VERSION 5.8 ;
BUSBITCHARS "[]" ;
DIVIDERCHAR "/" ;
UNITS
    DATABASE MICRONS 1000 ;
END UNITS

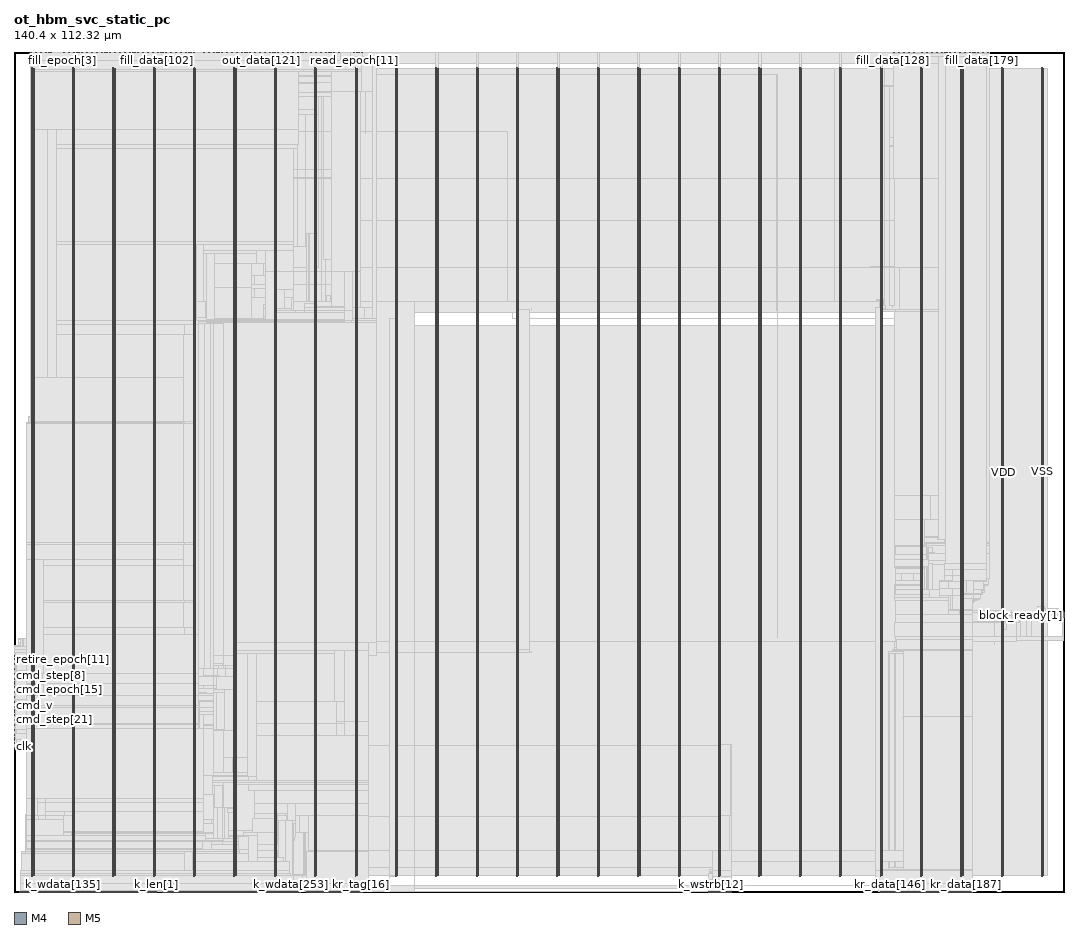
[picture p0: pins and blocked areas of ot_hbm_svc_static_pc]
MACRO ot_hbm_svc_static_pc
  FOREIGN ot_hbm_svc_static_pc 0 0 ;
  CLASS BLOCK ;
  SIZE 140.4 BY 112.32 ;
  PIN bank_owned[0]
    DIRECTION OUTPUT ;
    USE SIGNAL ;
    PORT
      LAYER M4 ;
        RECT  140.316 36.72 140.4 36.744 ;
    END
  END bank_owned[0]
  PIN bank_owned[1]
    DIRECTION OUTPUT ;
    USE SIGNAL ;
    PORT
      LAYER M4 ;
        RECT  140.316 36.816 140.4 36.84 ;
    END
  END bank_owned[1]
  PIN block_ready[0]
    DIRECTION OUTPUT ;
    USE SIGNAL ;
    PORT
      LAYER M4 ;
        RECT  140.316 36.912 140.4 36.936 ;
    END
  END block_ready[0]
  PIN block_ready[1]
    DIRECTION OUTPUT ;
    USE SIGNAL ;
    PORT
      LAYER M4 ;
        RECT  140.316 37.008 140.4 37.032 ;
    END
  END block_ready[1]
  PIN busy
    DIRECTION OUTPUT ;
    USE SIGNAL ;
    PORT
      LAYER M4 ;
        RECT  140.316 37.104 140.4 37.128 ;
    END
  END busy
  PIN clk
    DIRECTION INPUT ;
    USE SIGNAL ;
    PORT
      LAYER M4 ;
        RECT  0 19.44 0.084 19.464 ;
    END
  END clk
  PIN cmd_addr[0]
    DIRECTION INPUT ;
    USE SIGNAL ;
    PORT
      LAYER M4 ;
        RECT  0 19.536 0.084 19.56 ;
    END
  END cmd_addr[0]
  PIN cmd_addr[10]
    DIRECTION INPUT ;
    USE SIGNAL ;
    PORT
      LAYER M4 ;
        RECT  0 20.496 0.084 20.52 ;
    END
  END cmd_addr[10]
  PIN cmd_addr[11]
    DIRECTION INPUT ;
    USE SIGNAL ;
    PORT
      LAYER M4 ;
        RECT  0 20.592 0.084 20.616 ;
    END
  END cmd_addr[11]
  PIN cmd_addr[12]
    DIRECTION INPUT ;
    USE SIGNAL ;
    PORT
      LAYER M4 ;
        RECT  0 20.688 0.084 20.712 ;
    END
  END cmd_addr[12]
  PIN cmd_addr[13]
    DIRECTION INPUT ;
    USE SIGNAL ;
    PORT
      LAYER M4 ;
        RECT  0 20.784 0.084 20.808 ;
    END
  END cmd_addr[13]
  PIN cmd_addr[14]
    DIRECTION INPUT ;
    USE SIGNAL ;
    PORT
      LAYER M4 ;
        RECT  0 20.88 0.084 20.904 ;
    END
  END cmd_addr[14]
  PIN cmd_addr[15]
    DIRECTION INPUT ;
    USE SIGNAL ;
    PORT
      LAYER M4 ;
        RECT  0 20.976 0.084 21 ;
    END
  END cmd_addr[15]
  PIN cmd_addr[16]
    DIRECTION INPUT ;
    USE SIGNAL ;
    PORT
      LAYER M4 ;
        RECT  0 21.072 0.084 21.096 ;
    END
  END cmd_addr[16]
  PIN cmd_addr[17]
    DIRECTION INPUT ;
    USE SIGNAL ;
    PORT
      LAYER M4 ;
        RECT  0 21.168 0.084 21.192 ;
    END
  END cmd_addr[17]
  PIN cmd_addr[18]
    DIRECTION INPUT ;
    USE SIGNAL ;
    PORT
      LAYER M4 ;
        RECT  0 21.264 0.084 21.288 ;
    END
  END cmd_addr[18]
  PIN cmd_addr[19]
    DIRECTION INPUT ;
    USE SIGNAL ;
    PORT
      LAYER M4 ;
        RECT  0 21.36 0.084 21.384 ;
    END
  END cmd_addr[19]
  PIN cmd_addr[1]
    DIRECTION INPUT ;
    USE SIGNAL ;
    PORT
      LAYER M4 ;
        RECT  0 19.632 0.084 19.656 ;
    END
  END cmd_addr[1]
  PIN cmd_addr[20]
    DIRECTION INPUT ;
    USE SIGNAL ;
    PORT
      LAYER M4 ;
        RECT  0 21.456 0.084 21.48 ;
    END
  END cmd_addr[20]
  PIN cmd_addr[21]
    DIRECTION INPUT ;
    USE SIGNAL ;
    PORT
      LAYER M4 ;
        RECT  0 21.552 0.084 21.576 ;
    END
  END cmd_addr[21]
  PIN cmd_addr[22]
    DIRECTION INPUT ;
    USE SIGNAL ;
    PORT
      LAYER M4 ;
        RECT  0 21.648 0.084 21.672 ;
    END
  END cmd_addr[22]
  PIN cmd_addr[23]
    DIRECTION INPUT ;
    USE SIGNAL ;
    PORT
      LAYER M4 ;
        RECT  0 21.744 0.084 21.768 ;
    END
  END cmd_addr[23]
  PIN cmd_addr[24]
    DIRECTION INPUT ;
    USE SIGNAL ;
    PORT
      LAYER M4 ;
        RECT  0 21.84 0.084 21.864 ;
    END
  END cmd_addr[24]
  PIN cmd_addr[25]
    DIRECTION INPUT ;
    USE SIGNAL ;
    PORT
      LAYER M4 ;
        RECT  0 21.936 0.084 21.96 ;
    END
  END cmd_addr[25]
  PIN cmd_addr[26]
    DIRECTION INPUT ;
    USE SIGNAL ;
    PORT
      LAYER M4 ;
        RECT  0 22.032 0.084 22.056 ;
    END
  END cmd_addr[26]
  PIN cmd_addr[27]
    DIRECTION INPUT ;
    USE SIGNAL ;
    PORT
      LAYER M4 ;
        RECT  0 22.128 0.084 22.152 ;
    END
  END cmd_addr[27]
  PIN cmd_addr[28]
    DIRECTION INPUT ;
    USE SIGNAL ;
    PORT
      LAYER M4 ;
        RECT  0 22.224 0.084 22.248 ;
    END
  END cmd_addr[28]
  PIN cmd_addr[29]
    DIRECTION INPUT ;
    USE SIGNAL ;
    PORT
      LAYER M4 ;
        RECT  0 22.32 0.084 22.344 ;
    END
  END cmd_addr[29]
  PIN cmd_addr[2]
    DIRECTION INPUT ;
    USE SIGNAL ;
    PORT
      LAYER M4 ;
        RECT  0 19.728 0.084 19.752 ;
    END
  END cmd_addr[2]
  PIN cmd_addr[3]
    DIRECTION INPUT ;
    USE SIGNAL ;
    PORT
      LAYER M4 ;
        RECT  0 19.824 0.084 19.848 ;
    END
  END cmd_addr[3]
  PIN cmd_addr[4]
    DIRECTION INPUT ;
    USE SIGNAL ;
    PORT
      LAYER M4 ;
        RECT  0 19.92 0.084 19.944 ;
    END
  END cmd_addr[4]
  PIN cmd_addr[5]
    DIRECTION INPUT ;
    USE SIGNAL ;
    PORT
      LAYER M4 ;
        RECT  0 20.016 0.084 20.04 ;
    END
  END cmd_addr[5]
  PIN cmd_addr[6]
    DIRECTION INPUT ;
    USE SIGNAL ;
    PORT
      LAYER M4 ;
        RECT  0 20.112 0.084 20.136 ;
    END
  END cmd_addr[6]
  PIN cmd_addr[7]
    DIRECTION INPUT ;
    USE SIGNAL ;
    PORT
      LAYER M4 ;
        RECT  0 20.208 0.084 20.232 ;
    END
  END cmd_addr[7]
  PIN cmd_addr[8]
    DIRECTION INPUT ;
    USE SIGNAL ;
    PORT
      LAYER M4 ;
        RECT  0 20.304 0.084 20.328 ;
    END
  END cmd_addr[8]
  PIN cmd_addr[9]
    DIRECTION INPUT ;
    USE SIGNAL ;
    PORT
      LAYER M4 ;
        RECT  0 20.4 0.084 20.424 ;
    END
  END cmd_addr[9]
  PIN cmd_bank
    DIRECTION INPUT ;
    USE SIGNAL ;
    PORT
      LAYER M4 ;
        RECT  0 22.416 0.084 22.44 ;
    END
  END cmd_bank
  PIN cmd_epoch[0]
    DIRECTION INPUT ;
    USE SIGNAL ;
    PORT
      LAYER M4 ;
        RECT  0 25.584 0.084 25.608 ;
    END
  END cmd_epoch[0]
  PIN cmd_epoch[10]
    DIRECTION INPUT ;
    USE SIGNAL ;
    PORT
      LAYER M4 ;
        RECT  0 26.544 0.084 26.568 ;
    END
  END cmd_epoch[10]
  PIN cmd_epoch[11]
    DIRECTION INPUT ;
    USE SIGNAL ;
    PORT
      LAYER M4 ;
        RECT  0 26.64 0.084 26.664 ;
    END
  END cmd_epoch[11]
  PIN cmd_epoch[12]
    DIRECTION INPUT ;
    USE SIGNAL ;
    PORT
      LAYER M4 ;
        RECT  0 26.736 0.084 26.76 ;
    END
  END cmd_epoch[12]
  PIN cmd_epoch[13]
    DIRECTION INPUT ;
    USE SIGNAL ;
    PORT
      LAYER M4 ;
        RECT  0 26.832 0.084 26.856 ;
    END
  END cmd_epoch[13]
  PIN cmd_epoch[14]
    DIRECTION INPUT ;
    USE SIGNAL ;
    PORT
      LAYER M4 ;
        RECT  0 26.928 0.084 26.952 ;
    END
  END cmd_epoch[14]
  PIN cmd_epoch[15]
    DIRECTION INPUT ;
    USE SIGNAL ;
    PORT
      LAYER M4 ;
        RECT  0 27.024 0.084 27.048 ;
    END
  END cmd_epoch[15]
  PIN cmd_epoch[1]
    DIRECTION INPUT ;
    USE SIGNAL ;
    PORT
      LAYER M4 ;
        RECT  0 25.68 0.084 25.704 ;
    END
  END cmd_epoch[1]
  PIN cmd_epoch[2]
    DIRECTION INPUT ;
    USE SIGNAL ;
    PORT
      LAYER M4 ;
        RECT  0 25.776 0.084 25.8 ;
    END
  END cmd_epoch[2]
  PIN cmd_epoch[3]
    DIRECTION INPUT ;
    USE SIGNAL ;
    PORT
      LAYER M4 ;
        RECT  0 25.872 0.084 25.896 ;
    END
  END cmd_epoch[3]
  PIN cmd_epoch[4]
    DIRECTION INPUT ;
    USE SIGNAL ;
    PORT
      LAYER M4 ;
        RECT  0 25.968 0.084 25.992 ;
    END
  END cmd_epoch[4]
  PIN cmd_epoch[5]
    DIRECTION INPUT ;
    USE SIGNAL ;
    PORT
      LAYER M4 ;
        RECT  0 26.064 0.084 26.088 ;
    END
  END cmd_epoch[5]
  PIN cmd_epoch[6]
    DIRECTION INPUT ;
    USE SIGNAL ;
    PORT
      LAYER M4 ;
        RECT  0 26.16 0.084 26.184 ;
    END
  END cmd_epoch[6]
  PIN cmd_epoch[7]
    DIRECTION INPUT ;
    USE SIGNAL ;
    PORT
      LAYER M4 ;
        RECT  0 26.256 0.084 26.28 ;
    END
  END cmd_epoch[7]
  PIN cmd_epoch[8]
    DIRECTION INPUT ;
    USE SIGNAL ;
    PORT
      LAYER M4 ;
        RECT  0 26.352 0.084 26.376 ;
    END
  END cmd_epoch[8]
  PIN cmd_epoch[9]
    DIRECTION INPUT ;
    USE SIGNAL ;
    PORT
      LAYER M4 ;
        RECT  0 26.448 0.084 26.472 ;
    END
  END cmd_epoch[9]
  PIN cmd_step[0]
    DIRECTION INPUT ;
    USE SIGNAL ;
    PORT
      LAYER M4 ;
        RECT  0 27.12 0.084 27.144 ;
    END
  END cmd_step[0]
  PIN cmd_step[10]
    DIRECTION INPUT ;
    USE SIGNAL ;
    PORT
      LAYER M4 ;
        RECT  0 28.08 0.084 28.104 ;
    END
  END cmd_step[10]
  PIN cmd_step[11]
    DIRECTION INPUT ;
    USE SIGNAL ;
    PORT
      LAYER M4 ;
        RECT  0 28.176 0.084 28.2 ;
    END
  END cmd_step[11]
  PIN cmd_step[12]
    DIRECTION INPUT ;
    USE SIGNAL ;
    PORT
      LAYER M4 ;
        RECT  0 28.272 0.084 28.296 ;
    END
  END cmd_step[12]
  PIN cmd_step[13]
    DIRECTION INPUT ;
    USE SIGNAL ;
    PORT
      LAYER M4 ;
        RECT  0 28.368 0.084 28.392 ;
    END
  END cmd_step[13]
  PIN cmd_step[14]
    DIRECTION INPUT ;
    USE SIGNAL ;
    PORT
      LAYER M4 ;
        RECT  0 28.464 0.084 28.488 ;
    END
  END cmd_step[14]
  PIN cmd_step[15]
    DIRECTION INPUT ;
    USE SIGNAL ;
    PORT
      LAYER M4 ;
        RECT  0 28.56 0.084 28.584 ;
    END
  END cmd_step[15]
  PIN cmd_step[16]
    DIRECTION INPUT ;
    USE SIGNAL ;
    PORT
      LAYER M4 ;
        RECT  0 22.512 0.084 22.536 ;
    END
  END cmd_step[16]
  PIN cmd_step[17]
    DIRECTION INPUT ;
    USE SIGNAL ;
    PORT
      LAYER M4 ;
        RECT  0 22.608 0.084 22.632 ;
    END
  END cmd_step[17]
  PIN cmd_step[18]
    DIRECTION INPUT ;
    USE SIGNAL ;
    PORT
      LAYER M4 ;
        RECT  0 22.704 0.084 22.728 ;
    END
  END cmd_step[18]
  PIN cmd_step[19]
    DIRECTION INPUT ;
    USE SIGNAL ;
    PORT
      LAYER M4 ;
        RECT  0 22.8 0.084 22.824 ;
    END
  END cmd_step[19]
  PIN cmd_step[1]
    DIRECTION INPUT ;
    USE SIGNAL ;
    PORT
      LAYER M4 ;
        RECT  0 27.216 0.084 27.24 ;
    END
  END cmd_step[1]
  PIN cmd_step[20]
    DIRECTION INPUT ;
    USE SIGNAL ;
    PORT
      LAYER M4 ;
        RECT  0 22.896 0.084 22.92 ;
    END
  END cmd_step[20]
  PIN cmd_step[21]
    DIRECTION INPUT ;
    USE SIGNAL ;
    PORT
      LAYER M4 ;
        RECT  0 22.992 0.084 23.016 ;
    END
  END cmd_step[21]
  PIN cmd_step[22]
    DIRECTION INPUT ;
    USE SIGNAL ;
    PORT
      LAYER M4 ;
        RECT  0 23.088 0.084 23.112 ;
    END
  END cmd_step[22]
  PIN cmd_step[23]
    DIRECTION INPUT ;
    USE SIGNAL ;
    PORT
      LAYER M4 ;
        RECT  0 23.184 0.084 23.208 ;
    END
  END cmd_step[23]
  PIN cmd_step[24]
    DIRECTION INPUT ;
    USE SIGNAL ;
    PORT
      LAYER M4 ;
        RECT  0 23.28 0.084 23.304 ;
    END
  END cmd_step[24]
  PIN cmd_step[25]
    DIRECTION INPUT ;
    USE SIGNAL ;
    PORT
      LAYER M4 ;
        RECT  0 23.376 0.084 23.4 ;
    END
  END cmd_step[25]
  PIN cmd_step[26]
    DIRECTION INPUT ;
    USE SIGNAL ;
    PORT
      LAYER M4 ;
        RECT  0 23.472 0.084 23.496 ;
    END
  END cmd_step[26]
  PIN cmd_step[27]
    DIRECTION INPUT ;
    USE SIGNAL ;
    PORT
      LAYER M4 ;
        RECT  0 23.568 0.084 23.592 ;
    END
  END cmd_step[27]
  PIN cmd_step[28]
    DIRECTION INPUT ;
    USE SIGNAL ;
    PORT
      LAYER M4 ;
        RECT  0 23.664 0.084 23.688 ;
    END
  END cmd_step[28]
  PIN cmd_step[29]
    DIRECTION INPUT ;
    USE SIGNAL ;
    PORT
      LAYER M4 ;
        RECT  0 23.76 0.084 23.784 ;
    END
  END cmd_step[29]
  PIN cmd_step[2]
    DIRECTION INPUT ;
    USE SIGNAL ;
    PORT
      LAYER M4 ;
        RECT  0 27.312 0.084 27.336 ;
    END
  END cmd_step[2]
  PIN cmd_step[3]
    DIRECTION INPUT ;
    USE SIGNAL ;
    PORT
      LAYER M4 ;
        RECT  0 27.408 0.084 27.432 ;
    END
  END cmd_step[3]
  PIN cmd_step[4]
    DIRECTION INPUT ;
    USE SIGNAL ;
    PORT
      LAYER M4 ;
        RECT  0 27.504 0.084 27.528 ;
    END
  END cmd_step[4]
  PIN cmd_step[5]
    DIRECTION INPUT ;
    USE SIGNAL ;
    PORT
      LAYER M4 ;
        RECT  0 27.6 0.084 27.624 ;
    END
  END cmd_step[5]
  PIN cmd_step[6]
    DIRECTION INPUT ;
    USE SIGNAL ;
    PORT
      LAYER M4 ;
        RECT  0 27.696 0.084 27.72 ;
    END
  END cmd_step[6]
  PIN cmd_step[7]
    DIRECTION INPUT ;
    USE SIGNAL ;
    PORT
      LAYER M4 ;
        RECT  0 27.792 0.084 27.816 ;
    END
  END cmd_step[7]
  PIN cmd_step[8]
    DIRECTION INPUT ;
    USE SIGNAL ;
    PORT
      LAYER M4 ;
        RECT  0 27.888 0.084 27.912 ;
    END
  END cmd_step[8]
  PIN cmd_step[9]
    DIRECTION INPUT ;
    USE SIGNAL ;
    PORT
      LAYER M4 ;
        RECT  0 27.984 0.084 28.008 ;
    END
  END cmd_step[9]
  PIN cmd_v
    DIRECTION INPUT ;
    USE SIGNAL ;
    PORT
      LAYER M4 ;
        RECT  0 23.856 0.084 23.88 ;
    END
  END cmd_v
  PIN cmd_write
    DIRECTION INPUT ;
    USE SIGNAL ;
    PORT
      LAYER M4 ;
        RECT  0 23.952 0.084 23.976 ;
    END
  END cmd_write
  PIN done
    DIRECTION OUTPUT ;
    USE SIGNAL ;
    PORT
      LAYER M4 ;
        RECT  140.316 37.2 140.4 37.224 ;
    END
  END done
  PIN fault
    DIRECTION OUTPUT ;
    USE SIGNAL ;
    PORT
      LAYER M4 ;
        RECT  140.316 37.296 140.4 37.32 ;
    END
  END fault
  PIN fill_bank
    DIRECTION INPUT ;
    USE SIGNAL ;
    PORT
      LAYER M5 ;
        RECT  15.312 112.236 15.336 112.32 ;
    END
  END fill_bank
  PIN fill_data[0]
    DIRECTION INPUT ;
    USE SIGNAL ;
    PORT
      LAYER M5 ;
        RECT  15.408 112.236 15.432 112.32 ;
    END
  END fill_data[0]
  PIN fill_data[100]
    DIRECTION INPUT ;
    USE SIGNAL ;
    PORT
      LAYER M5 ;
        RECT  18.864 112.236 18.888 112.32 ;
    END
  END fill_data[100]
  PIN fill_data[101]
    DIRECTION INPUT ;
    USE SIGNAL ;
    PORT
      LAYER M5 ;
        RECT  18.96 112.236 18.984 112.32 ;
    END
  END fill_data[101]
  PIN fill_data[102]
    DIRECTION INPUT ;
    USE SIGNAL ;
    PORT
      LAYER M5 ;
        RECT  19.056 112.236 19.08 112.32 ;
    END
  END fill_data[102]
  PIN fill_data[103]
    DIRECTION INPUT ;
    USE SIGNAL ;
    PORT
      LAYER M5 ;
        RECT  19.152 112.236 19.176 112.32 ;
    END
  END fill_data[103]
  PIN fill_data[104]
    DIRECTION INPUT ;
    USE SIGNAL ;
    PORT
      LAYER M5 ;
        RECT  19.248 112.236 19.272 112.32 ;
    END
  END fill_data[104]
  PIN fill_data[105]
    DIRECTION INPUT ;
    USE SIGNAL ;
    PORT
      LAYER M5 ;
        RECT  19.344 112.236 19.368 112.32 ;
    END
  END fill_data[105]
  PIN fill_data[106]
    DIRECTION INPUT ;
    USE SIGNAL ;
    PORT
      LAYER M5 ;
        RECT  19.44 112.236 19.464 112.32 ;
    END
  END fill_data[106]
  PIN fill_data[107]
    DIRECTION INPUT ;
    USE SIGNAL ;
    PORT
      LAYER M5 ;
        RECT  19.536 112.236 19.56 112.32 ;
    END
  END fill_data[107]
  PIN fill_data[108]
    DIRECTION INPUT ;
    USE SIGNAL ;
    PORT
      LAYER M5 ;
        RECT  19.632 112.236 19.656 112.32 ;
    END
  END fill_data[108]
  PIN fill_data[109]
    DIRECTION INPUT ;
    USE SIGNAL ;
    PORT
      LAYER M5 ;
        RECT  19.728 112.236 19.752 112.32 ;
    END
  END fill_data[109]
  PIN fill_data[10]
    DIRECTION INPUT ;
    USE SIGNAL ;
    PORT
      LAYER M5 ;
        RECT  16.368 112.236 16.392 112.32 ;
    END
  END fill_data[10]
  PIN fill_data[110]
    DIRECTION INPUT ;
    USE SIGNAL ;
    PORT
      LAYER M5 ;
        RECT  19.824 112.236 19.848 112.32 ;
    END
  END fill_data[110]
  PIN fill_data[111]
    DIRECTION INPUT ;
    USE SIGNAL ;
    PORT
      LAYER M5 ;
        RECT  19.92 112.236 19.944 112.32 ;
    END
  END fill_data[111]
  PIN fill_data[112]
    DIRECTION INPUT ;
    USE SIGNAL ;
    PORT
      LAYER M5 ;
        RECT  20.016 112.236 20.04 112.32 ;
    END
  END fill_data[112]
  PIN fill_data[113]
    DIRECTION INPUT ;
    USE SIGNAL ;
    PORT
      LAYER M5 ;
        RECT  20.112 112.236 20.136 112.32 ;
    END
  END fill_data[113]
  PIN fill_data[114]
    DIRECTION INPUT ;
    USE SIGNAL ;
    PORT
      LAYER M5 ;
        RECT  20.208 112.236 20.232 112.32 ;
    END
  END fill_data[114]
  PIN fill_data[115]
    DIRECTION INPUT ;
    USE SIGNAL ;
    PORT
      LAYER M5 ;
        RECT  20.304 112.236 20.328 112.32 ;
    END
  END fill_data[115]
  PIN fill_data[116]
    DIRECTION INPUT ;
    USE SIGNAL ;
    PORT
      LAYER M5 ;
        RECT  20.4 112.236 20.424 112.32 ;
    END
  END fill_data[116]
  PIN fill_data[117]
    DIRECTION INPUT ;
    USE SIGNAL ;
    PORT
      LAYER M5 ;
        RECT  20.496 112.236 20.52 112.32 ;
    END
  END fill_data[117]
  PIN fill_data[118]
    DIRECTION INPUT ;
    USE SIGNAL ;
    PORT
      LAYER M5 ;
        RECT  20.592 112.236 20.616 112.32 ;
    END
  END fill_data[118]
  PIN fill_data[119]
    DIRECTION INPUT ;
    USE SIGNAL ;
    PORT
      LAYER M5 ;
        RECT  20.688 112.236 20.712 112.32 ;
    END
  END fill_data[119]
  PIN fill_data[11]
    DIRECTION INPUT ;
    USE SIGNAL ;
    PORT
      LAYER M5 ;
        RECT  16.464 112.236 16.488 112.32 ;
    END
  END fill_data[11]
  PIN fill_data[120]
    DIRECTION INPUT ;
    USE SIGNAL ;
    PORT
      LAYER M5 ;
        RECT  20.784 112.236 20.808 112.32 ;
    END
  END fill_data[120]
  PIN fill_data[121]
    DIRECTION INPUT ;
    USE SIGNAL ;
    PORT
      LAYER M5 ;
        RECT  20.88 112.236 20.904 112.32 ;
    END
  END fill_data[121]
  PIN fill_data[122]
    DIRECTION INPUT ;
    USE SIGNAL ;
    PORT
      LAYER M5 ;
        RECT  20.976 112.236 21 112.32 ;
    END
  END fill_data[122]
  PIN fill_data[123]
    DIRECTION INPUT ;
    USE SIGNAL ;
    PORT
      LAYER M5 ;
        RECT  21.072 112.236 21.096 112.32 ;
    END
  END fill_data[123]
  PIN fill_data[124]
    DIRECTION INPUT ;
    USE SIGNAL ;
    PORT
      LAYER M5 ;
        RECT  21.168 112.236 21.192 112.32 ;
    END
  END fill_data[124]
  PIN fill_data[125]
    DIRECTION INPUT ;
    USE SIGNAL ;
    PORT
      LAYER M5 ;
        RECT  21.264 112.236 21.288 112.32 ;
    END
  END fill_data[125]
  PIN fill_data[126]
    DIRECTION INPUT ;
    USE SIGNAL ;
    PORT
      LAYER M5 ;
        RECT  21.36 112.236 21.384 112.32 ;
    END
  END fill_data[126]
  PIN fill_data[127]
    DIRECTION INPUT ;
    USE SIGNAL ;
    PORT
      LAYER M5 ;
        RECT  117.456 112.236 117.48 112.32 ;
    END
  END fill_data[127]
  PIN fill_data[128]
    DIRECTION INPUT ;
    USE SIGNAL ;
    PORT
      LAYER M5 ;
        RECT  117.552 112.236 117.576 112.32 ;
    END
  END fill_data[128]
  PIN fill_data[129]
    DIRECTION INPUT ;
    USE SIGNAL ;
    PORT
      LAYER M5 ;
        RECT  117.648 112.236 117.672 112.32 ;
    END
  END fill_data[129]
  PIN fill_data[12]
    DIRECTION INPUT ;
    USE SIGNAL ;
    PORT
      LAYER M5 ;
        RECT  16.56 112.236 16.584 112.32 ;
    END
  END fill_data[12]
  PIN fill_data[130]
    DIRECTION INPUT ;
    USE SIGNAL ;
    PORT
      LAYER M5 ;
        RECT  117.744 112.236 117.768 112.32 ;
    END
  END fill_data[130]
  PIN fill_data[131]
    DIRECTION INPUT ;
    USE SIGNAL ;
    PORT
      LAYER M5 ;
        RECT  117.84 112.236 117.864 112.32 ;
    END
  END fill_data[131]
  PIN fill_data[132]
    DIRECTION INPUT ;
    USE SIGNAL ;
    PORT
      LAYER M5 ;
        RECT  117.936 112.236 117.96 112.32 ;
    END
  END fill_data[132]
  PIN fill_data[133]
    DIRECTION INPUT ;
    USE SIGNAL ;
    PORT
      LAYER M5 ;
        RECT  118.032 112.236 118.056 112.32 ;
    END
  END fill_data[133]
  PIN fill_data[134]
    DIRECTION INPUT ;
    USE SIGNAL ;
    PORT
      LAYER M5 ;
        RECT  118.128 112.236 118.152 112.32 ;
    END
  END fill_data[134]
  PIN fill_data[135]
    DIRECTION INPUT ;
    USE SIGNAL ;
    PORT
      LAYER M5 ;
        RECT  118.224 112.236 118.248 112.32 ;
    END
  END fill_data[135]
  PIN fill_data[136]
    DIRECTION INPUT ;
    USE SIGNAL ;
    PORT
      LAYER M5 ;
        RECT  118.32 112.236 118.344 112.32 ;
    END
  END fill_data[136]
  PIN fill_data[137]
    DIRECTION INPUT ;
    USE SIGNAL ;
    PORT
      LAYER M5 ;
        RECT  118.416 112.236 118.44 112.32 ;
    END
  END fill_data[137]
  PIN fill_data[138]
    DIRECTION INPUT ;
    USE SIGNAL ;
    PORT
      LAYER M5 ;
        RECT  118.512 112.236 118.536 112.32 ;
    END
  END fill_data[138]
  PIN fill_data[139]
    DIRECTION INPUT ;
    USE SIGNAL ;
    PORT
      LAYER M5 ;
        RECT  118.608 112.236 118.632 112.32 ;
    END
  END fill_data[139]
  PIN fill_data[13]
    DIRECTION INPUT ;
    USE SIGNAL ;
    PORT
      LAYER M5 ;
        RECT  16.656 112.236 16.68 112.32 ;
    END
  END fill_data[13]
  PIN fill_data[140]
    DIRECTION INPUT ;
    USE SIGNAL ;
    PORT
      LAYER M5 ;
        RECT  118.704 112.236 118.728 112.32 ;
    END
  END fill_data[140]
  PIN fill_data[141]
    DIRECTION INPUT ;
    USE SIGNAL ;
    PORT
      LAYER M5 ;
        RECT  118.8 112.236 118.824 112.32 ;
    END
  END fill_data[141]
  PIN fill_data[142]
    DIRECTION INPUT ;
    USE SIGNAL ;
    PORT
      LAYER M5 ;
        RECT  118.896 112.236 118.92 112.32 ;
    END
  END fill_data[142]
  PIN fill_data[143]
    DIRECTION INPUT ;
    USE SIGNAL ;
    PORT
      LAYER M5 ;
        RECT  118.992 112.236 119.016 112.32 ;
    END
  END fill_data[143]
  PIN fill_data[144]
    DIRECTION INPUT ;
    USE SIGNAL ;
    PORT
      LAYER M5 ;
        RECT  119.088 112.236 119.112 112.32 ;
    END
  END fill_data[144]
  PIN fill_data[145]
    DIRECTION INPUT ;
    USE SIGNAL ;
    PORT
      LAYER M5 ;
        RECT  119.184 112.236 119.208 112.32 ;
    END
  END fill_data[145]
  PIN fill_data[146]
    DIRECTION INPUT ;
    USE SIGNAL ;
    PORT
      LAYER M5 ;
        RECT  119.28 112.236 119.304 112.32 ;
    END
  END fill_data[146]
  PIN fill_data[147]
    DIRECTION INPUT ;
    USE SIGNAL ;
    PORT
      LAYER M5 ;
        RECT  119.376 112.236 119.4 112.32 ;
    END
  END fill_data[147]
  PIN fill_data[148]
    DIRECTION INPUT ;
    USE SIGNAL ;
    PORT
      LAYER M5 ;
        RECT  119.472 112.236 119.496 112.32 ;
    END
  END fill_data[148]
  PIN fill_data[149]
    DIRECTION INPUT ;
    USE SIGNAL ;
    PORT
      LAYER M5 ;
        RECT  119.568 112.236 119.592 112.32 ;
    END
  END fill_data[149]
  PIN fill_data[14]
    DIRECTION INPUT ;
    USE SIGNAL ;
    PORT
      LAYER M5 ;
        RECT  16.752 112.236 16.776 112.32 ;
    END
  END fill_data[14]
  PIN fill_data[150]
    DIRECTION INPUT ;
    USE SIGNAL ;
    PORT
      LAYER M5 ;
        RECT  119.664 112.236 119.688 112.32 ;
    END
  END fill_data[150]
  PIN fill_data[151]
    DIRECTION INPUT ;
    USE SIGNAL ;
    PORT
      LAYER M5 ;
        RECT  119.76 112.236 119.784 112.32 ;
    END
  END fill_data[151]
  PIN fill_data[152]
    DIRECTION INPUT ;
    USE SIGNAL ;
    PORT
      LAYER M5 ;
        RECT  119.856 112.236 119.88 112.32 ;
    END
  END fill_data[152]
  PIN fill_data[153]
    DIRECTION INPUT ;
    USE SIGNAL ;
    PORT
      LAYER M5 ;
        RECT  119.952 112.236 119.976 112.32 ;
    END
  END fill_data[153]
  PIN fill_data[154]
    DIRECTION INPUT ;
    USE SIGNAL ;
    PORT
      LAYER M5 ;
        RECT  120.048 112.236 120.072 112.32 ;
    END
  END fill_data[154]
  PIN fill_data[155]
    DIRECTION INPUT ;
    USE SIGNAL ;
    PORT
      LAYER M5 ;
        RECT  120.144 112.236 120.168 112.32 ;
    END
  END fill_data[155]
  PIN fill_data[156]
    DIRECTION INPUT ;
    USE SIGNAL ;
    PORT
      LAYER M5 ;
        RECT  120.24 112.236 120.264 112.32 ;
    END
  END fill_data[156]
  PIN fill_data[157]
    DIRECTION INPUT ;
    USE SIGNAL ;
    PORT
      LAYER M5 ;
        RECT  120.336 112.236 120.36 112.32 ;
    END
  END fill_data[157]
  PIN fill_data[158]
    DIRECTION INPUT ;
    USE SIGNAL ;
    PORT
      LAYER M5 ;
        RECT  120.432 112.236 120.456 112.32 ;
    END
  END fill_data[158]
  PIN fill_data[159]
    DIRECTION INPUT ;
    USE SIGNAL ;
    PORT
      LAYER M5 ;
        RECT  127.44 112.236 127.464 112.32 ;
    END
  END fill_data[159]
  PIN fill_data[15]
    DIRECTION INPUT ;
    USE SIGNAL ;
    PORT
      LAYER M5 ;
        RECT  16.848 112.236 16.872 112.32 ;
    END
  END fill_data[15]
  PIN fill_data[160]
    DIRECTION INPUT ;
    USE SIGNAL ;
    PORT
      LAYER M5 ;
        RECT  127.536 112.236 127.56 112.32 ;
    END
  END fill_data[160]
  PIN fill_data[161]
    DIRECTION INPUT ;
    USE SIGNAL ;
    PORT
      LAYER M5 ;
        RECT  127.632 112.236 127.656 112.32 ;
    END
  END fill_data[161]
  PIN fill_data[162]
    DIRECTION INPUT ;
    USE SIGNAL ;
    PORT
      LAYER M5 ;
        RECT  127.728 112.236 127.752 112.32 ;
    END
  END fill_data[162]
  PIN fill_data[163]
    DIRECTION INPUT ;
    USE SIGNAL ;
    PORT
      LAYER M5 ;
        RECT  127.824 112.236 127.848 112.32 ;
    END
  END fill_data[163]
  PIN fill_data[164]
    DIRECTION INPUT ;
    USE SIGNAL ;
    PORT
      LAYER M5 ;
        RECT  127.92 112.236 127.944 112.32 ;
    END
  END fill_data[164]
  PIN fill_data[165]
    DIRECTION INPUT ;
    USE SIGNAL ;
    PORT
      LAYER M5 ;
        RECT  128.016 112.236 128.04 112.32 ;
    END
  END fill_data[165]
  PIN fill_data[166]
    DIRECTION INPUT ;
    USE SIGNAL ;
    PORT
      LAYER M5 ;
        RECT  128.112 112.236 128.136 112.32 ;
    END
  END fill_data[166]
  PIN fill_data[167]
    DIRECTION INPUT ;
    USE SIGNAL ;
    PORT
      LAYER M5 ;
        RECT  128.208 112.236 128.232 112.32 ;
    END
  END fill_data[167]
  PIN fill_data[168]
    DIRECTION INPUT ;
    USE SIGNAL ;
    PORT
      LAYER M5 ;
        RECT  128.304 112.236 128.328 112.32 ;
    END
  END fill_data[168]
  PIN fill_data[169]
    DIRECTION INPUT ;
    USE SIGNAL ;
    PORT
      LAYER M5 ;
        RECT  128.4 112.236 128.424 112.32 ;
    END
  END fill_data[169]
  PIN fill_data[16]
    DIRECTION INPUT ;
    USE SIGNAL ;
    PORT
      LAYER M5 ;
        RECT  16.944 112.236 16.968 112.32 ;
    END
  END fill_data[16]
  PIN fill_data[170]
    DIRECTION INPUT ;
    USE SIGNAL ;
    PORT
      LAYER M5 ;
        RECT  128.496 112.236 128.52 112.32 ;
    END
  END fill_data[170]
  PIN fill_data[171]
    DIRECTION INPUT ;
    USE SIGNAL ;
    PORT
      LAYER M5 ;
        RECT  128.592 112.236 128.616 112.32 ;
    END
  END fill_data[171]
  PIN fill_data[172]
    DIRECTION INPUT ;
    USE SIGNAL ;
    PORT
      LAYER M5 ;
        RECT  128.688 112.236 128.712 112.32 ;
    END
  END fill_data[172]
  PIN fill_data[173]
    DIRECTION INPUT ;
    USE SIGNAL ;
    PORT
      LAYER M5 ;
        RECT  128.784 112.236 128.808 112.32 ;
    END
  END fill_data[173]
  PIN fill_data[174]
    DIRECTION INPUT ;
    USE SIGNAL ;
    PORT
      LAYER M5 ;
        RECT  128.88 112.236 128.904 112.32 ;
    END
  END fill_data[174]
  PIN fill_data[175]
    DIRECTION INPUT ;
    USE SIGNAL ;
    PORT
      LAYER M5 ;
        RECT  128.976 112.236 129 112.32 ;
    END
  END fill_data[175]
  PIN fill_data[176]
    DIRECTION INPUT ;
    USE SIGNAL ;
    PORT
      LAYER M5 ;
        RECT  129.072 112.236 129.096 112.32 ;
    END
  END fill_data[176]
  PIN fill_data[177]
    DIRECTION INPUT ;
    USE SIGNAL ;
    PORT
      LAYER M5 ;
        RECT  129.168 112.236 129.192 112.32 ;
    END
  END fill_data[177]
  PIN fill_data[178]
    DIRECTION INPUT ;
    USE SIGNAL ;
    PORT
      LAYER M5 ;
        RECT  129.264 112.236 129.288 112.32 ;
    END
  END fill_data[178]
  PIN fill_data[179]
    DIRECTION INPUT ;
    USE SIGNAL ;
    PORT
      LAYER M5 ;
        RECT  129.36 112.236 129.384 112.32 ;
    END
  END fill_data[179]
  PIN fill_data[17]
    DIRECTION INPUT ;
    USE SIGNAL ;
    PORT
      LAYER M5 ;
        RECT  17.04 112.236 17.064 112.32 ;
    END
  END fill_data[17]
  PIN fill_data[180]
    DIRECTION INPUT ;
    USE SIGNAL ;
    PORT
      LAYER M5 ;
        RECT  129.456 112.236 129.48 112.32 ;
    END
  END fill_data[180]
  PIN fill_data[181]
    DIRECTION INPUT ;
    USE SIGNAL ;
    PORT
      LAYER M5 ;
        RECT  129.552 112.236 129.576 112.32 ;
    END
  END fill_data[181]
  PIN fill_data[182]
    DIRECTION INPUT ;
    USE SIGNAL ;
    PORT
      LAYER M5 ;
        RECT  129.648 112.236 129.672 112.32 ;
    END
  END fill_data[182]
  PIN fill_data[183]
    DIRECTION INPUT ;
    USE SIGNAL ;
    PORT
      LAYER M5 ;
        RECT  129.744 112.236 129.768 112.32 ;
    END
  END fill_data[183]
  PIN fill_data[184]
    DIRECTION INPUT ;
    USE SIGNAL ;
    PORT
      LAYER M5 ;
        RECT  129.84 112.236 129.864 112.32 ;
    END
  END fill_data[184]
  PIN fill_data[185]
    DIRECTION INPUT ;
    USE SIGNAL ;
    PORT
      LAYER M5 ;
        RECT  129.936 112.236 129.96 112.32 ;
    END
  END fill_data[185]
  PIN fill_data[186]
    DIRECTION INPUT ;
    USE SIGNAL ;
    PORT
      LAYER M5 ;
        RECT  130.032 112.236 130.056 112.32 ;
    END
  END fill_data[186]
  PIN fill_data[187]
    DIRECTION INPUT ;
    USE SIGNAL ;
    PORT
      LAYER M5 ;
        RECT  130.128 112.236 130.152 112.32 ;
    END
  END fill_data[187]
  PIN fill_data[188]
    DIRECTION INPUT ;
    USE SIGNAL ;
    PORT
      LAYER M5 ;
        RECT  130.224 112.236 130.248 112.32 ;
    END
  END fill_data[188]
  PIN fill_data[189]
    DIRECTION INPUT ;
    USE SIGNAL ;
    PORT
      LAYER M5 ;
        RECT  130.32 112.236 130.344 112.32 ;
    END
  END fill_data[189]
  PIN fill_data[18]
    DIRECTION INPUT ;
    USE SIGNAL ;
    PORT
      LAYER M5 ;
        RECT  17.136 112.236 17.16 112.32 ;
    END
  END fill_data[18]
  PIN fill_data[190]
    DIRECTION INPUT ;
    USE SIGNAL ;
    PORT
      LAYER M5 ;
        RECT  130.416 112.236 130.44 112.32 ;
    END
  END fill_data[190]
  PIN fill_data[191]
    DIRECTION INPUT ;
    USE SIGNAL ;
    PORT
      LAYER M5 ;
        RECT  124.368 112.236 124.392 112.32 ;
    END
  END fill_data[191]
  PIN fill_data[192]
    DIRECTION INPUT ;
    USE SIGNAL ;
    PORT
      LAYER M5 ;
        RECT  124.464 112.236 124.488 112.32 ;
    END
  END fill_data[192]
  PIN fill_data[193]
    DIRECTION INPUT ;
    USE SIGNAL ;
    PORT
      LAYER M5 ;
        RECT  124.56 112.236 124.584 112.32 ;
    END
  END fill_data[193]
  PIN fill_data[194]
    DIRECTION INPUT ;
    USE SIGNAL ;
    PORT
      LAYER M5 ;
        RECT  124.656 112.236 124.68 112.32 ;
    END
  END fill_data[194]
  PIN fill_data[195]
    DIRECTION INPUT ;
    USE SIGNAL ;
    PORT
      LAYER M5 ;
        RECT  124.752 112.236 124.776 112.32 ;
    END
  END fill_data[195]
  PIN fill_data[196]
    DIRECTION INPUT ;
    USE SIGNAL ;
    PORT
      LAYER M5 ;
        RECT  124.848 112.236 124.872 112.32 ;
    END
  END fill_data[196]
  PIN fill_data[197]
    DIRECTION INPUT ;
    USE SIGNAL ;
    PORT
      LAYER M5 ;
        RECT  124.944 112.236 124.968 112.32 ;
    END
  END fill_data[197]
  PIN fill_data[198]
    DIRECTION INPUT ;
    USE SIGNAL ;
    PORT
      LAYER M5 ;
        RECT  125.04 112.236 125.064 112.32 ;
    END
  END fill_data[198]
  PIN fill_data[199]
    DIRECTION INPUT ;
    USE SIGNAL ;
    PORT
      LAYER M5 ;
        RECT  125.136 112.236 125.16 112.32 ;
    END
  END fill_data[199]
  PIN fill_data[19]
    DIRECTION INPUT ;
    USE SIGNAL ;
    PORT
      LAYER M5 ;
        RECT  17.232 112.236 17.256 112.32 ;
    END
  END fill_data[19]
  PIN fill_data[1]
    DIRECTION INPUT ;
    USE SIGNAL ;
    PORT
      LAYER M5 ;
        RECT  15.504 112.236 15.528 112.32 ;
    END
  END fill_data[1]
  PIN fill_data[200]
    DIRECTION INPUT ;
    USE SIGNAL ;
    PORT
      LAYER M5 ;
        RECT  125.232 112.236 125.256 112.32 ;
    END
  END fill_data[200]
  PIN fill_data[201]
    DIRECTION INPUT ;
    USE SIGNAL ;
    PORT
      LAYER M5 ;
        RECT  125.328 112.236 125.352 112.32 ;
    END
  END fill_data[201]
  PIN fill_data[202]
    DIRECTION INPUT ;
    USE SIGNAL ;
    PORT
      LAYER M5 ;
        RECT  125.424 112.236 125.448 112.32 ;
    END
  END fill_data[202]
  PIN fill_data[203]
    DIRECTION INPUT ;
    USE SIGNAL ;
    PORT
      LAYER M5 ;
        RECT  125.52 112.236 125.544 112.32 ;
    END
  END fill_data[203]
  PIN fill_data[204]
    DIRECTION INPUT ;
    USE SIGNAL ;
    PORT
      LAYER M5 ;
        RECT  125.616 112.236 125.64 112.32 ;
    END
  END fill_data[204]
  PIN fill_data[205]
    DIRECTION INPUT ;
    USE SIGNAL ;
    PORT
      LAYER M5 ;
        RECT  125.712 112.236 125.736 112.32 ;
    END
  END fill_data[205]
  PIN fill_data[206]
    DIRECTION INPUT ;
    USE SIGNAL ;
    PORT
      LAYER M5 ;
        RECT  125.808 112.236 125.832 112.32 ;
    END
  END fill_data[206]
  PIN fill_data[207]
    DIRECTION INPUT ;
    USE SIGNAL ;
    PORT
      LAYER M5 ;
        RECT  125.904 112.236 125.928 112.32 ;
    END
  END fill_data[207]
  PIN fill_data[208]
    DIRECTION INPUT ;
    USE SIGNAL ;
    PORT
      LAYER M5 ;
        RECT  126 112.236 126.024 112.32 ;
    END
  END fill_data[208]
  PIN fill_data[209]
    DIRECTION INPUT ;
    USE SIGNAL ;
    PORT
      LAYER M5 ;
        RECT  126.096 112.236 126.12 112.32 ;
    END
  END fill_data[209]
  PIN fill_data[20]
    DIRECTION INPUT ;
    USE SIGNAL ;
    PORT
      LAYER M5 ;
        RECT  17.328 112.236 17.352 112.32 ;
    END
  END fill_data[20]
  PIN fill_data[210]
    DIRECTION INPUT ;
    USE SIGNAL ;
    PORT
      LAYER M5 ;
        RECT  126.192 112.236 126.216 112.32 ;
    END
  END fill_data[210]
  PIN fill_data[211]
    DIRECTION INPUT ;
    USE SIGNAL ;
    PORT
      LAYER M5 ;
        RECT  126.288 112.236 126.312 112.32 ;
    END
  END fill_data[211]
  PIN fill_data[212]
    DIRECTION INPUT ;
    USE SIGNAL ;
    PORT
      LAYER M5 ;
        RECT  126.384 112.236 126.408 112.32 ;
    END
  END fill_data[212]
  PIN fill_data[213]
    DIRECTION INPUT ;
    USE SIGNAL ;
    PORT
      LAYER M5 ;
        RECT  126.48 112.236 126.504 112.32 ;
    END
  END fill_data[213]
  PIN fill_data[214]
    DIRECTION INPUT ;
    USE SIGNAL ;
    PORT
      LAYER M5 ;
        RECT  126.576 112.236 126.6 112.32 ;
    END
  END fill_data[214]
  PIN fill_data[215]
    DIRECTION INPUT ;
    USE SIGNAL ;
    PORT
      LAYER M5 ;
        RECT  126.672 112.236 126.696 112.32 ;
    END
  END fill_data[215]
  PIN fill_data[216]
    DIRECTION INPUT ;
    USE SIGNAL ;
    PORT
      LAYER M5 ;
        RECT  126.768 112.236 126.792 112.32 ;
    END
  END fill_data[216]
  PIN fill_data[217]
    DIRECTION INPUT ;
    USE SIGNAL ;
    PORT
      LAYER M5 ;
        RECT  126.864 112.236 126.888 112.32 ;
    END
  END fill_data[217]
  PIN fill_data[218]
    DIRECTION INPUT ;
    USE SIGNAL ;
    PORT
      LAYER M5 ;
        RECT  126.96 112.236 126.984 112.32 ;
    END
  END fill_data[218]
  PIN fill_data[219]
    DIRECTION INPUT ;
    USE SIGNAL ;
    PORT
      LAYER M5 ;
        RECT  127.056 112.236 127.08 112.32 ;
    END
  END fill_data[219]
  PIN fill_data[21]
    DIRECTION INPUT ;
    USE SIGNAL ;
    PORT
      LAYER M5 ;
        RECT  17.424 112.236 17.448 112.32 ;
    END
  END fill_data[21]
  PIN fill_data[220]
    DIRECTION INPUT ;
    USE SIGNAL ;
    PORT
      LAYER M5 ;
        RECT  127.152 112.236 127.176 112.32 ;
    END
  END fill_data[220]
  PIN fill_data[221]
    DIRECTION INPUT ;
    USE SIGNAL ;
    PORT
      LAYER M5 ;
        RECT  127.248 112.236 127.272 112.32 ;
    END
  END fill_data[221]
  PIN fill_data[222]
    DIRECTION INPUT ;
    USE SIGNAL ;
    PORT
      LAYER M5 ;
        RECT  127.344 112.236 127.368 112.32 ;
    END
  END fill_data[222]
  PIN fill_data[223]
    DIRECTION INPUT ;
    USE SIGNAL ;
    PORT
      LAYER M5 ;
        RECT  121.296 112.236 121.32 112.32 ;
    END
  END fill_data[223]
  PIN fill_data[224]
    DIRECTION INPUT ;
    USE SIGNAL ;
    PORT
      LAYER M5 ;
        RECT  121.392 112.236 121.416 112.32 ;
    END
  END fill_data[224]
  PIN fill_data[225]
    DIRECTION INPUT ;
    USE SIGNAL ;
    PORT
      LAYER M5 ;
        RECT  121.488 112.236 121.512 112.32 ;
    END
  END fill_data[225]
  PIN fill_data[226]
    DIRECTION INPUT ;
    USE SIGNAL ;
    PORT
      LAYER M5 ;
        RECT  121.584 112.236 121.608 112.32 ;
    END
  END fill_data[226]
  PIN fill_data[227]
    DIRECTION INPUT ;
    USE SIGNAL ;
    PORT
      LAYER M5 ;
        RECT  121.68 112.236 121.704 112.32 ;
    END
  END fill_data[227]
  PIN fill_data[228]
    DIRECTION INPUT ;
    USE SIGNAL ;
    PORT
      LAYER M5 ;
        RECT  121.776 112.236 121.8 112.32 ;
    END
  END fill_data[228]
  PIN fill_data[229]
    DIRECTION INPUT ;
    USE SIGNAL ;
    PORT
      LAYER M5 ;
        RECT  121.872 112.236 121.896 112.32 ;
    END
  END fill_data[229]
  PIN fill_data[22]
    DIRECTION INPUT ;
    USE SIGNAL ;
    PORT
      LAYER M5 ;
        RECT  17.52 112.236 17.544 112.32 ;
    END
  END fill_data[22]
  PIN fill_data[230]
    DIRECTION INPUT ;
    USE SIGNAL ;
    PORT
      LAYER M5 ;
        RECT  121.968 112.236 121.992 112.32 ;
    END
  END fill_data[230]
  PIN fill_data[231]
    DIRECTION INPUT ;
    USE SIGNAL ;
    PORT
      LAYER M5 ;
        RECT  122.064 112.236 122.088 112.32 ;
    END
  END fill_data[231]
  PIN fill_data[232]
    DIRECTION INPUT ;
    USE SIGNAL ;
    PORT
      LAYER M5 ;
        RECT  122.16 112.236 122.184 112.32 ;
    END
  END fill_data[232]
  PIN fill_data[233]
    DIRECTION INPUT ;
    USE SIGNAL ;
    PORT
      LAYER M5 ;
        RECT  122.256 112.236 122.28 112.32 ;
    END
  END fill_data[233]
  PIN fill_data[234]
    DIRECTION INPUT ;
    USE SIGNAL ;
    PORT
      LAYER M5 ;
        RECT  122.352 112.236 122.376 112.32 ;
    END
  END fill_data[234]
  PIN fill_data[235]
    DIRECTION INPUT ;
    USE SIGNAL ;
    PORT
      LAYER M5 ;
        RECT  122.448 112.236 122.472 112.32 ;
    END
  END fill_data[235]
  PIN fill_data[236]
    DIRECTION INPUT ;
    USE SIGNAL ;
    PORT
      LAYER M5 ;
        RECT  122.544 112.236 122.568 112.32 ;
    END
  END fill_data[236]
  PIN fill_data[237]
    DIRECTION INPUT ;
    USE SIGNAL ;
    PORT
      LAYER M5 ;
        RECT  122.64 112.236 122.664 112.32 ;
    END
  END fill_data[237]
  PIN fill_data[238]
    DIRECTION INPUT ;
    USE SIGNAL ;
    PORT
      LAYER M5 ;
        RECT  122.736 112.236 122.76 112.32 ;
    END
  END fill_data[238]
  PIN fill_data[239]
    DIRECTION INPUT ;
    USE SIGNAL ;
    PORT
      LAYER M5 ;
        RECT  122.832 112.236 122.856 112.32 ;
    END
  END fill_data[239]
  PIN fill_data[23]
    DIRECTION INPUT ;
    USE SIGNAL ;
    PORT
      LAYER M5 ;
        RECT  17.616 112.236 17.64 112.32 ;
    END
  END fill_data[23]
  PIN fill_data[240]
    DIRECTION INPUT ;
    USE SIGNAL ;
    PORT
      LAYER M5 ;
        RECT  122.928 112.236 122.952 112.32 ;
    END
  END fill_data[240]
  PIN fill_data[241]
    DIRECTION INPUT ;
    USE SIGNAL ;
    PORT
      LAYER M5 ;
        RECT  123.024 112.236 123.048 112.32 ;
    END
  END fill_data[241]
  PIN fill_data[242]
    DIRECTION INPUT ;
    USE SIGNAL ;
    PORT
      LAYER M5 ;
        RECT  123.12 112.236 123.144 112.32 ;
    END
  END fill_data[242]
  PIN fill_data[243]
    DIRECTION INPUT ;
    USE SIGNAL ;
    PORT
      LAYER M5 ;
        RECT  123.216 112.236 123.24 112.32 ;
    END
  END fill_data[243]
  PIN fill_data[244]
    DIRECTION INPUT ;
    USE SIGNAL ;
    PORT
      LAYER M5 ;
        RECT  123.312 112.236 123.336 112.32 ;
    END
  END fill_data[244]
  PIN fill_data[245]
    DIRECTION INPUT ;
    USE SIGNAL ;
    PORT
      LAYER M5 ;
        RECT  123.408 112.236 123.432 112.32 ;
    END
  END fill_data[245]
  PIN fill_data[246]
    DIRECTION INPUT ;
    USE SIGNAL ;
    PORT
      LAYER M5 ;
        RECT  123.504 112.236 123.528 112.32 ;
    END
  END fill_data[246]
  PIN fill_data[247]
    DIRECTION INPUT ;
    USE SIGNAL ;
    PORT
      LAYER M5 ;
        RECT  123.6 112.236 123.624 112.32 ;
    END
  END fill_data[247]
  PIN fill_data[248]
    DIRECTION INPUT ;
    USE SIGNAL ;
    PORT
      LAYER M5 ;
        RECT  123.696 112.236 123.72 112.32 ;
    END
  END fill_data[248]
  PIN fill_data[249]
    DIRECTION INPUT ;
    USE SIGNAL ;
    PORT
      LAYER M5 ;
        RECT  123.792 112.236 123.816 112.32 ;
    END
  END fill_data[249]
  PIN fill_data[24]
    DIRECTION INPUT ;
    USE SIGNAL ;
    PORT
      LAYER M5 ;
        RECT  17.712 112.236 17.736 112.32 ;
    END
  END fill_data[24]
  PIN fill_data[250]
    DIRECTION INPUT ;
    USE SIGNAL ;
    PORT
      LAYER M5 ;
        RECT  123.888 112.236 123.912 112.32 ;
    END
  END fill_data[250]
  PIN fill_data[251]
    DIRECTION INPUT ;
    USE SIGNAL ;
    PORT
      LAYER M5 ;
        RECT  123.984 112.236 124.008 112.32 ;
    END
  END fill_data[251]
  PIN fill_data[252]
    DIRECTION INPUT ;
    USE SIGNAL ;
    PORT
      LAYER M5 ;
        RECT  124.08 112.236 124.104 112.32 ;
    END
  END fill_data[252]
  PIN fill_data[253]
    DIRECTION INPUT ;
    USE SIGNAL ;
    PORT
      LAYER M5 ;
        RECT  124.176 112.236 124.2 112.32 ;
    END
  END fill_data[253]
  PIN fill_data[254]
    DIRECTION INPUT ;
    USE SIGNAL ;
    PORT
      LAYER M5 ;
        RECT  124.272 112.236 124.296 112.32 ;
    END
  END fill_data[254]
  PIN fill_data[255]
    DIRECTION INPUT ;
    USE SIGNAL ;
    PORT
      LAYER M5 ;
        RECT  6.096 112.236 6.12 112.32 ;
    END
  END fill_data[255]
  PIN fill_data[25]
    DIRECTION INPUT ;
    USE SIGNAL ;
    PORT
      LAYER M5 ;
        RECT  17.808 112.236 17.832 112.32 ;
    END
  END fill_data[25]
  PIN fill_data[26]
    DIRECTION INPUT ;
    USE SIGNAL ;
    PORT
      LAYER M5 ;
        RECT  17.904 112.236 17.928 112.32 ;
    END
  END fill_data[26]
  PIN fill_data[27]
    DIRECTION INPUT ;
    USE SIGNAL ;
    PORT
      LAYER M5 ;
        RECT  18 112.236 18.024 112.32 ;
    END
  END fill_data[27]
  PIN fill_data[28]
    DIRECTION INPUT ;
    USE SIGNAL ;
    PORT
      LAYER M5 ;
        RECT  18.096 112.236 18.12 112.32 ;
    END
  END fill_data[28]
  PIN fill_data[29]
    DIRECTION INPUT ;
    USE SIGNAL ;
    PORT
      LAYER M5 ;
        RECT  18.192 112.236 18.216 112.32 ;
    END
  END fill_data[29]
  PIN fill_data[2]
    DIRECTION INPUT ;
    USE SIGNAL ;
    PORT
      LAYER M5 ;
        RECT  15.6 112.236 15.624 112.32 ;
    END
  END fill_data[2]
  PIN fill_data[30]
    DIRECTION INPUT ;
    USE SIGNAL ;
    PORT
      LAYER M5 ;
        RECT  18.288 112.236 18.312 112.32 ;
    END
  END fill_data[30]
  PIN fill_data[31]
    DIRECTION INPUT ;
    USE SIGNAL ;
    PORT
      LAYER M5 ;
        RECT  12.24 112.236 12.264 112.32 ;
    END
  END fill_data[31]
  PIN fill_data[32]
    DIRECTION INPUT ;
    USE SIGNAL ;
    PORT
      LAYER M5 ;
        RECT  12.336 112.236 12.36 112.32 ;
    END
  END fill_data[32]
  PIN fill_data[33]
    DIRECTION INPUT ;
    USE SIGNAL ;
    PORT
      LAYER M5 ;
        RECT  12.432 112.236 12.456 112.32 ;
    END
  END fill_data[33]
  PIN fill_data[34]
    DIRECTION INPUT ;
    USE SIGNAL ;
    PORT
      LAYER M5 ;
        RECT  12.528 112.236 12.552 112.32 ;
    END
  END fill_data[34]
  PIN fill_data[35]
    DIRECTION INPUT ;
    USE SIGNAL ;
    PORT
      LAYER M5 ;
        RECT  12.624 112.236 12.648 112.32 ;
    END
  END fill_data[35]
  PIN fill_data[36]
    DIRECTION INPUT ;
    USE SIGNAL ;
    PORT
      LAYER M5 ;
        RECT  12.72 112.236 12.744 112.32 ;
    END
  END fill_data[36]
  PIN fill_data[37]
    DIRECTION INPUT ;
    USE SIGNAL ;
    PORT
      LAYER M5 ;
        RECT  12.816 112.236 12.84 112.32 ;
    END
  END fill_data[37]
  PIN fill_data[38]
    DIRECTION INPUT ;
    USE SIGNAL ;
    PORT
      LAYER M5 ;
        RECT  12.912 112.236 12.936 112.32 ;
    END
  END fill_data[38]
  PIN fill_data[39]
    DIRECTION INPUT ;
    USE SIGNAL ;
    PORT
      LAYER M5 ;
        RECT  13.008 112.236 13.032 112.32 ;
    END
  END fill_data[39]
  PIN fill_data[3]
    DIRECTION INPUT ;
    USE SIGNAL ;
    PORT
      LAYER M5 ;
        RECT  15.696 112.236 15.72 112.32 ;
    END
  END fill_data[3]
  PIN fill_data[40]
    DIRECTION INPUT ;
    USE SIGNAL ;
    PORT
      LAYER M5 ;
        RECT  13.104 112.236 13.128 112.32 ;
    END
  END fill_data[40]
  PIN fill_data[41]
    DIRECTION INPUT ;
    USE SIGNAL ;
    PORT
      LAYER M5 ;
        RECT  13.2 112.236 13.224 112.32 ;
    END
  END fill_data[41]
  PIN fill_data[42]
    DIRECTION INPUT ;
    USE SIGNAL ;
    PORT
      LAYER M5 ;
        RECT  13.296 112.236 13.32 112.32 ;
    END
  END fill_data[42]
  PIN fill_data[43]
    DIRECTION INPUT ;
    USE SIGNAL ;
    PORT
      LAYER M5 ;
        RECT  13.392 112.236 13.416 112.32 ;
    END
  END fill_data[43]
  PIN fill_data[44]
    DIRECTION INPUT ;
    USE SIGNAL ;
    PORT
      LAYER M5 ;
        RECT  13.488 112.236 13.512 112.32 ;
    END
  END fill_data[44]
  PIN fill_data[45]
    DIRECTION INPUT ;
    USE SIGNAL ;
    PORT
      LAYER M5 ;
        RECT  13.584 112.236 13.608 112.32 ;
    END
  END fill_data[45]
  PIN fill_data[46]
    DIRECTION INPUT ;
    USE SIGNAL ;
    PORT
      LAYER M5 ;
        RECT  13.68 112.236 13.704 112.32 ;
    END
  END fill_data[46]
  PIN fill_data[47]
    DIRECTION INPUT ;
    USE SIGNAL ;
    PORT
      LAYER M5 ;
        RECT  13.776 112.236 13.8 112.32 ;
    END
  END fill_data[47]
  PIN fill_data[48]
    DIRECTION INPUT ;
    USE SIGNAL ;
    PORT
      LAYER M5 ;
        RECT  13.872 112.236 13.896 112.32 ;
    END
  END fill_data[48]
  PIN fill_data[49]
    DIRECTION INPUT ;
    USE SIGNAL ;
    PORT
      LAYER M5 ;
        RECT  13.968 112.236 13.992 112.32 ;
    END
  END fill_data[49]
  PIN fill_data[4]
    DIRECTION INPUT ;
    USE SIGNAL ;
    PORT
      LAYER M5 ;
        RECT  15.792 112.236 15.816 112.32 ;
    END
  END fill_data[4]
  PIN fill_data[50]
    DIRECTION INPUT ;
    USE SIGNAL ;
    PORT
      LAYER M5 ;
        RECT  14.064 112.236 14.088 112.32 ;
    END
  END fill_data[50]
  PIN fill_data[51]
    DIRECTION INPUT ;
    USE SIGNAL ;
    PORT
      LAYER M5 ;
        RECT  14.16 112.236 14.184 112.32 ;
    END
  END fill_data[51]
  PIN fill_data[52]
    DIRECTION INPUT ;
    USE SIGNAL ;
    PORT
      LAYER M5 ;
        RECT  14.256 112.236 14.28 112.32 ;
    END
  END fill_data[52]
  PIN fill_data[53]
    DIRECTION INPUT ;
    USE SIGNAL ;
    PORT
      LAYER M5 ;
        RECT  14.352 112.236 14.376 112.32 ;
    END
  END fill_data[53]
  PIN fill_data[54]
    DIRECTION INPUT ;
    USE SIGNAL ;
    PORT
      LAYER M5 ;
        RECT  14.448 112.236 14.472 112.32 ;
    END
  END fill_data[54]
  PIN fill_data[55]
    DIRECTION INPUT ;
    USE SIGNAL ;
    PORT
      LAYER M5 ;
        RECT  14.544 112.236 14.568 112.32 ;
    END
  END fill_data[55]
  PIN fill_data[56]
    DIRECTION INPUT ;
    USE SIGNAL ;
    PORT
      LAYER M5 ;
        RECT  14.64 112.236 14.664 112.32 ;
    END
  END fill_data[56]
  PIN fill_data[57]
    DIRECTION INPUT ;
    USE SIGNAL ;
    PORT
      LAYER M5 ;
        RECT  14.736 112.236 14.76 112.32 ;
    END
  END fill_data[57]
  PIN fill_data[58]
    DIRECTION INPUT ;
    USE SIGNAL ;
    PORT
      LAYER M5 ;
        RECT  14.832 112.236 14.856 112.32 ;
    END
  END fill_data[58]
  PIN fill_data[59]
    DIRECTION INPUT ;
    USE SIGNAL ;
    PORT
      LAYER M5 ;
        RECT  14.928 112.236 14.952 112.32 ;
    END
  END fill_data[59]
  PIN fill_data[5]
    DIRECTION INPUT ;
    USE SIGNAL ;
    PORT
      LAYER M5 ;
        RECT  15.888 112.236 15.912 112.32 ;
    END
  END fill_data[5]
  PIN fill_data[60]
    DIRECTION INPUT ;
    USE SIGNAL ;
    PORT
      LAYER M5 ;
        RECT  15.024 112.236 15.048 112.32 ;
    END
  END fill_data[60]
  PIN fill_data[61]
    DIRECTION INPUT ;
    USE SIGNAL ;
    PORT
      LAYER M5 ;
        RECT  15.12 112.236 15.144 112.32 ;
    END
  END fill_data[61]
  PIN fill_data[62]
    DIRECTION INPUT ;
    USE SIGNAL ;
    PORT
      LAYER M5 ;
        RECT  15.216 112.236 15.24 112.32 ;
    END
  END fill_data[62]
  PIN fill_data[63]
    DIRECTION INPUT ;
    USE SIGNAL ;
    PORT
      LAYER M5 ;
        RECT  9.168 112.236 9.192 112.32 ;
    END
  END fill_data[63]
  PIN fill_data[64]
    DIRECTION INPUT ;
    USE SIGNAL ;
    PORT
      LAYER M5 ;
        RECT  9.264 112.236 9.288 112.32 ;
    END
  END fill_data[64]
  PIN fill_data[65]
    DIRECTION INPUT ;
    USE SIGNAL ;
    PORT
      LAYER M5 ;
        RECT  9.36 112.236 9.384 112.32 ;
    END
  END fill_data[65]
  PIN fill_data[66]
    DIRECTION INPUT ;
    USE SIGNAL ;
    PORT
      LAYER M5 ;
        RECT  9.456 112.236 9.48 112.32 ;
    END
  END fill_data[66]
  PIN fill_data[67]
    DIRECTION INPUT ;
    USE SIGNAL ;
    PORT
      LAYER M5 ;
        RECT  9.552 112.236 9.576 112.32 ;
    END
  END fill_data[67]
  PIN fill_data[68]
    DIRECTION INPUT ;
    USE SIGNAL ;
    PORT
      LAYER M5 ;
        RECT  9.648 112.236 9.672 112.32 ;
    END
  END fill_data[68]
  PIN fill_data[69]
    DIRECTION INPUT ;
    USE SIGNAL ;
    PORT
      LAYER M5 ;
        RECT  9.744 112.236 9.768 112.32 ;
    END
  END fill_data[69]
  PIN fill_data[6]
    DIRECTION INPUT ;
    USE SIGNAL ;
    PORT
      LAYER M5 ;
        RECT  15.984 112.236 16.008 112.32 ;
    END
  END fill_data[6]
  PIN fill_data[70]
    DIRECTION INPUT ;
    USE SIGNAL ;
    PORT
      LAYER M5 ;
        RECT  9.84 112.236 9.864 112.32 ;
    END
  END fill_data[70]
  PIN fill_data[71]
    DIRECTION INPUT ;
    USE SIGNAL ;
    PORT
      LAYER M5 ;
        RECT  9.936 112.236 9.96 112.32 ;
    END
  END fill_data[71]
  PIN fill_data[72]
    DIRECTION INPUT ;
    USE SIGNAL ;
    PORT
      LAYER M5 ;
        RECT  10.032 112.236 10.056 112.32 ;
    END
  END fill_data[72]
  PIN fill_data[73]
    DIRECTION INPUT ;
    USE SIGNAL ;
    PORT
      LAYER M5 ;
        RECT  10.128 112.236 10.152 112.32 ;
    END
  END fill_data[73]
  PIN fill_data[74]
    DIRECTION INPUT ;
    USE SIGNAL ;
    PORT
      LAYER M5 ;
        RECT  10.224 112.236 10.248 112.32 ;
    END
  END fill_data[74]
  PIN fill_data[75]
    DIRECTION INPUT ;
    USE SIGNAL ;
    PORT
      LAYER M5 ;
        RECT  10.32 112.236 10.344 112.32 ;
    END
  END fill_data[75]
  PIN fill_data[76]
    DIRECTION INPUT ;
    USE SIGNAL ;
    PORT
      LAYER M5 ;
        RECT  10.416 112.236 10.44 112.32 ;
    END
  END fill_data[76]
  PIN fill_data[77]
    DIRECTION INPUT ;
    USE SIGNAL ;
    PORT
      LAYER M5 ;
        RECT  10.512 112.236 10.536 112.32 ;
    END
  END fill_data[77]
  PIN fill_data[78]
    DIRECTION INPUT ;
    USE SIGNAL ;
    PORT
      LAYER M5 ;
        RECT  10.608 112.236 10.632 112.32 ;
    END
  END fill_data[78]
  PIN fill_data[79]
    DIRECTION INPUT ;
    USE SIGNAL ;
    PORT
      LAYER M5 ;
        RECT  10.704 112.236 10.728 112.32 ;
    END
  END fill_data[79]
  PIN fill_data[7]
    DIRECTION INPUT ;
    USE SIGNAL ;
    PORT
      LAYER M5 ;
        RECT  16.08 112.236 16.104 112.32 ;
    END
  END fill_data[7]
  PIN fill_data[80]
    DIRECTION INPUT ;
    USE SIGNAL ;
    PORT
      LAYER M5 ;
        RECT  10.8 112.236 10.824 112.32 ;
    END
  END fill_data[80]
  PIN fill_data[81]
    DIRECTION INPUT ;
    USE SIGNAL ;
    PORT
      LAYER M5 ;
        RECT  10.896 112.236 10.92 112.32 ;
    END
  END fill_data[81]
  PIN fill_data[82]
    DIRECTION INPUT ;
    USE SIGNAL ;
    PORT
      LAYER M5 ;
        RECT  10.992 112.236 11.016 112.32 ;
    END
  END fill_data[82]
  PIN fill_data[83]
    DIRECTION INPUT ;
    USE SIGNAL ;
    PORT
      LAYER M5 ;
        RECT  11.088 112.236 11.112 112.32 ;
    END
  END fill_data[83]
  PIN fill_data[84]
    DIRECTION INPUT ;
    USE SIGNAL ;
    PORT
      LAYER M5 ;
        RECT  11.184 112.236 11.208 112.32 ;
    END
  END fill_data[84]
  PIN fill_data[85]
    DIRECTION INPUT ;
    USE SIGNAL ;
    PORT
      LAYER M5 ;
        RECT  11.28 112.236 11.304 112.32 ;
    END
  END fill_data[85]
  PIN fill_data[86]
    DIRECTION INPUT ;
    USE SIGNAL ;
    PORT
      LAYER M5 ;
        RECT  11.376 112.236 11.4 112.32 ;
    END
  END fill_data[86]
  PIN fill_data[87]
    DIRECTION INPUT ;
    USE SIGNAL ;
    PORT
      LAYER M5 ;
        RECT  11.472 112.236 11.496 112.32 ;
    END
  END fill_data[87]
  PIN fill_data[88]
    DIRECTION INPUT ;
    USE SIGNAL ;
    PORT
      LAYER M5 ;
        RECT  11.568 112.236 11.592 112.32 ;
    END
  END fill_data[88]
  PIN fill_data[89]
    DIRECTION INPUT ;
    USE SIGNAL ;
    PORT
      LAYER M5 ;
        RECT  11.664 112.236 11.688 112.32 ;
    END
  END fill_data[89]
  PIN fill_data[8]
    DIRECTION INPUT ;
    USE SIGNAL ;
    PORT
      LAYER M5 ;
        RECT  16.176 112.236 16.2 112.32 ;
    END
  END fill_data[8]
  PIN fill_data[90]
    DIRECTION INPUT ;
    USE SIGNAL ;
    PORT
      LAYER M5 ;
        RECT  11.76 112.236 11.784 112.32 ;
    END
  END fill_data[90]
  PIN fill_data[91]
    DIRECTION INPUT ;
    USE SIGNAL ;
    PORT
      LAYER M5 ;
        RECT  11.856 112.236 11.88 112.32 ;
    END
  END fill_data[91]
  PIN fill_data[92]
    DIRECTION INPUT ;
    USE SIGNAL ;
    PORT
      LAYER M5 ;
        RECT  11.952 112.236 11.976 112.32 ;
    END
  END fill_data[92]
  PIN fill_data[93]
    DIRECTION INPUT ;
    USE SIGNAL ;
    PORT
      LAYER M5 ;
        RECT  12.048 112.236 12.072 112.32 ;
    END
  END fill_data[93]
  PIN fill_data[94]
    DIRECTION INPUT ;
    USE SIGNAL ;
    PORT
      LAYER M5 ;
        RECT  12.144 112.236 12.168 112.32 ;
    END
  END fill_data[94]
  PIN fill_data[95]
    DIRECTION INPUT ;
    USE SIGNAL ;
    PORT
      LAYER M5 ;
        RECT  18.384 112.236 18.408 112.32 ;
    END
  END fill_data[95]
  PIN fill_data[96]
    DIRECTION INPUT ;
    USE SIGNAL ;
    PORT
      LAYER M5 ;
        RECT  18.48 112.236 18.504 112.32 ;
    END
  END fill_data[96]
  PIN fill_data[97]
    DIRECTION INPUT ;
    USE SIGNAL ;
    PORT
      LAYER M5 ;
        RECT  18.576 112.236 18.6 112.32 ;
    END
  END fill_data[97]
  PIN fill_data[98]
    DIRECTION INPUT ;
    USE SIGNAL ;
    PORT
      LAYER M5 ;
        RECT  18.672 112.236 18.696 112.32 ;
    END
  END fill_data[98]
  PIN fill_data[99]
    DIRECTION INPUT ;
    USE SIGNAL ;
    PORT
      LAYER M5 ;
        RECT  18.768 112.236 18.792 112.32 ;
    END
  END fill_data[99]
  PIN fill_data[9]
    DIRECTION INPUT ;
    USE SIGNAL ;
    PORT
      LAYER M5 ;
        RECT  16.272 112.236 16.296 112.32 ;
    END
  END fill_data[9]
  PIN fill_epoch[0]
    DIRECTION INPUT ;
    USE SIGNAL ;
    PORT
      LAYER M5 ;
        RECT  6.192 112.236 6.216 112.32 ;
    END
  END fill_epoch[0]
  PIN fill_epoch[10]
    DIRECTION INPUT ;
    USE SIGNAL ;
    PORT
      LAYER M5 ;
        RECT  7.152 112.236 7.176 112.32 ;
    END
  END fill_epoch[10]
  PIN fill_epoch[11]
    DIRECTION INPUT ;
    USE SIGNAL ;
    PORT
      LAYER M5 ;
        RECT  7.248 112.236 7.272 112.32 ;
    END
  END fill_epoch[11]
  PIN fill_epoch[12]
    DIRECTION INPUT ;
    USE SIGNAL ;
    PORT
      LAYER M5 ;
        RECT  7.344 112.236 7.368 112.32 ;
    END
  END fill_epoch[12]
  PIN fill_epoch[13]
    DIRECTION INPUT ;
    USE SIGNAL ;
    PORT
      LAYER M5 ;
        RECT  7.44 112.236 7.464 112.32 ;
    END
  END fill_epoch[13]
  PIN fill_epoch[14]
    DIRECTION INPUT ;
    USE SIGNAL ;
    PORT
      LAYER M5 ;
        RECT  7.536 112.236 7.56 112.32 ;
    END
  END fill_epoch[14]
  PIN fill_epoch[15]
    DIRECTION INPUT ;
    USE SIGNAL ;
    PORT
      LAYER M5 ;
        RECT  7.632 112.236 7.656 112.32 ;
    END
  END fill_epoch[15]
  PIN fill_epoch[1]
    DIRECTION INPUT ;
    USE SIGNAL ;
    PORT
      LAYER M5 ;
        RECT  6.288 112.236 6.312 112.32 ;
    END
  END fill_epoch[1]
  PIN fill_epoch[2]
    DIRECTION INPUT ;
    USE SIGNAL ;
    PORT
      LAYER M5 ;
        RECT  6.384 112.236 6.408 112.32 ;
    END
  END fill_epoch[2]
  PIN fill_epoch[3]
    DIRECTION INPUT ;
    USE SIGNAL ;
    PORT
      LAYER M5 ;
        RECT  6.48 112.236 6.504 112.32 ;
    END
  END fill_epoch[3]
  PIN fill_epoch[4]
    DIRECTION INPUT ;
    USE SIGNAL ;
    PORT
      LAYER M5 ;
        RECT  6.576 112.236 6.6 112.32 ;
    END
  END fill_epoch[4]
  PIN fill_epoch[5]
    DIRECTION INPUT ;
    USE SIGNAL ;
    PORT
      LAYER M5 ;
        RECT  6.672 112.236 6.696 112.32 ;
    END
  END fill_epoch[5]
  PIN fill_epoch[6]
    DIRECTION INPUT ;
    USE SIGNAL ;
    PORT
      LAYER M5 ;
        RECT  6.768 112.236 6.792 112.32 ;
    END
  END fill_epoch[6]
  PIN fill_epoch[7]
    DIRECTION INPUT ;
    USE SIGNAL ;
    PORT
      LAYER M5 ;
        RECT  6.864 112.236 6.888 112.32 ;
    END
  END fill_epoch[7]
  PIN fill_epoch[8]
    DIRECTION INPUT ;
    USE SIGNAL ;
    PORT
      LAYER M5 ;
        RECT  6.96 112.236 6.984 112.32 ;
    END
  END fill_epoch[8]
  PIN fill_epoch[9]
    DIRECTION INPUT ;
    USE SIGNAL ;
    PORT
      LAYER M5 ;
        RECT  7.056 112.236 7.08 112.32 ;
    END
  END fill_epoch[9]
  PIN fill_slot[0]
    DIRECTION INPUT ;
    USE SIGNAL ;
    PORT
      LAYER M5 ;
        RECT  7.728 112.236 7.752 112.32 ;
    END
  END fill_slot[0]
  PIN fill_slot[1]
    DIRECTION INPUT ;
    USE SIGNAL ;
    PORT
      LAYER M5 ;
        RECT  7.824 112.236 7.848 112.32 ;
    END
  END fill_slot[1]
  PIN fill_slot[2]
    DIRECTION INPUT ;
    USE SIGNAL ;
    PORT
      LAYER M5 ;
        RECT  7.92 112.236 7.944 112.32 ;
    END
  END fill_slot[2]
  PIN fill_slot[3]
    DIRECTION INPUT ;
    USE SIGNAL ;
    PORT
      LAYER M5 ;
        RECT  8.016 112.236 8.04 112.32 ;
    END
  END fill_slot[3]
  PIN fill_slot[4]
    DIRECTION INPUT ;
    USE SIGNAL ;
    PORT
      LAYER M5 ;
        RECT  8.112 112.236 8.136 112.32 ;
    END
  END fill_slot[4]
  PIN fill_slot[5]
    DIRECTION INPUT ;
    USE SIGNAL ;
    PORT
      LAYER M5 ;
        RECT  8.208 112.236 8.232 112.32 ;
    END
  END fill_slot[5]
  PIN fill_v
    DIRECTION INPUT ;
    USE SIGNAL ;
    PORT
      LAYER M5 ;
        RECT  8.304 112.236 8.328 112.32 ;
    END
  END fill_v
  PIN k_addr[0]
    DIRECTION OUTPUT ;
    USE SIGNAL ;
    PORT
      LAYER M5 ;
        RECT  16.08 0 16.104 0.084 ;
    END
  END k_addr[0]
  PIN k_addr[10]
    DIRECTION OUTPUT ;
    USE SIGNAL ;
    PORT
      LAYER M5 ;
        RECT  17.04 0 17.064 0.084 ;
    END
  END k_addr[10]
  PIN k_addr[11]
    DIRECTION OUTPUT ;
    USE SIGNAL ;
    PORT
      LAYER M5 ;
        RECT  17.136 0 17.16 0.084 ;
    END
  END k_addr[11]
  PIN k_addr[12]
    DIRECTION OUTPUT ;
    USE SIGNAL ;
    PORT
      LAYER M5 ;
        RECT  17.232 0 17.256 0.084 ;
    END
  END k_addr[12]
  PIN k_addr[13]
    DIRECTION OUTPUT ;
    USE SIGNAL ;
    PORT
      LAYER M5 ;
        RECT  17.328 0 17.352 0.084 ;
    END
  END k_addr[13]
  PIN k_addr[14]
    DIRECTION OUTPUT ;
    USE SIGNAL ;
    PORT
      LAYER M5 ;
        RECT  17.424 0 17.448 0.084 ;
    END
  END k_addr[14]
  PIN k_addr[15]
    DIRECTION OUTPUT ;
    USE SIGNAL ;
    PORT
      LAYER M5 ;
        RECT  17.52 0 17.544 0.084 ;
    END
  END k_addr[15]
  PIN k_addr[16]
    DIRECTION OUTPUT ;
    USE SIGNAL ;
    PORT
      LAYER M5 ;
        RECT  17.616 0 17.64 0.084 ;
    END
  END k_addr[16]
  PIN k_addr[17]
    DIRECTION OUTPUT ;
    USE SIGNAL ;
    PORT
      LAYER M5 ;
        RECT  17.712 0 17.736 0.084 ;
    END
  END k_addr[17]
  PIN k_addr[18]
    DIRECTION OUTPUT ;
    USE SIGNAL ;
    PORT
      LAYER M5 ;
        RECT  17.808 0 17.832 0.084 ;
    END
  END k_addr[18]
  PIN k_addr[19]
    DIRECTION OUTPUT ;
    USE SIGNAL ;
    PORT
      LAYER M5 ;
        RECT  17.904 0 17.928 0.084 ;
    END
  END k_addr[19]
  PIN k_addr[1]
    DIRECTION OUTPUT ;
    USE SIGNAL ;
    PORT
      LAYER M5 ;
        RECT  16.176 0 16.2 0.084 ;
    END
  END k_addr[1]
  PIN k_addr[20]
    DIRECTION OUTPUT ;
    USE SIGNAL ;
    PORT
      LAYER M5 ;
        RECT  18 0 18.024 0.084 ;
    END
  END k_addr[20]
  PIN k_addr[21]
    DIRECTION OUTPUT ;
    USE SIGNAL ;
    PORT
      LAYER M5 ;
        RECT  18.096 0 18.12 0.084 ;
    END
  END k_addr[21]
  PIN k_addr[22]
    DIRECTION OUTPUT ;
    USE SIGNAL ;
    PORT
      LAYER M5 ;
        RECT  18.192 0 18.216 0.084 ;
    END
  END k_addr[22]
  PIN k_addr[23]
    DIRECTION OUTPUT ;
    USE SIGNAL ;
    PORT
      LAYER M5 ;
        RECT  18.288 0 18.312 0.084 ;
    END
  END k_addr[23]
  PIN k_addr[24]
    DIRECTION OUTPUT ;
    USE SIGNAL ;
    PORT
      LAYER M5 ;
        RECT  18.384 0 18.408 0.084 ;
    END
  END k_addr[24]
  PIN k_addr[25]
    DIRECTION OUTPUT ;
    USE SIGNAL ;
    PORT
      LAYER M5 ;
        RECT  18.48 0 18.504 0.084 ;
    END
  END k_addr[25]
  PIN k_addr[26]
    DIRECTION OUTPUT ;
    USE SIGNAL ;
    PORT
      LAYER M5 ;
        RECT  18.576 0 18.6 0.084 ;
    END
  END k_addr[26]
  PIN k_addr[27]
    DIRECTION OUTPUT ;
    USE SIGNAL ;
    PORT
      LAYER M5 ;
        RECT  18.672 0 18.696 0.084 ;
    END
  END k_addr[27]
  PIN k_addr[28]
    DIRECTION OUTPUT ;
    USE SIGNAL ;
    PORT
      LAYER M5 ;
        RECT  18.768 0 18.792 0.084 ;
    END
  END k_addr[28]
  PIN k_addr[29]
    DIRECTION OUTPUT ;
    USE SIGNAL ;
    PORT
      LAYER M5 ;
        RECT  18.864 0 18.888 0.084 ;
    END
  END k_addr[29]
  PIN k_addr[2]
    DIRECTION OUTPUT ;
    USE SIGNAL ;
    PORT
      LAYER M5 ;
        RECT  16.272 0 16.296 0.084 ;
    END
  END k_addr[2]
  PIN k_addr[3]
    DIRECTION OUTPUT ;
    USE SIGNAL ;
    PORT
      LAYER M5 ;
        RECT  16.368 0 16.392 0.084 ;
    END
  END k_addr[3]
  PIN k_addr[4]
    DIRECTION OUTPUT ;
    USE SIGNAL ;
    PORT
      LAYER M5 ;
        RECT  16.464 0 16.488 0.084 ;
    END
  END k_addr[4]
  PIN k_addr[5]
    DIRECTION OUTPUT ;
    USE SIGNAL ;
    PORT
      LAYER M5 ;
        RECT  16.56 0 16.584 0.084 ;
    END
  END k_addr[5]
  PIN k_addr[6]
    DIRECTION OUTPUT ;
    USE SIGNAL ;
    PORT
      LAYER M5 ;
        RECT  16.656 0 16.68 0.084 ;
    END
  END k_addr[6]
  PIN k_addr[7]
    DIRECTION OUTPUT ;
    USE SIGNAL ;
    PORT
      LAYER M5 ;
        RECT  16.752 0 16.776 0.084 ;
    END
  END k_addr[7]
  PIN k_addr[8]
    DIRECTION OUTPUT ;
    USE SIGNAL ;
    PORT
      LAYER M5 ;
        RECT  16.848 0 16.872 0.084 ;
    END
  END k_addr[8]
  PIN k_addr[9]
    DIRECTION OUTPUT ;
    USE SIGNAL ;
    PORT
      LAYER M5 ;
        RECT  16.944 0 16.968 0.084 ;
    END
  END k_addr[9]
  PIN k_len[0]
    DIRECTION OUTPUT ;
    USE SIGNAL ;
    PORT
      LAYER M5 ;
        RECT  18.96 0 18.984 0.084 ;
    END
  END k_len[0]
  PIN k_len[1]
    DIRECTION OUTPUT ;
    USE SIGNAL ;
    PORT
      LAYER M5 ;
        RECT  19.056 0 19.08 0.084 ;
    END
  END k_len[1]
  PIN k_len[2]
    DIRECTION OUTPUT ;
    USE SIGNAL ;
    PORT
      LAYER M5 ;
        RECT  13.008 0 13.032 0.084 ;
    END
  END k_len[2]
  PIN k_len[3]
    DIRECTION OUTPUT ;
    USE SIGNAL ;
    PORT
      LAYER M5 ;
        RECT  13.104 0 13.128 0.084 ;
    END
  END k_len[3]
  PIN k_rdy
    DIRECTION INPUT ;
    USE SIGNAL ;
    PORT
      LAYER M5 ;
        RECT  13.2 0 13.224 0.084 ;
    END
  END k_rdy
  PIN k_tag[0]
    DIRECTION OUTPUT ;
    USE SIGNAL ;
    PORT
      LAYER M5 ;
        RECT  13.296 0 13.32 0.084 ;
    END
  END k_tag[0]
  PIN k_tag[10]
    DIRECTION OUTPUT ;
    USE SIGNAL ;
    PORT
      LAYER M5 ;
        RECT  14.256 0 14.28 0.084 ;
    END
  END k_tag[10]
  PIN k_tag[11]
    DIRECTION OUTPUT ;
    USE SIGNAL ;
    PORT
      LAYER M5 ;
        RECT  14.352 0 14.376 0.084 ;
    END
  END k_tag[11]
  PIN k_tag[12]
    DIRECTION OUTPUT ;
    USE SIGNAL ;
    PORT
      LAYER M5 ;
        RECT  14.448 0 14.472 0.084 ;
    END
  END k_tag[12]
  PIN k_tag[13]
    DIRECTION OUTPUT ;
    USE SIGNAL ;
    PORT
      LAYER M5 ;
        RECT  14.544 0 14.568 0.084 ;
    END
  END k_tag[13]
  PIN k_tag[14]
    DIRECTION OUTPUT ;
    USE SIGNAL ;
    PORT
      LAYER M5 ;
        RECT  14.64 0 14.664 0.084 ;
    END
  END k_tag[14]
  PIN k_tag[15]
    DIRECTION OUTPUT ;
    USE SIGNAL ;
    PORT
      LAYER M5 ;
        RECT  14.736 0 14.76 0.084 ;
    END
  END k_tag[15]
  PIN k_tag[16]
    DIRECTION OUTPUT ;
    USE SIGNAL ;
    PORT
      LAYER M5 ;
        RECT  14.832 0 14.856 0.084 ;
    END
  END k_tag[16]
  PIN k_tag[1]
    DIRECTION OUTPUT ;
    USE SIGNAL ;
    PORT
      LAYER M5 ;
        RECT  13.392 0 13.416 0.084 ;
    END
  END k_tag[1]
  PIN k_tag[2]
    DIRECTION OUTPUT ;
    USE SIGNAL ;
    PORT
      LAYER M5 ;
        RECT  13.488 0 13.512 0.084 ;
    END
  END k_tag[2]
  PIN k_tag[3]
    DIRECTION OUTPUT ;
    USE SIGNAL ;
    PORT
      LAYER M5 ;
        RECT  13.584 0 13.608 0.084 ;
    END
  END k_tag[3]
  PIN k_tag[4]
    DIRECTION OUTPUT ;
    USE SIGNAL ;
    PORT
      LAYER M5 ;
        RECT  13.68 0 13.704 0.084 ;
    END
  END k_tag[4]
  PIN k_tag[5]
    DIRECTION OUTPUT ;
    USE SIGNAL ;
    PORT
      LAYER M5 ;
        RECT  13.776 0 13.8 0.084 ;
    END
  END k_tag[5]
  PIN k_tag[6]
    DIRECTION OUTPUT ;
    USE SIGNAL ;
    PORT
      LAYER M5 ;
        RECT  13.872 0 13.896 0.084 ;
    END
  END k_tag[6]
  PIN k_tag[7]
    DIRECTION OUTPUT ;
    USE SIGNAL ;
    PORT
      LAYER M5 ;
        RECT  13.968 0 13.992 0.084 ;
    END
  END k_tag[7]
  PIN k_tag[8]
    DIRECTION OUTPUT ;
    USE SIGNAL ;
    PORT
      LAYER M5 ;
        RECT  14.064 0 14.088 0.084 ;
    END
  END k_tag[8]
  PIN k_tag[9]
    DIRECTION OUTPUT ;
    USE SIGNAL ;
    PORT
      LAYER M5 ;
        RECT  14.16 0 14.184 0.084 ;
    END
  END k_tag[9]
  PIN k_v
    DIRECTION OUTPUT ;
    USE SIGNAL ;
    PORT
      LAYER M5 ;
        RECT  14.928 0 14.952 0.084 ;
    END
  END k_v
  PIN k_wdata[0]
    DIRECTION OUTPUT ;
    USE SIGNAL ;
    PORT
      LAYER M5 ;
        RECT  15.024 0 15.048 0.084 ;
    END
  END k_wdata[0]
  PIN k_wdata[100]
    DIRECTION OUTPUT ;
    USE SIGNAL ;
    PORT
      LAYER M5 ;
        RECT  9.264 0 9.288 0.084 ;
    END
  END k_wdata[100]
  PIN k_wdata[101]
    DIRECTION OUTPUT ;
    USE SIGNAL ;
    PORT
      LAYER M5 ;
        RECT  9.36 0 9.384 0.084 ;
    END
  END k_wdata[101]
  PIN k_wdata[102]
    DIRECTION OUTPUT ;
    USE SIGNAL ;
    PORT
      LAYER M5 ;
        RECT  9.456 0 9.48 0.084 ;
    END
  END k_wdata[102]
  PIN k_wdata[103]
    DIRECTION OUTPUT ;
    USE SIGNAL ;
    PORT
      LAYER M5 ;
        RECT  9.552 0 9.576 0.084 ;
    END
  END k_wdata[103]
  PIN k_wdata[104]
    DIRECTION OUTPUT ;
    USE SIGNAL ;
    PORT
      LAYER M5 ;
        RECT  9.648 0 9.672 0.084 ;
    END
  END k_wdata[104]
  PIN k_wdata[105]
    DIRECTION OUTPUT ;
    USE SIGNAL ;
    PORT
      LAYER M5 ;
        RECT  9.744 0 9.768 0.084 ;
    END
  END k_wdata[105]
  PIN k_wdata[106]
    DIRECTION OUTPUT ;
    USE SIGNAL ;
    PORT
      LAYER M5 ;
        RECT  9.84 0 9.864 0.084 ;
    END
  END k_wdata[106]
  PIN k_wdata[107]
    DIRECTION OUTPUT ;
    USE SIGNAL ;
    PORT
      LAYER M5 ;
        RECT  3.792 0 3.816 0.084 ;
    END
  END k_wdata[107]
  PIN k_wdata[108]
    DIRECTION OUTPUT ;
    USE SIGNAL ;
    PORT
      LAYER M5 ;
        RECT  3.888 0 3.912 0.084 ;
    END
  END k_wdata[108]
  PIN k_wdata[109]
    DIRECTION OUTPUT ;
    USE SIGNAL ;
    PORT
      LAYER M5 ;
        RECT  3.984 0 4.008 0.084 ;
    END
  END k_wdata[109]
  PIN k_wdata[10]
    DIRECTION OUTPUT ;
    USE SIGNAL ;
    PORT
      LAYER M5 ;
        RECT  15.984 0 16.008 0.084 ;
    END
  END k_wdata[10]
  PIN k_wdata[110]
    DIRECTION OUTPUT ;
    USE SIGNAL ;
    PORT
      LAYER M5 ;
        RECT  4.08 0 4.104 0.084 ;
    END
  END k_wdata[110]
  PIN k_wdata[111]
    DIRECTION OUTPUT ;
    USE SIGNAL ;
    PORT
      LAYER M5 ;
        RECT  4.176 0 4.2 0.084 ;
    END
  END k_wdata[111]
  PIN k_wdata[112]
    DIRECTION OUTPUT ;
    USE SIGNAL ;
    PORT
      LAYER M5 ;
        RECT  4.272 0 4.296 0.084 ;
    END
  END k_wdata[112]
  PIN k_wdata[113]
    DIRECTION OUTPUT ;
    USE SIGNAL ;
    PORT
      LAYER M5 ;
        RECT  4.368 0 4.392 0.084 ;
    END
  END k_wdata[113]
  PIN k_wdata[114]
    DIRECTION OUTPUT ;
    USE SIGNAL ;
    PORT
      LAYER M5 ;
        RECT  4.464 0 4.488 0.084 ;
    END
  END k_wdata[114]
  PIN k_wdata[115]
    DIRECTION OUTPUT ;
    USE SIGNAL ;
    PORT
      LAYER M5 ;
        RECT  4.56 0 4.584 0.084 ;
    END
  END k_wdata[115]
  PIN k_wdata[116]
    DIRECTION OUTPUT ;
    USE SIGNAL ;
    PORT
      LAYER M5 ;
        RECT  4.656 0 4.68 0.084 ;
    END
  END k_wdata[116]
  PIN k_wdata[117]
    DIRECTION OUTPUT ;
    USE SIGNAL ;
    PORT
      LAYER M5 ;
        RECT  4.752 0 4.776 0.084 ;
    END
  END k_wdata[117]
  PIN k_wdata[118]
    DIRECTION OUTPUT ;
    USE SIGNAL ;
    PORT
      LAYER M5 ;
        RECT  4.848 0 4.872 0.084 ;
    END
  END k_wdata[118]
  PIN k_wdata[119]
    DIRECTION OUTPUT ;
    USE SIGNAL ;
    PORT
      LAYER M5 ;
        RECT  4.944 0 4.968 0.084 ;
    END
  END k_wdata[119]
  PIN k_wdata[11]
    DIRECTION OUTPUT ;
    USE SIGNAL ;
    PORT
      LAYER M5 ;
        RECT  26.064 0 26.088 0.084 ;
    END
  END k_wdata[11]
  PIN k_wdata[120]
    DIRECTION OUTPUT ;
    USE SIGNAL ;
    PORT
      LAYER M5 ;
        RECT  5.04 0 5.064 0.084 ;
    END
  END k_wdata[120]
  PIN k_wdata[121]
    DIRECTION OUTPUT ;
    USE SIGNAL ;
    PORT
      LAYER M5 ;
        RECT  5.136 0 5.16 0.084 ;
    END
  END k_wdata[121]
  PIN k_wdata[122]
    DIRECTION OUTPUT ;
    USE SIGNAL ;
    PORT
      LAYER M5 ;
        RECT  5.232 0 5.256 0.084 ;
    END
  END k_wdata[122]
  PIN k_wdata[123]
    DIRECTION OUTPUT ;
    USE SIGNAL ;
    PORT
      LAYER M5 ;
        RECT  5.328 0 5.352 0.084 ;
    END
  END k_wdata[123]
  PIN k_wdata[124]
    DIRECTION OUTPUT ;
    USE SIGNAL ;
    PORT
      LAYER M5 ;
        RECT  5.424 0 5.448 0.084 ;
    END
  END k_wdata[124]
  PIN k_wdata[125]
    DIRECTION OUTPUT ;
    USE SIGNAL ;
    PORT
      LAYER M5 ;
        RECT  5.52 0 5.544 0.084 ;
    END
  END k_wdata[125]
  PIN k_wdata[126]
    DIRECTION OUTPUT ;
    USE SIGNAL ;
    PORT
      LAYER M5 ;
        RECT  5.616 0 5.64 0.084 ;
    END
  END k_wdata[126]
  PIN k_wdata[127]
    DIRECTION OUTPUT ;
    USE SIGNAL ;
    PORT
      LAYER M5 ;
        RECT  5.712 0 5.736 0.084 ;
    END
  END k_wdata[127]
  PIN k_wdata[128]
    DIRECTION OUTPUT ;
    USE SIGNAL ;
    PORT
      LAYER M5 ;
        RECT  5.808 0 5.832 0.084 ;
    END
  END k_wdata[128]
  PIN k_wdata[129]
    DIRECTION OUTPUT ;
    USE SIGNAL ;
    PORT
      LAYER M5 ;
        RECT  5.904 0 5.928 0.084 ;
    END
  END k_wdata[129]
  PIN k_wdata[12]
    DIRECTION OUTPUT ;
    USE SIGNAL ;
    PORT
      LAYER M5 ;
        RECT  26.16 0 26.184 0.084 ;
    END
  END k_wdata[12]
  PIN k_wdata[130]
    DIRECTION OUTPUT ;
    USE SIGNAL ;
    PORT
      LAYER M5 ;
        RECT  6 0 6.024 0.084 ;
    END
  END k_wdata[130]
  PIN k_wdata[131]
    DIRECTION OUTPUT ;
    USE SIGNAL ;
    PORT
      LAYER M5 ;
        RECT  6.096 0 6.12 0.084 ;
    END
  END k_wdata[131]
  PIN k_wdata[132]
    DIRECTION OUTPUT ;
    USE SIGNAL ;
    PORT
      LAYER M5 ;
        RECT  6.192 0 6.216 0.084 ;
    END
  END k_wdata[132]
  PIN k_wdata[133]
    DIRECTION OUTPUT ;
    USE SIGNAL ;
    PORT
      LAYER M5 ;
        RECT  6.288 0 6.312 0.084 ;
    END
  END k_wdata[133]
  PIN k_wdata[134]
    DIRECTION OUTPUT ;
    USE SIGNAL ;
    PORT
      LAYER M5 ;
        RECT  6.384 0 6.408 0.084 ;
    END
  END k_wdata[134]
  PIN k_wdata[135]
    DIRECTION OUTPUT ;
    USE SIGNAL ;
    PORT
      LAYER M5 ;
        RECT  6.48 0 6.504 0.084 ;
    END
  END k_wdata[135]
  PIN k_wdata[136]
    DIRECTION OUTPUT ;
    USE SIGNAL ;
    PORT
      LAYER M5 ;
        RECT  6.576 0 6.6 0.084 ;
    END
  END k_wdata[136]
  PIN k_wdata[137]
    DIRECTION OUTPUT ;
    USE SIGNAL ;
    PORT
      LAYER M5 ;
        RECT  6.672 0 6.696 0.084 ;
    END
  END k_wdata[137]
  PIN k_wdata[138]
    DIRECTION OUTPUT ;
    USE SIGNAL ;
    PORT
      LAYER M5 ;
        RECT  6.768 0 6.792 0.084 ;
    END
  END k_wdata[138]
  PIN k_wdata[139]
    DIRECTION OUTPUT ;
    USE SIGNAL ;
    PORT
      LAYER M5 ;
        RECT  0.72 0 0.744 0.084 ;
    END
  END k_wdata[139]
  PIN k_wdata[13]
    DIRECTION OUTPUT ;
    USE SIGNAL ;
    PORT
      LAYER M5 ;
        RECT  26.256 0 26.28 0.084 ;
    END
  END k_wdata[13]
  PIN k_wdata[140]
    DIRECTION OUTPUT ;
    USE SIGNAL ;
    PORT
      LAYER M5 ;
        RECT  0.816 0 0.84 0.084 ;
    END
  END k_wdata[140]
  PIN k_wdata[141]
    DIRECTION OUTPUT ;
    USE SIGNAL ;
    PORT
      LAYER M5 ;
        RECT  0.912 0 0.936 0.084 ;
    END
  END k_wdata[141]
  PIN k_wdata[142]
    DIRECTION OUTPUT ;
    USE SIGNAL ;
    PORT
      LAYER M5 ;
        RECT  1.008 0 1.032 0.084 ;
    END
  END k_wdata[142]
  PIN k_wdata[143]
    DIRECTION OUTPUT ;
    USE SIGNAL ;
    PORT
      LAYER M5 ;
        RECT  1.104 0 1.128 0.084 ;
    END
  END k_wdata[143]
  PIN k_wdata[144]
    DIRECTION OUTPUT ;
    USE SIGNAL ;
    PORT
      LAYER M5 ;
        RECT  1.2 0 1.224 0.084 ;
    END
  END k_wdata[144]
  PIN k_wdata[145]
    DIRECTION OUTPUT ;
    USE SIGNAL ;
    PORT
      LAYER M5 ;
        RECT  1.296 0 1.32 0.084 ;
    END
  END k_wdata[145]
  PIN k_wdata[146]
    DIRECTION OUTPUT ;
    USE SIGNAL ;
    PORT
      LAYER M5 ;
        RECT  1.392 0 1.416 0.084 ;
    END
  END k_wdata[146]
  PIN k_wdata[147]
    DIRECTION OUTPUT ;
    USE SIGNAL ;
    PORT
      LAYER M5 ;
        RECT  1.488 0 1.512 0.084 ;
    END
  END k_wdata[147]
  PIN k_wdata[148]
    DIRECTION OUTPUT ;
    USE SIGNAL ;
    PORT
      LAYER M5 ;
        RECT  1.584 0 1.608 0.084 ;
    END
  END k_wdata[148]
  PIN k_wdata[149]
    DIRECTION OUTPUT ;
    USE SIGNAL ;
    PORT
      LAYER M5 ;
        RECT  1.68 0 1.704 0.084 ;
    END
  END k_wdata[149]
  PIN k_wdata[14]
    DIRECTION OUTPUT ;
    USE SIGNAL ;
    PORT
      LAYER M5 ;
        RECT  26.352 0 26.376 0.084 ;
    END
  END k_wdata[14]
  PIN k_wdata[150]
    DIRECTION OUTPUT ;
    USE SIGNAL ;
    PORT
      LAYER M5 ;
        RECT  1.776 0 1.8 0.084 ;
    END
  END k_wdata[150]
  PIN k_wdata[151]
    DIRECTION OUTPUT ;
    USE SIGNAL ;
    PORT
      LAYER M5 ;
        RECT  1.872 0 1.896 0.084 ;
    END
  END k_wdata[151]
  PIN k_wdata[152]
    DIRECTION OUTPUT ;
    USE SIGNAL ;
    PORT
      LAYER M5 ;
        RECT  1.968 0 1.992 0.084 ;
    END
  END k_wdata[152]
  PIN k_wdata[153]
    DIRECTION OUTPUT ;
    USE SIGNAL ;
    PORT
      LAYER M5 ;
        RECT  2.064 0 2.088 0.084 ;
    END
  END k_wdata[153]
  PIN k_wdata[154]
    DIRECTION OUTPUT ;
    USE SIGNAL ;
    PORT
      LAYER M5 ;
        RECT  2.16 0 2.184 0.084 ;
    END
  END k_wdata[154]
  PIN k_wdata[155]
    DIRECTION OUTPUT ;
    USE SIGNAL ;
    PORT
      LAYER M5 ;
        RECT  2.256 0 2.28 0.084 ;
    END
  END k_wdata[155]
  PIN k_wdata[156]
    DIRECTION OUTPUT ;
    USE SIGNAL ;
    PORT
      LAYER M5 ;
        RECT  2.352 0 2.376 0.084 ;
    END
  END k_wdata[156]
  PIN k_wdata[157]
    DIRECTION OUTPUT ;
    USE SIGNAL ;
    PORT
      LAYER M5 ;
        RECT  2.448 0 2.472 0.084 ;
    END
  END k_wdata[157]
  PIN k_wdata[158]
    DIRECTION OUTPUT ;
    USE SIGNAL ;
    PORT
      LAYER M5 ;
        RECT  2.544 0 2.568 0.084 ;
    END
  END k_wdata[158]
  PIN k_wdata[159]
    DIRECTION OUTPUT ;
    USE SIGNAL ;
    PORT
      LAYER M5 ;
        RECT  2.64 0 2.664 0.084 ;
    END
  END k_wdata[159]
  PIN k_wdata[15]
    DIRECTION OUTPUT ;
    USE SIGNAL ;
    PORT
      LAYER M5 ;
        RECT  26.448 0 26.472 0.084 ;
    END
  END k_wdata[15]
  PIN k_wdata[160]
    DIRECTION OUTPUT ;
    USE SIGNAL ;
    PORT
      LAYER M5 ;
        RECT  2.736 0 2.76 0.084 ;
    END
  END k_wdata[160]
  PIN k_wdata[161]
    DIRECTION OUTPUT ;
    USE SIGNAL ;
    PORT
      LAYER M5 ;
        RECT  2.832 0 2.856 0.084 ;
    END
  END k_wdata[161]
  PIN k_wdata[162]
    DIRECTION OUTPUT ;
    USE SIGNAL ;
    PORT
      LAYER M5 ;
        RECT  2.928 0 2.952 0.084 ;
    END
  END k_wdata[162]
  PIN k_wdata[163]
    DIRECTION OUTPUT ;
    USE SIGNAL ;
    PORT
      LAYER M5 ;
        RECT  3.024 0 3.048 0.084 ;
    END
  END k_wdata[163]
  PIN k_wdata[164]
    DIRECTION OUTPUT ;
    USE SIGNAL ;
    PORT
      LAYER M5 ;
        RECT  3.12 0 3.144 0.084 ;
    END
  END k_wdata[164]
  PIN k_wdata[165]
    DIRECTION OUTPUT ;
    USE SIGNAL ;
    PORT
      LAYER M5 ;
        RECT  3.216 0 3.24 0.084 ;
    END
  END k_wdata[165]
  PIN k_wdata[166]
    DIRECTION OUTPUT ;
    USE SIGNAL ;
    PORT
      LAYER M5 ;
        RECT  3.312 0 3.336 0.084 ;
    END
  END k_wdata[166]
  PIN k_wdata[167]
    DIRECTION OUTPUT ;
    USE SIGNAL ;
    PORT
      LAYER M5 ;
        RECT  3.408 0 3.432 0.084 ;
    END
  END k_wdata[167]
  PIN k_wdata[168]
    DIRECTION OUTPUT ;
    USE SIGNAL ;
    PORT
      LAYER M5 ;
        RECT  3.504 0 3.528 0.084 ;
    END
  END k_wdata[168]
  PIN k_wdata[169]
    DIRECTION OUTPUT ;
    USE SIGNAL ;
    PORT
      LAYER M5 ;
        RECT  3.6 0 3.624 0.084 ;
    END
  END k_wdata[169]
  PIN k_wdata[16]
    DIRECTION OUTPUT ;
    USE SIGNAL ;
    PORT
      LAYER M5 ;
        RECT  26.544 0 26.568 0.084 ;
    END
  END k_wdata[16]
  PIN k_wdata[170]
    DIRECTION OUTPUT ;
    USE SIGNAL ;
    PORT
      LAYER M5 ;
        RECT  3.696 0 3.72 0.084 ;
    END
  END k_wdata[170]
  PIN k_wdata[171]
    DIRECTION OUTPUT ;
    USE SIGNAL ;
    PORT
      LAYER M5 ;
        RECT  22.992 0 23.016 0.084 ;
    END
  END k_wdata[171]
  PIN k_wdata[172]
    DIRECTION OUTPUT ;
    USE SIGNAL ;
    PORT
      LAYER M5 ;
        RECT  23.088 0 23.112 0.084 ;
    END
  END k_wdata[172]
  PIN k_wdata[173]
    DIRECTION OUTPUT ;
    USE SIGNAL ;
    PORT
      LAYER M5 ;
        RECT  23.184 0 23.208 0.084 ;
    END
  END k_wdata[173]
  PIN k_wdata[174]
    DIRECTION OUTPUT ;
    USE SIGNAL ;
    PORT
      LAYER M5 ;
        RECT  23.28 0 23.304 0.084 ;
    END
  END k_wdata[174]
  PIN k_wdata[175]
    DIRECTION OUTPUT ;
    USE SIGNAL ;
    PORT
      LAYER M5 ;
        RECT  23.376 0 23.4 0.084 ;
    END
  END k_wdata[175]
  PIN k_wdata[176]
    DIRECTION OUTPUT ;
    USE SIGNAL ;
    PORT
      LAYER M5 ;
        RECT  23.472 0 23.496 0.084 ;
    END
  END k_wdata[176]
  PIN k_wdata[177]
    DIRECTION OUTPUT ;
    USE SIGNAL ;
    PORT
      LAYER M5 ;
        RECT  23.568 0 23.592 0.084 ;
    END
  END k_wdata[177]
  PIN k_wdata[178]
    DIRECTION OUTPUT ;
    USE SIGNAL ;
    PORT
      LAYER M5 ;
        RECT  23.664 0 23.688 0.084 ;
    END
  END k_wdata[178]
  PIN k_wdata[179]
    DIRECTION OUTPUT ;
    USE SIGNAL ;
    PORT
      LAYER M5 ;
        RECT  23.76 0 23.784 0.084 ;
    END
  END k_wdata[179]
  PIN k_wdata[17]
    DIRECTION OUTPUT ;
    USE SIGNAL ;
    PORT
      LAYER M5 ;
        RECT  26.64 0 26.664 0.084 ;
    END
  END k_wdata[17]
  PIN k_wdata[180]
    DIRECTION OUTPUT ;
    USE SIGNAL ;
    PORT
      LAYER M5 ;
        RECT  23.856 0 23.88 0.084 ;
    END
  END k_wdata[180]
  PIN k_wdata[181]
    DIRECTION OUTPUT ;
    USE SIGNAL ;
    PORT
      LAYER M5 ;
        RECT  23.952 0 23.976 0.084 ;
    END
  END k_wdata[181]
  PIN k_wdata[182]
    DIRECTION OUTPUT ;
    USE SIGNAL ;
    PORT
      LAYER M5 ;
        RECT  24.048 0 24.072 0.084 ;
    END
  END k_wdata[182]
  PIN k_wdata[183]
    DIRECTION OUTPUT ;
    USE SIGNAL ;
    PORT
      LAYER M5 ;
        RECT  24.144 0 24.168 0.084 ;
    END
  END k_wdata[183]
  PIN k_wdata[184]
    DIRECTION OUTPUT ;
    USE SIGNAL ;
    PORT
      LAYER M5 ;
        RECT  24.24 0 24.264 0.084 ;
    END
  END k_wdata[184]
  PIN k_wdata[185]
    DIRECTION OUTPUT ;
    USE SIGNAL ;
    PORT
      LAYER M5 ;
        RECT  24.336 0 24.36 0.084 ;
    END
  END k_wdata[185]
  PIN k_wdata[186]
    DIRECTION OUTPUT ;
    USE SIGNAL ;
    PORT
      LAYER M5 ;
        RECT  24.432 0 24.456 0.084 ;
    END
  END k_wdata[186]
  PIN k_wdata[187]
    DIRECTION OUTPUT ;
    USE SIGNAL ;
    PORT
      LAYER M5 ;
        RECT  24.528 0 24.552 0.084 ;
    END
  END k_wdata[187]
  PIN k_wdata[188]
    DIRECTION OUTPUT ;
    USE SIGNAL ;
    PORT
      LAYER M5 ;
        RECT  24.624 0 24.648 0.084 ;
    END
  END k_wdata[188]
  PIN k_wdata[189]
    DIRECTION OUTPUT ;
    USE SIGNAL ;
    PORT
      LAYER M5 ;
        RECT  24.72 0 24.744 0.084 ;
    END
  END k_wdata[189]
  PIN k_wdata[18]
    DIRECTION OUTPUT ;
    USE SIGNAL ;
    PORT
      LAYER M5 ;
        RECT  26.736 0 26.76 0.084 ;
    END
  END k_wdata[18]
  PIN k_wdata[190]
    DIRECTION OUTPUT ;
    USE SIGNAL ;
    PORT
      LAYER M5 ;
        RECT  24.816 0 24.84 0.084 ;
    END
  END k_wdata[190]
  PIN k_wdata[191]
    DIRECTION OUTPUT ;
    USE SIGNAL ;
    PORT
      LAYER M5 ;
        RECT  24.912 0 24.936 0.084 ;
    END
  END k_wdata[191]
  PIN k_wdata[192]
    DIRECTION OUTPUT ;
    USE SIGNAL ;
    PORT
      LAYER M5 ;
        RECT  25.008 0 25.032 0.084 ;
    END
  END k_wdata[192]
  PIN k_wdata[193]
    DIRECTION OUTPUT ;
    USE SIGNAL ;
    PORT
      LAYER M5 ;
        RECT  25.104 0 25.128 0.084 ;
    END
  END k_wdata[193]
  PIN k_wdata[194]
    DIRECTION OUTPUT ;
    USE SIGNAL ;
    PORT
      LAYER M5 ;
        RECT  25.2 0 25.224 0.084 ;
    END
  END k_wdata[194]
  PIN k_wdata[195]
    DIRECTION OUTPUT ;
    USE SIGNAL ;
    PORT
      LAYER M5 ;
        RECT  25.296 0 25.32 0.084 ;
    END
  END k_wdata[195]
  PIN k_wdata[196]
    DIRECTION OUTPUT ;
    USE SIGNAL ;
    PORT
      LAYER M5 ;
        RECT  25.392 0 25.416 0.084 ;
    END
  END k_wdata[196]
  PIN k_wdata[197]
    DIRECTION OUTPUT ;
    USE SIGNAL ;
    PORT
      LAYER M5 ;
        RECT  25.488 0 25.512 0.084 ;
    END
  END k_wdata[197]
  PIN k_wdata[198]
    DIRECTION OUTPUT ;
    USE SIGNAL ;
    PORT
      LAYER M5 ;
        RECT  25.584 0 25.608 0.084 ;
    END
  END k_wdata[198]
  PIN k_wdata[199]
    DIRECTION OUTPUT ;
    USE SIGNAL ;
    PORT
      LAYER M5 ;
        RECT  25.68 0 25.704 0.084 ;
    END
  END k_wdata[199]
  PIN k_wdata[19]
    DIRECTION OUTPUT ;
    USE SIGNAL ;
    PORT
      LAYER M5 ;
        RECT  26.832 0 26.856 0.084 ;
    END
  END k_wdata[19]
  PIN k_wdata[1]
    DIRECTION OUTPUT ;
    USE SIGNAL ;
    PORT
      LAYER M5 ;
        RECT  15.12 0 15.144 0.084 ;
    END
  END k_wdata[1]
  PIN k_wdata[200]
    DIRECTION OUTPUT ;
    USE SIGNAL ;
    PORT
      LAYER M5 ;
        RECT  25.776 0 25.8 0.084 ;
    END
  END k_wdata[200]
  PIN k_wdata[201]
    DIRECTION OUTPUT ;
    USE SIGNAL ;
    PORT
      LAYER M5 ;
        RECT  25.872 0 25.896 0.084 ;
    END
  END k_wdata[201]
  PIN k_wdata[202]
    DIRECTION OUTPUT ;
    USE SIGNAL ;
    PORT
      LAYER M5 ;
        RECT  25.968 0 25.992 0.084 ;
    END
  END k_wdata[202]
  PIN k_wdata[203]
    DIRECTION OUTPUT ;
    USE SIGNAL ;
    PORT
      LAYER M5 ;
        RECT  29.136 0 29.16 0.084 ;
    END
  END k_wdata[203]
  PIN k_wdata[204]
    DIRECTION OUTPUT ;
    USE SIGNAL ;
    PORT
      LAYER M5 ;
        RECT  29.232 0 29.256 0.084 ;
    END
  END k_wdata[204]
  PIN k_wdata[205]
    DIRECTION OUTPUT ;
    USE SIGNAL ;
    PORT
      LAYER M5 ;
        RECT  29.328 0 29.352 0.084 ;
    END
  END k_wdata[205]
  PIN k_wdata[206]
    DIRECTION OUTPUT ;
    USE SIGNAL ;
    PORT
      LAYER M5 ;
        RECT  29.424 0 29.448 0.084 ;
    END
  END k_wdata[206]
  PIN k_wdata[207]
    DIRECTION OUTPUT ;
    USE SIGNAL ;
    PORT
      LAYER M5 ;
        RECT  29.52 0 29.544 0.084 ;
    END
  END k_wdata[207]
  PIN k_wdata[208]
    DIRECTION OUTPUT ;
    USE SIGNAL ;
    PORT
      LAYER M5 ;
        RECT  29.616 0 29.64 0.084 ;
    END
  END k_wdata[208]
  PIN k_wdata[209]
    DIRECTION OUTPUT ;
    USE SIGNAL ;
    PORT
      LAYER M5 ;
        RECT  29.712 0 29.736 0.084 ;
    END
  END k_wdata[209]
  PIN k_wdata[20]
    DIRECTION OUTPUT ;
    USE SIGNAL ;
    PORT
      LAYER M5 ;
        RECT  26.928 0 26.952 0.084 ;
    END
  END k_wdata[20]
  PIN k_wdata[210]
    DIRECTION OUTPUT ;
    USE SIGNAL ;
    PORT
      LAYER M5 ;
        RECT  29.808 0 29.832 0.084 ;
    END
  END k_wdata[210]
  PIN k_wdata[211]
    DIRECTION OUTPUT ;
    USE SIGNAL ;
    PORT
      LAYER M5 ;
        RECT  29.904 0 29.928 0.084 ;
    END
  END k_wdata[211]
  PIN k_wdata[212]
    DIRECTION OUTPUT ;
    USE SIGNAL ;
    PORT
      LAYER M5 ;
        RECT  30 0 30.024 0.084 ;
    END
  END k_wdata[212]
  PIN k_wdata[213]
    DIRECTION OUTPUT ;
    USE SIGNAL ;
    PORT
      LAYER M5 ;
        RECT  30.096 0 30.12 0.084 ;
    END
  END k_wdata[213]
  PIN k_wdata[214]
    DIRECTION OUTPUT ;
    USE SIGNAL ;
    PORT
      LAYER M5 ;
        RECT  30.192 0 30.216 0.084 ;
    END
  END k_wdata[214]
  PIN k_wdata[215]
    DIRECTION OUTPUT ;
    USE SIGNAL ;
    PORT
      LAYER M5 ;
        RECT  30.288 0 30.312 0.084 ;
    END
  END k_wdata[215]
  PIN k_wdata[216]
    DIRECTION OUTPUT ;
    USE SIGNAL ;
    PORT
      LAYER M5 ;
        RECT  30.384 0 30.408 0.084 ;
    END
  END k_wdata[216]
  PIN k_wdata[217]
    DIRECTION OUTPUT ;
    USE SIGNAL ;
    PORT
      LAYER M5 ;
        RECT  30.48 0 30.504 0.084 ;
    END
  END k_wdata[217]
  PIN k_wdata[218]
    DIRECTION OUTPUT ;
    USE SIGNAL ;
    PORT
      LAYER M5 ;
        RECT  30.576 0 30.6 0.084 ;
    END
  END k_wdata[218]
  PIN k_wdata[219]
    DIRECTION OUTPUT ;
    USE SIGNAL ;
    PORT
      LAYER M5 ;
        RECT  30.672 0 30.696 0.084 ;
    END
  END k_wdata[219]
  PIN k_wdata[21]
    DIRECTION OUTPUT ;
    USE SIGNAL ;
    PORT
      LAYER M5 ;
        RECT  27.024 0 27.048 0.084 ;
    END
  END k_wdata[21]
  PIN k_wdata[220]
    DIRECTION OUTPUT ;
    USE SIGNAL ;
    PORT
      LAYER M5 ;
        RECT  30.768 0 30.792 0.084 ;
    END
  END k_wdata[220]
  PIN k_wdata[221]
    DIRECTION OUTPUT ;
    USE SIGNAL ;
    PORT
      LAYER M5 ;
        RECT  30.864 0 30.888 0.084 ;
    END
  END k_wdata[221]
  PIN k_wdata[222]
    DIRECTION OUTPUT ;
    USE SIGNAL ;
    PORT
      LAYER M5 ;
        RECT  30.96 0 30.984 0.084 ;
    END
  END k_wdata[222]
  PIN k_wdata[223]
    DIRECTION OUTPUT ;
    USE SIGNAL ;
    PORT
      LAYER M5 ;
        RECT  31.056 0 31.08 0.084 ;
    END
  END k_wdata[223]
  PIN k_wdata[224]
    DIRECTION OUTPUT ;
    USE SIGNAL ;
    PORT
      LAYER M5 ;
        RECT  31.152 0 31.176 0.084 ;
    END
  END k_wdata[224]
  PIN k_wdata[225]
    DIRECTION OUTPUT ;
    USE SIGNAL ;
    PORT
      LAYER M5 ;
        RECT  31.248 0 31.272 0.084 ;
    END
  END k_wdata[225]
  PIN k_wdata[226]
    DIRECTION OUTPUT ;
    USE SIGNAL ;
    PORT
      LAYER M5 ;
        RECT  31.344 0 31.368 0.084 ;
    END
  END k_wdata[226]
  PIN k_wdata[227]
    DIRECTION OUTPUT ;
    USE SIGNAL ;
    PORT
      LAYER M5 ;
        RECT  31.44 0 31.464 0.084 ;
    END
  END k_wdata[227]
  PIN k_wdata[228]
    DIRECTION OUTPUT ;
    USE SIGNAL ;
    PORT
      LAYER M5 ;
        RECT  31.536 0 31.56 0.084 ;
    END
  END k_wdata[228]
  PIN k_wdata[229]
    DIRECTION OUTPUT ;
    USE SIGNAL ;
    PORT
      LAYER M5 ;
        RECT  31.632 0 31.656 0.084 ;
    END
  END k_wdata[229]
  PIN k_wdata[22]
    DIRECTION OUTPUT ;
    USE SIGNAL ;
    PORT
      LAYER M5 ;
        RECT  27.12 0 27.144 0.084 ;
    END
  END k_wdata[22]
  PIN k_wdata[230]
    DIRECTION OUTPUT ;
    USE SIGNAL ;
    PORT
      LAYER M5 ;
        RECT  31.728 0 31.752 0.084 ;
    END
  END k_wdata[230]
  PIN k_wdata[231]
    DIRECTION OUTPUT ;
    USE SIGNAL ;
    PORT
      LAYER M5 ;
        RECT  31.824 0 31.848 0.084 ;
    END
  END k_wdata[231]
  PIN k_wdata[232]
    DIRECTION OUTPUT ;
    USE SIGNAL ;
    PORT
      LAYER M5 ;
        RECT  31.92 0 31.944 0.084 ;
    END
  END k_wdata[232]
  PIN k_wdata[233]
    DIRECTION OUTPUT ;
    USE SIGNAL ;
    PORT
      LAYER M5 ;
        RECT  32.016 0 32.04 0.084 ;
    END
  END k_wdata[233]
  PIN k_wdata[234]
    DIRECTION OUTPUT ;
    USE SIGNAL ;
    PORT
      LAYER M5 ;
        RECT  32.112 0 32.136 0.084 ;
    END
  END k_wdata[234]
  PIN k_wdata[235]
    DIRECTION OUTPUT ;
    USE SIGNAL ;
    PORT
      LAYER M5 ;
        RECT  35.28 0 35.304 0.084 ;
    END
  END k_wdata[235]
  PIN k_wdata[236]
    DIRECTION OUTPUT ;
    USE SIGNAL ;
    PORT
      LAYER M5 ;
        RECT  35.376 0 35.4 0.084 ;
    END
  END k_wdata[236]
  PIN k_wdata[237]
    DIRECTION OUTPUT ;
    USE SIGNAL ;
    PORT
      LAYER M5 ;
        RECT  35.472 0 35.496 0.084 ;
    END
  END k_wdata[237]
  PIN k_wdata[238]
    DIRECTION OUTPUT ;
    USE SIGNAL ;
    PORT
      LAYER M5 ;
        RECT  35.568 0 35.592 0.084 ;
    END
  END k_wdata[238]
  PIN k_wdata[239]
    DIRECTION OUTPUT ;
    USE SIGNAL ;
    PORT
      LAYER M5 ;
        RECT  35.664 0 35.688 0.084 ;
    END
  END k_wdata[239]
  PIN k_wdata[23]
    DIRECTION OUTPUT ;
    USE SIGNAL ;
    PORT
      LAYER M5 ;
        RECT  27.216 0 27.24 0.084 ;
    END
  END k_wdata[23]
  PIN k_wdata[240]
    DIRECTION OUTPUT ;
    USE SIGNAL ;
    PORT
      LAYER M5 ;
        RECT  35.76 0 35.784 0.084 ;
    END
  END k_wdata[240]
  PIN k_wdata[241]
    DIRECTION OUTPUT ;
    USE SIGNAL ;
    PORT
      LAYER M5 ;
        RECT  35.856 0 35.88 0.084 ;
    END
  END k_wdata[241]
  PIN k_wdata[242]
    DIRECTION OUTPUT ;
    USE SIGNAL ;
    PORT
      LAYER M5 ;
        RECT  35.952 0 35.976 0.084 ;
    END
  END k_wdata[242]
  PIN k_wdata[243]
    DIRECTION OUTPUT ;
    USE SIGNAL ;
    PORT
      LAYER M5 ;
        RECT  36.048 0 36.072 0.084 ;
    END
  END k_wdata[243]
  PIN k_wdata[244]
    DIRECTION OUTPUT ;
    USE SIGNAL ;
    PORT
      LAYER M5 ;
        RECT  36.144 0 36.168 0.084 ;
    END
  END k_wdata[244]
  PIN k_wdata[245]
    DIRECTION OUTPUT ;
    USE SIGNAL ;
    PORT
      LAYER M5 ;
        RECT  36.24 0 36.264 0.084 ;
    END
  END k_wdata[245]
  PIN k_wdata[246]
    DIRECTION OUTPUT ;
    USE SIGNAL ;
    PORT
      LAYER M5 ;
        RECT  36.336 0 36.36 0.084 ;
    END
  END k_wdata[246]
  PIN k_wdata[247]
    DIRECTION OUTPUT ;
    USE SIGNAL ;
    PORT
      LAYER M5 ;
        RECT  36.432 0 36.456 0.084 ;
    END
  END k_wdata[247]
  PIN k_wdata[248]
    DIRECTION OUTPUT ;
    USE SIGNAL ;
    PORT
      LAYER M5 ;
        RECT  36.528 0 36.552 0.084 ;
    END
  END k_wdata[248]
  PIN k_wdata[249]
    DIRECTION OUTPUT ;
    USE SIGNAL ;
    PORT
      LAYER M5 ;
        RECT  36.624 0 36.648 0.084 ;
    END
  END k_wdata[249]
  PIN k_wdata[24]
    DIRECTION OUTPUT ;
    USE SIGNAL ;
    PORT
      LAYER M5 ;
        RECT  27.312 0 27.336 0.084 ;
    END
  END k_wdata[24]
  PIN k_wdata[250]
    DIRECTION OUTPUT ;
    USE SIGNAL ;
    PORT
      LAYER M5 ;
        RECT  36.72 0 36.744 0.084 ;
    END
  END k_wdata[250]
  PIN k_wdata[251]
    DIRECTION OUTPUT ;
    USE SIGNAL ;
    PORT
      LAYER M5 ;
        RECT  36.816 0 36.84 0.084 ;
    END
  END k_wdata[251]
  PIN k_wdata[252]
    DIRECTION OUTPUT ;
    USE SIGNAL ;
    PORT
      LAYER M5 ;
        RECT  36.912 0 36.936 0.084 ;
    END
  END k_wdata[252]
  PIN k_wdata[253]
    DIRECTION OUTPUT ;
    USE SIGNAL ;
    PORT
      LAYER M5 ;
        RECT  37.008 0 37.032 0.084 ;
    END
  END k_wdata[253]
  PIN k_wdata[254]
    DIRECTION OUTPUT ;
    USE SIGNAL ;
    PORT
      LAYER M5 ;
        RECT  37.104 0 37.128 0.084 ;
    END
  END k_wdata[254]
  PIN k_wdata[255]
    DIRECTION OUTPUT ;
    USE SIGNAL ;
    PORT
      LAYER M5 ;
        RECT  37.2 0 37.224 0.084 ;
    END
  END k_wdata[255]
  PIN k_wdata[25]
    DIRECTION OUTPUT ;
    USE SIGNAL ;
    PORT
      LAYER M5 ;
        RECT  27.408 0 27.432 0.084 ;
    END
  END k_wdata[25]
  PIN k_wdata[26]
    DIRECTION OUTPUT ;
    USE SIGNAL ;
    PORT
      LAYER M5 ;
        RECT  27.504 0 27.528 0.084 ;
    END
  END k_wdata[26]
  PIN k_wdata[27]
    DIRECTION OUTPUT ;
    USE SIGNAL ;
    PORT
      LAYER M5 ;
        RECT  27.6 0 27.624 0.084 ;
    END
  END k_wdata[27]
  PIN k_wdata[28]
    DIRECTION OUTPUT ;
    USE SIGNAL ;
    PORT
      LAYER M5 ;
        RECT  27.696 0 27.72 0.084 ;
    END
  END k_wdata[28]
  PIN k_wdata[29]
    DIRECTION OUTPUT ;
    USE SIGNAL ;
    PORT
      LAYER M5 ;
        RECT  27.792 0 27.816 0.084 ;
    END
  END k_wdata[29]
  PIN k_wdata[2]
    DIRECTION OUTPUT ;
    USE SIGNAL ;
    PORT
      LAYER M5 ;
        RECT  15.216 0 15.24 0.084 ;
    END
  END k_wdata[2]
  PIN k_wdata[30]
    DIRECTION OUTPUT ;
    USE SIGNAL ;
    PORT
      LAYER M5 ;
        RECT  27.888 0 27.912 0.084 ;
    END
  END k_wdata[30]
  PIN k_wdata[31]
    DIRECTION OUTPUT ;
    USE SIGNAL ;
    PORT
      LAYER M5 ;
        RECT  27.984 0 28.008 0.084 ;
    END
  END k_wdata[31]
  PIN k_wdata[32]
    DIRECTION OUTPUT ;
    USE SIGNAL ;
    PORT
      LAYER M5 ;
        RECT  28.08 0 28.104 0.084 ;
    END
  END k_wdata[32]
  PIN k_wdata[33]
    DIRECTION OUTPUT ;
    USE SIGNAL ;
    PORT
      LAYER M5 ;
        RECT  28.176 0 28.2 0.084 ;
    END
  END k_wdata[33]
  PIN k_wdata[34]
    DIRECTION OUTPUT ;
    USE SIGNAL ;
    PORT
      LAYER M5 ;
        RECT  28.272 0 28.296 0.084 ;
    END
  END k_wdata[34]
  PIN k_wdata[35]
    DIRECTION OUTPUT ;
    USE SIGNAL ;
    PORT
      LAYER M5 ;
        RECT  28.368 0 28.392 0.084 ;
    END
  END k_wdata[35]
  PIN k_wdata[36]
    DIRECTION OUTPUT ;
    USE SIGNAL ;
    PORT
      LAYER M5 ;
        RECT  28.464 0 28.488 0.084 ;
    END
  END k_wdata[36]
  PIN k_wdata[37]
    DIRECTION OUTPUT ;
    USE SIGNAL ;
    PORT
      LAYER M5 ;
        RECT  28.56 0 28.584 0.084 ;
    END
  END k_wdata[37]
  PIN k_wdata[38]
    DIRECTION OUTPUT ;
    USE SIGNAL ;
    PORT
      LAYER M5 ;
        RECT  28.656 0 28.68 0.084 ;
    END
  END k_wdata[38]
  PIN k_wdata[39]
    DIRECTION OUTPUT ;
    USE SIGNAL ;
    PORT
      LAYER M5 ;
        RECT  28.752 0 28.776 0.084 ;
    END
  END k_wdata[39]
  PIN k_wdata[3]
    DIRECTION OUTPUT ;
    USE SIGNAL ;
    PORT
      LAYER M5 ;
        RECT  15.312 0 15.336 0.084 ;
    END
  END k_wdata[3]
  PIN k_wdata[40]
    DIRECTION OUTPUT ;
    USE SIGNAL ;
    PORT
      LAYER M5 ;
        RECT  28.848 0 28.872 0.084 ;
    END
  END k_wdata[40]
  PIN k_wdata[41]
    DIRECTION OUTPUT ;
    USE SIGNAL ;
    PORT
      LAYER M5 ;
        RECT  28.944 0 28.968 0.084 ;
    END
  END k_wdata[41]
  PIN k_wdata[42]
    DIRECTION OUTPUT ;
    USE SIGNAL ;
    PORT
      LAYER M5 ;
        RECT  29.04 0 29.064 0.084 ;
    END
  END k_wdata[42]
  PIN k_wdata[43]
    DIRECTION OUTPUT ;
    USE SIGNAL ;
    PORT
      LAYER M5 ;
        RECT  9.936 0 9.96 0.084 ;
    END
  END k_wdata[43]
  PIN k_wdata[44]
    DIRECTION OUTPUT ;
    USE SIGNAL ;
    PORT
      LAYER M5 ;
        RECT  10.032 0 10.056 0.084 ;
    END
  END k_wdata[44]
  PIN k_wdata[45]
    DIRECTION OUTPUT ;
    USE SIGNAL ;
    PORT
      LAYER M5 ;
        RECT  10.128 0 10.152 0.084 ;
    END
  END k_wdata[45]
  PIN k_wdata[46]
    DIRECTION OUTPUT ;
    USE SIGNAL ;
    PORT
      LAYER M5 ;
        RECT  10.224 0 10.248 0.084 ;
    END
  END k_wdata[46]
  PIN k_wdata[47]
    DIRECTION OUTPUT ;
    USE SIGNAL ;
    PORT
      LAYER M5 ;
        RECT  10.32 0 10.344 0.084 ;
    END
  END k_wdata[47]
  PIN k_wdata[48]
    DIRECTION OUTPUT ;
    USE SIGNAL ;
    PORT
      LAYER M5 ;
        RECT  10.416 0 10.44 0.084 ;
    END
  END k_wdata[48]
  PIN k_wdata[49]
    DIRECTION OUTPUT ;
    USE SIGNAL ;
    PORT
      LAYER M5 ;
        RECT  10.512 0 10.536 0.084 ;
    END
  END k_wdata[49]
  PIN k_wdata[4]
    DIRECTION OUTPUT ;
    USE SIGNAL ;
    PORT
      LAYER M5 ;
        RECT  15.408 0 15.432 0.084 ;
    END
  END k_wdata[4]
  PIN k_wdata[50]
    DIRECTION OUTPUT ;
    USE SIGNAL ;
    PORT
      LAYER M5 ;
        RECT  10.608 0 10.632 0.084 ;
    END
  END k_wdata[50]
  PIN k_wdata[51]
    DIRECTION OUTPUT ;
    USE SIGNAL ;
    PORT
      LAYER M5 ;
        RECT  10.704 0 10.728 0.084 ;
    END
  END k_wdata[51]
  PIN k_wdata[52]
    DIRECTION OUTPUT ;
    USE SIGNAL ;
    PORT
      LAYER M5 ;
        RECT  10.8 0 10.824 0.084 ;
    END
  END k_wdata[52]
  PIN k_wdata[53]
    DIRECTION OUTPUT ;
    USE SIGNAL ;
    PORT
      LAYER M5 ;
        RECT  10.896 0 10.92 0.084 ;
    END
  END k_wdata[53]
  PIN k_wdata[54]
    DIRECTION OUTPUT ;
    USE SIGNAL ;
    PORT
      LAYER M5 ;
        RECT  10.992 0 11.016 0.084 ;
    END
  END k_wdata[54]
  PIN k_wdata[55]
    DIRECTION OUTPUT ;
    USE SIGNAL ;
    PORT
      LAYER M5 ;
        RECT  11.088 0 11.112 0.084 ;
    END
  END k_wdata[55]
  PIN k_wdata[56]
    DIRECTION OUTPUT ;
    USE SIGNAL ;
    PORT
      LAYER M5 ;
        RECT  11.184 0 11.208 0.084 ;
    END
  END k_wdata[56]
  PIN k_wdata[57]
    DIRECTION OUTPUT ;
    USE SIGNAL ;
    PORT
      LAYER M5 ;
        RECT  11.28 0 11.304 0.084 ;
    END
  END k_wdata[57]
  PIN k_wdata[58]
    DIRECTION OUTPUT ;
    USE SIGNAL ;
    PORT
      LAYER M5 ;
        RECT  11.376 0 11.4 0.084 ;
    END
  END k_wdata[58]
  PIN k_wdata[59]
    DIRECTION OUTPUT ;
    USE SIGNAL ;
    PORT
      LAYER M5 ;
        RECT  11.472 0 11.496 0.084 ;
    END
  END k_wdata[59]
  PIN k_wdata[5]
    DIRECTION OUTPUT ;
    USE SIGNAL ;
    PORT
      LAYER M5 ;
        RECT  15.504 0 15.528 0.084 ;
    END
  END k_wdata[5]
  PIN k_wdata[60]
    DIRECTION OUTPUT ;
    USE SIGNAL ;
    PORT
      LAYER M5 ;
        RECT  11.568 0 11.592 0.084 ;
    END
  END k_wdata[60]
  PIN k_wdata[61]
    DIRECTION OUTPUT ;
    USE SIGNAL ;
    PORT
      LAYER M5 ;
        RECT  11.664 0 11.688 0.084 ;
    END
  END k_wdata[61]
  PIN k_wdata[62]
    DIRECTION OUTPUT ;
    USE SIGNAL ;
    PORT
      LAYER M5 ;
        RECT  11.76 0 11.784 0.084 ;
    END
  END k_wdata[62]
  PIN k_wdata[63]
    DIRECTION OUTPUT ;
    USE SIGNAL ;
    PORT
      LAYER M5 ;
        RECT  11.856 0 11.88 0.084 ;
    END
  END k_wdata[63]
  PIN k_wdata[64]
    DIRECTION OUTPUT ;
    USE SIGNAL ;
    PORT
      LAYER M5 ;
        RECT  11.952 0 11.976 0.084 ;
    END
  END k_wdata[64]
  PIN k_wdata[65]
    DIRECTION OUTPUT ;
    USE SIGNAL ;
    PORT
      LAYER M5 ;
        RECT  12.048 0 12.072 0.084 ;
    END
  END k_wdata[65]
  PIN k_wdata[66]
    DIRECTION OUTPUT ;
    USE SIGNAL ;
    PORT
      LAYER M5 ;
        RECT  12.144 0 12.168 0.084 ;
    END
  END k_wdata[66]
  PIN k_wdata[67]
    DIRECTION OUTPUT ;
    USE SIGNAL ;
    PORT
      LAYER M5 ;
        RECT  12.24 0 12.264 0.084 ;
    END
  END k_wdata[67]
  PIN k_wdata[68]
    DIRECTION OUTPUT ;
    USE SIGNAL ;
    PORT
      LAYER M5 ;
        RECT  12.336 0 12.36 0.084 ;
    END
  END k_wdata[68]
  PIN k_wdata[69]
    DIRECTION OUTPUT ;
    USE SIGNAL ;
    PORT
      LAYER M5 ;
        RECT  12.432 0 12.456 0.084 ;
    END
  END k_wdata[69]
  PIN k_wdata[6]
    DIRECTION OUTPUT ;
    USE SIGNAL ;
    PORT
      LAYER M5 ;
        RECT  15.6 0 15.624 0.084 ;
    END
  END k_wdata[6]
  PIN k_wdata[70]
    DIRECTION OUTPUT ;
    USE SIGNAL ;
    PORT
      LAYER M5 ;
        RECT  12.528 0 12.552 0.084 ;
    END
  END k_wdata[70]
  PIN k_wdata[71]
    DIRECTION OUTPUT ;
    USE SIGNAL ;
    PORT
      LAYER M5 ;
        RECT  12.624 0 12.648 0.084 ;
    END
  END k_wdata[71]
  PIN k_wdata[72]
    DIRECTION OUTPUT ;
    USE SIGNAL ;
    PORT
      LAYER M5 ;
        RECT  12.72 0 12.744 0.084 ;
    END
  END k_wdata[72]
  PIN k_wdata[73]
    DIRECTION OUTPUT ;
    USE SIGNAL ;
    PORT
      LAYER M5 ;
        RECT  12.816 0 12.84 0.084 ;
    END
  END k_wdata[73]
  PIN k_wdata[74]
    DIRECTION OUTPUT ;
    USE SIGNAL ;
    PORT
      LAYER M5 ;
        RECT  12.912 0 12.936 0.084 ;
    END
  END k_wdata[74]
  PIN k_wdata[75]
    DIRECTION OUTPUT ;
    USE SIGNAL ;
    PORT
      LAYER M5 ;
        RECT  6.864 0 6.888 0.084 ;
    END
  END k_wdata[75]
  PIN k_wdata[76]
    DIRECTION OUTPUT ;
    USE SIGNAL ;
    PORT
      LAYER M5 ;
        RECT  6.96 0 6.984 0.084 ;
    END
  END k_wdata[76]
  PIN k_wdata[77]
    DIRECTION OUTPUT ;
    USE SIGNAL ;
    PORT
      LAYER M5 ;
        RECT  7.056 0 7.08 0.084 ;
    END
  END k_wdata[77]
  PIN k_wdata[78]
    DIRECTION OUTPUT ;
    USE SIGNAL ;
    PORT
      LAYER M5 ;
        RECT  7.152 0 7.176 0.084 ;
    END
  END k_wdata[78]
  PIN k_wdata[79]
    DIRECTION OUTPUT ;
    USE SIGNAL ;
    PORT
      LAYER M5 ;
        RECT  7.248 0 7.272 0.084 ;
    END
  END k_wdata[79]
  PIN k_wdata[7]
    DIRECTION OUTPUT ;
    USE SIGNAL ;
    PORT
      LAYER M5 ;
        RECT  15.696 0 15.72 0.084 ;
    END
  END k_wdata[7]
  PIN k_wdata[80]
    DIRECTION OUTPUT ;
    USE SIGNAL ;
    PORT
      LAYER M5 ;
        RECT  7.344 0 7.368 0.084 ;
    END
  END k_wdata[80]
  PIN k_wdata[81]
    DIRECTION OUTPUT ;
    USE SIGNAL ;
    PORT
      LAYER M5 ;
        RECT  7.44 0 7.464 0.084 ;
    END
  END k_wdata[81]
  PIN k_wdata[82]
    DIRECTION OUTPUT ;
    USE SIGNAL ;
    PORT
      LAYER M5 ;
        RECT  7.536 0 7.56 0.084 ;
    END
  END k_wdata[82]
  PIN k_wdata[83]
    DIRECTION OUTPUT ;
    USE SIGNAL ;
    PORT
      LAYER M5 ;
        RECT  7.632 0 7.656 0.084 ;
    END
  END k_wdata[83]
  PIN k_wdata[84]
    DIRECTION OUTPUT ;
    USE SIGNAL ;
    PORT
      LAYER M5 ;
        RECT  7.728 0 7.752 0.084 ;
    END
  END k_wdata[84]
  PIN k_wdata[85]
    DIRECTION OUTPUT ;
    USE SIGNAL ;
    PORT
      LAYER M5 ;
        RECT  7.824 0 7.848 0.084 ;
    END
  END k_wdata[85]
  PIN k_wdata[86]
    DIRECTION OUTPUT ;
    USE SIGNAL ;
    PORT
      LAYER M5 ;
        RECT  7.92 0 7.944 0.084 ;
    END
  END k_wdata[86]
  PIN k_wdata[87]
    DIRECTION OUTPUT ;
    USE SIGNAL ;
    PORT
      LAYER M5 ;
        RECT  8.016 0 8.04 0.084 ;
    END
  END k_wdata[87]
  PIN k_wdata[88]
    DIRECTION OUTPUT ;
    USE SIGNAL ;
    PORT
      LAYER M5 ;
        RECT  8.112 0 8.136 0.084 ;
    END
  END k_wdata[88]
  PIN k_wdata[89]
    DIRECTION OUTPUT ;
    USE SIGNAL ;
    PORT
      LAYER M5 ;
        RECT  8.208 0 8.232 0.084 ;
    END
  END k_wdata[89]
  PIN k_wdata[8]
    DIRECTION OUTPUT ;
    USE SIGNAL ;
    PORT
      LAYER M5 ;
        RECT  15.792 0 15.816 0.084 ;
    END
  END k_wdata[8]
  PIN k_wdata[90]
    DIRECTION OUTPUT ;
    USE SIGNAL ;
    PORT
      LAYER M5 ;
        RECT  8.304 0 8.328 0.084 ;
    END
  END k_wdata[90]
  PIN k_wdata[91]
    DIRECTION OUTPUT ;
    USE SIGNAL ;
    PORT
      LAYER M5 ;
        RECT  8.4 0 8.424 0.084 ;
    END
  END k_wdata[91]
  PIN k_wdata[92]
    DIRECTION OUTPUT ;
    USE SIGNAL ;
    PORT
      LAYER M5 ;
        RECT  8.496 0 8.52 0.084 ;
    END
  END k_wdata[92]
  PIN k_wdata[93]
    DIRECTION OUTPUT ;
    USE SIGNAL ;
    PORT
      LAYER M5 ;
        RECT  8.592 0 8.616 0.084 ;
    END
  END k_wdata[93]
  PIN k_wdata[94]
    DIRECTION OUTPUT ;
    USE SIGNAL ;
    PORT
      LAYER M5 ;
        RECT  8.688 0 8.712 0.084 ;
    END
  END k_wdata[94]
  PIN k_wdata[95]
    DIRECTION OUTPUT ;
    USE SIGNAL ;
    PORT
      LAYER M5 ;
        RECT  8.784 0 8.808 0.084 ;
    END
  END k_wdata[95]
  PIN k_wdata[96]
    DIRECTION OUTPUT ;
    USE SIGNAL ;
    PORT
      LAYER M5 ;
        RECT  8.88 0 8.904 0.084 ;
    END
  END k_wdata[96]
  PIN k_wdata[97]
    DIRECTION OUTPUT ;
    USE SIGNAL ;
    PORT
      LAYER M5 ;
        RECT  8.976 0 9 0.084 ;
    END
  END k_wdata[97]
  PIN k_wdata[98]
    DIRECTION OUTPUT ;
    USE SIGNAL ;
    PORT
      LAYER M5 ;
        RECT  9.072 0 9.096 0.084 ;
    END
  END k_wdata[98]
  PIN k_wdata[99]
    DIRECTION OUTPUT ;
    USE SIGNAL ;
    PORT
      LAYER M5 ;
        RECT  9.168 0 9.192 0.084 ;
    END
  END k_wdata[99]
  PIN k_wdata[9]
    DIRECTION OUTPUT ;
    USE SIGNAL ;
    PORT
      LAYER M5 ;
        RECT  15.888 0 15.912 0.084 ;
    END
  END k_wdata[9]
  PIN k_we
    DIRECTION OUTPUT ;
    USE SIGNAL ;
    PORT
      LAYER M5 ;
        RECT  37.296 0 37.32 0.084 ;
    END
  END k_we
  PIN k_wr_done
    DIRECTION INPUT ;
    USE SIGNAL ;
    PORT
      LAYER M5 ;
        RECT  37.392 0 37.416 0.084 ;
    END
  END k_wr_done
  PIN k_wstrb[0]
    DIRECTION OUTPUT ;
    USE SIGNAL ;
    PORT
      LAYER M5 ;
        RECT  37.488 0 37.512 0.084 ;
    END
  END k_wstrb[0]
  PIN k_wstrb[10]
    DIRECTION OUTPUT ;
    USE SIGNAL ;
    PORT
      LAYER M5 ;
        RECT  92.976 0 93 0.084 ;
    END
  END k_wstrb[10]
  PIN k_wstrb[11]
    DIRECTION OUTPUT ;
    USE SIGNAL ;
    PORT
      LAYER M5 ;
        RECT  93.072 0 93.096 0.084 ;
    END
  END k_wstrb[11]
  PIN k_wstrb[12]
    DIRECTION OUTPUT ;
    USE SIGNAL ;
    PORT
      LAYER M5 ;
        RECT  93.168 0 93.192 0.084 ;
    END
  END k_wstrb[12]
  PIN k_wstrb[13]
    DIRECTION OUTPUT ;
    USE SIGNAL ;
    PORT
      LAYER M5 ;
        RECT  93.264 0 93.288 0.084 ;
    END
  END k_wstrb[13]
  PIN k_wstrb[14]
    DIRECTION OUTPUT ;
    USE SIGNAL ;
    PORT
      LAYER M5 ;
        RECT  93.36 0 93.384 0.084 ;
    END
  END k_wstrb[14]
  PIN k_wstrb[15]
    DIRECTION OUTPUT ;
    USE SIGNAL ;
    PORT
      LAYER M5 ;
        RECT  93.456 0 93.48 0.084 ;
    END
  END k_wstrb[15]
  PIN k_wstrb[16]
    DIRECTION OUTPUT ;
    USE SIGNAL ;
    PORT
      LAYER M5 ;
        RECT  93.552 0 93.576 0.084 ;
    END
  END k_wstrb[16]
  PIN k_wstrb[17]
    DIRECTION OUTPUT ;
    USE SIGNAL ;
    PORT
      LAYER M5 ;
        RECT  93.648 0 93.672 0.084 ;
    END
  END k_wstrb[17]
  PIN k_wstrb[18]
    DIRECTION OUTPUT ;
    USE SIGNAL ;
    PORT
      LAYER M5 ;
        RECT  93.744 0 93.768 0.084 ;
    END
  END k_wstrb[18]
  PIN k_wstrb[19]
    DIRECTION OUTPUT ;
    USE SIGNAL ;
    PORT
      LAYER M5 ;
        RECT  93.84 0 93.864 0.084 ;
    END
  END k_wstrb[19]
  PIN k_wstrb[1]
    DIRECTION OUTPUT ;
    USE SIGNAL ;
    PORT
      LAYER M5 ;
        RECT  37.584 0 37.608 0.084 ;
    END
  END k_wstrb[1]
  PIN k_wstrb[20]
    DIRECTION OUTPUT ;
    USE SIGNAL ;
    PORT
      LAYER M5 ;
        RECT  93.936 0 93.96 0.084 ;
    END
  END k_wstrb[20]
  PIN k_wstrb[21]
    DIRECTION OUTPUT ;
    USE SIGNAL ;
    PORT
      LAYER M5 ;
        RECT  94.032 0 94.056 0.084 ;
    END
  END k_wstrb[21]
  PIN k_wstrb[22]
    DIRECTION OUTPUT ;
    USE SIGNAL ;
    PORT
      LAYER M5 ;
        RECT  94.128 0 94.152 0.084 ;
    END
  END k_wstrb[22]
  PIN k_wstrb[23]
    DIRECTION OUTPUT ;
    USE SIGNAL ;
    PORT
      LAYER M5 ;
        RECT  94.224 0 94.248 0.084 ;
    END
  END k_wstrb[23]
  PIN k_wstrb[24]
    DIRECTION OUTPUT ;
    USE SIGNAL ;
    PORT
      LAYER M5 ;
        RECT  94.32 0 94.344 0.084 ;
    END
  END k_wstrb[24]
  PIN k_wstrb[25]
    DIRECTION OUTPUT ;
    USE SIGNAL ;
    PORT
      LAYER M5 ;
        RECT  94.416 0 94.44 0.084 ;
    END
  END k_wstrb[25]
  PIN k_wstrb[26]
    DIRECTION OUTPUT ;
    USE SIGNAL ;
    PORT
      LAYER M5 ;
        RECT  94.512 0 94.536 0.084 ;
    END
  END k_wstrb[26]
  PIN k_wstrb[27]
    DIRECTION OUTPUT ;
    USE SIGNAL ;
    PORT
      LAYER M5 ;
        RECT  94.608 0 94.632 0.084 ;
    END
  END k_wstrb[27]
  PIN k_wstrb[28]
    DIRECTION OUTPUT ;
    USE SIGNAL ;
    PORT
      LAYER M5 ;
        RECT  94.704 0 94.728 0.084 ;
    END
  END k_wstrb[28]
  PIN k_wstrb[29]
    DIRECTION OUTPUT ;
    USE SIGNAL ;
    PORT
      LAYER M5 ;
        RECT  94.8 0 94.824 0.084 ;
    END
  END k_wstrb[29]
  PIN k_wstrb[2]
    DIRECTION OUTPUT ;
    USE SIGNAL ;
    PORT
      LAYER M5 ;
        RECT  37.68 0 37.704 0.084 ;
    END
  END k_wstrb[2]
  PIN k_wstrb[30]
    DIRECTION OUTPUT ;
    USE SIGNAL ;
    PORT
      LAYER M5 ;
        RECT  94.896 0 94.92 0.084 ;
    END
  END k_wstrb[30]
  PIN k_wstrb[31]
    DIRECTION OUTPUT ;
    USE SIGNAL ;
    PORT
      LAYER M5 ;
        RECT  94.992 0 95.016 0.084 ;
    END
  END k_wstrb[31]
  PIN k_wstrb[3]
    DIRECTION OUTPUT ;
    USE SIGNAL ;
    PORT
      LAYER M5 ;
        RECT  37.776 0 37.8 0.084 ;
    END
  END k_wstrb[3]
  PIN k_wstrb[4]
    DIRECTION OUTPUT ;
    USE SIGNAL ;
    PORT
      LAYER M5 ;
        RECT  37.872 0 37.896 0.084 ;
    END
  END k_wstrb[4]
  PIN k_wstrb[5]
    DIRECTION OUTPUT ;
    USE SIGNAL ;
    PORT
      LAYER M5 ;
        RECT  37.968 0 37.992 0.084 ;
    END
  END k_wstrb[5]
  PIN k_wstrb[6]
    DIRECTION OUTPUT ;
    USE SIGNAL ;
    PORT
      LAYER M5 ;
        RECT  38.064 0 38.088 0.084 ;
    END
  END k_wstrb[6]
  PIN k_wstrb[7]
    DIRECTION OUTPUT ;
    USE SIGNAL ;
    PORT
      LAYER M5 ;
        RECT  38.16 0 38.184 0.084 ;
    END
  END k_wstrb[7]
  PIN k_wstrb[8]
    DIRECTION OUTPUT ;
    USE SIGNAL ;
    PORT
      LAYER M5 ;
        RECT  38.256 0 38.28 0.084 ;
    END
  END k_wstrb[8]
  PIN k_wstrb[9]
    DIRECTION OUTPUT ;
    USE SIGNAL ;
    PORT
      LAYER M5 ;
        RECT  92.88 0 92.904 0.084 ;
    END
  END k_wstrb[9]
  PIN kr_beat[0]
    DIRECTION INPUT ;
    USE SIGNAL ;
    PORT
      LAYER M5 ;
        RECT  95.088 0 95.112 0.084 ;
    END
  END kr_beat[0]
  PIN kr_beat[1]
    DIRECTION INPUT ;
    USE SIGNAL ;
    PORT
      LAYER M5 ;
        RECT  95.184 0 95.208 0.084 ;
    END
  END kr_beat[1]
  PIN kr_beat[2]
    DIRECTION INPUT ;
    USE SIGNAL ;
    PORT
      LAYER M5 ;
        RECT  95.28 0 95.304 0.084 ;
    END
  END kr_beat[2]
  PIN kr_beat[3]
    DIRECTION INPUT ;
    USE SIGNAL ;
    PORT
      LAYER M5 ;
        RECT  95.376 0 95.4 0.084 ;
    END
  END kr_beat[3]
  PIN kr_data[0]
    DIRECTION INPUT ;
    USE SIGNAL ;
    PORT
      LAYER M5 ;
        RECT  95.472 0 95.496 0.084 ;
    END
  END kr_data[0]
  PIN kr_data[100]
    DIRECTION INPUT ;
    USE SIGNAL ;
    PORT
      LAYER M5 ;
        RECT  45.168 0 45.192 0.084 ;
    END
  END kr_data[100]
  PIN kr_data[101]
    DIRECTION INPUT ;
    USE SIGNAL ;
    PORT
      LAYER M5 ;
        RECT  39.12 0 39.144 0.084 ;
    END
  END kr_data[101]
  PIN kr_data[102]
    DIRECTION INPUT ;
    USE SIGNAL ;
    PORT
      LAYER M5 ;
        RECT  39.216 0 39.24 0.084 ;
    END
  END kr_data[102]
  PIN kr_data[103]
    DIRECTION INPUT ;
    USE SIGNAL ;
    PORT
      LAYER M5 ;
        RECT  39.312 0 39.336 0.084 ;
    END
  END kr_data[103]
  PIN kr_data[104]
    DIRECTION INPUT ;
    USE SIGNAL ;
    PORT
      LAYER M5 ;
        RECT  39.408 0 39.432 0.084 ;
    END
  END kr_data[104]
  PIN kr_data[105]
    DIRECTION INPUT ;
    USE SIGNAL ;
    PORT
      LAYER M5 ;
        RECT  39.504 0 39.528 0.084 ;
    END
  END kr_data[105]
  PIN kr_data[106]
    DIRECTION INPUT ;
    USE SIGNAL ;
    PORT
      LAYER M5 ;
        RECT  39.6 0 39.624 0.084 ;
    END
  END kr_data[106]
  PIN kr_data[107]
    DIRECTION INPUT ;
    USE SIGNAL ;
    PORT
      LAYER M5 ;
        RECT  39.696 0 39.72 0.084 ;
    END
  END kr_data[107]
  PIN kr_data[108]
    DIRECTION INPUT ;
    USE SIGNAL ;
    PORT
      LAYER M5 ;
        RECT  39.792 0 39.816 0.084 ;
    END
  END kr_data[108]
  PIN kr_data[109]
    DIRECTION INPUT ;
    USE SIGNAL ;
    PORT
      LAYER M5 ;
        RECT  39.888 0 39.912 0.084 ;
    END
  END kr_data[109]
  PIN kr_data[10]
    DIRECTION INPUT ;
    USE SIGNAL ;
    PORT
      LAYER M5 ;
        RECT  20.4 0 20.424 0.084 ;
    END
  END kr_data[10]
  PIN kr_data[110]
    DIRECTION INPUT ;
    USE SIGNAL ;
    PORT
      LAYER M5 ;
        RECT  39.984 0 40.008 0.084 ;
    END
  END kr_data[110]
  PIN kr_data[111]
    DIRECTION INPUT ;
    USE SIGNAL ;
    PORT
      LAYER M5 ;
        RECT  40.08 0 40.104 0.084 ;
    END
  END kr_data[111]
  PIN kr_data[112]
    DIRECTION INPUT ;
    USE SIGNAL ;
    PORT
      LAYER M5 ;
        RECT  40.176 0 40.2 0.084 ;
    END
  END kr_data[112]
  PIN kr_data[113]
    DIRECTION INPUT ;
    USE SIGNAL ;
    PORT
      LAYER M5 ;
        RECT  40.272 0 40.296 0.084 ;
    END
  END kr_data[113]
  PIN kr_data[114]
    DIRECTION INPUT ;
    USE SIGNAL ;
    PORT
      LAYER M5 ;
        RECT  40.368 0 40.392 0.084 ;
    END
  END kr_data[114]
  PIN kr_data[115]
    DIRECTION INPUT ;
    USE SIGNAL ;
    PORT
      LAYER M5 ;
        RECT  40.464 0 40.488 0.084 ;
    END
  END kr_data[115]
  PIN kr_data[116]
    DIRECTION INPUT ;
    USE SIGNAL ;
    PORT
      LAYER M5 ;
        RECT  40.56 0 40.584 0.084 ;
    END
  END kr_data[116]
  PIN kr_data[117]
    DIRECTION INPUT ;
    USE SIGNAL ;
    PORT
      LAYER M5 ;
        RECT  40.656 0 40.68 0.084 ;
    END
  END kr_data[117]
  PIN kr_data[118]
    DIRECTION INPUT ;
    USE SIGNAL ;
    PORT
      LAYER M5 ;
        RECT  40.752 0 40.776 0.084 ;
    END
  END kr_data[118]
  PIN kr_data[119]
    DIRECTION INPUT ;
    USE SIGNAL ;
    PORT
      LAYER M5 ;
        RECT  40.848 0 40.872 0.084 ;
    END
  END kr_data[119]
  PIN kr_data[11]
    DIRECTION INPUT ;
    USE SIGNAL ;
    PORT
      LAYER M5 ;
        RECT  20.496 0 20.52 0.084 ;
    END
  END kr_data[11]
  PIN kr_data[120]
    DIRECTION INPUT ;
    USE SIGNAL ;
    PORT
      LAYER M5 ;
        RECT  40.944 0 40.968 0.084 ;
    END
  END kr_data[120]
  PIN kr_data[121]
    DIRECTION INPUT ;
    USE SIGNAL ;
    PORT
      LAYER M5 ;
        RECT  41.04 0 41.064 0.084 ;
    END
  END kr_data[121]
  PIN kr_data[122]
    DIRECTION INPUT ;
    USE SIGNAL ;
    PORT
      LAYER M5 ;
        RECT  41.136 0 41.16 0.084 ;
    END
  END kr_data[122]
  PIN kr_data[123]
    DIRECTION INPUT ;
    USE SIGNAL ;
    PORT
      LAYER M5 ;
        RECT  41.232 0 41.256 0.084 ;
    END
  END kr_data[123]
  PIN kr_data[124]
    DIRECTION INPUT ;
    USE SIGNAL ;
    PORT
      LAYER M5 ;
        RECT  41.328 0 41.352 0.084 ;
    END
  END kr_data[124]
  PIN kr_data[125]
    DIRECTION INPUT ;
    USE SIGNAL ;
    PORT
      LAYER M5 ;
        RECT  41.424 0 41.448 0.084 ;
    END
  END kr_data[125]
  PIN kr_data[126]
    DIRECTION INPUT ;
    USE SIGNAL ;
    PORT
      LAYER M5 ;
        RECT  41.52 0 41.544 0.084 ;
    END
  END kr_data[126]
  PIN kr_data[127]
    DIRECTION INPUT ;
    USE SIGNAL ;
    PORT
      LAYER M5 ;
        RECT  41.616 0 41.64 0.084 ;
    END
  END kr_data[127]
  PIN kr_data[128]
    DIRECTION INPUT ;
    USE SIGNAL ;
    PORT
      LAYER M5 ;
        RECT  41.712 0 41.736 0.084 ;
    END
  END kr_data[128]
  PIN kr_data[129]
    DIRECTION INPUT ;
    USE SIGNAL ;
    PORT
      LAYER M5 ;
        RECT  41.808 0 41.832 0.084 ;
    END
  END kr_data[129]
  PIN kr_data[12]
    DIRECTION INPUT ;
    USE SIGNAL ;
    PORT
      LAYER M5 ;
        RECT  20.592 0 20.616 0.084 ;
    END
  END kr_data[12]
  PIN kr_data[130]
    DIRECTION INPUT ;
    USE SIGNAL ;
    PORT
      LAYER M5 ;
        RECT  41.904 0 41.928 0.084 ;
    END
  END kr_data[130]
  PIN kr_data[131]
    DIRECTION INPUT ;
    USE SIGNAL ;
    PORT
      LAYER M5 ;
        RECT  42 0 42.024 0.084 ;
    END
  END kr_data[131]
  PIN kr_data[132]
    DIRECTION INPUT ;
    USE SIGNAL ;
    PORT
      LAYER M5 ;
        RECT  42.096 0 42.12 0.084 ;
    END
  END kr_data[132]
  PIN kr_data[133]
    DIRECTION INPUT ;
    USE SIGNAL ;
    PORT
      LAYER M5 ;
        RECT  115.92 0 115.944 0.084 ;
    END
  END kr_data[133]
  PIN kr_data[134]
    DIRECTION INPUT ;
    USE SIGNAL ;
    PORT
      LAYER M5 ;
        RECT  116.016 0 116.04 0.084 ;
    END
  END kr_data[134]
  PIN kr_data[135]
    DIRECTION INPUT ;
    USE SIGNAL ;
    PORT
      LAYER M5 ;
        RECT  116.112 0 116.136 0.084 ;
    END
  END kr_data[135]
  PIN kr_data[136]
    DIRECTION INPUT ;
    USE SIGNAL ;
    PORT
      LAYER M5 ;
        RECT  116.208 0 116.232 0.084 ;
    END
  END kr_data[136]
  PIN kr_data[137]
    DIRECTION INPUT ;
    USE SIGNAL ;
    PORT
      LAYER M5 ;
        RECT  116.304 0 116.328 0.084 ;
    END
  END kr_data[137]
  PIN kr_data[138]
    DIRECTION INPUT ;
    USE SIGNAL ;
    PORT
      LAYER M5 ;
        RECT  116.4 0 116.424 0.084 ;
    END
  END kr_data[138]
  PIN kr_data[139]
    DIRECTION INPUT ;
    USE SIGNAL ;
    PORT
      LAYER M5 ;
        RECT  116.496 0 116.52 0.084 ;
    END
  END kr_data[139]
  PIN kr_data[13]
    DIRECTION INPUT ;
    USE SIGNAL ;
    PORT
      LAYER M5 ;
        RECT  20.688 0 20.712 0.084 ;
    END
  END kr_data[13]
  PIN kr_data[140]
    DIRECTION INPUT ;
    USE SIGNAL ;
    PORT
      LAYER M5 ;
        RECT  116.592 0 116.616 0.084 ;
    END
  END kr_data[140]
  PIN kr_data[141]
    DIRECTION INPUT ;
    USE SIGNAL ;
    PORT
      LAYER M5 ;
        RECT  116.688 0 116.712 0.084 ;
    END
  END kr_data[141]
  PIN kr_data[142]
    DIRECTION INPUT ;
    USE SIGNAL ;
    PORT
      LAYER M5 ;
        RECT  116.784 0 116.808 0.084 ;
    END
  END kr_data[142]
  PIN kr_data[143]
    DIRECTION INPUT ;
    USE SIGNAL ;
    PORT
      LAYER M5 ;
        RECT  116.88 0 116.904 0.084 ;
    END
  END kr_data[143]
  PIN kr_data[144]
    DIRECTION INPUT ;
    USE SIGNAL ;
    PORT
      LAYER M5 ;
        RECT  116.976 0 117 0.084 ;
    END
  END kr_data[144]
  PIN kr_data[145]
    DIRECTION INPUT ;
    USE SIGNAL ;
    PORT
      LAYER M5 ;
        RECT  117.072 0 117.096 0.084 ;
    END
  END kr_data[145]
  PIN kr_data[146]
    DIRECTION INPUT ;
    USE SIGNAL ;
    PORT
      LAYER M5 ;
        RECT  117.168 0 117.192 0.084 ;
    END
  END kr_data[146]
  PIN kr_data[147]
    DIRECTION INPUT ;
    USE SIGNAL ;
    PORT
      LAYER M5 ;
        RECT  117.264 0 117.288 0.084 ;
    END
  END kr_data[147]
  PIN kr_data[148]
    DIRECTION INPUT ;
    USE SIGNAL ;
    PORT
      LAYER M5 ;
        RECT  117.36 0 117.384 0.084 ;
    END
  END kr_data[148]
  PIN kr_data[149]
    DIRECTION INPUT ;
    USE SIGNAL ;
    PORT
      LAYER M5 ;
        RECT  117.456 0 117.48 0.084 ;
    END
  END kr_data[149]
  PIN kr_data[14]
    DIRECTION INPUT ;
    USE SIGNAL ;
    PORT
      LAYER M5 ;
        RECT  20.784 0 20.808 0.084 ;
    END
  END kr_data[14]
  PIN kr_data[150]
    DIRECTION INPUT ;
    USE SIGNAL ;
    PORT
      LAYER M5 ;
        RECT  117.552 0 117.576 0.084 ;
    END
  END kr_data[150]
  PIN kr_data[151]
    DIRECTION INPUT ;
    USE SIGNAL ;
    PORT
      LAYER M5 ;
        RECT  117.648 0 117.672 0.084 ;
    END
  END kr_data[151]
  PIN kr_data[152]
    DIRECTION INPUT ;
    USE SIGNAL ;
    PORT
      LAYER M5 ;
        RECT  117.744 0 117.768 0.084 ;
    END
  END kr_data[152]
  PIN kr_data[153]
    DIRECTION INPUT ;
    USE SIGNAL ;
    PORT
      LAYER M5 ;
        RECT  117.84 0 117.864 0.084 ;
    END
  END kr_data[153]
  PIN kr_data[154]
    DIRECTION INPUT ;
    USE SIGNAL ;
    PORT
      LAYER M5 ;
        RECT  117.936 0 117.96 0.084 ;
    END
  END kr_data[154]
  PIN kr_data[155]
    DIRECTION INPUT ;
    USE SIGNAL ;
    PORT
      LAYER M5 ;
        RECT  118.032 0 118.056 0.084 ;
    END
  END kr_data[155]
  PIN kr_data[156]
    DIRECTION INPUT ;
    USE SIGNAL ;
    PORT
      LAYER M5 ;
        RECT  118.128 0 118.152 0.084 ;
    END
  END kr_data[156]
  PIN kr_data[157]
    DIRECTION INPUT ;
    USE SIGNAL ;
    PORT
      LAYER M5 ;
        RECT  118.224 0 118.248 0.084 ;
    END
  END kr_data[157]
  PIN kr_data[158]
    DIRECTION INPUT ;
    USE SIGNAL ;
    PORT
      LAYER M5 ;
        RECT  118.32 0 118.344 0.084 ;
    END
  END kr_data[158]
  PIN kr_data[159]
    DIRECTION INPUT ;
    USE SIGNAL ;
    PORT
      LAYER M5 ;
        RECT  118.416 0 118.44 0.084 ;
    END
  END kr_data[159]
  PIN kr_data[15]
    DIRECTION INPUT ;
    USE SIGNAL ;
    PORT
      LAYER M5 ;
        RECT  20.88 0 20.904 0.084 ;
    END
  END kr_data[15]
  PIN kr_data[160]
    DIRECTION INPUT ;
    USE SIGNAL ;
    PORT
      LAYER M5 ;
        RECT  118.512 0 118.536 0.084 ;
    END
  END kr_data[160]
  PIN kr_data[161]
    DIRECTION INPUT ;
    USE SIGNAL ;
    PORT
      LAYER M5 ;
        RECT  118.608 0 118.632 0.084 ;
    END
  END kr_data[161]
  PIN kr_data[162]
    DIRECTION INPUT ;
    USE SIGNAL ;
    PORT
      LAYER M5 ;
        RECT  118.704 0 118.728 0.084 ;
    END
  END kr_data[162]
  PIN kr_data[163]
    DIRECTION INPUT ;
    USE SIGNAL ;
    PORT
      LAYER M5 ;
        RECT  118.8 0 118.824 0.084 ;
    END
  END kr_data[163]
  PIN kr_data[164]
    DIRECTION INPUT ;
    USE SIGNAL ;
    PORT
      LAYER M5 ;
        RECT  118.896 0 118.92 0.084 ;
    END
  END kr_data[164]
  PIN kr_data[165]
    DIRECTION INPUT ;
    USE SIGNAL ;
    PORT
      LAYER M5 ;
        RECT  125.136 0 125.16 0.084 ;
    END
  END kr_data[165]
  PIN kr_data[166]
    DIRECTION INPUT ;
    USE SIGNAL ;
    PORT
      LAYER M5 ;
        RECT  125.232 0 125.256 0.084 ;
    END
  END kr_data[166]
  PIN kr_data[167]
    DIRECTION INPUT ;
    USE SIGNAL ;
    PORT
      LAYER M5 ;
        RECT  125.328 0 125.352 0.084 ;
    END
  END kr_data[167]
  PIN kr_data[168]
    DIRECTION INPUT ;
    USE SIGNAL ;
    PORT
      LAYER M5 ;
        RECT  125.424 0 125.448 0.084 ;
    END
  END kr_data[168]
  PIN kr_data[169]
    DIRECTION INPUT ;
    USE SIGNAL ;
    PORT
      LAYER M5 ;
        RECT  125.52 0 125.544 0.084 ;
    END
  END kr_data[169]
  PIN kr_data[16]
    DIRECTION INPUT ;
    USE SIGNAL ;
    PORT
      LAYER M5 ;
        RECT  20.976 0 21 0.084 ;
    END
  END kr_data[16]
  PIN kr_data[170]
    DIRECTION INPUT ;
    USE SIGNAL ;
    PORT
      LAYER M5 ;
        RECT  125.616 0 125.64 0.084 ;
    END
  END kr_data[170]
  PIN kr_data[171]
    DIRECTION INPUT ;
    USE SIGNAL ;
    PORT
      LAYER M5 ;
        RECT  125.712 0 125.736 0.084 ;
    END
  END kr_data[171]
  PIN kr_data[172]
    DIRECTION INPUT ;
    USE SIGNAL ;
    PORT
      LAYER M5 ;
        RECT  125.808 0 125.832 0.084 ;
    END
  END kr_data[172]
  PIN kr_data[173]
    DIRECTION INPUT ;
    USE SIGNAL ;
    PORT
      LAYER M5 ;
        RECT  125.904 0 125.928 0.084 ;
    END
  END kr_data[173]
  PIN kr_data[174]
    DIRECTION INPUT ;
    USE SIGNAL ;
    PORT
      LAYER M5 ;
        RECT  126 0 126.024 0.084 ;
    END
  END kr_data[174]
  PIN kr_data[175]
    DIRECTION INPUT ;
    USE SIGNAL ;
    PORT
      LAYER M5 ;
        RECT  126.096 0 126.12 0.084 ;
    END
  END kr_data[175]
  PIN kr_data[176]
    DIRECTION INPUT ;
    USE SIGNAL ;
    PORT
      LAYER M5 ;
        RECT  126.192 0 126.216 0.084 ;
    END
  END kr_data[176]
  PIN kr_data[177]
    DIRECTION INPUT ;
    USE SIGNAL ;
    PORT
      LAYER M5 ;
        RECT  126.288 0 126.312 0.084 ;
    END
  END kr_data[177]
  PIN kr_data[178]
    DIRECTION INPUT ;
    USE SIGNAL ;
    PORT
      LAYER M5 ;
        RECT  126.384 0 126.408 0.084 ;
    END
  END kr_data[178]
  PIN kr_data[179]
    DIRECTION INPUT ;
    USE SIGNAL ;
    PORT
      LAYER M5 ;
        RECT  126.48 0 126.504 0.084 ;
    END
  END kr_data[179]
  PIN kr_data[17]
    DIRECTION INPUT ;
    USE SIGNAL ;
    PORT
      LAYER M5 ;
        RECT  21.072 0 21.096 0.084 ;
    END
  END kr_data[17]
  PIN kr_data[180]
    DIRECTION INPUT ;
    USE SIGNAL ;
    PORT
      LAYER M5 ;
        RECT  126.576 0 126.6 0.084 ;
    END
  END kr_data[180]
  PIN kr_data[181]
    DIRECTION INPUT ;
    USE SIGNAL ;
    PORT
      LAYER M5 ;
        RECT  126.672 0 126.696 0.084 ;
    END
  END kr_data[181]
  PIN kr_data[182]
    DIRECTION INPUT ;
    USE SIGNAL ;
    PORT
      LAYER M5 ;
        RECT  126.768 0 126.792 0.084 ;
    END
  END kr_data[182]
  PIN kr_data[183]
    DIRECTION INPUT ;
    USE SIGNAL ;
    PORT
      LAYER M5 ;
        RECT  126.864 0 126.888 0.084 ;
    END
  END kr_data[183]
  PIN kr_data[184]
    DIRECTION INPUT ;
    USE SIGNAL ;
    PORT
      LAYER M5 ;
        RECT  126.96 0 126.984 0.084 ;
    END
  END kr_data[184]
  PIN kr_data[185]
    DIRECTION INPUT ;
    USE SIGNAL ;
    PORT
      LAYER M5 ;
        RECT  127.056 0 127.08 0.084 ;
    END
  END kr_data[185]
  PIN kr_data[186]
    DIRECTION INPUT ;
    USE SIGNAL ;
    PORT
      LAYER M5 ;
        RECT  127.152 0 127.176 0.084 ;
    END
  END kr_data[186]
  PIN kr_data[187]
    DIRECTION INPUT ;
    USE SIGNAL ;
    PORT
      LAYER M5 ;
        RECT  127.248 0 127.272 0.084 ;
    END
  END kr_data[187]
  PIN kr_data[188]
    DIRECTION INPUT ;
    USE SIGNAL ;
    PORT
      LAYER M5 ;
        RECT  127.344 0 127.368 0.084 ;
    END
  END kr_data[188]
  PIN kr_data[189]
    DIRECTION INPUT ;
    USE SIGNAL ;
    PORT
      LAYER M5 ;
        RECT  127.44 0 127.464 0.084 ;
    END
  END kr_data[189]
  PIN kr_data[18]
    DIRECTION INPUT ;
    USE SIGNAL ;
    PORT
      LAYER M5 ;
        RECT  21.168 0 21.192 0.084 ;
    END
  END kr_data[18]
  PIN kr_data[190]
    DIRECTION INPUT ;
    USE SIGNAL ;
    PORT
      LAYER M5 ;
        RECT  127.536 0 127.56 0.084 ;
    END
  END kr_data[190]
  PIN kr_data[191]
    DIRECTION INPUT ;
    USE SIGNAL ;
    PORT
      LAYER M5 ;
        RECT  127.632 0 127.656 0.084 ;
    END
  END kr_data[191]
  PIN kr_data[192]
    DIRECTION INPUT ;
    USE SIGNAL ;
    PORT
      LAYER M5 ;
        RECT  127.728 0 127.752 0.084 ;
    END
  END kr_data[192]
  PIN kr_data[193]
    DIRECTION INPUT ;
    USE SIGNAL ;
    PORT
      LAYER M5 ;
        RECT  127.824 0 127.848 0.084 ;
    END
  END kr_data[193]
  PIN kr_data[194]
    DIRECTION INPUT ;
    USE SIGNAL ;
    PORT
      LAYER M5 ;
        RECT  127.92 0 127.944 0.084 ;
    END
  END kr_data[194]
  PIN kr_data[195]
    DIRECTION INPUT ;
    USE SIGNAL ;
    PORT
      LAYER M5 ;
        RECT  128.016 0 128.04 0.084 ;
    END
  END kr_data[195]
  PIN kr_data[196]
    DIRECTION INPUT ;
    USE SIGNAL ;
    PORT
      LAYER M5 ;
        RECT  128.112 0 128.136 0.084 ;
    END
  END kr_data[196]
  PIN kr_data[197]
    DIRECTION INPUT ;
    USE SIGNAL ;
    PORT
      LAYER M5 ;
        RECT  122.064 0 122.088 0.084 ;
    END
  END kr_data[197]
  PIN kr_data[198]
    DIRECTION INPUT ;
    USE SIGNAL ;
    PORT
      LAYER M5 ;
        RECT  122.16 0 122.184 0.084 ;
    END
  END kr_data[198]
  PIN kr_data[199]
    DIRECTION INPUT ;
    USE SIGNAL ;
    PORT
      LAYER M5 ;
        RECT  122.256 0 122.28 0.084 ;
    END
  END kr_data[199]
  PIN kr_data[19]
    DIRECTION INPUT ;
    USE SIGNAL ;
    PORT
      LAYER M5 ;
        RECT  21.264 0 21.288 0.084 ;
    END
  END kr_data[19]
  PIN kr_data[1]
    DIRECTION INPUT ;
    USE SIGNAL ;
    PORT
      LAYER M5 ;
        RECT  95.568 0 95.592 0.084 ;
    END
  END kr_data[1]
  PIN kr_data[200]
    DIRECTION INPUT ;
    USE SIGNAL ;
    PORT
      LAYER M5 ;
        RECT  122.352 0 122.376 0.084 ;
    END
  END kr_data[200]
  PIN kr_data[201]
    DIRECTION INPUT ;
    USE SIGNAL ;
    PORT
      LAYER M5 ;
        RECT  122.448 0 122.472 0.084 ;
    END
  END kr_data[201]
  PIN kr_data[202]
    DIRECTION INPUT ;
    USE SIGNAL ;
    PORT
      LAYER M5 ;
        RECT  122.544 0 122.568 0.084 ;
    END
  END kr_data[202]
  PIN kr_data[203]
    DIRECTION INPUT ;
    USE SIGNAL ;
    PORT
      LAYER M5 ;
        RECT  122.64 0 122.664 0.084 ;
    END
  END kr_data[203]
  PIN kr_data[204]
    DIRECTION INPUT ;
    USE SIGNAL ;
    PORT
      LAYER M5 ;
        RECT  122.736 0 122.76 0.084 ;
    END
  END kr_data[204]
  PIN kr_data[205]
    DIRECTION INPUT ;
    USE SIGNAL ;
    PORT
      LAYER M5 ;
        RECT  122.832 0 122.856 0.084 ;
    END
  END kr_data[205]
  PIN kr_data[206]
    DIRECTION INPUT ;
    USE SIGNAL ;
    PORT
      LAYER M5 ;
        RECT  122.928 0 122.952 0.084 ;
    END
  END kr_data[206]
  PIN kr_data[207]
    DIRECTION INPUT ;
    USE SIGNAL ;
    PORT
      LAYER M5 ;
        RECT  123.024 0 123.048 0.084 ;
    END
  END kr_data[207]
  PIN kr_data[208]
    DIRECTION INPUT ;
    USE SIGNAL ;
    PORT
      LAYER M5 ;
        RECT  123.12 0 123.144 0.084 ;
    END
  END kr_data[208]
  PIN kr_data[209]
    DIRECTION INPUT ;
    USE SIGNAL ;
    PORT
      LAYER M5 ;
        RECT  123.216 0 123.24 0.084 ;
    END
  END kr_data[209]
  PIN kr_data[20]
    DIRECTION INPUT ;
    USE SIGNAL ;
    PORT
      LAYER M5 ;
        RECT  21.36 0 21.384 0.084 ;
    END
  END kr_data[20]
  PIN kr_data[210]
    DIRECTION INPUT ;
    USE SIGNAL ;
    PORT
      LAYER M5 ;
        RECT  123.312 0 123.336 0.084 ;
    END
  END kr_data[210]
  PIN kr_data[211]
    DIRECTION INPUT ;
    USE SIGNAL ;
    PORT
      LAYER M5 ;
        RECT  123.408 0 123.432 0.084 ;
    END
  END kr_data[211]
  PIN kr_data[212]
    DIRECTION INPUT ;
    USE SIGNAL ;
    PORT
      LAYER M5 ;
        RECT  123.504 0 123.528 0.084 ;
    END
  END kr_data[212]
  PIN kr_data[213]
    DIRECTION INPUT ;
    USE SIGNAL ;
    PORT
      LAYER M5 ;
        RECT  123.6 0 123.624 0.084 ;
    END
  END kr_data[213]
  PIN kr_data[214]
    DIRECTION INPUT ;
    USE SIGNAL ;
    PORT
      LAYER M5 ;
        RECT  123.696 0 123.72 0.084 ;
    END
  END kr_data[214]
  PIN kr_data[215]
    DIRECTION INPUT ;
    USE SIGNAL ;
    PORT
      LAYER M5 ;
        RECT  123.792 0 123.816 0.084 ;
    END
  END kr_data[215]
  PIN kr_data[216]
    DIRECTION INPUT ;
    USE SIGNAL ;
    PORT
      LAYER M5 ;
        RECT  123.888 0 123.912 0.084 ;
    END
  END kr_data[216]
  PIN kr_data[217]
    DIRECTION INPUT ;
    USE SIGNAL ;
    PORT
      LAYER M5 ;
        RECT  123.984 0 124.008 0.084 ;
    END
  END kr_data[217]
  PIN kr_data[218]
    DIRECTION INPUT ;
    USE SIGNAL ;
    PORT
      LAYER M5 ;
        RECT  124.08 0 124.104 0.084 ;
    END
  END kr_data[218]
  PIN kr_data[219]
    DIRECTION INPUT ;
    USE SIGNAL ;
    PORT
      LAYER M5 ;
        RECT  124.176 0 124.2 0.084 ;
    END
  END kr_data[219]
  PIN kr_data[21]
    DIRECTION INPUT ;
    USE SIGNAL ;
    PORT
      LAYER M5 ;
        RECT  21.456 0 21.48 0.084 ;
    END
  END kr_data[21]
  PIN kr_data[220]
    DIRECTION INPUT ;
    USE SIGNAL ;
    PORT
      LAYER M5 ;
        RECT  124.272 0 124.296 0.084 ;
    END
  END kr_data[220]
  PIN kr_data[221]
    DIRECTION INPUT ;
    USE SIGNAL ;
    PORT
      LAYER M5 ;
        RECT  124.368 0 124.392 0.084 ;
    END
  END kr_data[221]
  PIN kr_data[222]
    DIRECTION INPUT ;
    USE SIGNAL ;
    PORT
      LAYER M5 ;
        RECT  124.464 0 124.488 0.084 ;
    END
  END kr_data[222]
  PIN kr_data[223]
    DIRECTION INPUT ;
    USE SIGNAL ;
    PORT
      LAYER M5 ;
        RECT  124.56 0 124.584 0.084 ;
    END
  END kr_data[223]
  PIN kr_data[224]
    DIRECTION INPUT ;
    USE SIGNAL ;
    PORT
      LAYER M5 ;
        RECT  124.656 0 124.68 0.084 ;
    END
  END kr_data[224]
  PIN kr_data[225]
    DIRECTION INPUT ;
    USE SIGNAL ;
    PORT
      LAYER M5 ;
        RECT  124.752 0 124.776 0.084 ;
    END
  END kr_data[225]
  PIN kr_data[226]
    DIRECTION INPUT ;
    USE SIGNAL ;
    PORT
      LAYER M5 ;
        RECT  124.848 0 124.872 0.084 ;
    END
  END kr_data[226]
  PIN kr_data[227]
    DIRECTION INPUT ;
    USE SIGNAL ;
    PORT
      LAYER M5 ;
        RECT  124.944 0 124.968 0.084 ;
    END
  END kr_data[227]
  PIN kr_data[228]
    DIRECTION INPUT ;
    USE SIGNAL ;
    PORT
      LAYER M5 ;
        RECT  125.04 0 125.064 0.084 ;
    END
  END kr_data[228]
  PIN kr_data[229]
    DIRECTION INPUT ;
    USE SIGNAL ;
    PORT
      LAYER M5 ;
        RECT  118.992 0 119.016 0.084 ;
    END
  END kr_data[229]
  PIN kr_data[22]
    DIRECTION INPUT ;
    USE SIGNAL ;
    PORT
      LAYER M5 ;
        RECT  21.552 0 21.576 0.084 ;
    END
  END kr_data[22]
  PIN kr_data[230]
    DIRECTION INPUT ;
    USE SIGNAL ;
    PORT
      LAYER M5 ;
        RECT  119.088 0 119.112 0.084 ;
    END
  END kr_data[230]
  PIN kr_data[231]
    DIRECTION INPUT ;
    USE SIGNAL ;
    PORT
      LAYER M5 ;
        RECT  119.184 0 119.208 0.084 ;
    END
  END kr_data[231]
  PIN kr_data[232]
    DIRECTION INPUT ;
    USE SIGNAL ;
    PORT
      LAYER M5 ;
        RECT  119.28 0 119.304 0.084 ;
    END
  END kr_data[232]
  PIN kr_data[233]
    DIRECTION INPUT ;
    USE SIGNAL ;
    PORT
      LAYER M5 ;
        RECT  119.376 0 119.4 0.084 ;
    END
  END kr_data[233]
  PIN kr_data[234]
    DIRECTION INPUT ;
    USE SIGNAL ;
    PORT
      LAYER M5 ;
        RECT  119.472 0 119.496 0.084 ;
    END
  END kr_data[234]
  PIN kr_data[235]
    DIRECTION INPUT ;
    USE SIGNAL ;
    PORT
      LAYER M5 ;
        RECT  119.568 0 119.592 0.084 ;
    END
  END kr_data[235]
  PIN kr_data[236]
    DIRECTION INPUT ;
    USE SIGNAL ;
    PORT
      LAYER M5 ;
        RECT  119.664 0 119.688 0.084 ;
    END
  END kr_data[236]
  PIN kr_data[237]
    DIRECTION INPUT ;
    USE SIGNAL ;
    PORT
      LAYER M5 ;
        RECT  119.76 0 119.784 0.084 ;
    END
  END kr_data[237]
  PIN kr_data[238]
    DIRECTION INPUT ;
    USE SIGNAL ;
    PORT
      LAYER M5 ;
        RECT  119.856 0 119.88 0.084 ;
    END
  END kr_data[238]
  PIN kr_data[239]
    DIRECTION INPUT ;
    USE SIGNAL ;
    PORT
      LAYER M5 ;
        RECT  119.952 0 119.976 0.084 ;
    END
  END kr_data[239]
  PIN kr_data[23]
    DIRECTION INPUT ;
    USE SIGNAL ;
    PORT
      LAYER M5 ;
        RECT  21.648 0 21.672 0.084 ;
    END
  END kr_data[23]
  PIN kr_data[240]
    DIRECTION INPUT ;
    USE SIGNAL ;
    PORT
      LAYER M5 ;
        RECT  120.048 0 120.072 0.084 ;
    END
  END kr_data[240]
  PIN kr_data[241]
    DIRECTION INPUT ;
    USE SIGNAL ;
    PORT
      LAYER M5 ;
        RECT  120.144 0 120.168 0.084 ;
    END
  END kr_data[241]
  PIN kr_data[242]
    DIRECTION INPUT ;
    USE SIGNAL ;
    PORT
      LAYER M5 ;
        RECT  120.24 0 120.264 0.084 ;
    END
  END kr_data[242]
  PIN kr_data[243]
    DIRECTION INPUT ;
    USE SIGNAL ;
    PORT
      LAYER M5 ;
        RECT  120.336 0 120.36 0.084 ;
    END
  END kr_data[243]
  PIN kr_data[244]
    DIRECTION INPUT ;
    USE SIGNAL ;
    PORT
      LAYER M5 ;
        RECT  120.432 0 120.456 0.084 ;
    END
  END kr_data[244]
  PIN kr_data[245]
    DIRECTION INPUT ;
    USE SIGNAL ;
    PORT
      LAYER M5 ;
        RECT  120.528 0 120.552 0.084 ;
    END
  END kr_data[245]
  PIN kr_data[246]
    DIRECTION INPUT ;
    USE SIGNAL ;
    PORT
      LAYER M5 ;
        RECT  120.624 0 120.648 0.084 ;
    END
  END kr_data[246]
  PIN kr_data[247]
    DIRECTION INPUT ;
    USE SIGNAL ;
    PORT
      LAYER M5 ;
        RECT  120.72 0 120.744 0.084 ;
    END
  END kr_data[247]
  PIN kr_data[248]
    DIRECTION INPUT ;
    USE SIGNAL ;
    PORT
      LAYER M5 ;
        RECT  120.816 0 120.84 0.084 ;
    END
  END kr_data[248]
  PIN kr_data[249]
    DIRECTION INPUT ;
    USE SIGNAL ;
    PORT
      LAYER M5 ;
        RECT  120.912 0 120.936 0.084 ;
    END
  END kr_data[249]
  PIN kr_data[24]
    DIRECTION INPUT ;
    USE SIGNAL ;
    PORT
      LAYER M5 ;
        RECT  21.744 0 21.768 0.084 ;
    END
  END kr_data[24]
  PIN kr_data[250]
    DIRECTION INPUT ;
    USE SIGNAL ;
    PORT
      LAYER M5 ;
        RECT  121.008 0 121.032 0.084 ;
    END
  END kr_data[250]
  PIN kr_data[251]
    DIRECTION INPUT ;
    USE SIGNAL ;
    PORT
      LAYER M5 ;
        RECT  121.104 0 121.128 0.084 ;
    END
  END kr_data[251]
  PIN kr_data[252]
    DIRECTION INPUT ;
    USE SIGNAL ;
    PORT
      LAYER M5 ;
        RECT  121.2 0 121.224 0.084 ;
    END
  END kr_data[252]
  PIN kr_data[253]
    DIRECTION INPUT ;
    USE SIGNAL ;
    PORT
      LAYER M5 ;
        RECT  121.296 0 121.32 0.084 ;
    END
  END kr_data[253]
  PIN kr_data[254]
    DIRECTION INPUT ;
    USE SIGNAL ;
    PORT
      LAYER M5 ;
        RECT  121.392 0 121.416 0.084 ;
    END
  END kr_data[254]
  PIN kr_data[255]
    DIRECTION INPUT ;
    USE SIGNAL ;
    PORT
      LAYER M5 ;
        RECT  121.488 0 121.512 0.084 ;
    END
  END kr_data[255]
  PIN kr_data[25]
    DIRECTION INPUT ;
    USE SIGNAL ;
    PORT
      LAYER M5 ;
        RECT  21.84 0 21.864 0.084 ;
    END
  END kr_data[25]
  PIN kr_data[26]
    DIRECTION INPUT ;
    USE SIGNAL ;
    PORT
      LAYER M5 ;
        RECT  21.936 0 21.96 0.084 ;
    END
  END kr_data[26]
  PIN kr_data[27]
    DIRECTION INPUT ;
    USE SIGNAL ;
    PORT
      LAYER M5 ;
        RECT  22.032 0 22.056 0.084 ;
    END
  END kr_data[27]
  PIN kr_data[28]
    DIRECTION INPUT ;
    USE SIGNAL ;
    PORT
      LAYER M5 ;
        RECT  22.128 0 22.152 0.084 ;
    END
  END kr_data[28]
  PIN kr_data[29]
    DIRECTION INPUT ;
    USE SIGNAL ;
    PORT
      LAYER M5 ;
        RECT  22.224 0 22.248 0.084 ;
    END
  END kr_data[29]
  PIN kr_data[2]
    DIRECTION INPUT ;
    USE SIGNAL ;
    PORT
      LAYER M5 ;
        RECT  95.664 0 95.688 0.084 ;
    END
  END kr_data[2]
  PIN kr_data[30]
    DIRECTION INPUT ;
    USE SIGNAL ;
    PORT
      LAYER M5 ;
        RECT  22.32 0 22.344 0.084 ;
    END
  END kr_data[30]
  PIN kr_data[31]
    DIRECTION INPUT ;
    USE SIGNAL ;
    PORT
      LAYER M5 ;
        RECT  22.416 0 22.44 0.084 ;
    END
  END kr_data[31]
  PIN kr_data[32]
    DIRECTION INPUT ;
    USE SIGNAL ;
    PORT
      LAYER M5 ;
        RECT  22.512 0 22.536 0.084 ;
    END
  END kr_data[32]
  PIN kr_data[33]
    DIRECTION INPUT ;
    USE SIGNAL ;
    PORT
      LAYER M5 ;
        RECT  22.608 0 22.632 0.084 ;
    END
  END kr_data[33]
  PIN kr_data[34]
    DIRECTION INPUT ;
    USE SIGNAL ;
    PORT
      LAYER M5 ;
        RECT  22.704 0 22.728 0.084 ;
    END
  END kr_data[34]
  PIN kr_data[35]
    DIRECTION INPUT ;
    USE SIGNAL ;
    PORT
      LAYER M5 ;
        RECT  22.8 0 22.824 0.084 ;
    END
  END kr_data[35]
  PIN kr_data[36]
    DIRECTION INPUT ;
    USE SIGNAL ;
    PORT
      LAYER M5 ;
        RECT  22.896 0 22.92 0.084 ;
    END
  END kr_data[36]
  PIN kr_data[37]
    DIRECTION INPUT ;
    USE SIGNAL ;
    PORT
      LAYER M5 ;
        RECT  32.208 0 32.232 0.084 ;
    END
  END kr_data[37]
  PIN kr_data[38]
    DIRECTION INPUT ;
    USE SIGNAL ;
    PORT
      LAYER M5 ;
        RECT  32.304 0 32.328 0.084 ;
    END
  END kr_data[38]
  PIN kr_data[39]
    DIRECTION INPUT ;
    USE SIGNAL ;
    PORT
      LAYER M5 ;
        RECT  32.4 0 32.424 0.084 ;
    END
  END kr_data[39]
  PIN kr_data[3]
    DIRECTION INPUT ;
    USE SIGNAL ;
    PORT
      LAYER M5 ;
        RECT  95.76 0 95.784 0.084 ;
    END
  END kr_data[3]
  PIN kr_data[40]
    DIRECTION INPUT ;
    USE SIGNAL ;
    PORT
      LAYER M5 ;
        RECT  32.496 0 32.52 0.084 ;
    END
  END kr_data[40]
  PIN kr_data[41]
    DIRECTION INPUT ;
    USE SIGNAL ;
    PORT
      LAYER M5 ;
        RECT  32.592 0 32.616 0.084 ;
    END
  END kr_data[41]
  PIN kr_data[42]
    DIRECTION INPUT ;
    USE SIGNAL ;
    PORT
      LAYER M5 ;
        RECT  32.688 0 32.712 0.084 ;
    END
  END kr_data[42]
  PIN kr_data[43]
    DIRECTION INPUT ;
    USE SIGNAL ;
    PORT
      LAYER M5 ;
        RECT  32.784 0 32.808 0.084 ;
    END
  END kr_data[43]
  PIN kr_data[44]
    DIRECTION INPUT ;
    USE SIGNAL ;
    PORT
      LAYER M5 ;
        RECT  32.88 0 32.904 0.084 ;
    END
  END kr_data[44]
  PIN kr_data[45]
    DIRECTION INPUT ;
    USE SIGNAL ;
    PORT
      LAYER M5 ;
        RECT  32.976 0 33 0.084 ;
    END
  END kr_data[45]
  PIN kr_data[46]
    DIRECTION INPUT ;
    USE SIGNAL ;
    PORT
      LAYER M5 ;
        RECT  33.072 0 33.096 0.084 ;
    END
  END kr_data[46]
  PIN kr_data[47]
    DIRECTION INPUT ;
    USE SIGNAL ;
    PORT
      LAYER M5 ;
        RECT  33.168 0 33.192 0.084 ;
    END
  END kr_data[47]
  PIN kr_data[48]
    DIRECTION INPUT ;
    USE SIGNAL ;
    PORT
      LAYER M5 ;
        RECT  33.264 0 33.288 0.084 ;
    END
  END kr_data[48]
  PIN kr_data[49]
    DIRECTION INPUT ;
    USE SIGNAL ;
    PORT
      LAYER M5 ;
        RECT  33.36 0 33.384 0.084 ;
    END
  END kr_data[49]
  PIN kr_data[4]
    DIRECTION INPUT ;
    USE SIGNAL ;
    PORT
      LAYER M5 ;
        RECT  95.856 0 95.88 0.084 ;
    END
  END kr_data[4]
  PIN kr_data[50]
    DIRECTION INPUT ;
    USE SIGNAL ;
    PORT
      LAYER M5 ;
        RECT  33.456 0 33.48 0.084 ;
    END
  END kr_data[50]
  PIN kr_data[51]
    DIRECTION INPUT ;
    USE SIGNAL ;
    PORT
      LAYER M5 ;
        RECT  33.552 0 33.576 0.084 ;
    END
  END kr_data[51]
  PIN kr_data[52]
    DIRECTION INPUT ;
    USE SIGNAL ;
    PORT
      LAYER M5 ;
        RECT  33.648 0 33.672 0.084 ;
    END
  END kr_data[52]
  PIN kr_data[53]
    DIRECTION INPUT ;
    USE SIGNAL ;
    PORT
      LAYER M5 ;
        RECT  33.744 0 33.768 0.084 ;
    END
  END kr_data[53]
  PIN kr_data[54]
    DIRECTION INPUT ;
    USE SIGNAL ;
    PORT
      LAYER M5 ;
        RECT  33.84 0 33.864 0.084 ;
    END
  END kr_data[54]
  PIN kr_data[55]
    DIRECTION INPUT ;
    USE SIGNAL ;
    PORT
      LAYER M5 ;
        RECT  33.936 0 33.96 0.084 ;
    END
  END kr_data[55]
  PIN kr_data[56]
    DIRECTION INPUT ;
    USE SIGNAL ;
    PORT
      LAYER M5 ;
        RECT  34.032 0 34.056 0.084 ;
    END
  END kr_data[56]
  PIN kr_data[57]
    DIRECTION INPUT ;
    USE SIGNAL ;
    PORT
      LAYER M5 ;
        RECT  34.128 0 34.152 0.084 ;
    END
  END kr_data[57]
  PIN kr_data[58]
    DIRECTION INPUT ;
    USE SIGNAL ;
    PORT
      LAYER M5 ;
        RECT  34.224 0 34.248 0.084 ;
    END
  END kr_data[58]
  PIN kr_data[59]
    DIRECTION INPUT ;
    USE SIGNAL ;
    PORT
      LAYER M5 ;
        RECT  34.32 0 34.344 0.084 ;
    END
  END kr_data[59]
  PIN kr_data[5]
    DIRECTION INPUT ;
    USE SIGNAL ;
    PORT
      LAYER M5 ;
        RECT  19.92 0 19.944 0.084 ;
    END
  END kr_data[5]
  PIN kr_data[60]
    DIRECTION INPUT ;
    USE SIGNAL ;
    PORT
      LAYER M5 ;
        RECT  34.416 0 34.44 0.084 ;
    END
  END kr_data[60]
  PIN kr_data[61]
    DIRECTION INPUT ;
    USE SIGNAL ;
    PORT
      LAYER M5 ;
        RECT  34.512 0 34.536 0.084 ;
    END
  END kr_data[61]
  PIN kr_data[62]
    DIRECTION INPUT ;
    USE SIGNAL ;
    PORT
      LAYER M5 ;
        RECT  34.608 0 34.632 0.084 ;
    END
  END kr_data[62]
  PIN kr_data[63]
    DIRECTION INPUT ;
    USE SIGNAL ;
    PORT
      LAYER M5 ;
        RECT  34.704 0 34.728 0.084 ;
    END
  END kr_data[63]
  PIN kr_data[64]
    DIRECTION INPUT ;
    USE SIGNAL ;
    PORT
      LAYER M5 ;
        RECT  34.8 0 34.824 0.084 ;
    END
  END kr_data[64]
  PIN kr_data[65]
    DIRECTION INPUT ;
    USE SIGNAL ;
    PORT
      LAYER M5 ;
        RECT  34.896 0 34.92 0.084 ;
    END
  END kr_data[65]
  PIN kr_data[66]
    DIRECTION INPUT ;
    USE SIGNAL ;
    PORT
      LAYER M5 ;
        RECT  34.992 0 35.016 0.084 ;
    END
  END kr_data[66]
  PIN kr_data[67]
    DIRECTION INPUT ;
    USE SIGNAL ;
    PORT
      LAYER M5 ;
        RECT  35.088 0 35.112 0.084 ;
    END
  END kr_data[67]
  PIN kr_data[68]
    DIRECTION INPUT ;
    USE SIGNAL ;
    PORT
      LAYER M5 ;
        RECT  35.184 0 35.208 0.084 ;
    END
  END kr_data[68]
  PIN kr_data[69]
    DIRECTION INPUT ;
    USE SIGNAL ;
    PORT
      LAYER M5 ;
        RECT  42.192 0 42.216 0.084 ;
    END
  END kr_data[69]
  PIN kr_data[6]
    DIRECTION INPUT ;
    USE SIGNAL ;
    PORT
      LAYER M5 ;
        RECT  20.016 0 20.04 0.084 ;
    END
  END kr_data[6]
  PIN kr_data[70]
    DIRECTION INPUT ;
    USE SIGNAL ;
    PORT
      LAYER M5 ;
        RECT  42.288 0 42.312 0.084 ;
    END
  END kr_data[70]
  PIN kr_data[71]
    DIRECTION INPUT ;
    USE SIGNAL ;
    PORT
      LAYER M5 ;
        RECT  42.384 0 42.408 0.084 ;
    END
  END kr_data[71]
  PIN kr_data[72]
    DIRECTION INPUT ;
    USE SIGNAL ;
    PORT
      LAYER M5 ;
        RECT  42.48 0 42.504 0.084 ;
    END
  END kr_data[72]
  PIN kr_data[73]
    DIRECTION INPUT ;
    USE SIGNAL ;
    PORT
      LAYER M5 ;
        RECT  42.576 0 42.6 0.084 ;
    END
  END kr_data[73]
  PIN kr_data[74]
    DIRECTION INPUT ;
    USE SIGNAL ;
    PORT
      LAYER M5 ;
        RECT  42.672 0 42.696 0.084 ;
    END
  END kr_data[74]
  PIN kr_data[75]
    DIRECTION INPUT ;
    USE SIGNAL ;
    PORT
      LAYER M5 ;
        RECT  42.768 0 42.792 0.084 ;
    END
  END kr_data[75]
  PIN kr_data[76]
    DIRECTION INPUT ;
    USE SIGNAL ;
    PORT
      LAYER M5 ;
        RECT  42.864 0 42.888 0.084 ;
    END
  END kr_data[76]
  PIN kr_data[77]
    DIRECTION INPUT ;
    USE SIGNAL ;
    PORT
      LAYER M5 ;
        RECT  42.96 0 42.984 0.084 ;
    END
  END kr_data[77]
  PIN kr_data[78]
    DIRECTION INPUT ;
    USE SIGNAL ;
    PORT
      LAYER M5 ;
        RECT  43.056 0 43.08 0.084 ;
    END
  END kr_data[78]
  PIN kr_data[79]
    DIRECTION INPUT ;
    USE SIGNAL ;
    PORT
      LAYER M5 ;
        RECT  43.152 0 43.176 0.084 ;
    END
  END kr_data[79]
  PIN kr_data[7]
    DIRECTION INPUT ;
    USE SIGNAL ;
    PORT
      LAYER M5 ;
        RECT  20.112 0 20.136 0.084 ;
    END
  END kr_data[7]
  PIN kr_data[80]
    DIRECTION INPUT ;
    USE SIGNAL ;
    PORT
      LAYER M5 ;
        RECT  43.248 0 43.272 0.084 ;
    END
  END kr_data[80]
  PIN kr_data[81]
    DIRECTION INPUT ;
    USE SIGNAL ;
    PORT
      LAYER M5 ;
        RECT  43.344 0 43.368 0.084 ;
    END
  END kr_data[81]
  PIN kr_data[82]
    DIRECTION INPUT ;
    USE SIGNAL ;
    PORT
      LAYER M5 ;
        RECT  43.44 0 43.464 0.084 ;
    END
  END kr_data[82]
  PIN kr_data[83]
    DIRECTION INPUT ;
    USE SIGNAL ;
    PORT
      LAYER M5 ;
        RECT  43.536 0 43.56 0.084 ;
    END
  END kr_data[83]
  PIN kr_data[84]
    DIRECTION INPUT ;
    USE SIGNAL ;
    PORT
      LAYER M5 ;
        RECT  43.632 0 43.656 0.084 ;
    END
  END kr_data[84]
  PIN kr_data[85]
    DIRECTION INPUT ;
    USE SIGNAL ;
    PORT
      LAYER M5 ;
        RECT  43.728 0 43.752 0.084 ;
    END
  END kr_data[85]
  PIN kr_data[86]
    DIRECTION INPUT ;
    USE SIGNAL ;
    PORT
      LAYER M5 ;
        RECT  43.824 0 43.848 0.084 ;
    END
  END kr_data[86]
  PIN kr_data[87]
    DIRECTION INPUT ;
    USE SIGNAL ;
    PORT
      LAYER M5 ;
        RECT  43.92 0 43.944 0.084 ;
    END
  END kr_data[87]
  PIN kr_data[88]
    DIRECTION INPUT ;
    USE SIGNAL ;
    PORT
      LAYER M5 ;
        RECT  44.016 0 44.04 0.084 ;
    END
  END kr_data[88]
  PIN kr_data[89]
    DIRECTION INPUT ;
    USE SIGNAL ;
    PORT
      LAYER M5 ;
        RECT  44.112 0 44.136 0.084 ;
    END
  END kr_data[89]
  PIN kr_data[8]
    DIRECTION INPUT ;
    USE SIGNAL ;
    PORT
      LAYER M5 ;
        RECT  20.208 0 20.232 0.084 ;
    END
  END kr_data[8]
  PIN kr_data[90]
    DIRECTION INPUT ;
    USE SIGNAL ;
    PORT
      LAYER M5 ;
        RECT  44.208 0 44.232 0.084 ;
    END
  END kr_data[90]
  PIN kr_data[91]
    DIRECTION INPUT ;
    USE SIGNAL ;
    PORT
      LAYER M5 ;
        RECT  44.304 0 44.328 0.084 ;
    END
  END kr_data[91]
  PIN kr_data[92]
    DIRECTION INPUT ;
    USE SIGNAL ;
    PORT
      LAYER M5 ;
        RECT  44.4 0 44.424 0.084 ;
    END
  END kr_data[92]
  PIN kr_data[93]
    DIRECTION INPUT ;
    USE SIGNAL ;
    PORT
      LAYER M5 ;
        RECT  44.496 0 44.52 0.084 ;
    END
  END kr_data[93]
  PIN kr_data[94]
    DIRECTION INPUT ;
    USE SIGNAL ;
    PORT
      LAYER M5 ;
        RECT  44.592 0 44.616 0.084 ;
    END
  END kr_data[94]
  PIN kr_data[95]
    DIRECTION INPUT ;
    USE SIGNAL ;
    PORT
      LAYER M5 ;
        RECT  44.688 0 44.712 0.084 ;
    END
  END kr_data[95]
  PIN kr_data[96]
    DIRECTION INPUT ;
    USE SIGNAL ;
    PORT
      LAYER M5 ;
        RECT  44.784 0 44.808 0.084 ;
    END
  END kr_data[96]
  PIN kr_data[97]
    DIRECTION INPUT ;
    USE SIGNAL ;
    PORT
      LAYER M5 ;
        RECT  44.88 0 44.904 0.084 ;
    END
  END kr_data[97]
  PIN kr_data[98]
    DIRECTION INPUT ;
    USE SIGNAL ;
    PORT
      LAYER M5 ;
        RECT  44.976 0 45 0.084 ;
    END
  END kr_data[98]
  PIN kr_data[99]
    DIRECTION INPUT ;
    USE SIGNAL ;
    PORT
      LAYER M5 ;
        RECT  45.072 0 45.096 0.084 ;
    END
  END kr_data[99]
  PIN kr_data[9]
    DIRECTION INPUT ;
    USE SIGNAL ;
    PORT
      LAYER M5 ;
        RECT  20.304 0 20.328 0.084 ;
    END
  END kr_data[9]
  PIN kr_rdy
    DIRECTION OUTPUT ;
    USE SIGNAL ;
    PORT
      LAYER M5 ;
        RECT  121.584 0 121.608 0.084 ;
    END
  END kr_rdy
  PIN kr_tag[0]
    DIRECTION INPUT ;
    USE SIGNAL ;
    PORT
      LAYER M5 ;
        RECT  121.68 0 121.704 0.084 ;
    END
  END kr_tag[0]
  PIN kr_tag[10]
    DIRECTION INPUT ;
    USE SIGNAL ;
    PORT
      LAYER M5 ;
        RECT  45.84 0 45.864 0.084 ;
    END
  END kr_tag[10]
  PIN kr_tag[11]
    DIRECTION INPUT ;
    USE SIGNAL ;
    PORT
      LAYER M5 ;
        RECT  45.936 0 45.96 0.084 ;
    END
  END kr_tag[11]
  PIN kr_tag[12]
    DIRECTION INPUT ;
    USE SIGNAL ;
    PORT
      LAYER M5 ;
        RECT  46.032 0 46.056 0.084 ;
    END
  END kr_tag[12]
  PIN kr_tag[13]
    DIRECTION INPUT ;
    USE SIGNAL ;
    PORT
      LAYER M5 ;
        RECT  46.128 0 46.152 0.084 ;
    END
  END kr_tag[13]
  PIN kr_tag[14]
    DIRECTION INPUT ;
    USE SIGNAL ;
    PORT
      LAYER M5 ;
        RECT  46.224 0 46.248 0.084 ;
    END
  END kr_tag[14]
  PIN kr_tag[15]
    DIRECTION INPUT ;
    USE SIGNAL ;
    PORT
      LAYER M5 ;
        RECT  46.32 0 46.344 0.084 ;
    END
  END kr_tag[15]
  PIN kr_tag[16]
    DIRECTION INPUT ;
    USE SIGNAL ;
    PORT
      LAYER M5 ;
        RECT  46.416 0 46.44 0.084 ;
    END
  END kr_tag[16]
  PIN kr_tag[1]
    DIRECTION INPUT ;
    USE SIGNAL ;
    PORT
      LAYER M5 ;
        RECT  121.776 0 121.8 0.084 ;
    END
  END kr_tag[1]
  PIN kr_tag[2]
    DIRECTION INPUT ;
    USE SIGNAL ;
    PORT
      LAYER M5 ;
        RECT  121.872 0 121.896 0.084 ;
    END
  END kr_tag[2]
  PIN kr_tag[3]
    DIRECTION INPUT ;
    USE SIGNAL ;
    PORT
      LAYER M5 ;
        RECT  121.968 0 121.992 0.084 ;
    END
  END kr_tag[3]
  PIN kr_tag[4]
    DIRECTION INPUT ;
    USE SIGNAL ;
    PORT
      LAYER M5 ;
        RECT  45.264 0 45.288 0.084 ;
    END
  END kr_tag[4]
  PIN kr_tag[5]
    DIRECTION INPUT ;
    USE SIGNAL ;
    PORT
      LAYER M5 ;
        RECT  45.36 0 45.384 0.084 ;
    END
  END kr_tag[5]
  PIN kr_tag[6]
    DIRECTION INPUT ;
    USE SIGNAL ;
    PORT
      LAYER M5 ;
        RECT  45.456 0 45.48 0.084 ;
    END
  END kr_tag[6]
  PIN kr_tag[7]
    DIRECTION INPUT ;
    USE SIGNAL ;
    PORT
      LAYER M5 ;
        RECT  45.552 0 45.576 0.084 ;
    END
  END kr_tag[7]
  PIN kr_tag[8]
    DIRECTION INPUT ;
    USE SIGNAL ;
    PORT
      LAYER M5 ;
        RECT  45.648 0 45.672 0.084 ;
    END
  END kr_tag[8]
  PIN kr_tag[9]
    DIRECTION INPUT ;
    USE SIGNAL ;
    PORT
      LAYER M5 ;
        RECT  45.744 0 45.768 0.084 ;
    END
  END kr_tag[9]
  PIN kr_v
    DIRECTION INPUT ;
    USE SIGNAL ;
    PORT
      LAYER M5 ;
        RECT  46.512 0 46.536 0.084 ;
    END
  END kr_v
  PIN open_bank
    DIRECTION INPUT ;
    USE SIGNAL ;
    PORT
      LAYER M4 ;
        RECT  0 24.048 0.084 24.072 ;
    END
  END open_bank
  PIN open_count[0]
    DIRECTION INPUT ;
    USE SIGNAL ;
    PORT
      LAYER M4 ;
        RECT  0 24.144 0.084 24.168 ;
    END
  END open_count[0]
  PIN open_count[1]
    DIRECTION INPUT ;
    USE SIGNAL ;
    PORT
      LAYER M4 ;
        RECT  0 24.24 0.084 24.264 ;
    END
  END open_count[1]
  PIN open_count[2]
    DIRECTION INPUT ;
    USE SIGNAL ;
    PORT
      LAYER M4 ;
        RECT  0 24.336 0.084 24.36 ;
    END
  END open_count[2]
  PIN open_count[3]
    DIRECTION INPUT ;
    USE SIGNAL ;
    PORT
      LAYER M4 ;
        RECT  0 24.432 0.084 24.456 ;
    END
  END open_count[3]
  PIN open_count[4]
    DIRECTION INPUT ;
    USE SIGNAL ;
    PORT
      LAYER M4 ;
        RECT  0 24.528 0.084 24.552 ;
    END
  END open_count[4]
  PIN open_count[5]
    DIRECTION INPUT ;
    USE SIGNAL ;
    PORT
      LAYER M4 ;
        RECT  0 24.624 0.084 24.648 ;
    END
  END open_count[5]
  PIN open_count[6]
    DIRECTION INPUT ;
    USE SIGNAL ;
    PORT
      LAYER M4 ;
        RECT  0 24.72 0.084 24.744 ;
    END
  END open_count[6]
  PIN open_epoch[0]
    DIRECTION INPUT ;
    USE SIGNAL ;
    PORT
      LAYER M4 ;
        RECT  0 24.816 0.084 24.84 ;
    END
  END open_epoch[0]
  PIN open_epoch[10]
    DIRECTION INPUT ;
    USE SIGNAL ;
    PORT
      LAYER M4 ;
        RECT  0 29.232 0.084 29.256 ;
    END
  END open_epoch[10]
  PIN open_epoch[11]
    DIRECTION INPUT ;
    USE SIGNAL ;
    PORT
      LAYER M4 ;
        RECT  0 29.328 0.084 29.352 ;
    END
  END open_epoch[11]
  PIN open_epoch[12]
    DIRECTION INPUT ;
    USE SIGNAL ;
    PORT
      LAYER M4 ;
        RECT  0 29.424 0.084 29.448 ;
    END
  END open_epoch[12]
  PIN open_epoch[13]
    DIRECTION INPUT ;
    USE SIGNAL ;
    PORT
      LAYER M4 ;
        RECT  0 29.52 0.084 29.544 ;
    END
  END open_epoch[13]
  PIN open_epoch[14]
    DIRECTION INPUT ;
    USE SIGNAL ;
    PORT
      LAYER M4 ;
        RECT  0 29.616 0.084 29.64 ;
    END
  END open_epoch[14]
  PIN open_epoch[15]
    DIRECTION INPUT ;
    USE SIGNAL ;
    PORT
      LAYER M4 ;
        RECT  0 29.712 0.084 29.736 ;
    END
  END open_epoch[15]
  PIN open_epoch[1]
    DIRECTION INPUT ;
    USE SIGNAL ;
    PORT
      LAYER M4 ;
        RECT  0 24.912 0.084 24.936 ;
    END
  END open_epoch[1]
  PIN open_epoch[2]
    DIRECTION INPUT ;
    USE SIGNAL ;
    PORT
      LAYER M4 ;
        RECT  0 25.008 0.084 25.032 ;
    END
  END open_epoch[2]
  PIN open_epoch[3]
    DIRECTION INPUT ;
    USE SIGNAL ;
    PORT
      LAYER M4 ;
        RECT  0 25.104 0.084 25.128 ;
    END
  END open_epoch[3]
  PIN open_epoch[4]
    DIRECTION INPUT ;
    USE SIGNAL ;
    PORT
      LAYER M4 ;
        RECT  0 25.2 0.084 25.224 ;
    END
  END open_epoch[4]
  PIN open_epoch[5]
    DIRECTION INPUT ;
    USE SIGNAL ;
    PORT
      LAYER M4 ;
        RECT  0 25.296 0.084 25.32 ;
    END
  END open_epoch[5]
  PIN open_epoch[6]
    DIRECTION INPUT ;
    USE SIGNAL ;
    PORT
      LAYER M4 ;
        RECT  0 25.392 0.084 25.416 ;
    END
  END open_epoch[6]
  PIN open_epoch[7]
    DIRECTION INPUT ;
    USE SIGNAL ;
    PORT
      LAYER M4 ;
        RECT  0 25.488 0.084 25.512 ;
    END
  END open_epoch[7]
  PIN open_epoch[8]
    DIRECTION INPUT ;
    USE SIGNAL ;
    PORT
      LAYER M4 ;
        RECT  0 29.04 0.084 29.064 ;
    END
  END open_epoch[8]
  PIN open_epoch[9]
    DIRECTION INPUT ;
    USE SIGNAL ;
    PORT
      LAYER M4 ;
        RECT  0 29.136 0.084 29.16 ;
    END
  END open_epoch[9]
  PIN open_v
    DIRECTION INPUT ;
    USE SIGNAL ;
    PORT
      LAYER M4 ;
        RECT  0 29.808 0.084 29.832 ;
    END
  END open_v
  PIN out_data[0]
    DIRECTION OUTPUT ;
    USE SIGNAL ;
    PORT
      LAYER M5 ;
        RECT  8.4 112.236 8.424 112.32 ;
    END
  END out_data[0]
  PIN out_data[100]
    DIRECTION OUTPUT ;
    USE SIGNAL ;
    PORT
      LAYER M5 ;
        RECT  4.944 112.236 4.968 112.32 ;
    END
  END out_data[100]
  PIN out_data[101]
    DIRECTION OUTPUT ;
    USE SIGNAL ;
    PORT
      LAYER M5 ;
        RECT  5.04 112.236 5.064 112.32 ;
    END
  END out_data[101]
  PIN out_data[102]
    DIRECTION OUTPUT ;
    USE SIGNAL ;
    PORT
      LAYER M5 ;
        RECT  5.136 112.236 5.16 112.32 ;
    END
  END out_data[102]
  PIN out_data[103]
    DIRECTION OUTPUT ;
    USE SIGNAL ;
    PORT
      LAYER M5 ;
        RECT  5.232 112.236 5.256 112.32 ;
    END
  END out_data[103]
  PIN out_data[104]
    DIRECTION OUTPUT ;
    USE SIGNAL ;
    PORT
      LAYER M5 ;
        RECT  31.44 112.236 31.464 112.32 ;
    END
  END out_data[104]
  PIN out_data[105]
    DIRECTION OUTPUT ;
    USE SIGNAL ;
    PORT
      LAYER M5 ;
        RECT  31.536 112.236 31.56 112.32 ;
    END
  END out_data[105]
  PIN out_data[106]
    DIRECTION OUTPUT ;
    USE SIGNAL ;
    PORT
      LAYER M5 ;
        RECT  31.632 112.236 31.656 112.32 ;
    END
  END out_data[106]
  PIN out_data[107]
    DIRECTION OUTPUT ;
    USE SIGNAL ;
    PORT
      LAYER M5 ;
        RECT  31.728 112.236 31.752 112.32 ;
    END
  END out_data[107]
  PIN out_data[108]
    DIRECTION OUTPUT ;
    USE SIGNAL ;
    PORT
      LAYER M5 ;
        RECT  31.824 112.236 31.848 112.32 ;
    END
  END out_data[108]
  PIN out_data[109]
    DIRECTION OUTPUT ;
    USE SIGNAL ;
    PORT
      LAYER M5 ;
        RECT  31.92 112.236 31.944 112.32 ;
    END
  END out_data[109]
  PIN out_data[10]
    DIRECTION OUTPUT ;
    USE SIGNAL ;
    PORT
      LAYER M5 ;
        RECT  21.648 112.236 21.672 112.32 ;
    END
  END out_data[10]
  PIN out_data[110]
    DIRECTION OUTPUT ;
    USE SIGNAL ;
    PORT
      LAYER M5 ;
        RECT  32.016 112.236 32.04 112.32 ;
    END
  END out_data[110]
  PIN out_data[111]
    DIRECTION OUTPUT ;
    USE SIGNAL ;
    PORT
      LAYER M5 ;
        RECT  32.112 112.236 32.136 112.32 ;
    END
  END out_data[111]
  PIN out_data[112]
    DIRECTION OUTPUT ;
    USE SIGNAL ;
    PORT
      LAYER M5 ;
        RECT  32.208 112.236 32.232 112.32 ;
    END
  END out_data[112]
  PIN out_data[113]
    DIRECTION OUTPUT ;
    USE SIGNAL ;
    PORT
      LAYER M5 ;
        RECT  32.304 112.236 32.328 112.32 ;
    END
  END out_data[113]
  PIN out_data[114]
    DIRECTION OUTPUT ;
    USE SIGNAL ;
    PORT
      LAYER M5 ;
        RECT  32.4 112.236 32.424 112.32 ;
    END
  END out_data[114]
  PIN out_data[115]
    DIRECTION OUTPUT ;
    USE SIGNAL ;
    PORT
      LAYER M5 ;
        RECT  32.496 112.236 32.52 112.32 ;
    END
  END out_data[115]
  PIN out_data[116]
    DIRECTION OUTPUT ;
    USE SIGNAL ;
    PORT
      LAYER M5 ;
        RECT  32.592 112.236 32.616 112.32 ;
    END
  END out_data[116]
  PIN out_data[117]
    DIRECTION OUTPUT ;
    USE SIGNAL ;
    PORT
      LAYER M5 ;
        RECT  32.688 112.236 32.712 112.32 ;
    END
  END out_data[117]
  PIN out_data[118]
    DIRECTION OUTPUT ;
    USE SIGNAL ;
    PORT
      LAYER M5 ;
        RECT  32.784 112.236 32.808 112.32 ;
    END
  END out_data[118]
  PIN out_data[119]
    DIRECTION OUTPUT ;
    USE SIGNAL ;
    PORT
      LAYER M5 ;
        RECT  32.88 112.236 32.904 112.32 ;
    END
  END out_data[119]
  PIN out_data[11]
    DIRECTION OUTPUT ;
    USE SIGNAL ;
    PORT
      LAYER M5 ;
        RECT  21.744 112.236 21.768 112.32 ;
    END
  END out_data[11]
  PIN out_data[120]
    DIRECTION OUTPUT ;
    USE SIGNAL ;
    PORT
      LAYER M5 ;
        RECT  32.976 112.236 33 112.32 ;
    END
  END out_data[120]
  PIN out_data[121]
    DIRECTION OUTPUT ;
    USE SIGNAL ;
    PORT
      LAYER M5 ;
        RECT  33.072 112.236 33.096 112.32 ;
    END
  END out_data[121]
  PIN out_data[122]
    DIRECTION OUTPUT ;
    USE SIGNAL ;
    PORT
      LAYER M5 ;
        RECT  33.168 112.236 33.192 112.32 ;
    END
  END out_data[122]
  PIN out_data[123]
    DIRECTION OUTPUT ;
    USE SIGNAL ;
    PORT
      LAYER M5 ;
        RECT  33.264 112.236 33.288 112.32 ;
    END
  END out_data[123]
  PIN out_data[124]
    DIRECTION OUTPUT ;
    USE SIGNAL ;
    PORT
      LAYER M5 ;
        RECT  33.36 112.236 33.384 112.32 ;
    END
  END out_data[124]
  PIN out_data[125]
    DIRECTION OUTPUT ;
    USE SIGNAL ;
    PORT
      LAYER M5 ;
        RECT  33.456 112.236 33.48 112.32 ;
    END
  END out_data[125]
  PIN out_data[126]
    DIRECTION OUTPUT ;
    USE SIGNAL ;
    PORT
      LAYER M5 ;
        RECT  33.552 112.236 33.576 112.32 ;
    END
  END out_data[126]
  PIN out_data[127]
    DIRECTION OUTPUT ;
    USE SIGNAL ;
    PORT
      LAYER M5 ;
        RECT  33.648 112.236 33.672 112.32 ;
    END
  END out_data[127]
  PIN out_data[128]
    DIRECTION OUTPUT ;
    USE SIGNAL ;
    PORT
      LAYER M5 ;
        RECT  33.744 112.236 33.768 112.32 ;
    END
  END out_data[128]
  PIN out_data[129]
    DIRECTION OUTPUT ;
    USE SIGNAL ;
    PORT
      LAYER M5 ;
        RECT  33.84 112.236 33.864 112.32 ;
    END
  END out_data[129]
  PIN out_data[12]
    DIRECTION OUTPUT ;
    USE SIGNAL ;
    PORT
      LAYER M5 ;
        RECT  21.84 112.236 21.864 112.32 ;
    END
  END out_data[12]
  PIN out_data[130]
    DIRECTION OUTPUT ;
    USE SIGNAL ;
    PORT
      LAYER M5 ;
        RECT  33.936 112.236 33.96 112.32 ;
    END
  END out_data[130]
  PIN out_data[131]
    DIRECTION OUTPUT ;
    USE SIGNAL ;
    PORT
      LAYER M5 ;
        RECT  34.032 112.236 34.056 112.32 ;
    END
  END out_data[131]
  PIN out_data[132]
    DIRECTION OUTPUT ;
    USE SIGNAL ;
    PORT
      LAYER M5 ;
        RECT  34.128 112.236 34.152 112.32 ;
    END
  END out_data[132]
  PIN out_data[133]
    DIRECTION OUTPUT ;
    USE SIGNAL ;
    PORT
      LAYER M5 ;
        RECT  34.224 112.236 34.248 112.32 ;
    END
  END out_data[133]
  PIN out_data[134]
    DIRECTION OUTPUT ;
    USE SIGNAL ;
    PORT
      LAYER M5 ;
        RECT  34.32 112.236 34.344 112.32 ;
    END
  END out_data[134]
  PIN out_data[135]
    DIRECTION OUTPUT ;
    USE SIGNAL ;
    PORT
      LAYER M5 ;
        RECT  34.416 112.236 34.44 112.32 ;
    END
  END out_data[135]
  PIN out_data[136]
    DIRECTION OUTPUT ;
    USE SIGNAL ;
    PORT
      LAYER M5 ;
        RECT  28.368 112.236 28.392 112.32 ;
    END
  END out_data[136]
  PIN out_data[137]
    DIRECTION OUTPUT ;
    USE SIGNAL ;
    PORT
      LAYER M5 ;
        RECT  28.464 112.236 28.488 112.32 ;
    END
  END out_data[137]
  PIN out_data[138]
    DIRECTION OUTPUT ;
    USE SIGNAL ;
    PORT
      LAYER M5 ;
        RECT  28.56 112.236 28.584 112.32 ;
    END
  END out_data[138]
  PIN out_data[139]
    DIRECTION OUTPUT ;
    USE SIGNAL ;
    PORT
      LAYER M5 ;
        RECT  28.656 112.236 28.68 112.32 ;
    END
  END out_data[139]
  PIN out_data[13]
    DIRECTION OUTPUT ;
    USE SIGNAL ;
    PORT
      LAYER M5 ;
        RECT  21.936 112.236 21.96 112.32 ;
    END
  END out_data[13]
  PIN out_data[140]
    DIRECTION OUTPUT ;
    USE SIGNAL ;
    PORT
      LAYER M5 ;
        RECT  28.752 112.236 28.776 112.32 ;
    END
  END out_data[140]
  PIN out_data[141]
    DIRECTION OUTPUT ;
    USE SIGNAL ;
    PORT
      LAYER M5 ;
        RECT  28.848 112.236 28.872 112.32 ;
    END
  END out_data[141]
  PIN out_data[142]
    DIRECTION OUTPUT ;
    USE SIGNAL ;
    PORT
      LAYER M5 ;
        RECT  28.944 112.236 28.968 112.32 ;
    END
  END out_data[142]
  PIN out_data[143]
    DIRECTION OUTPUT ;
    USE SIGNAL ;
    PORT
      LAYER M5 ;
        RECT  29.04 112.236 29.064 112.32 ;
    END
  END out_data[143]
  PIN out_data[144]
    DIRECTION OUTPUT ;
    USE SIGNAL ;
    PORT
      LAYER M5 ;
        RECT  29.136 112.236 29.16 112.32 ;
    END
  END out_data[144]
  PIN out_data[145]
    DIRECTION OUTPUT ;
    USE SIGNAL ;
    PORT
      LAYER M5 ;
        RECT  29.232 112.236 29.256 112.32 ;
    END
  END out_data[145]
  PIN out_data[146]
    DIRECTION OUTPUT ;
    USE SIGNAL ;
    PORT
      LAYER M5 ;
        RECT  29.328 112.236 29.352 112.32 ;
    END
  END out_data[146]
  PIN out_data[147]
    DIRECTION OUTPUT ;
    USE SIGNAL ;
    PORT
      LAYER M5 ;
        RECT  29.424 112.236 29.448 112.32 ;
    END
  END out_data[147]
  PIN out_data[148]
    DIRECTION OUTPUT ;
    USE SIGNAL ;
    PORT
      LAYER M5 ;
        RECT  29.52 112.236 29.544 112.32 ;
    END
  END out_data[148]
  PIN out_data[149]
    DIRECTION OUTPUT ;
    USE SIGNAL ;
    PORT
      LAYER M5 ;
        RECT  29.616 112.236 29.64 112.32 ;
    END
  END out_data[149]
  PIN out_data[14]
    DIRECTION OUTPUT ;
    USE SIGNAL ;
    PORT
      LAYER M5 ;
        RECT  22.032 112.236 22.056 112.32 ;
    END
  END out_data[14]
  PIN out_data[150]
    DIRECTION OUTPUT ;
    USE SIGNAL ;
    PORT
      LAYER M5 ;
        RECT  29.712 112.236 29.736 112.32 ;
    END
  END out_data[150]
  PIN out_data[151]
    DIRECTION OUTPUT ;
    USE SIGNAL ;
    PORT
      LAYER M5 ;
        RECT  29.808 112.236 29.832 112.32 ;
    END
  END out_data[151]
  PIN out_data[152]
    DIRECTION OUTPUT ;
    USE SIGNAL ;
    PORT
      LAYER M5 ;
        RECT  29.904 112.236 29.928 112.32 ;
    END
  END out_data[152]
  PIN out_data[153]
    DIRECTION OUTPUT ;
    USE SIGNAL ;
    PORT
      LAYER M5 ;
        RECT  30 112.236 30.024 112.32 ;
    END
  END out_data[153]
  PIN out_data[154]
    DIRECTION OUTPUT ;
    USE SIGNAL ;
    PORT
      LAYER M5 ;
        RECT  30.096 112.236 30.12 112.32 ;
    END
  END out_data[154]
  PIN out_data[155]
    DIRECTION OUTPUT ;
    USE SIGNAL ;
    PORT
      LAYER M5 ;
        RECT  30.192 112.236 30.216 112.32 ;
    END
  END out_data[155]
  PIN out_data[156]
    DIRECTION OUTPUT ;
    USE SIGNAL ;
    PORT
      LAYER M5 ;
        RECT  30.288 112.236 30.312 112.32 ;
    END
  END out_data[156]
  PIN out_data[157]
    DIRECTION OUTPUT ;
    USE SIGNAL ;
    PORT
      LAYER M5 ;
        RECT  30.384 112.236 30.408 112.32 ;
    END
  END out_data[157]
  PIN out_data[158]
    DIRECTION OUTPUT ;
    USE SIGNAL ;
    PORT
      LAYER M5 ;
        RECT  30.48 112.236 30.504 112.32 ;
    END
  END out_data[158]
  PIN out_data[159]
    DIRECTION OUTPUT ;
    USE SIGNAL ;
    PORT
      LAYER M5 ;
        RECT  30.576 112.236 30.6 112.32 ;
    END
  END out_data[159]
  PIN out_data[15]
    DIRECTION OUTPUT ;
    USE SIGNAL ;
    PORT
      LAYER M5 ;
        RECT  22.128 112.236 22.152 112.32 ;
    END
  END out_data[15]
  PIN out_data[160]
    DIRECTION OUTPUT ;
    USE SIGNAL ;
    PORT
      LAYER M5 ;
        RECT  30.672 112.236 30.696 112.32 ;
    END
  END out_data[160]
  PIN out_data[161]
    DIRECTION OUTPUT ;
    USE SIGNAL ;
    PORT
      LAYER M5 ;
        RECT  30.768 112.236 30.792 112.32 ;
    END
  END out_data[161]
  PIN out_data[162]
    DIRECTION OUTPUT ;
    USE SIGNAL ;
    PORT
      LAYER M5 ;
        RECT  30.864 112.236 30.888 112.32 ;
    END
  END out_data[162]
  PIN out_data[163]
    DIRECTION OUTPUT ;
    USE SIGNAL ;
    PORT
      LAYER M5 ;
        RECT  30.96 112.236 30.984 112.32 ;
    END
  END out_data[163]
  PIN out_data[164]
    DIRECTION OUTPUT ;
    USE SIGNAL ;
    PORT
      LAYER M5 ;
        RECT  31.056 112.236 31.08 112.32 ;
    END
  END out_data[164]
  PIN out_data[165]
    DIRECTION OUTPUT ;
    USE SIGNAL ;
    PORT
      LAYER M5 ;
        RECT  31.152 112.236 31.176 112.32 ;
    END
  END out_data[165]
  PIN out_data[166]
    DIRECTION OUTPUT ;
    USE SIGNAL ;
    PORT
      LAYER M5 ;
        RECT  31.248 112.236 31.272 112.32 ;
    END
  END out_data[166]
  PIN out_data[167]
    DIRECTION OUTPUT ;
    USE SIGNAL ;
    PORT
      LAYER M5 ;
        RECT  31.344 112.236 31.368 112.32 ;
    END
  END out_data[167]
  PIN out_data[168]
    DIRECTION OUTPUT ;
    USE SIGNAL ;
    PORT
      LAYER M5 ;
        RECT  25.296 112.236 25.32 112.32 ;
    END
  END out_data[168]
  PIN out_data[169]
    DIRECTION OUTPUT ;
    USE SIGNAL ;
    PORT
      LAYER M5 ;
        RECT  25.392 112.236 25.416 112.32 ;
    END
  END out_data[169]
  PIN out_data[16]
    DIRECTION OUTPUT ;
    USE SIGNAL ;
    PORT
      LAYER M5 ;
        RECT  22.224 112.236 22.248 112.32 ;
    END
  END out_data[16]
  PIN out_data[170]
    DIRECTION OUTPUT ;
    USE SIGNAL ;
    PORT
      LAYER M5 ;
        RECT  25.488 112.236 25.512 112.32 ;
    END
  END out_data[170]
  PIN out_data[171]
    DIRECTION OUTPUT ;
    USE SIGNAL ;
    PORT
      LAYER M5 ;
        RECT  25.584 112.236 25.608 112.32 ;
    END
  END out_data[171]
  PIN out_data[172]
    DIRECTION OUTPUT ;
    USE SIGNAL ;
    PORT
      LAYER M5 ;
        RECT  25.68 112.236 25.704 112.32 ;
    END
  END out_data[172]
  PIN out_data[173]
    DIRECTION OUTPUT ;
    USE SIGNAL ;
    PORT
      LAYER M5 ;
        RECT  25.776 112.236 25.8 112.32 ;
    END
  END out_data[173]
  PIN out_data[174]
    DIRECTION OUTPUT ;
    USE SIGNAL ;
    PORT
      LAYER M5 ;
        RECT  25.872 112.236 25.896 112.32 ;
    END
  END out_data[174]
  PIN out_data[175]
    DIRECTION OUTPUT ;
    USE SIGNAL ;
    PORT
      LAYER M5 ;
        RECT  25.968 112.236 25.992 112.32 ;
    END
  END out_data[175]
  PIN out_data[176]
    DIRECTION OUTPUT ;
    USE SIGNAL ;
    PORT
      LAYER M5 ;
        RECT  26.064 112.236 26.088 112.32 ;
    END
  END out_data[176]
  PIN out_data[177]
    DIRECTION OUTPUT ;
    USE SIGNAL ;
    PORT
      LAYER M5 ;
        RECT  26.16 112.236 26.184 112.32 ;
    END
  END out_data[177]
  PIN out_data[178]
    DIRECTION OUTPUT ;
    USE SIGNAL ;
    PORT
      LAYER M5 ;
        RECT  26.256 112.236 26.28 112.32 ;
    END
  END out_data[178]
  PIN out_data[179]
    DIRECTION OUTPUT ;
    USE SIGNAL ;
    PORT
      LAYER M5 ;
        RECT  26.352 112.236 26.376 112.32 ;
    END
  END out_data[179]
  PIN out_data[17]
    DIRECTION OUTPUT ;
    USE SIGNAL ;
    PORT
      LAYER M5 ;
        RECT  22.32 112.236 22.344 112.32 ;
    END
  END out_data[17]
  PIN out_data[180]
    DIRECTION OUTPUT ;
    USE SIGNAL ;
    PORT
      LAYER M5 ;
        RECT  26.448 112.236 26.472 112.32 ;
    END
  END out_data[180]
  PIN out_data[181]
    DIRECTION OUTPUT ;
    USE SIGNAL ;
    PORT
      LAYER M5 ;
        RECT  26.544 112.236 26.568 112.32 ;
    END
  END out_data[181]
  PIN out_data[182]
    DIRECTION OUTPUT ;
    USE SIGNAL ;
    PORT
      LAYER M5 ;
        RECT  26.64 112.236 26.664 112.32 ;
    END
  END out_data[182]
  PIN out_data[183]
    DIRECTION OUTPUT ;
    USE SIGNAL ;
    PORT
      LAYER M5 ;
        RECT  26.736 112.236 26.76 112.32 ;
    END
  END out_data[183]
  PIN out_data[184]
    DIRECTION OUTPUT ;
    USE SIGNAL ;
    PORT
      LAYER M5 ;
        RECT  26.832 112.236 26.856 112.32 ;
    END
  END out_data[184]
  PIN out_data[185]
    DIRECTION OUTPUT ;
    USE SIGNAL ;
    PORT
      LAYER M5 ;
        RECT  26.928 112.236 26.952 112.32 ;
    END
  END out_data[185]
  PIN out_data[186]
    DIRECTION OUTPUT ;
    USE SIGNAL ;
    PORT
      LAYER M5 ;
        RECT  27.024 112.236 27.048 112.32 ;
    END
  END out_data[186]
  PIN out_data[187]
    DIRECTION OUTPUT ;
    USE SIGNAL ;
    PORT
      LAYER M5 ;
        RECT  27.12 112.236 27.144 112.32 ;
    END
  END out_data[187]
  PIN out_data[188]
    DIRECTION OUTPUT ;
    USE SIGNAL ;
    PORT
      LAYER M5 ;
        RECT  27.216 112.236 27.24 112.32 ;
    END
  END out_data[188]
  PIN out_data[189]
    DIRECTION OUTPUT ;
    USE SIGNAL ;
    PORT
      LAYER M5 ;
        RECT  27.312 112.236 27.336 112.32 ;
    END
  END out_data[189]
  PIN out_data[18]
    DIRECTION OUTPUT ;
    USE SIGNAL ;
    PORT
      LAYER M5 ;
        RECT  22.416 112.236 22.44 112.32 ;
    END
  END out_data[18]
  PIN out_data[190]
    DIRECTION OUTPUT ;
    USE SIGNAL ;
    PORT
      LAYER M5 ;
        RECT  27.408 112.236 27.432 112.32 ;
    END
  END out_data[190]
  PIN out_data[191]
    DIRECTION OUTPUT ;
    USE SIGNAL ;
    PORT
      LAYER M5 ;
        RECT  27.504 112.236 27.528 112.32 ;
    END
  END out_data[191]
  PIN out_data[192]
    DIRECTION OUTPUT ;
    USE SIGNAL ;
    PORT
      LAYER M5 ;
        RECT  27.6 112.236 27.624 112.32 ;
    END
  END out_data[192]
  PIN out_data[193]
    DIRECTION OUTPUT ;
    USE SIGNAL ;
    PORT
      LAYER M5 ;
        RECT  27.696 112.236 27.72 112.32 ;
    END
  END out_data[193]
  PIN out_data[194]
    DIRECTION OUTPUT ;
    USE SIGNAL ;
    PORT
      LAYER M5 ;
        RECT  27.792 112.236 27.816 112.32 ;
    END
  END out_data[194]
  PIN out_data[195]
    DIRECTION OUTPUT ;
    USE SIGNAL ;
    PORT
      LAYER M5 ;
        RECT  27.888 112.236 27.912 112.32 ;
    END
  END out_data[195]
  PIN out_data[196]
    DIRECTION OUTPUT ;
    USE SIGNAL ;
    PORT
      LAYER M5 ;
        RECT  27.984 112.236 28.008 112.32 ;
    END
  END out_data[196]
  PIN out_data[197]
    DIRECTION OUTPUT ;
    USE SIGNAL ;
    PORT
      LAYER M5 ;
        RECT  28.08 112.236 28.104 112.32 ;
    END
  END out_data[197]
  PIN out_data[198]
    DIRECTION OUTPUT ;
    USE SIGNAL ;
    PORT
      LAYER M5 ;
        RECT  28.176 112.236 28.2 112.32 ;
    END
  END out_data[198]
  PIN out_data[199]
    DIRECTION OUTPUT ;
    USE SIGNAL ;
    PORT
      LAYER M5 ;
        RECT  28.272 112.236 28.296 112.32 ;
    END
  END out_data[199]
  PIN out_data[19]
    DIRECTION OUTPUT ;
    USE SIGNAL ;
    PORT
      LAYER M5 ;
        RECT  22.512 112.236 22.536 112.32 ;
    END
  END out_data[19]
  PIN out_data[1]
    DIRECTION OUTPUT ;
    USE SIGNAL ;
    PORT
      LAYER M5 ;
        RECT  8.496 112.236 8.52 112.32 ;
    END
  END out_data[1]
  PIN out_data[200]
    DIRECTION OUTPUT ;
    USE SIGNAL ;
    PORT
      LAYER M5 ;
        RECT  37.584 112.236 37.608 112.32 ;
    END
  END out_data[200]
  PIN out_data[201]
    DIRECTION OUTPUT ;
    USE SIGNAL ;
    PORT
      LAYER M5 ;
        RECT  37.68 112.236 37.704 112.32 ;
    END
  END out_data[201]
  PIN out_data[202]
    DIRECTION OUTPUT ;
    USE SIGNAL ;
    PORT
      LAYER M5 ;
        RECT  37.776 112.236 37.8 112.32 ;
    END
  END out_data[202]
  PIN out_data[203]
    DIRECTION OUTPUT ;
    USE SIGNAL ;
    PORT
      LAYER M5 ;
        RECT  37.872 112.236 37.896 112.32 ;
    END
  END out_data[203]
  PIN out_data[204]
    DIRECTION OUTPUT ;
    USE SIGNAL ;
    PORT
      LAYER M5 ;
        RECT  37.968 112.236 37.992 112.32 ;
    END
  END out_data[204]
  PIN out_data[205]
    DIRECTION OUTPUT ;
    USE SIGNAL ;
    PORT
      LAYER M5 ;
        RECT  38.064 112.236 38.088 112.32 ;
    END
  END out_data[205]
  PIN out_data[206]
    DIRECTION OUTPUT ;
    USE SIGNAL ;
    PORT
      LAYER M5 ;
        RECT  38.16 112.236 38.184 112.32 ;
    END
  END out_data[206]
  PIN out_data[207]
    DIRECTION OUTPUT ;
    USE SIGNAL ;
    PORT
      LAYER M5 ;
        RECT  38.256 112.236 38.28 112.32 ;
    END
  END out_data[207]
  PIN out_data[208]
    DIRECTION OUTPUT ;
    USE SIGNAL ;
    PORT
      LAYER M5 ;
        RECT  38.352 112.236 38.376 112.32 ;
    END
  END out_data[208]
  PIN out_data[209]
    DIRECTION OUTPUT ;
    USE SIGNAL ;
    PORT
      LAYER M5 ;
        RECT  38.448 112.236 38.472 112.32 ;
    END
  END out_data[209]
  PIN out_data[20]
    DIRECTION OUTPUT ;
    USE SIGNAL ;
    PORT
      LAYER M5 ;
        RECT  22.608 112.236 22.632 112.32 ;
    END
  END out_data[20]
  PIN out_data[210]
    DIRECTION OUTPUT ;
    USE SIGNAL ;
    PORT
      LAYER M5 ;
        RECT  38.544 112.236 38.568 112.32 ;
    END
  END out_data[210]
  PIN out_data[211]
    DIRECTION OUTPUT ;
    USE SIGNAL ;
    PORT
      LAYER M5 ;
        RECT  38.64 112.236 38.664 112.32 ;
    END
  END out_data[211]
  PIN out_data[212]
    DIRECTION OUTPUT ;
    USE SIGNAL ;
    PORT
      LAYER M5 ;
        RECT  38.736 112.236 38.76 112.32 ;
    END
  END out_data[212]
  PIN out_data[213]
    DIRECTION OUTPUT ;
    USE SIGNAL ;
    PORT
      LAYER M5 ;
        RECT  38.832 112.236 38.856 112.32 ;
    END
  END out_data[213]
  PIN out_data[214]
    DIRECTION OUTPUT ;
    USE SIGNAL ;
    PORT
      LAYER M5 ;
        RECT  38.928 112.236 38.952 112.32 ;
    END
  END out_data[214]
  PIN out_data[215]
    DIRECTION OUTPUT ;
    USE SIGNAL ;
    PORT
      LAYER M5 ;
        RECT  39.024 112.236 39.048 112.32 ;
    END
  END out_data[215]
  PIN out_data[216]
    DIRECTION OUTPUT ;
    USE SIGNAL ;
    PORT
      LAYER M5 ;
        RECT  39.12 112.236 39.144 112.32 ;
    END
  END out_data[216]
  PIN out_data[217]
    DIRECTION OUTPUT ;
    USE SIGNAL ;
    PORT
      LAYER M5 ;
        RECT  39.216 112.236 39.24 112.32 ;
    END
  END out_data[217]
  PIN out_data[218]
    DIRECTION OUTPUT ;
    USE SIGNAL ;
    PORT
      LAYER M5 ;
        RECT  39.312 112.236 39.336 112.32 ;
    END
  END out_data[218]
  PIN out_data[219]
    DIRECTION OUTPUT ;
    USE SIGNAL ;
    PORT
      LAYER M5 ;
        RECT  39.408 112.236 39.432 112.32 ;
    END
  END out_data[219]
  PIN out_data[21]
    DIRECTION OUTPUT ;
    USE SIGNAL ;
    PORT
      LAYER M5 ;
        RECT  22.704 112.236 22.728 112.32 ;
    END
  END out_data[21]
  PIN out_data[220]
    DIRECTION OUTPUT ;
    USE SIGNAL ;
    PORT
      LAYER M5 ;
        RECT  39.504 112.236 39.528 112.32 ;
    END
  END out_data[220]
  PIN out_data[221]
    DIRECTION OUTPUT ;
    USE SIGNAL ;
    PORT
      LAYER M5 ;
        RECT  39.6 112.236 39.624 112.32 ;
    END
  END out_data[221]
  PIN out_data[222]
    DIRECTION OUTPUT ;
    USE SIGNAL ;
    PORT
      LAYER M5 ;
        RECT  39.696 112.236 39.72 112.32 ;
    END
  END out_data[222]
  PIN out_data[223]
    DIRECTION OUTPUT ;
    USE SIGNAL ;
    PORT
      LAYER M5 ;
        RECT  39.792 112.236 39.816 112.32 ;
    END
  END out_data[223]
  PIN out_data[224]
    DIRECTION OUTPUT ;
    USE SIGNAL ;
    PORT
      LAYER M5 ;
        RECT  39.888 112.236 39.912 112.32 ;
    END
  END out_data[224]
  PIN out_data[225]
    DIRECTION OUTPUT ;
    USE SIGNAL ;
    PORT
      LAYER M5 ;
        RECT  39.984 112.236 40.008 112.32 ;
    END
  END out_data[225]
  PIN out_data[226]
    DIRECTION OUTPUT ;
    USE SIGNAL ;
    PORT
      LAYER M5 ;
        RECT  40.08 112.236 40.104 112.32 ;
    END
  END out_data[226]
  PIN out_data[227]
    DIRECTION OUTPUT ;
    USE SIGNAL ;
    PORT
      LAYER M5 ;
        RECT  40.176 112.236 40.2 112.32 ;
    END
  END out_data[227]
  PIN out_data[228]
    DIRECTION OUTPUT ;
    USE SIGNAL ;
    PORT
      LAYER M5 ;
        RECT  40.272 112.236 40.296 112.32 ;
    END
  END out_data[228]
  PIN out_data[229]
    DIRECTION OUTPUT ;
    USE SIGNAL ;
    PORT
      LAYER M5 ;
        RECT  40.368 112.236 40.392 112.32 ;
    END
  END out_data[229]
  PIN out_data[22]
    DIRECTION OUTPUT ;
    USE SIGNAL ;
    PORT
      LAYER M5 ;
        RECT  22.8 112.236 22.824 112.32 ;
    END
  END out_data[22]
  PIN out_data[230]
    DIRECTION OUTPUT ;
    USE SIGNAL ;
    PORT
      LAYER M5 ;
        RECT  40.464 112.236 40.488 112.32 ;
    END
  END out_data[230]
  PIN out_data[231]
    DIRECTION OUTPUT ;
    USE SIGNAL ;
    PORT
      LAYER M5 ;
        RECT  40.56 112.236 40.584 112.32 ;
    END
  END out_data[231]
  PIN out_data[232]
    DIRECTION OUTPUT ;
    USE SIGNAL ;
    PORT
      LAYER M5 ;
        RECT  40.656 112.236 40.68 112.32 ;
    END
  END out_data[232]
  PIN out_data[233]
    DIRECTION OUTPUT ;
    USE SIGNAL ;
    PORT
      LAYER M5 ;
        RECT  40.752 112.236 40.776 112.32 ;
    END
  END out_data[233]
  PIN out_data[234]
    DIRECTION OUTPUT ;
    USE SIGNAL ;
    PORT
      LAYER M5 ;
        RECT  40.848 112.236 40.872 112.32 ;
    END
  END out_data[234]
  PIN out_data[235]
    DIRECTION OUTPUT ;
    USE SIGNAL ;
    PORT
      LAYER M5 ;
        RECT  40.944 112.236 40.968 112.32 ;
    END
  END out_data[235]
  PIN out_data[236]
    DIRECTION OUTPUT ;
    USE SIGNAL ;
    PORT
      LAYER M5 ;
        RECT  41.04 112.236 41.064 112.32 ;
    END
  END out_data[236]
  PIN out_data[237]
    DIRECTION OUTPUT ;
    USE SIGNAL ;
    PORT
      LAYER M5 ;
        RECT  41.136 112.236 41.16 112.32 ;
    END
  END out_data[237]
  PIN out_data[238]
    DIRECTION OUTPUT ;
    USE SIGNAL ;
    PORT
      LAYER M5 ;
        RECT  41.232 112.236 41.256 112.32 ;
    END
  END out_data[238]
  PIN out_data[239]
    DIRECTION OUTPUT ;
    USE SIGNAL ;
    PORT
      LAYER M5 ;
        RECT  41.328 112.236 41.352 112.32 ;
    END
  END out_data[239]
  PIN out_data[23]
    DIRECTION OUTPUT ;
    USE SIGNAL ;
    PORT
      LAYER M5 ;
        RECT  22.896 112.236 22.92 112.32 ;
    END
  END out_data[23]
  PIN out_data[240]
    DIRECTION OUTPUT ;
    USE SIGNAL ;
    PORT
      LAYER M5 ;
        RECT  41.424 112.236 41.448 112.32 ;
    END
  END out_data[240]
  PIN out_data[241]
    DIRECTION OUTPUT ;
    USE SIGNAL ;
    PORT
      LAYER M5 ;
        RECT  41.52 112.236 41.544 112.32 ;
    END
  END out_data[241]
  PIN out_data[242]
    DIRECTION OUTPUT ;
    USE SIGNAL ;
    PORT
      LAYER M5 ;
        RECT  41.616 112.236 41.64 112.32 ;
    END
  END out_data[242]
  PIN out_data[243]
    DIRECTION OUTPUT ;
    USE SIGNAL ;
    PORT
      LAYER M5 ;
        RECT  41.712 112.236 41.736 112.32 ;
    END
  END out_data[243]
  PIN out_data[244]
    DIRECTION OUTPUT ;
    USE SIGNAL ;
    PORT
      LAYER M5 ;
        RECT  41.808 112.236 41.832 112.32 ;
    END
  END out_data[244]
  PIN out_data[245]
    DIRECTION OUTPUT ;
    USE SIGNAL ;
    PORT
      LAYER M5 ;
        RECT  41.904 112.236 41.928 112.32 ;
    END
  END out_data[245]
  PIN out_data[246]
    DIRECTION OUTPUT ;
    USE SIGNAL ;
    PORT
      LAYER M5 ;
        RECT  42 112.236 42.024 112.32 ;
    END
  END out_data[246]
  PIN out_data[247]
    DIRECTION OUTPUT ;
    USE SIGNAL ;
    PORT
      LAYER M5 ;
        RECT  42.096 112.236 42.12 112.32 ;
    END
  END out_data[247]
  PIN out_data[248]
    DIRECTION OUTPUT ;
    USE SIGNAL ;
    PORT
      LAYER M5 ;
        RECT  42.192 112.236 42.216 112.32 ;
    END
  END out_data[248]
  PIN out_data[249]
    DIRECTION OUTPUT ;
    USE SIGNAL ;
    PORT
      LAYER M5 ;
        RECT  42.288 112.236 42.312 112.32 ;
    END
  END out_data[249]
  PIN out_data[24]
    DIRECTION OUTPUT ;
    USE SIGNAL ;
    PORT
      LAYER M5 ;
        RECT  22.992 112.236 23.016 112.32 ;
    END
  END out_data[24]
  PIN out_data[250]
    DIRECTION OUTPUT ;
    USE SIGNAL ;
    PORT
      LAYER M5 ;
        RECT  42.384 112.236 42.408 112.32 ;
    END
  END out_data[250]
  PIN out_data[251]
    DIRECTION OUTPUT ;
    USE SIGNAL ;
    PORT
      LAYER M5 ;
        RECT  42.48 112.236 42.504 112.32 ;
    END
  END out_data[251]
  PIN out_data[252]
    DIRECTION OUTPUT ;
    USE SIGNAL ;
    PORT
      LAYER M5 ;
        RECT  42.576 112.236 42.6 112.32 ;
    END
  END out_data[252]
  PIN out_data[253]
    DIRECTION OUTPUT ;
    USE SIGNAL ;
    PORT
      LAYER M5 ;
        RECT  42.672 112.236 42.696 112.32 ;
    END
  END out_data[253]
  PIN out_data[254]
    DIRECTION OUTPUT ;
    USE SIGNAL ;
    PORT
      LAYER M5 ;
        RECT  42.768 112.236 42.792 112.32 ;
    END
  END out_data[254]
  PIN out_data[255]
    DIRECTION OUTPUT ;
    USE SIGNAL ;
    PORT
      LAYER M5 ;
        RECT  42.864 112.236 42.888 112.32 ;
    END
  END out_data[255]
  PIN out_data[25]
    DIRECTION OUTPUT ;
    USE SIGNAL ;
    PORT
      LAYER M5 ;
        RECT  23.088 112.236 23.112 112.32 ;
    END
  END out_data[25]
  PIN out_data[26]
    DIRECTION OUTPUT ;
    USE SIGNAL ;
    PORT
      LAYER M5 ;
        RECT  23.184 112.236 23.208 112.32 ;
    END
  END out_data[26]
  PIN out_data[27]
    DIRECTION OUTPUT ;
    USE SIGNAL ;
    PORT
      LAYER M5 ;
        RECT  23.28 112.236 23.304 112.32 ;
    END
  END out_data[27]
  PIN out_data[28]
    DIRECTION OUTPUT ;
    USE SIGNAL ;
    PORT
      LAYER M5 ;
        RECT  23.376 112.236 23.4 112.32 ;
    END
  END out_data[28]
  PIN out_data[29]
    DIRECTION OUTPUT ;
    USE SIGNAL ;
    PORT
      LAYER M5 ;
        RECT  23.472 112.236 23.496 112.32 ;
    END
  END out_data[29]
  PIN out_data[2]
    DIRECTION OUTPUT ;
    USE SIGNAL ;
    PORT
      LAYER M5 ;
        RECT  8.592 112.236 8.616 112.32 ;
    END
  END out_data[2]
  PIN out_data[30]
    DIRECTION OUTPUT ;
    USE SIGNAL ;
    PORT
      LAYER M5 ;
        RECT  23.568 112.236 23.592 112.32 ;
    END
  END out_data[30]
  PIN out_data[31]
    DIRECTION OUTPUT ;
    USE SIGNAL ;
    PORT
      LAYER M5 ;
        RECT  23.664 112.236 23.688 112.32 ;
    END
  END out_data[31]
  PIN out_data[32]
    DIRECTION OUTPUT ;
    USE SIGNAL ;
    PORT
      LAYER M5 ;
        RECT  23.76 112.236 23.784 112.32 ;
    END
  END out_data[32]
  PIN out_data[33]
    DIRECTION OUTPUT ;
    USE SIGNAL ;
    PORT
      LAYER M5 ;
        RECT  23.856 112.236 23.88 112.32 ;
    END
  END out_data[33]
  PIN out_data[34]
    DIRECTION OUTPUT ;
    USE SIGNAL ;
    PORT
      LAYER M5 ;
        RECT  23.952 112.236 23.976 112.32 ;
    END
  END out_data[34]
  PIN out_data[35]
    DIRECTION OUTPUT ;
    USE SIGNAL ;
    PORT
      LAYER M5 ;
        RECT  24.048 112.236 24.072 112.32 ;
    END
  END out_data[35]
  PIN out_data[36]
    DIRECTION OUTPUT ;
    USE SIGNAL ;
    PORT
      LAYER M5 ;
        RECT  24.144 112.236 24.168 112.32 ;
    END
  END out_data[36]
  PIN out_data[37]
    DIRECTION OUTPUT ;
    USE SIGNAL ;
    PORT
      LAYER M5 ;
        RECT  24.24 112.236 24.264 112.32 ;
    END
  END out_data[37]
  PIN out_data[38]
    DIRECTION OUTPUT ;
    USE SIGNAL ;
    PORT
      LAYER M5 ;
        RECT  24.336 112.236 24.36 112.32 ;
    END
  END out_data[38]
  PIN out_data[39]
    DIRECTION OUTPUT ;
    USE SIGNAL ;
    PORT
      LAYER M5 ;
        RECT  24.432 112.236 24.456 112.32 ;
    END
  END out_data[39]
  PIN out_data[3]
    DIRECTION OUTPUT ;
    USE SIGNAL ;
    PORT
      LAYER M5 ;
        RECT  8.688 112.236 8.712 112.32 ;
    END
  END out_data[3]
  PIN out_data[40]
    DIRECTION OUTPUT ;
    USE SIGNAL ;
    PORT
      LAYER M5 ;
        RECT  34.512 112.236 34.536 112.32 ;
    END
  END out_data[40]
  PIN out_data[41]
    DIRECTION OUTPUT ;
    USE SIGNAL ;
    PORT
      LAYER M5 ;
        RECT  34.608 112.236 34.632 112.32 ;
    END
  END out_data[41]
  PIN out_data[42]
    DIRECTION OUTPUT ;
    USE SIGNAL ;
    PORT
      LAYER M5 ;
        RECT  34.704 112.236 34.728 112.32 ;
    END
  END out_data[42]
  PIN out_data[43]
    DIRECTION OUTPUT ;
    USE SIGNAL ;
    PORT
      LAYER M5 ;
        RECT  34.8 112.236 34.824 112.32 ;
    END
  END out_data[43]
  PIN out_data[44]
    DIRECTION OUTPUT ;
    USE SIGNAL ;
    PORT
      LAYER M5 ;
        RECT  34.896 112.236 34.92 112.32 ;
    END
  END out_data[44]
  PIN out_data[45]
    DIRECTION OUTPUT ;
    USE SIGNAL ;
    PORT
      LAYER M5 ;
        RECT  34.992 112.236 35.016 112.32 ;
    END
  END out_data[45]
  PIN out_data[46]
    DIRECTION OUTPUT ;
    USE SIGNAL ;
    PORT
      LAYER M5 ;
        RECT  35.088 112.236 35.112 112.32 ;
    END
  END out_data[46]
  PIN out_data[47]
    DIRECTION OUTPUT ;
    USE SIGNAL ;
    PORT
      LAYER M5 ;
        RECT  35.184 112.236 35.208 112.32 ;
    END
  END out_data[47]
  PIN out_data[48]
    DIRECTION OUTPUT ;
    USE SIGNAL ;
    PORT
      LAYER M5 ;
        RECT  35.28 112.236 35.304 112.32 ;
    END
  END out_data[48]
  PIN out_data[49]
    DIRECTION OUTPUT ;
    USE SIGNAL ;
    PORT
      LAYER M5 ;
        RECT  35.376 112.236 35.4 112.32 ;
    END
  END out_data[49]
  PIN out_data[4]
    DIRECTION OUTPUT ;
    USE SIGNAL ;
    PORT
      LAYER M5 ;
        RECT  8.784 112.236 8.808 112.32 ;
    END
  END out_data[4]
  PIN out_data[50]
    DIRECTION OUTPUT ;
    USE SIGNAL ;
    PORT
      LAYER M5 ;
        RECT  35.472 112.236 35.496 112.32 ;
    END
  END out_data[50]
  PIN out_data[51]
    DIRECTION OUTPUT ;
    USE SIGNAL ;
    PORT
      LAYER M5 ;
        RECT  35.568 112.236 35.592 112.32 ;
    END
  END out_data[51]
  PIN out_data[52]
    DIRECTION OUTPUT ;
    USE SIGNAL ;
    PORT
      LAYER M5 ;
        RECT  35.664 112.236 35.688 112.32 ;
    END
  END out_data[52]
  PIN out_data[53]
    DIRECTION OUTPUT ;
    USE SIGNAL ;
    PORT
      LAYER M5 ;
        RECT  35.76 112.236 35.784 112.32 ;
    END
  END out_data[53]
  PIN out_data[54]
    DIRECTION OUTPUT ;
    USE SIGNAL ;
    PORT
      LAYER M5 ;
        RECT  35.856 112.236 35.88 112.32 ;
    END
  END out_data[54]
  PIN out_data[55]
    DIRECTION OUTPUT ;
    USE SIGNAL ;
    PORT
      LAYER M5 ;
        RECT  35.952 112.236 35.976 112.32 ;
    END
  END out_data[55]
  PIN out_data[56]
    DIRECTION OUTPUT ;
    USE SIGNAL ;
    PORT
      LAYER M5 ;
        RECT  36.048 112.236 36.072 112.32 ;
    END
  END out_data[56]
  PIN out_data[57]
    DIRECTION OUTPUT ;
    USE SIGNAL ;
    PORT
      LAYER M5 ;
        RECT  36.144 112.236 36.168 112.32 ;
    END
  END out_data[57]
  PIN out_data[58]
    DIRECTION OUTPUT ;
    USE SIGNAL ;
    PORT
      LAYER M5 ;
        RECT  36.24 112.236 36.264 112.32 ;
    END
  END out_data[58]
  PIN out_data[59]
    DIRECTION OUTPUT ;
    USE SIGNAL ;
    PORT
      LAYER M5 ;
        RECT  36.336 112.236 36.36 112.32 ;
    END
  END out_data[59]
  PIN out_data[5]
    DIRECTION OUTPUT ;
    USE SIGNAL ;
    PORT
      LAYER M5 ;
        RECT  8.88 112.236 8.904 112.32 ;
    END
  END out_data[5]
  PIN out_data[60]
    DIRECTION OUTPUT ;
    USE SIGNAL ;
    PORT
      LAYER M5 ;
        RECT  36.432 112.236 36.456 112.32 ;
    END
  END out_data[60]
  PIN out_data[61]
    DIRECTION OUTPUT ;
    USE SIGNAL ;
    PORT
      LAYER M5 ;
        RECT  36.528 112.236 36.552 112.32 ;
    END
  END out_data[61]
  PIN out_data[62]
    DIRECTION OUTPUT ;
    USE SIGNAL ;
    PORT
      LAYER M5 ;
        RECT  36.624 112.236 36.648 112.32 ;
    END
  END out_data[62]
  PIN out_data[63]
    DIRECTION OUTPUT ;
    USE SIGNAL ;
    PORT
      LAYER M5 ;
        RECT  36.72 112.236 36.744 112.32 ;
    END
  END out_data[63]
  PIN out_data[64]
    DIRECTION OUTPUT ;
    USE SIGNAL ;
    PORT
      LAYER M5 ;
        RECT  36.816 112.236 36.84 112.32 ;
    END
  END out_data[64]
  PIN out_data[65]
    DIRECTION OUTPUT ;
    USE SIGNAL ;
    PORT
      LAYER M5 ;
        RECT  36.912 112.236 36.936 112.32 ;
    END
  END out_data[65]
  PIN out_data[66]
    DIRECTION OUTPUT ;
    USE SIGNAL ;
    PORT
      LAYER M5 ;
        RECT  37.008 112.236 37.032 112.32 ;
    END
  END out_data[66]
  PIN out_data[67]
    DIRECTION OUTPUT ;
    USE SIGNAL ;
    PORT
      LAYER M5 ;
        RECT  37.104 112.236 37.128 112.32 ;
    END
  END out_data[67]
  PIN out_data[68]
    DIRECTION OUTPUT ;
    USE SIGNAL ;
    PORT
      LAYER M5 ;
        RECT  37.2 112.236 37.224 112.32 ;
    END
  END out_data[68]
  PIN out_data[69]
    DIRECTION OUTPUT ;
    USE SIGNAL ;
    PORT
      LAYER M5 ;
        RECT  37.296 112.236 37.32 112.32 ;
    END
  END out_data[69]
  PIN out_data[6]
    DIRECTION OUTPUT ;
    USE SIGNAL ;
    PORT
      LAYER M5 ;
        RECT  8.976 112.236 9 112.32 ;
    END
  END out_data[6]
  PIN out_data[70]
    DIRECTION OUTPUT ;
    USE SIGNAL ;
    PORT
      LAYER M5 ;
        RECT  37.392 112.236 37.416 112.32 ;
    END
  END out_data[70]
  PIN out_data[71]
    DIRECTION OUTPUT ;
    USE SIGNAL ;
    PORT
      LAYER M5 ;
        RECT  37.488 112.236 37.512 112.32 ;
    END
  END out_data[71]
  PIN out_data[72]
    DIRECTION OUTPUT ;
    USE SIGNAL ;
    PORT
      LAYER M5 ;
        RECT  2.256 112.236 2.28 112.32 ;
    END
  END out_data[72]
  PIN out_data[73]
    DIRECTION OUTPUT ;
    USE SIGNAL ;
    PORT
      LAYER M5 ;
        RECT  2.352 112.236 2.376 112.32 ;
    END
  END out_data[73]
  PIN out_data[74]
    DIRECTION OUTPUT ;
    USE SIGNAL ;
    PORT
      LAYER M5 ;
        RECT  2.448 112.236 2.472 112.32 ;
    END
  END out_data[74]
  PIN out_data[75]
    DIRECTION OUTPUT ;
    USE SIGNAL ;
    PORT
      LAYER M5 ;
        RECT  2.544 112.236 2.568 112.32 ;
    END
  END out_data[75]
  PIN out_data[76]
    DIRECTION OUTPUT ;
    USE SIGNAL ;
    PORT
      LAYER M5 ;
        RECT  2.64 112.236 2.664 112.32 ;
    END
  END out_data[76]
  PIN out_data[77]
    DIRECTION OUTPUT ;
    USE SIGNAL ;
    PORT
      LAYER M5 ;
        RECT  2.736 112.236 2.76 112.32 ;
    END
  END out_data[77]
  PIN out_data[78]
    DIRECTION OUTPUT ;
    USE SIGNAL ;
    PORT
      LAYER M5 ;
        RECT  2.832 112.236 2.856 112.32 ;
    END
  END out_data[78]
  PIN out_data[79]
    DIRECTION OUTPUT ;
    USE SIGNAL ;
    PORT
      LAYER M5 ;
        RECT  2.928 112.236 2.952 112.32 ;
    END
  END out_data[79]
  PIN out_data[7]
    DIRECTION OUTPUT ;
    USE SIGNAL ;
    PORT
      LAYER M5 ;
        RECT  9.072 112.236 9.096 112.32 ;
    END
  END out_data[7]
  PIN out_data[80]
    DIRECTION OUTPUT ;
    USE SIGNAL ;
    PORT
      LAYER M5 ;
        RECT  3.024 112.236 3.048 112.32 ;
    END
  END out_data[80]
  PIN out_data[81]
    DIRECTION OUTPUT ;
    USE SIGNAL ;
    PORT
      LAYER M5 ;
        RECT  3.12 112.236 3.144 112.32 ;
    END
  END out_data[81]
  PIN out_data[82]
    DIRECTION OUTPUT ;
    USE SIGNAL ;
    PORT
      LAYER M5 ;
        RECT  3.216 112.236 3.24 112.32 ;
    END
  END out_data[82]
  PIN out_data[83]
    DIRECTION OUTPUT ;
    USE SIGNAL ;
    PORT
      LAYER M5 ;
        RECT  3.312 112.236 3.336 112.32 ;
    END
  END out_data[83]
  PIN out_data[84]
    DIRECTION OUTPUT ;
    USE SIGNAL ;
    PORT
      LAYER M5 ;
        RECT  3.408 112.236 3.432 112.32 ;
    END
  END out_data[84]
  PIN out_data[85]
    DIRECTION OUTPUT ;
    USE SIGNAL ;
    PORT
      LAYER M5 ;
        RECT  3.504 112.236 3.528 112.32 ;
    END
  END out_data[85]
  PIN out_data[86]
    DIRECTION OUTPUT ;
    USE SIGNAL ;
    PORT
      LAYER M5 ;
        RECT  3.6 112.236 3.624 112.32 ;
    END
  END out_data[86]
  PIN out_data[87]
    DIRECTION OUTPUT ;
    USE SIGNAL ;
    PORT
      LAYER M5 ;
        RECT  3.696 112.236 3.72 112.32 ;
    END
  END out_data[87]
  PIN out_data[88]
    DIRECTION OUTPUT ;
    USE SIGNAL ;
    PORT
      LAYER M5 ;
        RECT  3.792 112.236 3.816 112.32 ;
    END
  END out_data[88]
  PIN out_data[89]
    DIRECTION OUTPUT ;
    USE SIGNAL ;
    PORT
      LAYER M5 ;
        RECT  3.888 112.236 3.912 112.32 ;
    END
  END out_data[89]
  PIN out_data[8]
    DIRECTION OUTPUT ;
    USE SIGNAL ;
    PORT
      LAYER M5 ;
        RECT  21.456 112.236 21.48 112.32 ;
    END
  END out_data[8]
  PIN out_data[90]
    DIRECTION OUTPUT ;
    USE SIGNAL ;
    PORT
      LAYER M5 ;
        RECT  3.984 112.236 4.008 112.32 ;
    END
  END out_data[90]
  PIN out_data[91]
    DIRECTION OUTPUT ;
    USE SIGNAL ;
    PORT
      LAYER M5 ;
        RECT  4.08 112.236 4.104 112.32 ;
    END
  END out_data[91]
  PIN out_data[92]
    DIRECTION OUTPUT ;
    USE SIGNAL ;
    PORT
      LAYER M5 ;
        RECT  4.176 112.236 4.2 112.32 ;
    END
  END out_data[92]
  PIN out_data[93]
    DIRECTION OUTPUT ;
    USE SIGNAL ;
    PORT
      LAYER M5 ;
        RECT  4.272 112.236 4.296 112.32 ;
    END
  END out_data[93]
  PIN out_data[94]
    DIRECTION OUTPUT ;
    USE SIGNAL ;
    PORT
      LAYER M5 ;
        RECT  4.368 112.236 4.392 112.32 ;
    END
  END out_data[94]
  PIN out_data[95]
    DIRECTION OUTPUT ;
    USE SIGNAL ;
    PORT
      LAYER M5 ;
        RECT  4.464 112.236 4.488 112.32 ;
    END
  END out_data[95]
  PIN out_data[96]
    DIRECTION OUTPUT ;
    USE SIGNAL ;
    PORT
      LAYER M5 ;
        RECT  4.56 112.236 4.584 112.32 ;
    END
  END out_data[96]
  PIN out_data[97]
    DIRECTION OUTPUT ;
    USE SIGNAL ;
    PORT
      LAYER M5 ;
        RECT  4.656 112.236 4.68 112.32 ;
    END
  END out_data[97]
  PIN out_data[98]
    DIRECTION OUTPUT ;
    USE SIGNAL ;
    PORT
      LAYER M5 ;
        RECT  4.752 112.236 4.776 112.32 ;
    END
  END out_data[98]
  PIN out_data[99]
    DIRECTION OUTPUT ;
    USE SIGNAL ;
    PORT
      LAYER M5 ;
        RECT  4.848 112.236 4.872 112.32 ;
    END
  END out_data[99]
  PIN out_data[9]
    DIRECTION OUTPUT ;
    USE SIGNAL ;
    PORT
      LAYER M5 ;
        RECT  21.552 112.236 21.576 112.32 ;
    END
  END out_data[9]
  PIN out_v
    DIRECTION OUTPUT ;
    USE SIGNAL ;
    PORT
      LAYER M5 ;
        RECT  42.96 112.236 42.984 112.32 ;
    END
  END out_v
  PIN read_bank
    DIRECTION INPUT ;
    USE SIGNAL ;
    PORT
      LAYER M5 ;
        RECT  43.056 112.236 43.08 112.32 ;
    END
  END read_bank
  PIN read_epoch[0]
    DIRECTION INPUT ;
    USE SIGNAL ;
    PORT
      LAYER M5 ;
        RECT  43.152 112.236 43.176 112.32 ;
    END
  END read_epoch[0]
  PIN read_epoch[10]
    DIRECTION INPUT ;
    USE SIGNAL ;
    PORT
      LAYER M5 ;
        RECT  45.36 112.236 45.384 112.32 ;
    END
  END read_epoch[10]
  PIN read_epoch[11]
    DIRECTION INPUT ;
    USE SIGNAL ;
    PORT
      LAYER M5 ;
        RECT  45.456 112.236 45.48 112.32 ;
    END
  END read_epoch[11]
  PIN read_epoch[12]
    DIRECTION INPUT ;
    USE SIGNAL ;
    PORT
      LAYER M5 ;
        RECT  45.552 112.236 45.576 112.32 ;
    END
  END read_epoch[12]
  PIN read_epoch[13]
    DIRECTION INPUT ;
    USE SIGNAL ;
    PORT
      LAYER M5 ;
        RECT  45.648 112.236 45.672 112.32 ;
    END
  END read_epoch[13]
  PIN read_epoch[14]
    DIRECTION INPUT ;
    USE SIGNAL ;
    PORT
      LAYER M5 ;
        RECT  45.744 112.236 45.768 112.32 ;
    END
  END read_epoch[14]
  PIN read_epoch[15]
    DIRECTION INPUT ;
    USE SIGNAL ;
    PORT
      LAYER M5 ;
        RECT  45.84 112.236 45.864 112.32 ;
    END
  END read_epoch[15]
  PIN read_epoch[1]
    DIRECTION INPUT ;
    USE SIGNAL ;
    PORT
      LAYER M5 ;
        RECT  43.248 112.236 43.272 112.32 ;
    END
  END read_epoch[1]
  PIN read_epoch[2]
    DIRECTION INPUT ;
    USE SIGNAL ;
    PORT
      LAYER M5 ;
        RECT  43.344 112.236 43.368 112.32 ;
    END
  END read_epoch[2]
  PIN read_epoch[3]
    DIRECTION INPUT ;
    USE SIGNAL ;
    PORT
      LAYER M5 ;
        RECT  43.44 112.236 43.464 112.32 ;
    END
  END read_epoch[3]
  PIN read_epoch[4]
    DIRECTION INPUT ;
    USE SIGNAL ;
    PORT
      LAYER M5 ;
        RECT  43.536 112.236 43.56 112.32 ;
    END
  END read_epoch[4]
  PIN read_epoch[5]
    DIRECTION INPUT ;
    USE SIGNAL ;
    PORT
      LAYER M5 ;
        RECT  43.632 112.236 43.656 112.32 ;
    END
  END read_epoch[5]
  PIN read_epoch[6]
    DIRECTION INPUT ;
    USE SIGNAL ;
    PORT
      LAYER M5 ;
        RECT  44.976 112.236 45 112.32 ;
    END
  END read_epoch[6]
  PIN read_epoch[7]
    DIRECTION INPUT ;
    USE SIGNAL ;
    PORT
      LAYER M5 ;
        RECT  45.072 112.236 45.096 112.32 ;
    END
  END read_epoch[7]
  PIN read_epoch[8]
    DIRECTION INPUT ;
    USE SIGNAL ;
    PORT
      LAYER M5 ;
        RECT  45.168 112.236 45.192 112.32 ;
    END
  END read_epoch[8]
  PIN read_epoch[9]
    DIRECTION INPUT ;
    USE SIGNAL ;
    PORT
      LAYER M5 ;
        RECT  45.264 112.236 45.288 112.32 ;
    END
  END read_epoch[9]
  PIN read_slot[0]
    DIRECTION INPUT ;
    USE SIGNAL ;
    PORT
      LAYER M5 ;
        RECT  45.936 112.236 45.96 112.32 ;
    END
  END read_slot[0]
  PIN read_slot[1]
    DIRECTION INPUT ;
    USE SIGNAL ;
    PORT
      LAYER M5 ;
        RECT  46.032 112.236 46.056 112.32 ;
    END
  END read_slot[1]
  PIN read_slot[2]
    DIRECTION INPUT ;
    USE SIGNAL ;
    PORT
      LAYER M5 ;
        RECT  46.128 112.236 46.152 112.32 ;
    END
  END read_slot[2]
  PIN read_slot[3]
    DIRECTION INPUT ;
    USE SIGNAL ;
    PORT
      LAYER M5 ;
        RECT  46.224 112.236 46.248 112.32 ;
    END
  END read_slot[3]
  PIN read_slot[4]
    DIRECTION INPUT ;
    USE SIGNAL ;
    PORT
      LAYER M5 ;
        RECT  46.32 112.236 46.344 112.32 ;
    END
  END read_slot[4]
  PIN read_slot[5]
    DIRECTION INPUT ;
    USE SIGNAL ;
    PORT
      LAYER M5 ;
        RECT  46.416 112.236 46.44 112.32 ;
    END
  END read_slot[5]
  PIN read_v
    DIRECTION INPUT ;
    USE SIGNAL ;
    PORT
      LAYER M5 ;
        RECT  46.512 112.236 46.536 112.32 ;
    END
  END read_v
  PIN retire_bank
    DIRECTION INPUT ;
    USE SIGNAL ;
    PORT
      LAYER M4 ;
        RECT  0 29.904 0.084 29.928 ;
    END
  END retire_bank
  PIN retire_epoch[0]
    DIRECTION INPUT ;
    USE SIGNAL ;
    PORT
      LAYER M4 ;
        RECT  0 30 0.084 30.024 ;
    END
  END retire_epoch[0]
  PIN retire_epoch[10]
    DIRECTION INPUT ;
    USE SIGNAL ;
    PORT
      LAYER M4 ;
        RECT  0 30.96 0.084 30.984 ;
    END
  END retire_epoch[10]
  PIN retire_epoch[11]
    DIRECTION INPUT ;
    USE SIGNAL ;
    PORT
      LAYER M4 ;
        RECT  0 31.056 0.084 31.08 ;
    END
  END retire_epoch[11]
  PIN retire_epoch[12]
    DIRECTION INPUT ;
    USE SIGNAL ;
    PORT
      LAYER M4 ;
        RECT  0 31.152 0.084 31.176 ;
    END
  END retire_epoch[12]
  PIN retire_epoch[13]
    DIRECTION INPUT ;
    USE SIGNAL ;
    PORT
      LAYER M4 ;
        RECT  0 31.248 0.084 31.272 ;
    END
  END retire_epoch[13]
  PIN retire_epoch[14]
    DIRECTION INPUT ;
    USE SIGNAL ;
    PORT
      LAYER M4 ;
        RECT  0 31.344 0.084 31.368 ;
    END
  END retire_epoch[14]
  PIN retire_epoch[15]
    DIRECTION INPUT ;
    USE SIGNAL ;
    PORT
      LAYER M4 ;
        RECT  0 31.44 0.084 31.464 ;
    END
  END retire_epoch[15]
  PIN retire_epoch[1]
    DIRECTION INPUT ;
    USE SIGNAL ;
    PORT
      LAYER M4 ;
        RECT  0 30.096 0.084 30.12 ;
    END
  END retire_epoch[1]
  PIN retire_epoch[2]
    DIRECTION INPUT ;
    USE SIGNAL ;
    PORT
      LAYER M4 ;
        RECT  0 30.192 0.084 30.216 ;
    END
  END retire_epoch[2]
  PIN retire_epoch[3]
    DIRECTION INPUT ;
    USE SIGNAL ;
    PORT
      LAYER M4 ;
        RECT  0 30.288 0.084 30.312 ;
    END
  END retire_epoch[3]
  PIN retire_epoch[4]
    DIRECTION INPUT ;
    USE SIGNAL ;
    PORT
      LAYER M4 ;
        RECT  0 30.384 0.084 30.408 ;
    END
  END retire_epoch[4]
  PIN retire_epoch[5]
    DIRECTION INPUT ;
    USE SIGNAL ;
    PORT
      LAYER M4 ;
        RECT  0 30.48 0.084 30.504 ;
    END
  END retire_epoch[5]
  PIN retire_epoch[6]
    DIRECTION INPUT ;
    USE SIGNAL ;
    PORT
      LAYER M4 ;
        RECT  0 30.576 0.084 30.6 ;
    END
  END retire_epoch[6]
  PIN retire_epoch[7]
    DIRECTION INPUT ;
    USE SIGNAL ;
    PORT
      LAYER M4 ;
        RECT  0 30.672 0.084 30.696 ;
    END
  END retire_epoch[7]
  PIN retire_epoch[8]
    DIRECTION INPUT ;
    USE SIGNAL ;
    PORT
      LAYER M4 ;
        RECT  0 30.768 0.084 30.792 ;
    END
  END retire_epoch[8]
  PIN retire_epoch[9]
    DIRECTION INPUT ;
    USE SIGNAL ;
    PORT
      LAYER M4 ;
        RECT  0 30.864 0.084 30.888 ;
    END
  END retire_epoch[9]
  PIN retire_v
    DIRECTION INPUT ;
    USE SIGNAL ;
    PORT
      LAYER M4 ;
        RECT  0 31.536 0.084 31.56 ;
    END
  END retire_v
  PIN rst_n
    DIRECTION INPUT ;
    USE SIGNAL ;
    PORT
      LAYER M4 ;
        RECT  0 31.632 0.084 31.656 ;
    END
  END rst_n
  PIN VDD
    DIRECTION INOUT ;
    USE POWER ;
    PORT
      LAYER M5 ;
        RECT  137.592 2.151 137.712 110.169 ;
        RECT  132.192 2.151 132.312 110.169 ;
        RECT  126.792 2.151 126.912 110.169 ;
        RECT  121.392 2.151 121.512 110.169 ;
        RECT  115.992 2.151 116.112 110.169 ;
        RECT  110.592 2.151 110.712 110.169 ;
        RECT  105.192 2.151 105.312 110.169 ;
        RECT  99.792 2.151 99.912 110.169 ;
        RECT  94.392 2.151 94.512 110.169 ;
        RECT  88.992 2.151 89.112 110.169 ;
        RECT  83.592 2.151 83.712 110.169 ;
        RECT  78.192 2.151 78.312 110.169 ;
        RECT  72.792 2.151 72.912 110.169 ;
        RECT  67.392 2.151 67.512 110.169 ;
        RECT  61.992 2.151 62.112 110.169 ;
        RECT  56.592 2.151 56.712 110.169 ;
        RECT  51.192 2.151 51.312 110.169 ;
        RECT  45.792 2.151 45.912 110.169 ;
        RECT  40.392 2.151 40.512 110.169 ;
        RECT  34.992 2.151 35.112 110.169 ;
        RECT  29.592 2.151 29.712 110.169 ;
        RECT  24.192 2.151 24.312 110.169 ;
        RECT  18.792 2.151 18.912 110.169 ;
        RECT  13.392 2.151 13.512 110.169 ;
        RECT  7.992 2.151 8.112 110.169 ;
        RECT  2.592 2.151 2.712 110.169 ;
    END
  END VDD
  PIN VSS
    DIRECTION INOUT ;
    USE GROUND ;
    PORT
      LAYER M5 ;
        RECT  137.4 2.137 137.52 110.183 ;
        RECT  132 2.137 132.12 110.183 ;
        RECT  126.6 2.137 126.72 110.183 ;
        RECT  121.2 2.137 121.32 110.183 ;
        RECT  115.8 2.137 115.92 110.183 ;
        RECT  110.4 2.137 110.52 110.183 ;
        RECT  105 2.137 105.12 110.183 ;
        RECT  99.6 2.137 99.72 110.183 ;
        RECT  94.2 2.137 94.32 110.183 ;
        RECT  88.8 2.137 88.92 110.183 ;
        RECT  83.4 2.137 83.52 110.183 ;
        RECT  78 2.137 78.12 110.183 ;
        RECT  72.6 2.137 72.72 110.183 ;
        RECT  67.2 2.137 67.32 110.183 ;
        RECT  61.8 2.137 61.92 110.183 ;
        RECT  56.4 2.137 56.52 110.183 ;
        RECT  51 2.137 51.12 110.183 ;
        RECT  45.6 2.137 45.72 110.183 ;
        RECT  40.2 2.137 40.32 110.183 ;
        RECT  34.8 2.137 34.92 110.183 ;
        RECT  29.4 2.137 29.52 110.183 ;
        RECT  24 2.137 24.12 110.183 ;
        RECT  18.6 2.137 18.72 110.183 ;
        RECT  13.2 2.137 13.32 110.183 ;
        RECT  7.8 2.137 7.92 110.183 ;
        RECT  2.4 2.137 2.52 110.183 ;
    END
  END VSS
  # OT_OBS_CLOSED layer=M5 d_um=1.536 added=129
  OBS
    LAYER LVTN ;
     RECT  45.846 4.185 46.116 4.32 ;
     RECT  21.438 5.265 22.032 5.4 ;
     RECT  21.6 5.4 21.978 5.535 ;
     RECT  13.932 5.94 15.336 6.075 ;
     RECT  20.142 5.94 20.79 6.075 ;
     RECT  17.928 6.345 18.306 6.48 ;
     RECT  20.142 6.48 20.52 6.615 ;
     RECT  13.392 6.885 14.796 7.02 ;
     RECT  21.708 7.965 22.14 8.1 ;
     RECT  14.148 8.1 15.552 8.235 ;
     RECT  18.468 8.505 18.846 8.64 ;
     RECT  20.25 8.505 20.574 8.64 ;
     RECT  18.954 9.585 19.332 9.72 ;
     RECT  19.44 9.72 19.764 9.855 ;
     RECT  20.25 9.72 20.574 9.855 ;
     RECT  18.846 10.125 19.224 10.26 ;
     RECT  18.522 16.605 19.062 16.74 ;
     RECT  5.616 22.68 6.048 22.815 ;
     RECT  16.038 28.08 16.578 28.215 ;
     RECT  7.722 29.7 8.316 29.835 ;
     RECT  7.83 30.105 8.154 30.24 ;
     RECT  9.018 30.105 9.45 30.24 ;
     RECT  9.126 31.32 9.504 31.455 ;
     RECT  10.422 31.32 10.854 31.455 ;
     RECT  11.934 43.2 12.474 43.335 ;
     RECT  9.234 44.28 10.098 44.415 ;
     RECT  11.448 44.685 11.88 44.82 ;
     RECT  12.312 44.82 12.69 44.955 ;
     RECT  11.232 45.225 11.61 45.36 ;
     RECT  19.656 45.36 20.196 45.495 ;
     RECT  20.196 45.9 20.736 46.035 ;
     RECT  13.176 48.465 13.5 48.6 ;
     RECT  10.26 48.6 10.584 48.735 ;
     RECT  11.07 49.14 11.232 49.275 ;
     RECT  11.34 51.84 11.88 51.975 ;
     RECT  5.616 52.245 6.156 52.38 ;
     RECT  9.018 52.38 9.234 52.515 ;
     RECT  13.068 52.38 13.716 52.515 ;
     RECT  14.526 52.38 14.958 52.515 ;
     RECT  10.53 52.785 11.502 52.92 ;
     RECT  13.284 52.785 13.824 52.92 ;
     RECT  10.638 52.92 11.772 53.055 ;
     RECT  4.806 53.325 5.346 53.46 ;
     RECT  13.554 53.325 14.094 53.46 ;
     RECT  3.348 53.46 3.888 53.595 ;
     RECT  4.158 53.865 4.698 54 ;
     RECT  8.748 53.865 9.072 54 ;
     RECT  3.456 54 3.996 54.135 ;
     RECT  8.694 54.405 9.018 54.54 ;
     RECT  2.916 54.54 3.456 54.675 ;
     RECT  13.446 54.54 13.77 54.675 ;
     RECT  3.456 54.945 3.996 55.08 ;
     RECT  5.94 55.08 6.372 55.215 ;
     RECT  11.556 55.08 11.88 55.215 ;
     RECT  13.392 55.08 13.824 55.215 ;
     RECT  12.312 55.485 12.636 55.62 ;
     RECT  2.916 56.025 3.456 56.16 ;
     RECT  3.888 56.16 4.428 56.295 ;
     RECT  11.394 56.16 11.934 56.295 ;
     RECT  6.804 56.565 7.128 56.7 ;
     RECT  4.32 57.105 4.86 57.24 ;
     RECT  9.018 57.24 9.558 57.375 ;
     RECT  3.348 57.78 3.888 57.915 ;
     RECT  6.372 57.78 6.912 57.915 ;
     RECT  8.424 57.78 8.964 57.915 ;
     RECT  4.158 58.32 4.698 58.455 ;
     RECT  6.048 58.32 6.588 58.455 ;
     RECT  8.262 58.86 8.802 58.995 ;
     RECT  3.726 59.265 4.806 59.4 ;
     RECT  3.726 59.4 4.266 59.535 ;
     RECT  6.21 59.4 6.75 59.535 ;
     RECT  8.154 59.4 8.694 59.535 ;
     RECT  11.07 59.4 11.61 59.535 ;
     RECT  6.642 59.805 7.182 59.94 ;
     RECT  4.32 60.345 4.86 60.48 ;
     RECT  6.642 60.48 7.182 60.615 ;
     RECT  4.644 60.885 5.184 61.02 ;
     RECT  16.092 63.72 16.578 63.855 ;
     RECT  8.694 64.125 9.018 64.26 ;
     RECT  15.66 64.125 15.984 64.26 ;
     RECT  16.362 64.125 16.686 64.26 ;
     RECT  15.984 64.665 16.47 64.8 ;
     RECT  16.74 64.665 17.226 64.8 ;
     RECT  18.738 64.665 19.224 64.8 ;
     RECT  16.092 64.8 16.578 64.935 ;
     RECT  15.498 65.205 16.47 65.34 ;
     RECT  17.226 65.205 18.198 65.34 ;
     RECT  15.822 65.34 16.794 65.475 ;
     RECT  16.362 65.745 16.848 65.88 ;
     RECT  16.254 65.88 16.74 66.015 ;
     RECT  15.498 66.285 15.984 66.42 ;
     RECT  17.766 66.285 18.252 66.42 ;
     RECT  15.984 66.42 16.47 66.555 ;
     RECT  17.658 66.42 19.116 66.555 ;
     RECT  10.53 109.62 11.718 109.755 ;
    LAYER LVTP ;
     RECT  45.846 4.05 46.116 4.185 ;
     RECT  21.438 5.13 22.032 5.265 ;
     RECT  21.6 5.535 21.978 5.67 ;
     RECT  13.932 6.075 15.336 6.21 ;
     RECT  20.142 6.075 20.79 6.21 ;
     RECT  17.928 6.21 18.306 6.345 ;
     RECT  20.142 6.615 20.52 6.75 ;
     RECT  13.392 6.75 14.796 6.885 ;
     RECT  21.708 7.83 22.14 7.965 ;
     RECT  14.148 8.235 15.552 8.37 ;
     RECT  18.468 8.37 18.846 8.505 ;
     RECT  20.25 8.37 20.574 8.505 ;
     RECT  18.954 9.45 19.332 9.585 ;
     RECT  19.44 9.855 19.764 9.99 ;
     RECT  20.25 9.855 20.574 9.99 ;
     RECT  18.846 9.99 19.224 10.125 ;
     RECT  18.522 16.47 19.062 16.605 ;
     RECT  5.616 22.815 6.048 22.95 ;
     RECT  16.038 28.215 16.578 28.35 ;
     RECT  7.722 29.835 8.316 29.97 ;
     RECT  7.83 29.97 8.154 30.105 ;
     RECT  9.018 29.97 9.45 30.105 ;
     RECT  9.126 31.455 9.504 31.59 ;
     RECT  10.422 31.455 10.854 31.59 ;
     RECT  11.934 43.335 12.474 43.47 ;
     RECT  9.234 44.415 10.098 44.55 ;
     RECT  11.448 44.55 11.88 44.685 ;
     RECT  12.312 44.955 12.69 45.09 ;
     RECT  11.232 45.09 11.61 45.225 ;
     RECT  19.656 45.495 20.196 45.63 ;
     RECT  20.196 46.035 20.736 46.17 ;
     RECT  13.176 48.33 13.5 48.465 ;
     RECT  10.26 48.735 10.584 48.87 ;
     RECT  11.07 49.275 11.232 49.41 ;
     RECT  11.34 51.975 11.88 52.11 ;
     RECT  5.616 52.11 6.156 52.245 ;
     RECT  9.018 52.515 9.234 52.65 ;
     RECT  13.068 52.515 13.716 52.65 ;
     RECT  14.526 52.515 14.958 52.65 ;
     RECT  10.53 52.65 11.502 52.785 ;
     RECT  13.284 52.65 13.824 52.785 ;
     RECT  10.638 53.055 11.772 53.19 ;
     RECT  4.806 53.19 5.346 53.325 ;
     RECT  13.554 53.19 14.094 53.325 ;
     RECT  3.348 53.595 3.888 53.73 ;
     RECT  4.158 53.73 4.698 53.865 ;
     RECT  8.748 53.73 9.072 53.865 ;
     RECT  3.456 54.135 3.996 54.27 ;
     RECT  8.694 54.27 9.018 54.405 ;
     RECT  2.916 54.675 3.456 54.81 ;
     RECT  13.446 54.675 13.77 54.81 ;
     RECT  3.456 54.81 3.996 54.945 ;
     RECT  5.94 55.215 6.372 55.35 ;
     RECT  11.556 55.215 11.88 55.35 ;
     RECT  13.392 55.215 13.824 55.35 ;
     RECT  12.312 55.35 12.636 55.485 ;
     RECT  2.916 55.89 3.456 56.025 ;
     RECT  3.888 56.295 4.428 56.43 ;
     RECT  11.394 56.295 11.934 56.43 ;
     RECT  6.804 56.43 7.128 56.565 ;
     RECT  4.32 56.97 4.86 57.105 ;
     RECT  9.018 57.375 9.558 57.51 ;
     RECT  3.348 57.915 3.888 58.05 ;
     RECT  6.372 57.915 6.912 58.05 ;
     RECT  8.424 57.915 8.964 58.05 ;
     RECT  4.158 58.455 4.698 58.59 ;
     RECT  6.048 58.455 6.588 58.59 ;
     RECT  8.262 58.995 8.802 59.13 ;
     RECT  3.726 59.13 4.806 59.265 ;
     RECT  3.726 59.535 4.266 59.67 ;
     RECT  6.21 59.535 6.75 59.67 ;
     RECT  8.154 59.535 8.694 59.67 ;
     RECT  11.07 59.535 11.61 59.67 ;
     RECT  6.642 59.67 7.182 59.805 ;
     RECT  4.32 60.21 4.86 60.345 ;
     RECT  6.642 60.615 7.182 60.75 ;
     RECT  4.644 60.75 5.184 60.885 ;
     RECT  16.092 63.855 16.578 63.99 ;
     RECT  8.694 63.99 9.018 64.125 ;
     RECT  15.66 63.99 15.984 64.125 ;
     RECT  16.362 63.99 16.686 64.125 ;
     RECT  15.984 64.53 16.47 64.665 ;
     RECT  16.74 64.53 17.226 64.665 ;
     RECT  18.738 64.53 19.224 64.665 ;
     RECT  16.092 64.935 16.578 65.07 ;
     RECT  15.498 65.07 16.47 65.205 ;
     RECT  17.226 65.07 18.198 65.205 ;
     RECT  15.822 65.475 16.794 65.61 ;
     RECT  16.362 65.61 16.848 65.745 ;
     RECT  16.254 66.015 16.74 66.15 ;
     RECT  15.498 66.15 15.984 66.285 ;
     RECT  17.766 66.15 18.252 66.285 ;
     RECT  15.984 66.555 16.47 66.69 ;
     RECT  17.658 66.555 19.116 66.69 ;
     RECT  10.53 109.755 11.718 109.89 ;
    LAYER RVTN ;
     RECT  2.16 2.16 138.24 2.295 ;
     RECT  2.16 2.565 138.24 2.835 ;
     RECT  2.16 3.105 138.24 3.375 ;
     RECT  2.16 3.645 138.24 3.915 ;
     RECT  2.16 4.185 45.846 4.32 ;
     RECT  46.116 4.185 138.24 4.32 ;
     RECT  2.16 4.32 138.24 4.455 ;
     RECT  2.16 4.725 138.24 4.995 ;
     RECT  2.16 5.265 21.438 5.4 ;
     RECT  22.032 5.265 138.24 5.4 ;
     RECT  2.16 5.4 21.6 5.535 ;
     RECT  21.978 5.4 138.24 5.535 ;
     RECT  2.16 5.805 138.24 5.94 ;
     RECT  2.16 5.94 13.932 6.075 ;
     RECT  15.336 5.94 20.142 6.075 ;
     RECT  20.79 5.94 138.24 6.075 ;
     RECT  2.16 6.345 17.928 6.48 ;
     RECT  18.306 6.345 138.24 6.48 ;
     RECT  2.16 6.48 20.142 6.615 ;
     RECT  20.52 6.48 138.24 6.615 ;
     RECT  2.16 6.885 13.392 7.02 ;
     RECT  14.796 6.885 138.24 7.02 ;
     RECT  2.16 7.02 138.24 7.155 ;
     RECT  2.16 7.425 138.24 7.695 ;
     RECT  2.16 7.965 21.708 8.1 ;
     RECT  22.14 7.965 138.24 8.1 ;
     RECT  2.16 8.1 14.148 8.235 ;
     RECT  15.552 8.1 138.24 8.235 ;
     RECT  2.16 8.505 18.468 8.64 ;
     RECT  18.846 8.505 20.25 8.64 ;
     RECT  20.574 8.505 138.24 8.64 ;
     RECT  2.16 8.64 138.24 8.775 ;
     RECT  2.16 9.045 138.24 9.315 ;
     RECT  2.16 9.585 18.954 9.72 ;
     RECT  19.332 9.585 138.24 9.72 ;
     RECT  2.16 9.72 19.44 9.855 ;
     RECT  19.764 9.72 20.25 9.855 ;
     RECT  20.574 9.72 138.24 9.855 ;
     RECT  2.16 10.125 18.846 10.26 ;
     RECT  19.224 10.125 138.24 10.26 ;
     RECT  2.16 10.26 138.24 10.395 ;
     RECT  2.16 10.665 138.24 10.935 ;
     RECT  2.16 11.205 138.24 11.475 ;
     RECT  2.16 11.745 138.24 12.015 ;
     RECT  2.16 12.285 138.24 12.555 ;
     RECT  2.16 12.825 138.24 13.095 ;
     RECT  2.16 13.365 138.24 13.635 ;
     RECT  2.16 13.905 138.24 14.175 ;
     RECT  2.16 14.445 138.24 14.715 ;
     RECT  2.16 14.985 138.24 15.255 ;
     RECT  2.16 15.525 138.24 15.795 ;
     RECT  2.16 16.065 138.24 16.335 ;
     RECT  2.16 16.605 18.522 16.74 ;
     RECT  19.062 16.605 138.24 16.74 ;
     RECT  2.16 16.74 138.24 16.875 ;
     RECT  2.16 17.145 138.24 17.415 ;
     RECT  2.16 17.685 138.24 17.955 ;
     RECT  2.16 18.225 138.24 18.495 ;
     RECT  2.16 18.765 138.24 19.035 ;
     RECT  2.16 19.305 138.24 19.575 ;
     RECT  2.16 19.845 138.24 20.115 ;
     RECT  2.16 20.385 138.24 20.655 ;
     RECT  2.16 20.925 138.24 21.195 ;
     RECT  2.16 21.465 138.24 21.735 ;
     RECT  2.16 22.005 138.24 22.275 ;
     RECT  2.16 22.545 138.24 22.68 ;
     RECT  2.16 22.68 5.616 22.815 ;
     RECT  6.048 22.68 138.24 22.815 ;
     RECT  2.16 23.085 138.24 23.355 ;
     RECT  2.16 23.625 138.24 23.895 ;
     RECT  2.16 24.165 138.24 24.435 ;
     RECT  2.16 24.705 138.24 24.975 ;
     RECT  2.16 25.245 138.24 25.515 ;
     RECT  2.16 25.785 138.24 26.055 ;
     RECT  2.16 26.325 138.24 26.595 ;
     RECT  2.16 26.865 138.24 27.135 ;
     RECT  2.16 27.405 138.24 27.675 ;
     RECT  2.16 27.945 138.24 28.08 ;
     RECT  2.16 28.08 16.038 28.215 ;
     RECT  16.578 28.08 138.24 28.215 ;
     RECT  2.16 28.485 138.24 28.755 ;
     RECT  2.16 29.025 138.24 29.295 ;
     RECT  2.16 29.565 138.24 29.7 ;
     RECT  2.16 29.7 7.722 29.835 ;
     RECT  8.316 29.7 138.24 29.835 ;
     RECT  2.16 30.105 7.83 30.24 ;
     RECT  8.154 30.105 9.018 30.24 ;
     RECT  9.45 30.105 138.24 30.24 ;
     RECT  2.16 30.24 138.24 30.375 ;
     RECT  2.16 30.645 138.24 30.915 ;
     RECT  2.16 31.185 138.24 31.32 ;
     RECT  2.16 31.32 9.126 31.455 ;
     RECT  9.504 31.32 10.422 31.455 ;
     RECT  10.854 31.32 138.24 31.455 ;
     RECT  2.16 31.725 138.24 31.995 ;
     RECT  2.16 32.265 138.24 32.4 ;
     RECT  2.16 32.4 20.844 32.535 ;
     RECT  119.772 32.4 138.24 32.535 ;
     RECT  2.16 32.805 20.844 33.075 ;
     RECT  119.772 32.805 138.24 33.075 ;
     RECT  2.16 33.345 20.844 33.615 ;
     RECT  119.772 33.345 138.24 33.615 ;
     RECT  2.16 33.885 20.844 34.155 ;
     RECT  119.772 33.885 138.24 34.155 ;
     RECT  2.16 34.425 20.844 34.695 ;
     RECT  119.772 34.425 138.24 34.695 ;
     RECT  2.16 34.965 20.844 35.235 ;
     RECT  119.772 34.965 138.24 35.235 ;
     RECT  2.16 35.505 20.844 35.775 ;
     RECT  119.772 35.505 138.24 35.775 ;
     RECT  2.16 36.045 20.844 36.315 ;
     RECT  119.772 36.045 138.24 36.315 ;
     RECT  2.16 36.585 20.844 36.855 ;
     RECT  119.772 36.585 138.24 36.855 ;
     RECT  2.16 37.125 20.844 37.395 ;
     RECT  119.772 37.125 138.24 37.395 ;
     RECT  2.16 37.665 20.844 37.935 ;
     RECT  119.772 37.665 138.24 37.935 ;
     RECT  2.16 38.205 20.844 38.475 ;
     RECT  119.772 38.205 138.24 38.475 ;
     RECT  2.16 38.745 20.844 39.015 ;
     RECT  119.772 38.745 138.24 39.015 ;
     RECT  2.16 39.285 20.844 39.555 ;
     RECT  119.772 39.285 138.24 39.555 ;
     RECT  2.16 39.825 20.844 40.095 ;
     RECT  119.772 39.825 138.24 40.095 ;
     RECT  2.16 40.365 20.844 40.635 ;
     RECT  119.772 40.365 138.24 40.635 ;
     RECT  2.16 40.905 20.844 41.175 ;
     RECT  119.772 40.905 138.24 41.175 ;
     RECT  2.16 41.445 20.844 41.715 ;
     RECT  119.772 41.445 138.24 41.715 ;
     RECT  2.16 41.985 20.844 42.255 ;
     RECT  119.772 41.985 138.24 42.255 ;
     RECT  2.16 42.525 20.844 42.795 ;
     RECT  119.772 42.525 138.24 42.795 ;
     RECT  2.16 43.065 20.844 43.2 ;
     RECT  2.16 43.2 11.934 43.335 ;
     RECT  12.474 43.2 20.844 43.335 ;
     RECT  119.772 43.065 138.24 43.335 ;
     RECT  2.16 43.605 20.844 43.875 ;
     RECT  119.772 43.605 138.24 43.875 ;
     RECT  2.16 44.145 20.844 44.28 ;
     RECT  2.16 44.28 9.234 44.415 ;
     RECT  10.098 44.28 20.844 44.415 ;
     RECT  119.772 44.145 138.24 44.415 ;
     RECT  2.16 44.685 11.448 44.82 ;
     RECT  11.88 44.685 20.844 44.82 ;
     RECT  2.16 44.82 12.312 44.955 ;
     RECT  12.69 44.82 20.844 44.955 ;
     RECT  119.772 44.685 138.24 44.955 ;
     RECT  2.16 45.225 11.232 45.36 ;
     RECT  11.61 45.225 20.844 45.36 ;
     RECT  2.16 45.36 19.656 45.495 ;
     RECT  20.196 45.36 20.844 45.495 ;
     RECT  119.772 45.225 138.24 45.495 ;
     RECT  2.16 45.765 20.844 45.9 ;
     RECT  2.16 45.9 20.196 46.035 ;
     RECT  20.736 45.9 20.844 46.035 ;
     RECT  119.772 45.765 138.24 46.035 ;
     RECT  2.16 46.305 20.844 46.575 ;
     RECT  119.772 46.305 138.24 46.575 ;
     RECT  2.16 46.845 20.844 47.115 ;
     RECT  119.772 46.845 138.24 47.115 ;
     RECT  2.16 47.385 20.844 47.655 ;
     RECT  119.772 47.385 138.24 47.655 ;
     RECT  2.16 47.925 20.844 48.195 ;
     RECT  119.772 47.925 138.24 48.195 ;
     RECT  2.16 48.465 13.176 48.6 ;
     RECT  13.5 48.465 20.844 48.6 ;
     RECT  2.16 48.6 10.26 48.735 ;
     RECT  10.584 48.6 20.844 48.735 ;
     RECT  119.772 48.465 138.24 48.735 ;
     RECT  2.16 49.005 20.844 49.14 ;
     RECT  2.16 49.14 11.07 49.275 ;
     RECT  11.232 49.14 20.844 49.275 ;
     RECT  119.772 49.005 138.24 49.275 ;
     RECT  2.16 49.545 20.844 49.815 ;
     RECT  119.772 49.545 138.24 49.815 ;
     RECT  2.16 50.085 20.844 50.355 ;
     RECT  119.772 50.085 138.24 50.355 ;
     RECT  2.16 50.625 20.844 50.895 ;
     RECT  119.772 50.625 138.24 50.895 ;
     RECT  2.16 51.165 20.844 51.435 ;
     RECT  119.772 51.165 138.24 51.435 ;
     RECT  2.16 51.705 20.844 51.84 ;
     RECT  2.16 51.84 11.34 51.975 ;
     RECT  11.88 51.84 20.844 51.975 ;
     RECT  119.772 51.705 138.24 51.975 ;
     RECT  2.16 52.245 5.616 52.38 ;
     RECT  6.156 52.245 20.844 52.38 ;
     RECT  2.16 52.38 9.018 52.515 ;
     RECT  9.234 52.38 13.068 52.515 ;
     RECT  13.716 52.38 14.526 52.515 ;
     RECT  14.958 52.38 20.844 52.515 ;
     RECT  119.772 52.245 138.24 52.515 ;
     RECT  2.16 52.785 10.53 52.92 ;
     RECT  11.502 52.785 13.284 52.92 ;
     RECT  13.824 52.785 20.844 52.92 ;
     RECT  2.16 52.92 10.638 53.055 ;
     RECT  11.772 52.92 20.844 53.055 ;
     RECT  119.772 52.785 138.24 53.055 ;
     RECT  2.16 53.325 4.806 53.46 ;
     RECT  5.346 53.325 13.554 53.46 ;
     RECT  14.094 53.325 20.844 53.46 ;
     RECT  2.16 53.46 3.348 53.595 ;
     RECT  3.888 53.46 20.844 53.595 ;
     RECT  119.772 53.325 138.24 53.595 ;
     RECT  2.16 53.865 4.158 54 ;
     RECT  4.698 53.865 8.748 54 ;
     RECT  9.072 53.865 20.844 54 ;
     RECT  2.16 54 3.456 54.135 ;
     RECT  3.996 54 20.844 54.135 ;
     RECT  119.772 53.865 138.24 54.135 ;
     RECT  2.16 54.405 8.694 54.54 ;
     RECT  9.018 54.405 20.844 54.54 ;
     RECT  2.16 54.54 2.916 54.675 ;
     RECT  3.456 54.54 13.446 54.675 ;
     RECT  13.77 54.54 20.844 54.675 ;
     RECT  119.772 54.405 138.24 54.675 ;
     RECT  2.16 54.945 3.456 55.08 ;
     RECT  3.996 54.945 20.844 55.08 ;
     RECT  2.16 55.08 5.94 55.215 ;
     RECT  6.372 55.08 11.556 55.215 ;
     RECT  11.88 55.08 13.392 55.215 ;
     RECT  13.824 55.08 20.844 55.215 ;
     RECT  119.772 54.945 138.24 55.215 ;
     RECT  2.16 55.485 12.312 55.62 ;
     RECT  12.636 55.485 20.844 55.62 ;
     RECT  2.16 55.62 20.844 55.755 ;
     RECT  119.772 55.485 138.24 55.755 ;
     RECT  2.16 56.025 2.916 56.16 ;
     RECT  3.456 56.025 20.844 56.16 ;
     RECT  2.16 56.16 3.888 56.295 ;
     RECT  4.428 56.16 11.394 56.295 ;
     RECT  11.934 56.16 20.844 56.295 ;
     RECT  119.772 56.025 138.24 56.295 ;
     RECT  2.16 56.565 6.804 56.7 ;
     RECT  7.128 56.565 20.844 56.7 ;
     RECT  2.16 56.7 20.844 56.835 ;
     RECT  119.772 56.565 138.24 56.835 ;
     RECT  2.16 57.105 4.32 57.24 ;
     RECT  4.86 57.105 20.844 57.24 ;
     RECT  2.16 57.24 9.018 57.375 ;
     RECT  9.558 57.24 20.844 57.375 ;
     RECT  119.772 57.105 138.24 57.375 ;
     RECT  2.16 57.645 20.844 57.78 ;
     RECT  2.16 57.78 3.348 57.915 ;
     RECT  3.888 57.78 6.372 57.915 ;
     RECT  6.912 57.78 8.424 57.915 ;
     RECT  8.964 57.78 20.844 57.915 ;
     RECT  119.772 57.645 138.24 57.915 ;
     RECT  2.16 58.185 20.844 58.32 ;
     RECT  2.16 58.32 4.158 58.455 ;
     RECT  4.698 58.32 6.048 58.455 ;
     RECT  6.588 58.32 20.844 58.455 ;
     RECT  119.772 58.185 138.24 58.455 ;
     RECT  2.16 58.725 20.844 58.86 ;
     RECT  2.16 58.86 8.262 58.995 ;
     RECT  8.802 58.86 20.844 58.995 ;
     RECT  119.772 58.725 138.24 58.995 ;
     RECT  4.806 59.265 20.844 59.4 ;
     RECT  2.16 59.265 3.726 59.535 ;
     RECT  4.266 59.4 6.21 59.535 ;
     RECT  6.75 59.4 8.154 59.535 ;
     RECT  8.694 59.4 11.07 59.535 ;
     RECT  11.61 59.4 20.844 59.535 ;
     RECT  119.772 59.265 138.24 59.535 ;
     RECT  2.16 59.805 6.642 59.94 ;
     RECT  7.182 59.805 20.844 59.94 ;
     RECT  2.16 59.94 20.844 60.075 ;
     RECT  119.772 59.805 138.24 60.075 ;
     RECT  2.16 60.345 4.32 60.48 ;
     RECT  4.86 60.345 20.844 60.48 ;
     RECT  2.16 60.48 6.642 60.615 ;
     RECT  7.182 60.48 20.844 60.615 ;
     RECT  119.772 60.345 138.24 60.615 ;
     RECT  2.16 60.885 4.644 61.02 ;
     RECT  5.184 60.885 20.844 61.02 ;
     RECT  2.16 61.02 20.844 61.155 ;
     RECT  119.772 60.885 138.24 61.155 ;
     RECT  2.16 61.425 20.844 61.695 ;
     RECT  119.772 61.425 138.24 61.695 ;
     RECT  2.16 61.965 20.844 62.235 ;
     RECT  119.772 61.965 138.24 62.235 ;
     RECT  2.16 62.505 20.844 62.775 ;
     RECT  119.772 62.505 138.24 62.775 ;
     RECT  2.16 63.045 20.844 63.315 ;
     RECT  119.772 63.045 138.24 63.315 ;
     RECT  2.16 63.585 20.844 63.72 ;
     RECT  2.16 63.72 16.092 63.855 ;
     RECT  16.578 63.72 20.844 63.855 ;
     RECT  119.772 63.585 138.24 63.855 ;
     RECT  2.16 64.125 8.694 64.26 ;
     RECT  9.018 64.125 15.66 64.26 ;
     RECT  15.984 64.125 16.362 64.26 ;
     RECT  16.686 64.125 20.844 64.26 ;
     RECT  2.16 64.26 20.844 64.395 ;
     RECT  119.772 64.125 138.24 64.395 ;
     RECT  2.16 64.665 15.984 64.8 ;
     RECT  16.47 64.665 16.74 64.8 ;
     RECT  17.226 64.665 18.738 64.8 ;
     RECT  19.224 64.665 20.844 64.8 ;
     RECT  2.16 64.8 16.092 64.935 ;
     RECT  16.578 64.8 20.844 64.935 ;
     RECT  119.772 64.665 138.24 64.935 ;
     RECT  2.16 65.205 15.498 65.34 ;
     RECT  16.47 65.205 17.226 65.34 ;
     RECT  18.198 65.205 20.844 65.34 ;
     RECT  2.16 65.34 15.822 65.475 ;
     RECT  16.794 65.34 20.844 65.475 ;
     RECT  119.772 65.205 138.24 65.475 ;
     RECT  2.16 65.745 16.362 65.88 ;
     RECT  16.848 65.745 20.844 65.88 ;
     RECT  2.16 65.88 16.254 66.015 ;
     RECT  16.74 65.88 20.844 66.015 ;
     RECT  119.772 65.745 138.24 66.015 ;
     RECT  2.16 66.285 15.498 66.42 ;
     RECT  15.984 66.285 17.766 66.42 ;
     RECT  18.252 66.285 20.844 66.42 ;
     RECT  2.16 66.42 15.984 66.555 ;
     RECT  16.47 66.42 17.658 66.555 ;
     RECT  19.116 66.42 20.844 66.555 ;
     RECT  119.772 66.285 138.24 66.555 ;
     RECT  2.16 66.825 20.844 67.095 ;
     RECT  119.772 66.825 138.24 67.095 ;
     RECT  2.16 67.365 20.844 67.635 ;
     RECT  119.772 67.365 138.24 67.635 ;
     RECT  2.16 67.905 20.844 68.175 ;
     RECT  119.772 67.905 138.24 68.175 ;
     RECT  2.16 68.445 20.844 68.715 ;
     RECT  119.772 68.445 138.24 68.715 ;
     RECT  2.16 68.985 20.844 69.255 ;
     RECT  119.772 68.985 138.24 69.255 ;
     RECT  2.16 69.525 20.844 69.795 ;
     RECT  119.772 69.525 138.24 69.795 ;
     RECT  2.16 70.065 20.844 70.335 ;
     RECT  119.772 70.065 138.24 70.335 ;
     RECT  2.16 70.605 20.844 70.875 ;
     RECT  119.772 70.605 138.24 70.875 ;
     RECT  2.16 71.145 20.844 71.415 ;
     RECT  119.772 71.145 138.24 71.415 ;
     RECT  2.16 71.685 20.844 71.955 ;
     RECT  119.772 71.685 138.24 71.955 ;
     RECT  2.16 72.225 20.844 72.495 ;
     RECT  119.772 72.225 138.24 72.495 ;
     RECT  2.16 72.765 20.844 73.035 ;
     RECT  119.772 72.765 138.24 73.035 ;
     RECT  2.16 73.305 20.844 73.575 ;
     RECT  119.772 73.305 138.24 73.575 ;
     RECT  2.16 73.845 20.844 74.115 ;
     RECT  119.772 73.845 138.24 74.115 ;
     RECT  2.16 74.385 20.844 74.655 ;
     RECT  119.772 74.385 138.24 74.655 ;
     RECT  2.16 74.925 20.844 75.195 ;
     RECT  119.772 74.925 138.24 75.195 ;
     RECT  2.16 75.465 20.844 75.735 ;
     RECT  119.772 75.465 138.24 75.735 ;
     RECT  2.16 76.005 20.844 76.275 ;
     RECT  119.772 76.005 138.24 76.275 ;
     RECT  2.16 76.545 20.844 76.815 ;
     RECT  119.772 76.545 138.24 76.815 ;
     RECT  2.16 77.085 20.844 77.355 ;
     RECT  119.772 77.085 138.24 77.355 ;
     RECT  2.16 77.625 20.844 77.76 ;
     RECT  119.772 77.625 138.24 77.76 ;
     RECT  2.16 77.76 138.24 77.895 ;
     RECT  2.16 78.165 138.24 78.435 ;
     RECT  2.16 78.705 138.24 78.975 ;
     RECT  2.16 79.245 138.24 79.515 ;
     RECT  2.16 79.785 138.24 80.055 ;
     RECT  2.16 80.325 138.24 80.595 ;
     RECT  2.16 80.865 138.24 81.135 ;
     RECT  2.16 81.405 138.24 81.675 ;
     RECT  2.16 81.945 138.24 82.215 ;
     RECT  2.16 82.485 138.24 82.755 ;
     RECT  2.16 83.025 138.24 83.295 ;
     RECT  2.16 83.565 138.24 83.835 ;
     RECT  2.16 84.105 138.24 84.375 ;
     RECT  2.16 84.645 138.24 84.915 ;
     RECT  2.16 85.185 138.24 85.455 ;
     RECT  2.16 85.725 138.24 85.995 ;
     RECT  2.16 86.265 138.24 86.535 ;
     RECT  2.16 86.805 138.24 87.075 ;
     RECT  2.16 87.345 138.24 87.615 ;
     RECT  2.16 87.885 138.24 88.155 ;
     RECT  2.16 88.425 138.24 88.695 ;
     RECT  2.16 88.965 138.24 89.235 ;
     RECT  2.16 89.505 138.24 89.775 ;
     RECT  2.16 90.045 138.24 90.315 ;
     RECT  2.16 90.585 138.24 90.855 ;
     RECT  2.16 91.125 138.24 91.395 ;
     RECT  2.16 91.665 138.24 91.935 ;
     RECT  2.16 92.205 138.24 92.475 ;
     RECT  2.16 92.745 138.24 93.015 ;
     RECT  2.16 93.285 138.24 93.555 ;
     RECT  2.16 93.825 138.24 94.095 ;
     RECT  2.16 94.365 138.24 94.635 ;
     RECT  2.16 94.905 138.24 95.175 ;
     RECT  2.16 95.445 138.24 95.715 ;
     RECT  2.16 95.985 138.24 96.255 ;
     RECT  2.16 96.525 138.24 96.795 ;
     RECT  2.16 97.065 138.24 97.335 ;
     RECT  2.16 97.605 138.24 97.875 ;
     RECT  2.16 98.145 138.24 98.415 ;
     RECT  2.16 98.685 138.24 98.955 ;
     RECT  2.16 99.225 138.24 99.495 ;
     RECT  2.16 99.765 138.24 100.035 ;
     RECT  2.16 100.305 138.24 100.575 ;
     RECT  2.16 100.845 138.24 101.115 ;
     RECT  2.16 101.385 138.24 101.655 ;
     RECT  2.16 101.925 138.24 102.195 ;
     RECT  2.16 102.465 138.24 102.735 ;
     RECT  2.16 103.005 138.24 103.275 ;
     RECT  2.16 103.545 138.24 103.815 ;
     RECT  2.16 104.085 138.24 104.355 ;
     RECT  2.16 104.625 138.24 104.895 ;
     RECT  2.16 105.165 138.24 105.435 ;
     RECT  2.16 105.705 138.24 105.975 ;
     RECT  2.16 106.245 138.24 106.515 ;
     RECT  2.16 106.785 138.24 107.055 ;
     RECT  2.16 107.325 138.24 107.595 ;
     RECT  2.16 107.865 138.24 108.135 ;
     RECT  2.16 108.405 138.24 108.675 ;
     RECT  2.16 108.945 138.24 109.215 ;
     RECT  2.16 109.485 138.24 109.62 ;
     RECT  2.16 109.62 10.53 109.755 ;
     RECT  11.718 109.62 138.24 109.755 ;
     RECT  2.16 110.025 138.24 110.16 ;
    LAYER RVTP ;
     RECT  2.16 2.295 138.24 2.565 ;
     RECT  2.16 2.835 138.24 3.105 ;
     RECT  2.16 3.375 138.24 3.645 ;
     RECT  2.16 3.915 138.24 4.05 ;
     RECT  2.16 4.05 45.846 4.185 ;
     RECT  46.116 4.05 138.24 4.185 ;
     RECT  2.16 4.455 138.24 4.725 ;
     RECT  2.16 4.995 138.24 5.13 ;
     RECT  2.16 5.13 21.438 5.265 ;
     RECT  22.032 5.13 138.24 5.265 ;
     RECT  2.16 5.535 21.6 5.67 ;
     RECT  21.978 5.535 138.24 5.67 ;
     RECT  2.16 5.67 138.24 5.805 ;
     RECT  2.16 6.075 13.932 6.21 ;
     RECT  15.336 6.075 20.142 6.21 ;
     RECT  20.79 6.075 138.24 6.21 ;
     RECT  2.16 6.21 17.928 6.345 ;
     RECT  18.306 6.21 138.24 6.345 ;
     RECT  2.16 6.615 20.142 6.75 ;
     RECT  20.52 6.615 138.24 6.75 ;
     RECT  2.16 6.75 13.392 6.885 ;
     RECT  14.796 6.75 138.24 6.885 ;
     RECT  2.16 7.155 138.24 7.425 ;
     RECT  2.16 7.695 138.24 7.83 ;
     RECT  2.16 7.83 21.708 7.965 ;
     RECT  22.14 7.83 138.24 7.965 ;
     RECT  2.16 8.235 14.148 8.37 ;
     RECT  15.552 8.235 138.24 8.37 ;
     RECT  2.16 8.37 18.468 8.505 ;
     RECT  18.846 8.37 20.25 8.505 ;
     RECT  20.574 8.37 138.24 8.505 ;
     RECT  2.16 8.775 138.24 9.045 ;
     RECT  2.16 9.315 138.24 9.45 ;
     RECT  2.16 9.45 18.954 9.585 ;
     RECT  19.332 9.45 138.24 9.585 ;
     RECT  2.16 9.855 19.44 9.99 ;
     RECT  19.764 9.855 20.25 9.99 ;
     RECT  20.574 9.855 138.24 9.99 ;
     RECT  2.16 9.99 18.846 10.125 ;
     RECT  19.224 9.99 138.24 10.125 ;
     RECT  2.16 10.395 138.24 10.665 ;
     RECT  2.16 10.935 138.24 11.205 ;
     RECT  2.16 11.475 138.24 11.745 ;
     RECT  2.16 12.015 138.24 12.285 ;
     RECT  2.16 12.555 138.24 12.825 ;
     RECT  2.16 13.095 138.24 13.365 ;
     RECT  2.16 13.635 138.24 13.905 ;
     RECT  2.16 14.175 138.24 14.445 ;
     RECT  2.16 14.715 138.24 14.985 ;
     RECT  2.16 15.255 138.24 15.525 ;
     RECT  2.16 15.795 138.24 16.065 ;
     RECT  2.16 16.335 138.24 16.47 ;
     RECT  2.16 16.47 18.522 16.605 ;
     RECT  19.062 16.47 138.24 16.605 ;
     RECT  2.16 16.875 138.24 17.145 ;
     RECT  2.16 17.415 138.24 17.685 ;
     RECT  2.16 17.955 138.24 18.225 ;
     RECT  2.16 18.495 138.24 18.765 ;
     RECT  2.16 19.035 138.24 19.305 ;
     RECT  2.16 19.575 138.24 19.845 ;
     RECT  2.16 20.115 138.24 20.385 ;
     RECT  2.16 20.655 138.24 20.925 ;
     RECT  2.16 21.195 138.24 21.465 ;
     RECT  2.16 21.735 138.24 22.005 ;
     RECT  2.16 22.275 138.24 22.545 ;
     RECT  2.16 22.815 5.616 22.95 ;
     RECT  6.048 22.815 138.24 22.95 ;
     RECT  2.16 22.95 138.24 23.085 ;
     RECT  2.16 23.355 138.24 23.625 ;
     RECT  2.16 23.895 138.24 24.165 ;
     RECT  2.16 24.435 138.24 24.705 ;
     RECT  2.16 24.975 138.24 25.245 ;
     RECT  2.16 25.515 138.24 25.785 ;
     RECT  2.16 26.055 138.24 26.325 ;
     RECT  2.16 26.595 138.24 26.865 ;
     RECT  2.16 27.135 138.24 27.405 ;
     RECT  2.16 27.675 138.24 27.945 ;
     RECT  2.16 28.215 16.038 28.35 ;
     RECT  16.578 28.215 138.24 28.35 ;
     RECT  2.16 28.35 138.24 28.485 ;
     RECT  2.16 28.755 138.24 29.025 ;
     RECT  2.16 29.295 138.24 29.565 ;
     RECT  2.16 29.835 7.722 29.97 ;
     RECT  8.316 29.835 138.24 29.97 ;
     RECT  2.16 29.97 7.83 30.105 ;
     RECT  8.154 29.97 9.018 30.105 ;
     RECT  9.45 29.97 138.24 30.105 ;
     RECT  2.16 30.375 138.24 30.645 ;
     RECT  2.16 30.915 138.24 31.185 ;
     RECT  2.16 31.455 9.126 31.59 ;
     RECT  9.504 31.455 10.422 31.59 ;
     RECT  10.854 31.455 138.24 31.59 ;
     RECT  2.16 31.59 138.24 31.725 ;
     RECT  2.16 31.995 138.24 32.265 ;
     RECT  2.16 32.535 20.844 32.805 ;
     RECT  119.772 32.535 138.24 32.805 ;
     RECT  2.16 33.075 20.844 33.345 ;
     RECT  119.772 33.075 138.24 33.345 ;
     RECT  2.16 33.615 20.844 33.885 ;
     RECT  119.772 33.615 138.24 33.885 ;
     RECT  2.16 34.155 20.844 34.425 ;
     RECT  119.772 34.155 138.24 34.425 ;
     RECT  2.16 34.695 20.844 34.965 ;
     RECT  119.772 34.695 138.24 34.965 ;
     RECT  2.16 35.235 20.844 35.505 ;
     RECT  119.772 35.235 138.24 35.505 ;
     RECT  2.16 35.775 20.844 36.045 ;
     RECT  119.772 35.775 138.24 36.045 ;
     RECT  2.16 36.315 20.844 36.585 ;
     RECT  119.772 36.315 138.24 36.585 ;
     RECT  2.16 36.855 20.844 37.125 ;
     RECT  119.772 36.855 138.24 37.125 ;
     RECT  2.16 37.395 20.844 37.665 ;
     RECT  119.772 37.395 138.24 37.665 ;
     RECT  2.16 37.935 20.844 38.205 ;
     RECT  119.772 37.935 138.24 38.205 ;
     RECT  2.16 38.475 20.844 38.745 ;
     RECT  119.772 38.475 138.24 38.745 ;
     RECT  2.16 39.015 20.844 39.285 ;
     RECT  119.772 39.015 138.24 39.285 ;
     RECT  2.16 39.555 20.844 39.825 ;
     RECT  119.772 39.555 138.24 39.825 ;
     RECT  2.16 40.095 20.844 40.365 ;
     RECT  119.772 40.095 138.24 40.365 ;
     RECT  2.16 40.635 20.844 40.905 ;
     RECT  119.772 40.635 138.24 40.905 ;
     RECT  2.16 41.175 20.844 41.445 ;
     RECT  119.772 41.175 138.24 41.445 ;
     RECT  2.16 41.715 20.844 41.985 ;
     RECT  119.772 41.715 138.24 41.985 ;
     RECT  2.16 42.255 20.844 42.525 ;
     RECT  119.772 42.255 138.24 42.525 ;
     RECT  2.16 42.795 20.844 43.065 ;
     RECT  119.772 42.795 138.24 43.065 ;
     RECT  2.16 43.335 11.934 43.47 ;
     RECT  12.474 43.335 20.844 43.47 ;
     RECT  2.16 43.47 20.844 43.605 ;
     RECT  119.772 43.335 138.24 43.605 ;
     RECT  2.16 43.875 20.844 44.145 ;
     RECT  119.772 43.875 138.24 44.145 ;
     RECT  2.16 44.415 9.234 44.55 ;
     RECT  10.098 44.415 20.844 44.55 ;
     RECT  2.16 44.55 11.448 44.685 ;
     RECT  11.88 44.55 20.844 44.685 ;
     RECT  119.772 44.415 138.24 44.685 ;
     RECT  2.16 44.955 12.312 45.09 ;
     RECT  12.69 44.955 20.844 45.09 ;
     RECT  2.16 45.09 11.232 45.225 ;
     RECT  11.61 45.09 20.844 45.225 ;
     RECT  119.772 44.955 138.24 45.225 ;
     RECT  2.16 45.495 19.656 45.63 ;
     RECT  20.196 45.495 20.844 45.63 ;
     RECT  2.16 45.63 20.844 45.765 ;
     RECT  119.772 45.495 138.24 45.765 ;
     RECT  2.16 46.035 20.196 46.17 ;
     RECT  20.736 46.035 20.844 46.17 ;
     RECT  2.16 46.17 20.844 46.305 ;
     RECT  119.772 46.035 138.24 46.305 ;
     RECT  2.16 46.575 20.844 46.845 ;
     RECT  119.772 46.575 138.24 46.845 ;
     RECT  2.16 47.115 20.844 47.385 ;
     RECT  119.772 47.115 138.24 47.385 ;
     RECT  2.16 47.655 20.844 47.925 ;
     RECT  119.772 47.655 138.24 47.925 ;
     RECT  2.16 48.195 20.844 48.33 ;
     RECT  2.16 48.33 13.176 48.465 ;
     RECT  13.5 48.33 20.844 48.465 ;
     RECT  119.772 48.195 138.24 48.465 ;
     RECT  2.16 48.735 10.26 48.87 ;
     RECT  10.584 48.735 20.844 48.87 ;
     RECT  2.16 48.87 20.844 49.005 ;
     RECT  119.772 48.735 138.24 49.005 ;
     RECT  2.16 49.275 11.07 49.41 ;
     RECT  11.232 49.275 20.844 49.41 ;
     RECT  2.16 49.41 20.844 49.545 ;
     RECT  119.772 49.275 138.24 49.545 ;
     RECT  2.16 49.815 20.844 50.085 ;
     RECT  119.772 49.815 138.24 50.085 ;
     RECT  2.16 50.355 20.844 50.625 ;
     RECT  119.772 50.355 138.24 50.625 ;
     RECT  2.16 50.895 20.844 51.165 ;
     RECT  119.772 50.895 138.24 51.165 ;
     RECT  2.16 51.435 20.844 51.705 ;
     RECT  119.772 51.435 138.24 51.705 ;
     RECT  2.16 51.975 11.34 52.11 ;
     RECT  11.88 51.975 20.844 52.11 ;
     RECT  2.16 52.11 5.616 52.245 ;
     RECT  6.156 52.11 20.844 52.245 ;
     RECT  119.772 51.975 138.24 52.245 ;
     RECT  2.16 52.515 9.018 52.65 ;
     RECT  9.234 52.515 13.068 52.65 ;
     RECT  13.716 52.515 14.526 52.65 ;
     RECT  14.958 52.515 20.844 52.65 ;
     RECT  2.16 52.65 10.53 52.785 ;
     RECT  11.502 52.65 13.284 52.785 ;
     RECT  13.824 52.65 20.844 52.785 ;
     RECT  119.772 52.515 138.24 52.785 ;
     RECT  2.16 53.055 10.638 53.19 ;
     RECT  11.772 53.055 20.844 53.19 ;
     RECT  2.16 53.19 4.806 53.325 ;
     RECT  5.346 53.19 13.554 53.325 ;
     RECT  14.094 53.19 20.844 53.325 ;
     RECT  119.772 53.055 138.24 53.325 ;
     RECT  2.16 53.595 3.348 53.73 ;
     RECT  3.888 53.595 20.844 53.73 ;
     RECT  2.16 53.73 4.158 53.865 ;
     RECT  4.698 53.73 8.748 53.865 ;
     RECT  9.072 53.73 20.844 53.865 ;
     RECT  119.772 53.595 138.24 53.865 ;
     RECT  2.16 54.135 3.456 54.27 ;
     RECT  3.996 54.135 20.844 54.27 ;
     RECT  2.16 54.27 8.694 54.405 ;
     RECT  9.018 54.27 20.844 54.405 ;
     RECT  119.772 54.135 138.24 54.405 ;
     RECT  2.16 54.675 2.916 54.81 ;
     RECT  3.456 54.675 13.446 54.81 ;
     RECT  13.77 54.675 20.844 54.81 ;
     RECT  2.16 54.81 3.456 54.945 ;
     RECT  3.996 54.81 20.844 54.945 ;
     RECT  119.772 54.675 138.24 54.945 ;
     RECT  2.16 55.215 5.94 55.35 ;
     RECT  6.372 55.215 11.556 55.35 ;
     RECT  11.88 55.215 13.392 55.35 ;
     RECT  13.824 55.215 20.844 55.35 ;
     RECT  2.16 55.35 12.312 55.485 ;
     RECT  12.636 55.35 20.844 55.485 ;
     RECT  119.772 55.215 138.24 55.485 ;
     RECT  2.16 55.755 20.844 55.89 ;
     RECT  2.16 55.89 2.916 56.025 ;
     RECT  3.456 55.89 20.844 56.025 ;
     RECT  119.772 55.755 138.24 56.025 ;
     RECT  2.16 56.295 3.888 56.43 ;
     RECT  4.428 56.295 11.394 56.43 ;
     RECT  11.934 56.295 20.844 56.43 ;
     RECT  2.16 56.43 6.804 56.565 ;
     RECT  7.128 56.43 20.844 56.565 ;
     RECT  119.772 56.295 138.24 56.565 ;
     RECT  2.16 56.835 20.844 56.97 ;
     RECT  2.16 56.97 4.32 57.105 ;
     RECT  4.86 56.97 20.844 57.105 ;
     RECT  119.772 56.835 138.24 57.105 ;
     RECT  2.16 57.375 9.018 57.51 ;
     RECT  9.558 57.375 20.844 57.51 ;
     RECT  2.16 57.51 20.844 57.645 ;
     RECT  119.772 57.375 138.24 57.645 ;
     RECT  2.16 57.915 3.348 58.05 ;
     RECT  3.888 57.915 6.372 58.05 ;
     RECT  6.912 57.915 8.424 58.05 ;
     RECT  8.964 57.915 20.844 58.05 ;
     RECT  2.16 58.05 20.844 58.185 ;
     RECT  119.772 57.915 138.24 58.185 ;
     RECT  2.16 58.455 4.158 58.59 ;
     RECT  4.698 58.455 6.048 58.59 ;
     RECT  6.588 58.455 20.844 58.59 ;
     RECT  2.16 58.59 20.844 58.725 ;
     RECT  119.772 58.455 138.24 58.725 ;
     RECT  2.16 58.995 8.262 59.13 ;
     RECT  8.802 58.995 20.844 59.13 ;
     RECT  2.16 59.13 3.726 59.265 ;
     RECT  4.806 59.13 20.844 59.265 ;
     RECT  119.772 58.995 138.24 59.265 ;
     RECT  2.16 59.535 3.726 59.67 ;
     RECT  4.266 59.535 6.21 59.67 ;
     RECT  6.75 59.535 8.154 59.67 ;
     RECT  8.694 59.535 11.07 59.67 ;
     RECT  11.61 59.535 20.844 59.67 ;
     RECT  2.16 59.67 6.642 59.805 ;
     RECT  7.182 59.67 20.844 59.805 ;
     RECT  119.772 59.535 138.24 59.805 ;
     RECT  2.16 60.075 20.844 60.21 ;
     RECT  2.16 60.21 4.32 60.345 ;
     RECT  4.86 60.21 20.844 60.345 ;
     RECT  119.772 60.075 138.24 60.345 ;
     RECT  2.16 60.615 6.642 60.75 ;
     RECT  7.182 60.615 20.844 60.75 ;
     RECT  2.16 60.75 4.644 60.885 ;
     RECT  5.184 60.75 20.844 60.885 ;
     RECT  119.772 60.615 138.24 60.885 ;
     RECT  2.16 61.155 20.844 61.425 ;
     RECT  119.772 61.155 138.24 61.425 ;
     RECT  2.16 61.695 20.844 61.965 ;
     RECT  119.772 61.695 138.24 61.965 ;
     RECT  2.16 62.235 20.844 62.505 ;
     RECT  119.772 62.235 138.24 62.505 ;
     RECT  2.16 62.775 20.844 63.045 ;
     RECT  119.772 62.775 138.24 63.045 ;
     RECT  2.16 63.315 20.844 63.585 ;
     RECT  119.772 63.315 138.24 63.585 ;
     RECT  2.16 63.855 16.092 63.99 ;
     RECT  16.578 63.855 20.844 63.99 ;
     RECT  2.16 63.99 8.694 64.125 ;
     RECT  9.018 63.99 15.66 64.125 ;
     RECT  15.984 63.99 16.362 64.125 ;
     RECT  16.686 63.99 20.844 64.125 ;
     RECT  119.772 63.855 138.24 64.125 ;
     RECT  2.16 64.395 20.844 64.53 ;
     RECT  2.16 64.53 15.984 64.665 ;
     RECT  16.47 64.53 16.74 64.665 ;
     RECT  17.226 64.53 18.738 64.665 ;
     RECT  19.224 64.53 20.844 64.665 ;
     RECT  119.772 64.395 138.24 64.665 ;
     RECT  2.16 64.935 16.092 65.07 ;
     RECT  16.578 64.935 20.844 65.07 ;
     RECT  2.16 65.07 15.498 65.205 ;
     RECT  16.47 65.07 17.226 65.205 ;
     RECT  18.198 65.07 20.844 65.205 ;
     RECT  119.772 64.935 138.24 65.205 ;
     RECT  2.16 65.475 15.822 65.61 ;
     RECT  16.794 65.475 20.844 65.61 ;
     RECT  2.16 65.61 16.362 65.745 ;
     RECT  16.848 65.61 20.844 65.745 ;
     RECT  119.772 65.475 138.24 65.745 ;
     RECT  2.16 66.015 16.254 66.15 ;
     RECT  16.74 66.015 20.844 66.15 ;
     RECT  2.16 66.15 15.498 66.285 ;
     RECT  15.984 66.15 17.766 66.285 ;
     RECT  18.252 66.15 20.844 66.285 ;
     RECT  119.772 66.015 138.24 66.285 ;
     RECT  2.16 66.555 15.984 66.69 ;
     RECT  16.47 66.555 17.658 66.69 ;
     RECT  19.116 66.555 20.844 66.69 ;
     RECT  2.16 66.69 20.844 66.825 ;
     RECT  119.772 66.555 138.24 66.825 ;
     RECT  2.16 67.095 20.844 67.365 ;
     RECT  119.772 67.095 138.24 67.365 ;
     RECT  2.16 67.635 20.844 67.905 ;
     RECT  119.772 67.635 138.24 67.905 ;
     RECT  2.16 68.175 20.844 68.445 ;
     RECT  119.772 68.175 138.24 68.445 ;
     RECT  2.16 68.715 20.844 68.985 ;
     RECT  119.772 68.715 138.24 68.985 ;
     RECT  2.16 69.255 20.844 69.525 ;
     RECT  119.772 69.255 138.24 69.525 ;
     RECT  2.16 69.795 20.844 70.065 ;
     RECT  119.772 69.795 138.24 70.065 ;
     RECT  2.16 70.335 20.844 70.605 ;
     RECT  119.772 70.335 138.24 70.605 ;
     RECT  2.16 70.875 20.844 71.145 ;
     RECT  119.772 70.875 138.24 71.145 ;
     RECT  2.16 71.415 20.844 71.685 ;
     RECT  119.772 71.415 138.24 71.685 ;
     RECT  2.16 71.955 20.844 72.225 ;
     RECT  119.772 71.955 138.24 72.225 ;
     RECT  2.16 72.495 20.844 72.765 ;
     RECT  119.772 72.495 138.24 72.765 ;
     RECT  2.16 73.035 20.844 73.305 ;
     RECT  119.772 73.035 138.24 73.305 ;
     RECT  2.16 73.575 20.844 73.845 ;
     RECT  119.772 73.575 138.24 73.845 ;
     RECT  2.16 74.115 20.844 74.385 ;
     RECT  119.772 74.115 138.24 74.385 ;
     RECT  2.16 74.655 20.844 74.925 ;
     RECT  119.772 74.655 138.24 74.925 ;
     RECT  2.16 75.195 20.844 75.465 ;
     RECT  119.772 75.195 138.24 75.465 ;
     RECT  2.16 75.735 20.844 76.005 ;
     RECT  119.772 75.735 138.24 76.005 ;
     RECT  2.16 76.275 20.844 76.545 ;
     RECT  119.772 76.275 138.24 76.545 ;
     RECT  2.16 76.815 20.844 77.085 ;
     RECT  119.772 76.815 138.24 77.085 ;
     RECT  2.16 77.355 20.844 77.625 ;
     RECT  119.772 77.355 138.24 77.625 ;
     RECT  2.16 77.895 138.24 78.165 ;
     RECT  2.16 78.435 138.24 78.705 ;
     RECT  2.16 78.975 138.24 79.245 ;
     RECT  2.16 79.515 138.24 79.785 ;
     RECT  2.16 80.055 138.24 80.325 ;
     RECT  2.16 80.595 138.24 80.865 ;
     RECT  2.16 81.135 138.24 81.405 ;
     RECT  2.16 81.675 138.24 81.945 ;
     RECT  2.16 82.215 138.24 82.485 ;
     RECT  2.16 82.755 138.24 83.025 ;
     RECT  2.16 83.295 138.24 83.565 ;
     RECT  2.16 83.835 138.24 84.105 ;
     RECT  2.16 84.375 138.24 84.645 ;
     RECT  2.16 84.915 138.24 85.185 ;
     RECT  2.16 85.455 138.24 85.725 ;
     RECT  2.16 85.995 138.24 86.265 ;
     RECT  2.16 86.535 138.24 86.805 ;
     RECT  2.16 87.075 138.24 87.345 ;
     RECT  2.16 87.615 138.24 87.885 ;
     RECT  2.16 88.155 138.24 88.425 ;
     RECT  2.16 88.695 138.24 88.965 ;
     RECT  2.16 89.235 138.24 89.505 ;
     RECT  2.16 89.775 138.24 90.045 ;
     RECT  2.16 90.315 138.24 90.585 ;
     RECT  2.16 90.855 138.24 91.125 ;
     RECT  2.16 91.395 138.24 91.665 ;
     RECT  2.16 91.935 138.24 92.205 ;
     RECT  2.16 92.475 138.24 92.745 ;
     RECT  2.16 93.015 138.24 93.285 ;
     RECT  2.16 93.555 138.24 93.825 ;
     RECT  2.16 94.095 138.24 94.365 ;
     RECT  2.16 94.635 138.24 94.905 ;
     RECT  2.16 95.175 138.24 95.445 ;
     RECT  2.16 95.715 138.24 95.985 ;
     RECT  2.16 96.255 138.24 96.525 ;
     RECT  2.16 96.795 138.24 97.065 ;
     RECT  2.16 97.335 138.24 97.605 ;
     RECT  2.16 97.875 138.24 98.145 ;
     RECT  2.16 98.415 138.24 98.685 ;
     RECT  2.16 98.955 138.24 99.225 ;
     RECT  2.16 99.495 138.24 99.765 ;
     RECT  2.16 100.035 138.24 100.305 ;
     RECT  2.16 100.575 138.24 100.845 ;
     RECT  2.16 101.115 138.24 101.385 ;
     RECT  2.16 101.655 138.24 101.925 ;
     RECT  2.16 102.195 138.24 102.465 ;
     RECT  2.16 102.735 138.24 103.005 ;
     RECT  2.16 103.275 138.24 103.545 ;
     RECT  2.16 103.815 138.24 104.085 ;
     RECT  2.16 104.355 138.24 104.625 ;
     RECT  2.16 104.895 138.24 105.165 ;
     RECT  2.16 105.435 138.24 105.705 ;
     RECT  2.16 105.975 138.24 106.245 ;
     RECT  2.16 106.515 138.24 106.785 ;
     RECT  2.16 107.055 138.24 107.325 ;
     RECT  2.16 107.595 138.24 107.865 ;
     RECT  2.16 108.135 138.24 108.405 ;
     RECT  2.16 108.675 138.24 108.945 ;
     RECT  2.16 109.215 138.24 109.485 ;
     RECT  2.16 109.755 10.53 109.89 ;
     RECT  11.718 109.755 138.24 109.89 ;
     RECT  2.16 109.89 138.24 110.025 ;
    LAYER M1 ;
     RECT  2.16 2.151 138.24 32.409 ;
     RECT  22.896 34.56 117.72 75.624 ;
     RECT  2.16 32.409 20.844 77.751 ;
     RECT  119.772 32.409 138.24 77.751 ;
     RECT  2.16 77.751 138.24 110.169 ;
    LAYER M2 ;
     RECT  0.067 22.626 0.103 22.644 ;
     RECT  0.067 24.174 0.103 24.192 ;
     RECT  0.103 20.16 0.139 20.178 ;
     RECT  0.103 25.641 0.139 26.199 ;
     RECT  0.103 21.24 0.167 22.644 ;
     RECT  0.139 25.182 0.203 26.199 ;
     RECT  0.103 29.844 0.239 30.906 ;
     RECT  0.103 27.342 0.499 27.9 ;
     RECT  0.499 27.216 0.535 27.9 ;
     RECT  0.139 31.662 0.535 31.68 ;
     RECT  0.103 32.886 0.823 32.904 ;
     RECT  0.571 33.822 0.823 33.84 ;
     RECT  0.103 23.562 1.147 24.192 ;
     RECT  0.203 25.182 1.147 26.118 ;
     RECT  0.535 27.144 1.147 27.9 ;
     RECT  0.239 29.844 1.147 30.438 ;
     RECT  0.535 31.428 1.147 31.68 ;
     RECT  1.147 29.844 1.183 32.094 ;
     RECT  0.823 32.886 1.183 33.84 ;
     RECT  1.183 29.844 1.283 33.84 ;
     RECT  1.147 23.292 1.399 26.118 ;
     RECT  1.147 27.072 1.399 27.9 ;
     RECT  1.147 3.186 1.543 3.204 ;
     RECT  1.543 3.186 1.579 3.834 ;
     RECT  1.579 7.056 1.615 7.074 ;
     RECT  1.579 3.186 1.687 3.978 ;
     RECT  1.039 5.346 1.723 5.364 ;
     RECT  0.103 28.8 1.723 28.818 ;
     RECT  1.615 7.056 1.759 7.65 ;
     RECT  1.723 4.806 1.795 5.364 ;
     RECT  1.759 6.786 1.831 7.65 ;
     RECT  1.543 10.296 1.831 10.314 ;
     RECT  1.831 6.696 1.903 7.65 ;
     RECT  1.831 9.756 1.903 10.314 ;
     RECT  1.903 6.624 1.975 7.65 ;
     RECT  1.723 28.8 1.975 28.98 ;
     RECT  0.139 20.16 2.011 20.34 ;
     RECT  2.011 8.676 2.047 8.694 ;
     RECT  0.283 19.35 2.047 19.368 ;
     RECT  0.167 21.24 2.083 22.5 ;
     RECT  1.399 23.292 2.083 27.9 ;
     RECT  2.047 18.846 2.119 19.368 ;
     RECT  1.795 4.734 2.155 5.364 ;
     RECT  1.975 6.426 2.155 7.65 ;
     RECT  1.903 9.756 2.155 10.692 ;
     RECT  2.083 11.826 2.155 11.844 ;
     RECT  1.651 1.422 2.16 1.44 ;
     RECT  2.155 2.268 2.16 2.286 ;
     RECT  1.687 3.114 2.16 3.978 ;
     RECT  2.155 4.734 2.16 7.65 ;
     RECT  2.047 8.478 2.16 8.694 ;
     RECT  2.155 9.756 2.16 11.844 ;
     RECT  1.867 13.068 2.16 13.086 ;
     RECT  1.975 15.426 2.16 15.444 ;
     RECT  2.119 18.198 2.16 19.368 ;
     RECT  2.011 20.16 2.16 20.484 ;
     RECT  2.083 21.24 2.16 27.9 ;
     RECT  1.975 28.8 2.16 29.052 ;
     RECT  1.283 29.844 2.16 30.438 ;
     RECT  1.283 31.428 2.16 33.84 ;
     RECT  1.939 63.558 2.16 63.576 ;
     RECT  7.339 111.42 7.411 111.438 ;
     RECT  7.411 111.42 8.527 111.708 ;
     RECT  8.527 111.42 8.743 112.104 ;
     RECT  8.743 111.42 8.995 112.176 ;
     RECT  2.16 1.422 9.571 110.169 ;
     RECT  8.995 111.042 9.571 112.176 ;
     RECT  9.571 1.422 9.931 112.176 ;
     RECT  1.939 0.072 15.799 0.09 ;
     RECT  15.799 0.072 17.635 0.279 ;
     RECT  17.635 0.036 18.275 0.279 ;
     RECT  18.275 0.036 20.767 0.198 ;
     RECT  9.931 1.422 20.844 112.284 ;
     RECT  20.767 0.036 20.903 0.324 ;
     RECT  20.844 1.422 21.011 38.7 ;
     RECT  20.844 43.074 21.011 45.414 ;
     RECT  21.011 1.422 21.083 37.386 ;
     RECT  21.011 43.884 21.083 45.414 ;
     RECT  20.844 46.314 21.083 57.636 ;
     RECT  20.844 74.826 21.083 112.284 ;
     RECT  20.844 39.564 21.119 42.084 ;
     RECT  21.011 38.286 21.155 38.7 ;
     RECT  21.083 43.884 21.155 44.334 ;
     RECT  20.844 61.236 21.299 73.764 ;
     RECT  21.119 41.526 21.335 42.084 ;
     RECT  21.155 44.118 21.371 44.334 ;
     RECT  21.083 46.314 21.407 49.572 ;
     RECT  21.407 46.314 21.515 48.924 ;
     RECT  21.155 38.286 21.551 38.394 ;
     RECT  21.335 41.526 21.587 41.544 ;
     RECT  21.299 61.704 21.659 73.764 ;
     RECT  20.844 58.464 21.667 60.408 ;
     RECT  21.083 1.422 21.695 36.27 ;
     RECT  21.659 66.294 21.695 73.764 ;
     RECT  21.083 50.598 21.703 57.636 ;
     RECT  21.667 58.464 21.703 60.444 ;
     RECT  21.703 50.598 21.767 60.444 ;
     RECT  21.767 50.598 21.839 60.408 ;
     RECT  21.695 35.514 21.911 36.27 ;
     RECT  21.839 50.598 21.911 57.636 ;
     RECT  21.911 52.056 21.947 57.636 ;
     RECT  21.119 39.564 21.955 40.734 ;
     RECT  21.551 38.376 21.983 38.394 ;
     RECT  21.955 39.528 21.983 40.734 ;
     RECT  21.083 45.396 22.063 45.414 ;
     RECT  21.983 39.528 22.091 40.158 ;
     RECT  22.091 40.14 22.163 40.158 ;
     RECT  22.063 45.036 22.163 45.414 ;
     RECT  21.515 47.664 22.163 48.924 ;
     RECT  21.083 75.438 22.351 112.284 ;
     RECT  22.243 38.52 22.567 38.736 ;
     RECT  21.011 43.074 22.603 43.092 ;
     RECT  20.903 0.036 22.639 0.198 ;
     RECT  21.695 1.422 22.639 34.758 ;
     RECT  21.911 35.514 22.675 36.072 ;
     RECT  22.567 38.52 22.675 38.772 ;
     RECT  21.911 50.598 22.747 51.228 ;
     RECT  22.639 0.036 22.896 34.758 ;
     RECT  22.675 35.514 22.896 36.378 ;
     RECT  21.083 37.368 22.896 37.386 ;
     RECT  22.675 38.52 22.896 38.844 ;
     RECT  22.747 40.95 22.896 40.968 ;
     RECT  22.603 42.768 22.896 43.092 ;
     RECT  22.163 45.396 22.896 45.414 ;
     RECT  21.515 46.314 22.896 46.638 ;
     RECT  22.163 47.664 22.896 48.726 ;
     RECT  22.747 50.211 22.896 51.228 ;
     RECT  21.947 52.596 22.896 57.636 ;
     RECT  21.839 58.464 22.896 60.372 ;
     RECT  21.659 61.704 22.896 65.538 ;
     RECT  21.695 66.528 22.896 73.764 ;
     RECT  22.351 75.366 22.896 112.284 ;
     RECT  22.896 0.036 33.107 112.284 ;
     RECT  33.107 110.916 35.375 112.284 ;
     RECT  35.375 110.961 35.591 112.284 ;
     RECT  33.107 0.036 37.895 110.169 ;
     RECT  37.895 0.036 38.219 76.149 ;
     RECT  37.895 77.022 39.415 110.169 ;
     RECT  39.415 77.022 39.515 110.556 ;
     RECT  38.219 0.036 40.487 75.624 ;
     RECT  39.515 77.022 41.063 110.169 ;
     RECT  41.063 77.526 41.711 110.169 ;
     RECT  41.711 77.67 42.331 110.169 ;
     RECT  42.331 77.67 42.431 110.592 ;
     RECT  40.487 0.846 42.971 75.624 ;
     RECT  35.591 111.42 43.367 112.284 ;
     RECT  42.431 77.67 44.231 110.169 ;
     RECT  43.367 111.456 45.059 112.284 ;
     RECT  44.231 77.706 45.095 110.169 ;
     RECT  45.059 112.23 45.635 112.284 ;
     RECT  45.635 112.266 46.031 112.284 ;
     RECT  45.059 111.456 46.211 111.474 ;
     RECT  40.487 0.036 95.783 0.054 ;
     RECT  45.095 77.751 109.687 110.169 ;
     RECT  109.687 77.706 116.339 110.169 ;
     RECT  42.971 2.151 117.72 75.624 ;
     RECT  117.72 35.316 117.851 35.334 ;
     RECT  117.72 43.272 117.887 43.29 ;
     RECT  117.72 37.944 117.923 38.079 ;
     RECT  117.72 40.536 118.355 41.004 ;
     RECT  118.579 35.244 118.615 35.262 ;
     RECT  118.615 35.244 118.759 35.334 ;
     RECT  117.72 36.09 118.939 36.378 ;
     RECT  117.72 2.151 118.975 34.344 ;
     RECT  118.759 35.136 118.975 35.334 ;
     RECT  118.939 36.09 118.975 37.08 ;
     RECT  117.923 37.944 118.975 38.034 ;
     RECT  118.975 2.151 119.011 35.334 ;
     RECT  118.975 36.09 119.011 38.034 ;
     RECT  117.72 46.818 119.119 74.61 ;
     RECT  119.119 46.656 119.155 74.61 ;
     RECT  117.72 42.336 119.443 42.354 ;
     RECT  66.631 76.626 119.443 76.644 ;
     RECT  118.355 40.536 119.515 40.554 ;
     RECT  119.515 40.302 119.551 40.554 ;
     RECT  119.407 43.542 119.659 43.56 ;
     RECT  117.72 44.388 119.659 45.324 ;
     RECT  119.011 2.151 119.731 38.034 ;
     RECT  119.731 2.151 119.767 38.502 ;
     RECT  119.443 42.336 119.767 42.624 ;
     RECT  119.767 2.151 119.772 38.736 ;
     RECT  119.551 40.266 119.772 41.238 ;
     RECT  119.767 42.192 119.772 42.624 ;
     RECT  119.659 43.542 119.772 45.324 ;
     RECT  119.155 46.35 119.772 74.61 ;
     RECT  119.443 76.32 119.772 76.644 ;
     RECT  116.339 77.751 119.772 110.169 ;
     RECT  42.971 0.846 120.839 0.864 ;
     RECT  119.772 2.151 138.24 110.169 ;
     RECT  138.24 36.756 139.091 37.854 ;
     RECT  139.091 36.756 139.631 37.044 ;
     RECT  139.091 37.836 139.631 37.854 ;
     RECT  139.631 36.981 140.351 36.999 ;
    LAYER M3 ;
     RECT  17.64 0.031 17.658 0.091 ;
     RECT  24.48 0.043 24.498 0.091 ;
     RECT  26.784 0.043 26.802 0.091 ;
     RECT  32.184 0.043 32.202 0.091 ;
     RECT  33.552 0.067 33.57 0.091 ;
     RECT  16.2 0.091 17.91 0.103 ;
     RECT  33.552 0.091 34.146 0.125 ;
     RECT  95.76 0.031 95.778 0.125 ;
     RECT  1.944 0.067 1.962 0.139 ;
     RECT  2.736 0.091 2.754 0.139 ;
     RECT  16.2 0.103 18.234 0.139 ;
     RECT  21.708 0.091 21.726 0.139 ;
     RECT  22.824 0.043 22.842 0.139 ;
     RECT  31.68 0.091 32.31 0.139 ;
     RECT  40.068 0.091 40.482 0.139 ;
     RECT  92.988 0.091 94.554 0.139 ;
     RECT  120.456 0.091 120.474 0.139 ;
     RECT  121.788 0.091 122.31 0.139 ;
     RECT  20.7 0.043 20.718 0.173 ;
     RECT  26.028 0.091 26.802 0.173 ;
     RECT  15.228 0.091 15.246 0.175 ;
     RECT  16.2 0.139 18.27 0.175 ;
     RECT  15.228 0.175 18.27 0.187 ;
     RECT  29.88 0.091 30.186 0.187 ;
     RECT  37.476 0.091 37.494 0.187 ;
     RECT  8.748 0.091 8.91 0.269 ;
     RECT  120.456 0.139 122.31 0.269 ;
     RECT  20.772 0.235 20.898 0.283 ;
     RECT  21.708 0.139 22.842 0.283 ;
     RECT  29.808 0.187 30.186 0.283 ;
     RECT  44.46 0.283 44.478 0.331 ;
     RECT  20.772 0.283 22.914 0.365 ;
     RECT  29.088 0.283 30.186 0.365 ;
     RECT  31.248 0.139 32.31 0.365 ;
     RECT  44.46 0.331 44.802 0.379 ;
     RECT  26.028 0.173 26.73 0.427 ;
     RECT  125.46 0.091 125.478 0.427 ;
     RECT  42.84 0.283 42.858 0.475 ;
     RECT  124.776 0.427 125.478 0.475 ;
     RECT  29.088 0.365 30.042 0.52 ;
     RECT  13.5 0.091 13.518 0.523 ;
     RECT  21.204 0.365 22.914 0.523 ;
     RECT  24.48 0.091 24.678 0.523 ;
     RECT  25.488 0.427 26.73 0.523 ;
     RECT  36.18 0.091 36.198 0.523 ;
     RECT  37.476 0.187 37.53 0.523 ;
     RECT  92.988 0.139 94.626 0.523 ;
     RECT  124.776 0.475 126.09 0.523 ;
     RECT  28.656 0.52 30.042 0.557 ;
     RECT  33.084 0.427 33.102 0.557 ;
     RECT  90.648 0.427 90.666 0.557 ;
     RECT  10.152 0.091 10.17 0.571 ;
     RECT  15.228 0.187 18.954 0.571 ;
     RECT  21.204 0.523 22.986 0.571 ;
     RECT  24.48 0.523 26.73 0.571 ;
     RECT  34.956 0.523 36.198 0.571 ;
     RECT  36.936 0.523 37.782 0.571 ;
     RECT  92.988 0.523 94.914 0.571 ;
     RECT  3.888 0.571 3.906 0.619 ;
     RECT  13.356 0.523 13.518 0.619 ;
     RECT  120.456 0.269 120.834 0.869 ;
     RECT  11.304 0.091 11.322 1.051 ;
     RECT  21.204 0.571 26.73 1.051 ;
     RECT  124.236 0.523 126.09 1.051 ;
     RECT  1.944 0.139 2.754 1.099 ;
     RECT  12.96 0.619 13.518 1.099 ;
     RECT  27.72 0.571 27.738 1.099 ;
     RECT  121.572 0.269 122.31 1.099 ;
     RECT  123.264 0.091 123.282 1.099 ;
     RECT  124.164 1.051 126.09 1.099 ;
     RECT  1.656 1.099 2.754 1.147 ;
     RECT  3.888 0.619 4.122 1.147 ;
     RECT  4.968 0.571 4.986 1.147 ;
     RECT  8.748 0.269 8.766 1.147 ;
     RECT  9.504 0.571 10.17 1.147 ;
     RECT  11.304 1.051 11.574 1.147 ;
     RECT  12.816 1.099 13.518 1.147 ;
     RECT  15.228 0.571 18.99 1.147 ;
     RECT  21.204 1.051 26.91 1.147 ;
     RECT  27.72 1.099 27.99 1.147 ;
     RECT  28.764 0.557 30.042 1.147 ;
     RECT  31.68 0.365 32.31 1.147 ;
     RECT  118.26 0.571 118.278 1.147 ;
     RECT  3.888 1.147 4.986 1.195 ;
     RECT  12.816 1.147 13.734 1.195 ;
     RECT  14.544 1.147 18.99 1.195 ;
     RECT  118.26 1.147 118.566 1.195 ;
     RECT  3.888 1.195 5.526 1.291 ;
     RECT  42.192 0.475 42.966 1.445 ;
     RECT  42.84 1.445 42.966 1.481 ;
     RECT  44.46 0.379 45.306 1.627 ;
     RECT  46.152 0.283 46.35 1.627 ;
     RECT  121.572 1.099 126.09 1.627 ;
     RECT  92.88 0.571 95.13 1.675 ;
     RECT  3.888 1.291 5.67 1.723 ;
     RECT  6.48 1.147 6.498 1.723 ;
     RECT  7.956 1.147 11.718 1.723 ;
     RECT  19.764 0.427 19.782 1.723 ;
     RECT  92.88 1.675 95.166 1.723 ;
     RECT  117.144 1.147 117.162 1.723 ;
     RECT  118.26 1.195 118.854 1.723 ;
     RECT  12.816 1.195 18.99 1.771 ;
     RECT  19.764 1.723 19.998 1.771 ;
     RECT  116.784 1.723 117.162 1.771 ;
     RECT  7.776 1.723 11.718 1.819 ;
     RECT  118.188 1.723 119.502 1.819 ;
     RECT  120.456 0.869 120.474 1.819 ;
     RECT  3.888 1.723 6.498 1.867 ;
     RECT  7.776 1.819 11.79 1.867 ;
     RECT  12.816 1.771 19.998 1.867 ;
     RECT  116.784 1.771 117.45 1.867 ;
     RECT  118.188 1.819 120.474 1.867 ;
     RECT  34.128 0.125 34.146 2.011 ;
     RECT  121.572 1.627 126.306 2.011 ;
     RECT  127.116 0.523 127.134 2.011 ;
     RECT  7.776 1.867 19.998 2.059 ;
     RECT  3.888 1.867 6.642 2.101 ;
     RECT  34.056 2.011 34.146 2.143 ;
     RECT  34.956 0.571 38.61 2.143 ;
     RECT  121.572 2.011 127.134 2.143 ;
     RECT  3.888 2.101 6.678 2.191 ;
     RECT  7.776 2.059 20.25 2.191 ;
     RECT  21.204 1.147 27.99 2.191 ;
     RECT  28.764 1.147 30.186 2.191 ;
     RECT  31.212 1.147 32.31 2.191 ;
     RECT  34.056 2.143 38.61 2.191 ;
     RECT  1.656 1.147 2.862 2.263 ;
     RECT  3.6 2.191 30.186 2.263 ;
     RECT  31.212 2.191 33.21 2.263 ;
     RECT  1.656 2.263 30.186 2.335 ;
     RECT  30.96 2.263 33.21 2.335 ;
     RECT  34.056 2.191 39.006 2.371 ;
     RECT  51.015 2.143 51.105 2.413 ;
     RECT  56.415 2.143 56.505 2.413 ;
     RECT  61.815 2.143 61.905 2.413 ;
     RECT  67.215 2.143 67.305 2.413 ;
     RECT  72.615 2.143 72.705 2.413 ;
     RECT  78.015 2.143 78.105 2.413 ;
     RECT  83.415 2.143 83.505 2.413 ;
     RECT  88.815 2.143 88.905 2.413 ;
     RECT  99.615 2.143 99.705 2.413 ;
     RECT  105.015 2.143 105.105 2.413 ;
     RECT  110.415 2.143 110.505 2.413 ;
     RECT  115.815 2.143 115.905 2.413 ;
     RECT  116.784 1.867 120.474 2.413 ;
     RECT  132.015 2.143 132.105 2.413 ;
     RECT  137.415 2.143 137.505 2.413 ;
     RECT  115.815 2.413 120.474 2.461 ;
     RECT  121.215 2.143 127.134 2.461 ;
     RECT  92.88 1.723 95.346 2.489 ;
     RECT  42.84 1.481 42.858 2.533 ;
     RECT  1.656 2.335 33.21 2.641 ;
     RECT  33.948 2.371 39.006 2.641 ;
     RECT  92.988 2.489 95.346 2.641 ;
     RECT  42.768 2.533 42.858 2.669 ;
     RECT  44.46 1.627 46.35 2.795 ;
     RECT  92.988 2.641 95.526 2.795 ;
     RECT  1.656 2.641 39.006 2.875 ;
     RECT  44.64 2.795 46.35 2.911 ;
     RECT  92.988 2.795 93.474 3.029 ;
     RECT  44.64 2.911 46.386 3.065 ;
     RECT  115.815 2.461 127.134 3.065 ;
     RECT  1.152 2.875 39.006 3.209 ;
     RECT  94.215 2.795 95.526 3.335 ;
     RECT  116.892 3.065 127.134 3.335 ;
     RECT  94.215 3.335 95.346 3.371 ;
     RECT  95.22 3.371 95.346 3.443 ;
     RECT  44.748 3.065 46.386 3.713 ;
     RECT  1.548 3.209 39.006 3.911 ;
     RECT  44.748 3.713 46.35 3.955 ;
     RECT  40.068 0.139 40.59 3.965 ;
     RECT  42.84 2.669 42.858 3.965 ;
     RECT  44.46 3.955 46.35 4.081 ;
     RECT  43.884 4.081 46.35 4.181 ;
     RECT  43.884 4.181 46.242 4.289 ;
     RECT  1.548 3.911 38.826 4.721 ;
     RECT  1.548 4.721 38.79 4.919 ;
     RECT  1.548 4.919 38.682 5.131 ;
     RECT  43.884 4.289 43.902 5.261 ;
     RECT  1.044 5.131 38.682 5.369 ;
     RECT  1.548 5.369 38.682 6.691 ;
     RECT  44.748 4.289 46.242 6.691 ;
     RECT  40.215 3.965 40.497 6.781 ;
     RECT  44.028 6.691 46.242 6.845 ;
     RECT  1.548 6.691 39.042 6.952 ;
     RECT  44.748 6.845 46.242 6.989 ;
     RECT  41.868 2.731 41.886 7.259 ;
     RECT  1.548 6.952 39.15 7.501 ;
     RECT  40.215 6.781 41.058 7.799 ;
     RECT  1.548 7.501 39.186 7.897 ;
     RECT  1.548 7.897 39.366 7.969 ;
     RECT  40.215 7.799 40.497 7.969 ;
     RECT  45.072 6.989 46.242 8.195 ;
     RECT  45.18 8.195 46.242 8.303 ;
     RECT  45.18 8.303 45.897 8.609 ;
     RECT  1.548 7.969 40.497 10.193 ;
     RECT  1.548 10.193 39.474 10.319 ;
     RECT  1.872 10.319 39.402 11.165 ;
     RECT  1.872 11.165 39.258 11.237 ;
     RECT  1.872 11.237 39.078 12.245 ;
     RECT  1.872 12.245 38.97 12.551 ;
     RECT  1.872 12.551 38.286 12.749 ;
     RECT  1.872 12.749 38.178 12.785 ;
     RECT  1.872 12.785 37.854 13.085 ;
     RECT  1.872 13.085 37.746 13.091 ;
     RECT  1.944 13.091 37.746 13.829 ;
     RECT  1.944 13.829 37.674 14.405 ;
     RECT  40.215 10.193 40.497 14.521 ;
     RECT  40.104 14.521 40.497 14.573 ;
     RECT  38.772 15.547 38.79 16.157 ;
     RECT  1.944 14.405 35.946 16.973 ;
     RECT  32.22 16.973 35.946 18.185 ;
     RECT  32.256 18.185 35.946 18.599 ;
     RECT  38.772 19.003 38.79 19.133 ;
     RECT  1.944 16.973 31.482 19.139 ;
     RECT  0.288 19.345 0.306 19.435 ;
     RECT  0.288 19.435 0.378 19.531 ;
     RECT  0.18 19.531 0.378 19.565 ;
     RECT  1.944 19.139 30.186 19.627 ;
     RECT  1.404 19.627 30.186 19.921 ;
     RECT  0.18 19.565 0.306 20.107 ;
     RECT  1.404 19.921 30.366 20.147 ;
     RECT  0.144 20.107 0.306 20.155 ;
     RECT  0.108 20.155 0.306 20.237 ;
     RECT  0.108 20.237 0.162 20.345 ;
     RECT  1.404 20.147 30.33 20.381 ;
     RECT  1.404 20.381 30.078 20.779 ;
     RECT  1.152 20.779 30.078 21.731 ;
     RECT  0.108 20.345 0.126 21.739 ;
     RECT  0.108 21.739 0.162 22.027 ;
     RECT  0.108 22.027 0.198 22.315 ;
     RECT  1.152 21.731 27.414 22.315 ;
     RECT  0.108 22.315 27.414 22.621 ;
     RECT  32.868 18.599 35.946 23.069 ;
     RECT  0.072 22.621 27.414 24.197 ;
     RECT  32.868 23.069 35.55 24.989 ;
     RECT  32.868 24.989 33.642 25.037 ;
     RECT  33.624 25.037 33.642 25.349 ;
     RECT  0.144 24.197 27.414 25.636 ;
     RECT  0.108 25.636 27.414 26.285 ;
     RECT  0.144 26.285 27.414 26.555 ;
     RECT  36.936 14.405 37.674 26.627 ;
     RECT  41.76 26.635 41.778 26.789 ;
     RECT  41.436 26.905 41.634 27.031 ;
     RECT  0.144 26.555 1.17 27.095 ;
     RECT  41.364 27.031 41.634 27.101 ;
     RECT  1.944 26.555 27.414 27.167 ;
     RECT  41.436 27.101 41.634 27.167 ;
     RECT  0.144 27.095 0.594 27.203 ;
     RECT  0.144 27.203 0.522 27.211 ;
     RECT  0.108 27.211 0.522 27.239 ;
     RECT  34.632 24.989 35.55 27.869 ;
     RECT  0.108 27.239 0.162 27.905 ;
     RECT  34.632 27.869 35.478 28.253 ;
     RECT  0.144 27.905 0.162 28.397 ;
     RECT  36.936 26.627 36.954 28.787 ;
     RECT  1.944 27.167 24.642 28.957 ;
     RECT  25.38 27.167 27.414 28.985 ;
     RECT  1.728 28.957 24.642 29.165 ;
     RECT  0.108 28.795 0.126 29.899 ;
     RECT  1.944 29.165 24.642 30.307 ;
     RECT  25.38 28.985 27.198 30.307 ;
     RECT  0.108 29.899 0.846 30.571 ;
     RECT  0.108 30.571 1.17 30.811 ;
     RECT  1.944 30.307 27.198 30.811 ;
     RECT  34.815 28.253 35.478 31.351 ;
     RECT  28.296 21.731 30.078 31.495 ;
     RECT  31.14 19.139 31.482 31.495 ;
     RECT  34.416 31.351 35.478 31.495 ;
     RECT  0.108 30.811 27.198 31.661 ;
     RECT  25.272 31.661 27.198 31.709 ;
     RECT  25.272 31.709 25.65 31.721 ;
     RECT  26.496 31.709 27.198 31.867 ;
     RECT  28.296 31.495 31.482 31.867 ;
     RECT  116.892 3.335 117.126 31.891 ;
     RECT  117.864 3.335 127.134 31.891 ;
     RECT  26.496 31.867 31.698 31.919 ;
     RECT  36.288 31.867 36.306 31.919 ;
     RECT  34.092 31.495 35.478 31.927 ;
     RECT  26.496 31.919 31.158 32.099 ;
     RECT  34.092 31.927 36.126 32.099 ;
     RECT  34.092 32.099 35.802 32.147 ;
     RECT  40.215 14.573 40.497 32.147 ;
     RECT  45.615 8.609 45.897 32.147 ;
     RECT  51.015 2.413 51.297 32.147 ;
     RECT  56.415 2.413 56.697 32.147 ;
     RECT  61.815 2.413 62.097 32.147 ;
     RECT  67.215 2.413 67.497 32.147 ;
     RECT  72.615 2.413 72.897 32.147 ;
     RECT  78.015 2.413 78.297 32.147 ;
     RECT  83.415 2.413 83.697 32.147 ;
     RECT  88.815 2.413 89.097 32.147 ;
     RECT  94.215 3.371 94.497 32.147 ;
     RECT  99.615 2.413 99.897 32.147 ;
     RECT  105.015 2.413 105.297 32.147 ;
     RECT  110.415 2.413 110.697 32.147 ;
     RECT  115.815 3.065 116.097 32.147 ;
     RECT  29.088 32.099 31.158 32.189 ;
     RECT  69.228 32.011 69.246 32.189 ;
     RECT  34.092 32.147 35.01 32.225 ;
     RECT  116.892 31.891 127.134 32.225 ;
     RECT  35.784 32.147 35.802 32.237 ;
     RECT  38.196 32.161 38.214 32.269 ;
     RECT  40.215 32.147 40.41 32.296 ;
     RECT  42.156 32.299 42.174 32.305 ;
     RECT  37.872 32.269 38.214 32.333 ;
     RECT  39.996 32.296 40.41 32.333 ;
     RECT  43.776 32.305 44.658 32.341 ;
     RECT  0.108 31.661 24.354 32.369 ;
     RECT  26.496 32.099 28.314 32.369 ;
     RECT  29.415 32.189 31.158 32.369 ;
     RECT  42.156 32.305 42.858 32.369 ;
     RECT  42.192 32.369 42.858 32.381 ;
     RECT  29.415 32.369 30.078 32.417 ;
     RECT  45.615 32.147 45.705 32.417 ;
     RECT  51.015 32.147 51.105 32.417 ;
     RECT  56.415 32.147 56.505 32.417 ;
     RECT  61.815 32.147 61.905 32.417 ;
     RECT  67.215 32.147 67.305 32.417 ;
     RECT  72.615 32.147 72.705 32.417 ;
     RECT  78.015 32.147 78.105 32.417 ;
     RECT  83.415 32.147 83.505 32.417 ;
     RECT  88.815 32.147 88.905 32.417 ;
     RECT  94.215 32.147 94.305 32.417 ;
     RECT  99.615 32.147 99.705 32.417 ;
     RECT  105.015 32.147 105.105 32.417 ;
     RECT  110.415 32.147 110.505 32.417 ;
     RECT  115.815 32.147 115.905 32.417 ;
     RECT  40.104 32.333 40.41 32.429 ;
     RECT  117.468 32.225 127.134 32.429 ;
     RECT  0.108 32.369 24.282 32.459 ;
     RECT  30.888 32.369 31.158 32.459 ;
     RECT  117.54 32.429 127.134 32.459 ;
     RECT  0.108 32.459 24.21 32.477 ;
     RECT  34.2 32.225 35.01 32.477 ;
     RECT  40.104 32.429 40.122 32.477 ;
     RECT  42.192 32.381 42.426 32.477 ;
     RECT  43.776 32.341 44.766 32.477 ;
     RECT  68.94 32.341 68.958 32.477 ;
     RECT  117.756 32.459 127.134 32.701 ;
     RECT  0.108 32.477 23.886 32.765 ;
     RECT  28.296 32.369 28.314 32.813 ;
     RECT  38.196 32.333 38.214 32.837 ;
     RECT  0.108 32.765 0.846 32.909 ;
     RECT  44.208 32.477 44.766 33.179 ;
     RECT  1.944 32.765 23.886 33.341 ;
     RECT  26.496 32.369 27.162 33.341 ;
     RECT  34.2 32.477 34.218 33.341 ;
     RECT  0.576 32.909 0.846 33.377 ;
     RECT  26.496 33.341 26.514 33.389 ;
     RECT  1.944 33.341 23.778 33.485 ;
     RECT  25.272 31.721 25.542 33.539 ;
     RECT  140.364 33.595 140.382 33.643 ;
     RECT  133.992 33.547 134.01 33.655 ;
     RECT  30.06 32.417 30.078 33.725 ;
     RECT  139.644 33.643 140.382 33.773 ;
     RECT  0.576 33.377 0.594 33.845 ;
     RECT  135.396 33.583 135.414 34.159 ;
     RECT  1.944 33.485 23.274 34.56 ;
     RECT  25.272 33.539 25.29 34.56 ;
     RECT  31.14 32.459 31.158 34.56 ;
     RECT  32.868 25.037 32.886 34.56 ;
     RECT  42.192 32.477 42.21 34.56 ;
     RECT  44.208 33.179 44.226 34.56 ;
     RECT  117.756 32.701 127.71 34.56 ;
     RECT  132.015 2.413 132.297 35.041 ;
     RECT  1.944 34.56 127.71 35.069 ;
     RECT  133.992 33.655 134.586 36.391 ;
     RECT  135.396 34.159 135.99 36.391 ;
     RECT  133.992 36.391 135.99 36.517 ;
     RECT  133.848 36.517 135.99 36.545 ;
     RECT  133.848 36.545 135.81 36.605 ;
     RECT  137.415 2.413 137.697 36.625 ;
     RECT  140.256 33.773 140.382 36.653 ;
     RECT  136.764 36.625 137.697 36.661 ;
     RECT  140.256 36.653 140.346 36.715 ;
     RECT  136.692 36.661 137.697 36.751 ;
     RECT  133.848 36.605 135.126 36.779 ;
     RECT  132.015 35.041 132.678 37.003 ;
     RECT  133.848 36.779 134.406 37.003 ;
     RECT  139.608 36.715 140.346 37.004 ;
     RECT  132.015 37.003 134.406 37.037 ;
     RECT  139.608 37.004 140.31 37.037 ;
     RECT  139.608 37.037 140.274 37.133 ;
     RECT  139.608 37.133 139.626 37.195 ;
     RECT  132.015 37.037 134.118 37.319 ;
     RECT  131.076 33.115 131.094 37.387 ;
     RECT  132.015 37.319 132.498 37.387 ;
     RECT  136.692 36.751 137.898 37.399 ;
     RECT  133.344 37.319 133.398 37.427 ;
     RECT  131.076 37.387 132.498 37.429 ;
     RECT  136.656 37.399 137.898 37.471 ;
     RECT  130.932 37.429 132.498 37.472 ;
     RECT  130.932 37.472 132.297 37.589 ;
     RECT  133.344 37.427 133.362 37.589 ;
     RECT  139.068 37.195 139.626 37.589 ;
     RECT  130.932 37.589 130.95 37.613 ;
     RECT  1.944 35.069 127.134 37.625 ;
     RECT  119.304 37.625 127.134 37.741 ;
     RECT  127.872 37.669 127.89 37.741 ;
     RECT  119.304 37.741 127.89 37.859 ;
     RECT  136.656 37.471 137.97 37.859 ;
     RECT  139.608 37.589 139.626 37.859 ;
     RECT  136.8 37.859 137.97 37.895 ;
     RECT  136.8 37.895 137.754 38.129 ;
     RECT  119.448 37.859 127.89 38.749 ;
     RECT  119.448 38.749 128.322 38.785 ;
     RECT  119.448 38.785 128.43 39.019 ;
     RECT  119.448 39.019 128.79 39.091 ;
     RECT  119.448 39.091 129.114 39.289 ;
     RECT  119.448 39.289 129.222 39.793 ;
     RECT  119.448 39.793 129.402 39.835 ;
     RECT  119.448 39.835 129.51 40.063 ;
     RECT  119.448 40.063 129.798 40.325 ;
     RECT  126.288 40.325 129.798 40.945 ;
     RECT  1.944 37.625 118.35 41.009 ;
     RECT  126.288 40.945 130.158 41.143 ;
     RECT  126.288 41.143 130.266 41.909 ;
     RECT  128.664 41.909 130.266 41.953 ;
     RECT  119.448 40.325 125.442 42.151 ;
     RECT  126.288 41.909 127.926 42.151 ;
     RECT  119.448 42.151 127.926 42.629 ;
     RECT  119.556 42.629 127.926 42.755 ;
     RECT  119.556 42.755 127.89 43.537 ;
     RECT  119.412 43.537 127.89 44.339 ;
     RECT  119.412 44.339 127.854 45.265 ;
     RECT  128.664 41.953 130.446 45.265 ;
     RECT  119.412 45.265 130.446 46.345 ;
     RECT  119.16 46.345 130.446 46.651 ;
     RECT  119.124 46.651 130.446 46.781 ;
     RECT  119.124 46.781 124.398 47.357 ;
     RECT  119.196 47.357 124.398 47.549 ;
     RECT  1.944 41.009 118.278 48.856 ;
     RECT  1.944 48.856 118.602 49.531 ;
     RECT  1.944 49.531 118.638 49.891 ;
     RECT  119.376 47.549 124.398 49.891 ;
     RECT  1.944 49.891 124.398 50.999 ;
     RECT  1.944 50.999 118.638 51.233 ;
     RECT  1.944 51.233 118.602 52.285 ;
     RECT  119.376 50.999 124.398 52.285 ;
     RECT  1.944 52.285 124.398 53.597 ;
     RECT  1.944 53.597 118.638 54.409 ;
     RECT  119.376 53.597 124.398 54.409 ;
     RECT  1.944 54.409 124.398 55.247 ;
     RECT  119.124 55.247 124.398 55.901 ;
     RECT  1.944 55.247 118.278 57.109 ;
     RECT  1.944 57.109 118.602 57.145 ;
     RECT  1.944 57.145 118.638 57.181 ;
     RECT  119.376 55.901 124.398 57.181 ;
     RECT  1.944 57.181 124.398 57.947 ;
     RECT  119.124 57.947 124.398 58.205 ;
     RECT  1.944 57.947 118.278 58.801 ;
     RECT  1.944 58.801 118.638 59.431 ;
     RECT  119.376 58.205 124.398 59.431 ;
     RECT  1.944 59.431 124.398 62.879 ;
     RECT  1.944 62.879 118.602 63.509 ;
     RECT  1.944 63.509 118.278 63.581 ;
     RECT  119.376 62.879 124.398 63.787 ;
     RECT  2.415 63.581 118.278 64.435 ;
     RECT  119.124 63.787 124.398 64.435 ;
     RECT  2.415 64.435 124.398 65.507 ;
     RECT  2.415 65.507 118.638 66.361 ;
     RECT  119.376 65.507 124.398 66.361 ;
     RECT  2.415 66.361 124.398 68.369 ;
     RECT  2.415 68.369 118.638 69.151 ;
     RECT  119.376 68.369 124.398 69.151 ;
     RECT  2.415 69.151 124.398 69.359 ;
     RECT  2.415 69.359 118.638 70.303 ;
     RECT  119.376 69.359 124.398 70.303 ;
     RECT  2.415 70.303 124.398 70.601 ;
     RECT  2.415 70.601 118.638 71.761 ;
     RECT  119.376 70.601 124.398 71.761 ;
     RECT  2.415 71.761 124.398 73.337 ;
     RECT  2.415 73.337 118.638 73.409 ;
     RECT  2.415 73.409 118.602 74.345 ;
     RECT  2.415 74.345 118.278 74.615 ;
     RECT  119.376 73.337 124.398 75.425 ;
     RECT  2.415 74.615 117.72 75.624 ;
     RECT  120.42 75.425 124.398 76.199 ;
     RECT  119.376 75.425 119.43 76.315 ;
     RECT  37.62 75.624 38.214 76.363 ;
     RECT  33.876 75.624 34.47 76.411 ;
     RECT  31.932 75.624 32.778 76.459 ;
     RECT  33.876 76.411 34.506 76.459 ;
     RECT  36.792 75.624 36.81 76.603 ;
     RECT  37.62 76.363 38.466 76.603 ;
     RECT  30.852 75.624 31.086 76.699 ;
     RECT  39.492 75.624 39.51 76.699 ;
     RECT  39.492 76.699 39.834 76.747 ;
     RECT  40.572 75.624 40.59 76.747 ;
     RECT  31.932 76.459 34.506 76.775 ;
     RECT  26.496 76.555 26.514 76.783 ;
     RECT  2.415 75.624 23.346 76.891 ;
     RECT  39.492 76.747 40.59 77.017 ;
     RECT  36.792 76.603 38.466 77.161 ;
     RECT  36.504 77.161 38.466 77.323 ;
     RECT  39.492 77.017 41.058 77.512 ;
     RECT  2.415 76.891 23.814 77.515 ;
     RECT  24.768 75.624 24.786 77.515 ;
     RECT  29.664 76.603 29.682 77.515 ;
     RECT  30.456 76.699 31.086 77.515 ;
     RECT  32.184 76.775 34.506 77.515 ;
     RECT  35.352 77.371 35.622 77.515 ;
     RECT  36.504 77.323 38.502 77.515 ;
     RECT  39.492 77.512 41.31 77.515 ;
     RECT  114.768 77.515 114.786 77.611 ;
     RECT  114.624 77.611 114.786 77.659 ;
     RECT  115.74 76.939 115.758 77.659 ;
     RECT  2.415 77.515 24.786 77.701 ;
     RECT  29.664 77.515 31.086 77.701 ;
     RECT  44.964 76.363 44.982 77.701 ;
     RECT  44.208 77.665 44.226 77.707 ;
     RECT  44.964 77.701 45.09 77.743 ;
     RECT  66.636 76.621 66.654 77.743 ;
     RECT  109.692 77.701 109.71 77.743 ;
     RECT  68.832 77.611 68.85 77.791 ;
     RECT  102.096 77.563 102.114 77.791 ;
     RECT  109.692 77.743 110.505 77.791 ;
     RECT  44.1 77.707 44.226 77.819 ;
     RECT  68.832 77.791 69.138 77.819 ;
     RECT  109.692 77.791 110.61 77.819 ;
     RECT  114.552 77.659 114.786 77.819 ;
     RECT  69.12 77.819 69.138 77.837 ;
     RECT  102.096 77.791 102.402 77.837 ;
     RECT  114.624 77.819 114.786 77.837 ;
     RECT  44.1 77.819 44.118 77.855 ;
     RECT  44.964 77.743 45.705 77.855 ;
     RECT  109.908 77.819 110.61 77.885 ;
     RECT  115.74 77.659 116.442 77.899 ;
     RECT  32.184 77.515 38.502 77.947 ;
     RECT  39.492 77.515 41.706 77.947 ;
     RECT  26.496 76.783 26.874 77.971 ;
     RECT  29.304 77.701 31.086 77.971 ;
     RECT  45.615 77.855 45.705 78.013 ;
     RECT  51.015 77.743 51.105 78.013 ;
     RECT  56.415 77.743 56.505 78.013 ;
     RECT  61.815 77.743 61.905 78.013 ;
     RECT  66.636 77.743 67.305 78.013 ;
     RECT  72.615 77.743 72.705 78.013 ;
     RECT  78.015 77.743 78.105 78.013 ;
     RECT  83.415 77.743 83.505 78.013 ;
     RECT  88.815 77.743 88.905 78.013 ;
     RECT  94.215 77.743 94.305 78.013 ;
     RECT  99.615 77.743 99.705 78.013 ;
     RECT  105.015 77.743 105.105 78.013 ;
     RECT  110.415 77.885 110.61 78.013 ;
     RECT  26.496 77.971 26.946 78.061 ;
     RECT  115.74 77.899 116.55 78.088 ;
     RECT  29.088 77.971 31.086 78.089 ;
     RECT  32.184 77.947 41.706 78.091 ;
     RECT  26.496 78.061 27.378 78.125 ;
     RECT  32.184 78.091 42.066 78.169 ;
     RECT  27.36 78.125 27.378 78.205 ;
     RECT  27.36 78.205 27.45 78.233 ;
     RECT  27.432 78.233 27.45 78.359 ;
     RECT  115.092 78.088 116.55 78.359 ;
     RECT  32.184 78.169 42.786 78.395 ;
     RECT  40.215 78.395 42.786 78.403 ;
     RECT  2.415 77.701 25.002 78.427 ;
     RECT  40.215 78.403 42.822 78.439 ;
     RECT  117.504 78.133 117.522 78.475 ;
     RECT  101.988 78.511 102.006 78.557 ;
     RECT  40.215 78.439 43.542 78.629 ;
     RECT  66.636 78.013 67.497 78.629 ;
     RECT  45.615 78.013 45.897 78.673 ;
     RECT  56.415 78.013 56.697 78.763 ;
     RECT  78.015 78.013 78.297 78.763 ;
     RECT  88.815 78.013 89.097 78.763 ;
     RECT  99.615 78.013 99.897 78.763 ;
     RECT  110.415 78.013 110.697 78.763 ;
     RECT  40.215 78.629 43.506 78.773 ;
     RECT  29.088 78.089 29.697 78.809 ;
     RECT  56.304 78.763 56.697 78.809 ;
     RECT  67.104 78.629 67.497 78.809 ;
     RECT  77.904 78.763 78.297 78.809 ;
     RECT  88.704 78.763 89.097 78.809 ;
     RECT  99.504 78.763 99.897 78.809 ;
     RECT  110.304 78.763 110.697 78.809 ;
     RECT  41.436 78.773 41.85 78.899 ;
     RECT  115.092 78.359 116.262 78.899 ;
     RECT  2.415 78.427 25.182 78.955 ;
     RECT  115.272 78.899 116.262 79.043 ;
     RECT  41.616 78.899 41.85 79.169 ;
     RECT  42.588 78.773 43.506 79.169 ;
     RECT  115.344 79.043 116.262 79.169 ;
     RECT  2.415 78.955 25.506 79.229 ;
     RECT  41.652 79.169 41.85 79.753 ;
     RECT  42.588 79.169 42.606 79.753 ;
     RECT  44.928 78.673 45.897 79.753 ;
     RECT  26.496 78.125 26.514 81.307 ;
     RECT  26.496 81.307 26.802 81.739 ;
     RECT  26.496 81.739 26.91 81.917 ;
     RECT  26.496 81.917 26.802 82.013 ;
     RECT  2.415 79.229 24.786 83.261 ;
     RECT  44.784 79.753 45.897 83.323 ;
     RECT  44.784 83.323 45.99 83.357 ;
     RECT  40.215 78.773 40.497 83.497 ;
     RECT  45.615 83.357 45.99 83.501 ;
     RECT  32.184 78.395 39.114 83.525 ;
     RECT  114.588 83.467 114.606 83.597 ;
     RECT  41.652 79.753 42.606 84.613 ;
     RECT  26.496 82.013 26.514 85.243 ;
     RECT  26.496 85.243 26.802 85.421 ;
     RECT  35.82 83.525 39.114 86.369 ;
     RECT  39.024 86.369 39.114 88.051 ;
     RECT  40.215 83.497 40.662 88.051 ;
     RECT  43.488 79.169 43.506 89.789 ;
     RECT  26.496 85.421 26.514 90.589 ;
     RECT  30.456 78.089 31.086 94.901 ;
     RECT  26.28 90.589 26.514 99.121 ;
     RECT  6.912 83.261 24.786 99.437 ;
     RECT  32.184 83.525 35.097 100.607 ;
     RECT  117.036 78.475 117.702 100.925 ;
     RECT  44.784 83.357 44.802 101.489 ;
     RECT  65.952 78.637 65.97 101.741 ;
     RECT  2.415 83.261 6.174 102.029 ;
     RECT  35.82 86.369 37.926 104.017 ;
     RECT  39.024 88.051 40.662 104.017 ;
     RECT  6.912 99.437 18.897 104.045 ;
     RECT  30.456 94.901 31.05 104.045 ;
     RECT  35.82 104.017 40.662 106.321 ;
     RECT  41.4 84.613 42.606 106.321 ;
     RECT  26.28 99.121 26.802 106.591 ;
     RECT  25.74 106.591 26.802 106.745 ;
     RECT  35.82 106.321 42.606 106.843 ;
     RECT  35.82 106.843 42.786 107.021 ;
     RECT  117.036 100.925 117.054 107.789 ;
     RECT  32.184 100.607 32.778 107.825 ;
     RECT  25.848 106.745 26.802 108.211 ;
     RECT  6.912 104.045 17.046 108.221 ;
     RECT  32.76 107.825 32.778 108.239 ;
     RECT  33.876 100.607 35.097 108.301 ;
     RECT  35.82 107.021 42.606 108.301 ;
     RECT  25.848 108.211 27.27 108.751 ;
     RECT  19.764 99.437 24.786 108.905 ;
     RECT  31.032 104.045 31.05 108.913 ;
     RECT  33.876 108.301 42.606 109.003 ;
     RECT  33.624 109.003 42.606 109.111 ;
     RECT  15.876 108.221 17.046 109.175 ;
     RECT  33.624 109.111 42.642 109.175 ;
     RECT  33.876 109.175 42.642 109.211 ;
     RECT  34.452 109.211 42.642 109.219 ;
     RECT  30.78 108.913 31.05 109.247 ;
     RECT  34.452 109.219 43.038 109.255 ;
     RECT  34.452 109.255 43.218 109.291 ;
     RECT  17.784 104.045 18.897 109.387 ;
     RECT  19.764 108.905 24.297 109.387 ;
     RECT  30.852 109.247 31.05 109.409 ;
     RECT  16.128 109.175 17.046 109.435 ;
     RECT  17.784 109.387 24.297 109.435 ;
     RECT  16.128 109.435 24.297 109.445 ;
     RECT  25.848 108.751 27.954 109.561 ;
     RECT  6.912 108.221 15.138 109.687 ;
     RECT  16.128 109.445 18.99 109.715 ;
     RECT  25.236 109.561 27.954 109.715 ;
     RECT  34.452 109.291 43.722 109.751 ;
     RECT  25.524 109.715 27.954 109.787 ;
     RECT  34.776 109.751 43.722 109.787 ;
     RECT  37.188 109.787 43.722 109.831 ;
     RECT  19.8 109.445 24.297 109.907 ;
     RECT  29.415 78.809 29.697 109.907 ;
     RECT  45.615 83.501 45.897 109.907 ;
     RECT  51.015 78.013 51.297 109.907 ;
     RECT  56.415 78.809 56.697 109.907 ;
     RECT  61.815 78.013 62.097 109.907 ;
     RECT  67.215 78.809 67.497 109.907 ;
     RECT  72.615 78.013 72.897 109.907 ;
     RECT  78.015 78.809 78.297 109.907 ;
     RECT  83.415 78.013 83.697 109.907 ;
     RECT  88.815 78.809 89.097 109.907 ;
     RECT  94.215 78.013 94.497 109.907 ;
     RECT  99.615 78.809 99.897 109.907 ;
     RECT  105.015 78.013 105.297 109.907 ;
     RECT  110.415 78.809 110.697 109.907 ;
     RECT  115.815 79.169 116.097 109.907 ;
     RECT  120.492 76.199 124.398 109.907 ;
     RECT  132.015 37.589 132.297 109.907 ;
     RECT  137.415 38.129 137.697 109.907 ;
     RECT  37.188 109.831 43.83 109.949 ;
     RECT  17.784 109.715 18.99 109.985 ;
     RECT  34.776 109.787 36.342 109.985 ;
     RECT  37.188 109.949 43.29 109.985 ;
     RECT  25.848 109.787 27.954 110.155 ;
     RECT  2.415 102.029 5.778 110.177 ;
     RECT  6.912 109.687 15.318 110.177 ;
     RECT  17.784 109.985 18.705 110.177 ;
     RECT  29.415 109.907 29.505 110.177 ;
     RECT  34.815 109.985 36.342 110.177 ;
     RECT  45.615 109.907 45.705 110.177 ;
     RECT  51.015 109.907 51.105 110.177 ;
     RECT  56.415 109.907 56.505 110.177 ;
     RECT  61.815 109.907 61.905 110.177 ;
     RECT  67.215 109.907 67.305 110.177 ;
     RECT  72.615 109.907 72.705 110.177 ;
     RECT  78.015 109.907 78.105 110.177 ;
     RECT  83.415 109.907 83.505 110.177 ;
     RECT  88.815 109.907 88.905 110.177 ;
     RECT  94.215 109.907 94.305 110.177 ;
     RECT  99.615 109.907 99.705 110.177 ;
     RECT  105.015 109.907 105.105 110.177 ;
     RECT  110.415 109.907 110.505 110.177 ;
     RECT  115.815 109.907 115.905 110.177 ;
     RECT  120.492 109.907 121.305 110.177 ;
     RECT  132.015 109.907 132.105 110.177 ;
     RECT  137.415 109.907 137.505 110.177 ;
     RECT  31.032 109.409 31.05 110.203 ;
     RECT  19.8 109.907 24.21 110.237 ;
     RECT  30.924 110.203 31.05 110.299 ;
     RECT  30.816 110.299 31.05 110.335 ;
     RECT  30.816 110.335 31.122 110.363 ;
     RECT  37.296 109.985 43.29 110.381 ;
     RECT  25.848 110.155 28.314 110.429 ;
     RECT  25.848 110.429 28.206 110.525 ;
     RECT  6.912 110.177 7.362 110.573 ;
     RECT  31.104 110.363 31.122 110.573 ;
     RECT  37.296 110.381 42.966 110.621 ;
     RECT  17.784 110.177 18.162 110.939 ;
     RECT  34.92 110.177 36.342 111.001 ;
     RECT  25.848 110.525 27.954 111.137 ;
     RECT  25.848 111.137 27.27 111.197 ;
     RECT  120.492 110.177 120.798 111.197 ;
     RECT  120.492 111.197 120.726 111.245 ;
     RECT  37.296 110.621 42.606 111.437 ;
     RECT  8.532 110.177 15.318 111.677 ;
     RECT  16.128 109.715 17.046 111.677 ;
     RECT  7.164 110.573 7.362 111.685 ;
     RECT  125.136 46.781 127.962 111.691 ;
     RECT  128.988 46.781 130.446 111.691 ;
     RECT  2.556 110.177 5.778 111.725 ;
     RECT  13.86 111.677 15.318 111.725 ;
     RECT  24.264 111.109 24.282 111.725 ;
     RECT  120.492 111.245 120.69 111.725 ;
     RECT  7.164 111.685 7.434 111.739 ;
     RECT  16.488 111.677 17.046 111.739 ;
     RECT  17.784 110.939 17.802 111.739 ;
     RECT  122.076 109.907 124.398 111.739 ;
     RECT  125.136 111.691 130.446 111.739 ;
     RECT  2.556 111.725 5.454 111.773 ;
     RECT  13.896 111.725 15.318 111.773 ;
     RECT  16.488 111.739 18.378 111.773 ;
     RECT  33.084 110.839 33.102 111.773 ;
     RECT  37.296 111.437 42.354 111.773 ;
     RECT  43.344 111.415 43.362 111.773 ;
     RECT  46.188 111.451 46.206 111.773 ;
     RECT  122.076 111.739 130.446 111.773 ;
     RECT  16.632 111.773 18.378 111.787 ;
     RECT  119.376 76.315 119.466 111.787 ;
     RECT  120.42 111.739 120.438 111.787 ;
     RECT  34.776 111.001 36.342 111.821 ;
     RECT  37.296 111.773 38.934 111.821 ;
     RECT  39.672 111.773 40.806 111.821 ;
     RECT  16.632 111.787 18.702 111.869 ;
     RECT  37.296 111.821 37.818 111.869 ;
     RECT  39.672 111.821 39.69 111.869 ;
     RECT  122.076 111.773 126.522 111.869 ;
     RECT  127.26 111.773 130.446 111.869 ;
     RECT  6.516 111.739 7.434 111.883 ;
     RECT  6.516 111.883 7.686 111.917 ;
     RECT  19.8 110.237 23.31 111.917 ;
     RECT  38.844 111.821 38.934 111.917 ;
     RECT  122.076 111.869 125.334 111.917 ;
     RECT  6.516 111.917 6.534 111.931 ;
     RECT  16.992 111.869 18.702 111.931 ;
     RECT  19.8 111.917 23.094 111.931 ;
     RECT  26.46 111.197 27.27 111.965 ;
     RECT  127.26 111.869 127.962 112.013 ;
     RECT  8.532 111.677 13.014 112.061 ;
     RECT  127.368 112.013 127.962 112.061 ;
     RECT  3.132 111.773 5.454 112.109 ;
     RECT  6.3 111.931 6.534 112.109 ;
     RECT  7.272 111.917 7.686 112.109 ;
     RECT  8.532 112.061 12.834 112.109 ;
     RECT  16.992 111.931 23.094 112.109 ;
     RECT  119.376 111.787 120.438 112.109 ;
     RECT  122.184 111.917 125.334 112.109 ;
     RECT  30.96 111.979 30.978 112.117 ;
     RECT  31.932 110.875 31.95 112.117 ;
     RECT  45.612 112.075 46.026 112.123 ;
     RECT  8.748 112.109 11.826 112.145 ;
     RECT  3.132 112.109 3.942 112.157 ;
     RECT  7.272 112.109 7.29 112.157 ;
     RECT  8.748 112.145 10.566 112.157 ;
     RECT  11.736 112.145 11.826 112.157 ;
     RECT  17.784 112.109 23.094 112.157 ;
     RECT  34.776 111.821 35.766 112.157 ;
     RECT  119.376 112.109 119.466 112.157 ;
     RECT  122.436 112.109 125.334 112.157 ;
     RECT  126.432 111.869 126.522 112.157 ;
     RECT  30.96 112.117 31.95 112.171 ;
     RECT  8.748 112.157 9.954 112.181 ;
     RECT  3.312 112.157 3.942 112.205 ;
     RECT  5.04 112.109 5.454 112.205 ;
     RECT  6.516 112.109 6.534 112.205 ;
     RECT  8.856 112.181 9.954 112.205 ;
     RECT  11.736 112.157 11.754 112.205 ;
     RECT  12.816 112.109 12.834 112.205 ;
     RECT  13.896 111.773 15.21 112.205 ;
     RECT  16.992 112.109 17.01 112.205 ;
     RECT  17.784 112.157 19.098 112.205 ;
     RECT  19.908 112.157 23.094 112.205 ;
     RECT  26.784 111.965 27.27 112.205 ;
     RECT  30.96 112.171 32.598 112.205 ;
     RECT  34.992 112.157 35.766 112.205 ;
     RECT  37.8 111.869 37.818 112.205 ;
     RECT  38.844 111.917 38.862 112.205 ;
     RECT  41.544 111.773 42.354 112.205 ;
     RECT  119.448 112.157 119.466 112.205 ;
     RECT  120.42 112.109 120.438 112.205 ;
     RECT  123.012 112.157 125.334 112.205 ;
     RECT  126.504 112.157 126.522 112.205 ;
     RECT  127.512 112.061 127.962 112.205 ;
     RECT  128.988 111.869 130.446 112.205 ;
     RECT  45.036 112.123 46.026 112.217 ;
     RECT  9.828 112.205 9.954 112.253 ;
     RECT  20.412 112.205 22.734 112.253 ;
     RECT  31.428 112.205 31.446 112.253 ;
     RECT  36.828 112.123 36.846 112.253 ;
     RECT  45.612 112.217 46.026 112.253 ;
     RECT  9.936 112.253 9.954 112.289 ;
     RECT  20.412 112.253 22.122 112.289 ;
     RECT  46.008 112.253 46.026 112.289 ;
     RECT  14.832 112.205 14.85 112.301 ;
     RECT  18.612 112.205 18.63 112.301 ;
     RECT  20.412 112.289 21.078 112.301 ;
     RECT  26.784 112.205 26.802 112.301 ;
     RECT  32.58 112.205 32.598 112.301 ;
     RECT  47.016 101.461 47.034 112.301 ;
     RECT  117.936 112.171 117.954 112.301 ;
    LAYER M4 ;
     RECT  0.06 19.44 0.133 31.656 ;
     RECT  0.133 19.44 0.389 31.992 ;
     RECT  0.709 0.096 0.901 0.12 ;
     RECT  0.805 2.88 1.093 2.904 ;
     RECT  0.989 5.136 1.285 5.16 ;
     RECT  1.285 4.56 1.477 5.16 ;
     RECT  1.189 1.728 1.573 1.752 ;
     RECT  0.901 0.096 1.645 0.168 ;
     RECT  1.573 1.152 1.645 1.752 ;
     RECT  1.645 0.096 1.825 1.752 ;
     RECT  1.093 2.88 1.825 2.952 ;
     RECT  1.477 4.56 2.113 5.784 ;
     RECT  1.601 6.864 2.113 6.888 ;
     RECT  2.113 4.56 2.221 6.888 ;
     RECT  2.221 4.464 2.293 6.888 ;
     RECT  1.825 0.096 2.408 2.952 ;
     RECT  2.293 3.936 2.408 6.888 ;
     RECT  2.053 7.968 2.408 7.992 ;
     RECT  2.221 8.976 2.408 9 ;
     RECT  2.185 10.176 2.408 10.2 ;
     RECT  2.365 15.84 2.408 15.864 ;
     RECT  0.389 19.536 2.408 31.992 ;
     RECT  2.245 43.296 2.408 43.32 ;
     RECT  1.669 62.736 2.408 62.76 ;
     RECT  2.408 0.096 2.437 110.172 ;
     RECT  2.437 0.096 2.512 111.144 ;
     RECT  2.512 111.072 2.533 111.144 ;
     RECT  2.341 112.176 2.533 112.2 ;
     RECT  2.512 0.096 2.704 109.902 ;
     RECT  2.704 0.096 2.765 17.256 ;
     RECT  2.765 0.144 2.867 17.256 ;
     RECT  2.867 1.152 2.873 17.256 ;
     RECT  2.873 1.2 2.915 17.256 ;
     RECT  2.704 52.944 2.915 58.152 ;
     RECT  2.704 59.568 2.915 60.072 ;
     RECT  2.915 52.944 3.011 57.576 ;
     RECT  2.704 18.768 3.107 29.256 ;
     RECT  3.011 52.944 3.161 54.984 ;
     RECT  2.704 30.384 3.197 31.848 ;
     RECT  2.533 111.072 3.233 112.2 ;
     RECT  2.915 1.248 3.341 17.256 ;
     RECT  3.341 11.904 3.449 17.256 ;
     RECT  2.704 43.296 3.593 43.32 ;
     RECT  2.704 44.448 3.685 45.096 ;
     RECT  2.704 46.176 3.685 48.312 ;
     RECT  2.704 35.328 3.697 35.352 ;
     RECT  2.867 0.144 3.779 0.168 ;
     RECT  3.685 44.448 3.781 48.312 ;
     RECT  3.197 31.824 3.805 31.848 ;
     RECT  2.704 32.928 3.805 32.952 ;
     RECT  3.107 19.2 3.827 29.256 ;
     RECT  3.341 1.248 3.877 10.872 ;
     RECT  2.704 50.016 3.913 50.04 ;
     RECT  2.704 51.024 3.913 51.048 ;
     RECT  3.233 111.504 3.953 112.2 ;
     RECT  2.915 60 3.973 60.072 ;
     RECT  3.781 44.448 3.989 48.936 ;
     RECT  3.805 31.824 4.025 32.952 ;
     RECT  3.449 11.952 4.057 17.256 ;
     RECT  3.989 44.688 4.057 48.936 ;
     RECT  3.913 50.016 4.057 51.048 ;
     RECT  3.011 55.968 4.201 55.992 ;
     RECT  3.011 56.976 4.201 57.576 ;
     RECT  3.161 53.568 4.213 54.984 ;
     RECT  3.973 60 4.237 60.216 ;
     RECT  4.057 11.952 4.241 17.304 ;
     RECT  3.827 19.2 4.261 28.824 ;
     RECT  3.953 111.504 4.261 112.152 ;
     RECT  4.261 40.128 4.309 40.152 ;
     RECT  4.201 55.968 4.313 57.576 ;
     RECT  4.261 19.104 4.348 28.824 ;
     RECT  2.704 37.392 4.357 37.416 ;
     RECT  3.197 30.384 4.381 30.648 ;
     RECT  4.241 11.952 4.403 17.16 ;
     RECT  2.704 39.024 4.453 39.048 ;
     RECT  4.309 40.128 4.453 40.92 ;
     RECT  3.697 34.512 4.501 35.352 ;
     RECT  4.261 111.12 4.501 112.152 ;
     RECT  4.213 53.04 4.529 54.984 ;
     RECT  4.057 44.688 4.561 51.048 ;
     RECT  4.501 33.264 4.633 35.352 ;
     RECT  4.357 37.392 4.633 37.608 ;
     RECT  4.348 19.2 4.637 28.824 ;
     RECT  4.237 59.232 4.669 60.216 ;
     RECT  4.381 30.288 4.705 30.648 ;
     RECT  4.025 31.824 4.705 32.28 ;
     RECT  4.705 30.288 4.777 32.28 ;
     RECT  4.313 55.968 4.813 57.384 ;
     RECT  4.705 61.488 4.813 61.512 ;
     RECT  3.877 0.576 4.849 10.872 ;
     RECT  4.403 11.952 4.849 16.536 ;
     RECT  4.813 55.392 4.889 57.384 ;
     RECT  4.669 58.464 4.889 60.216 ;
     RECT  4.813 61.488 4.933 61.56 ;
     RECT  4.501 110.784 4.933 112.152 ;
     RECT  4.849 0.576 4.997 16.536 ;
     RECT  4.561 44.688 5.029 51.912 ;
     RECT  4.273 65.52 5.075 65.544 ;
     RECT  4.777 30.096 5.101 32.28 ;
     RECT  4.633 33.264 5.101 35.4 ;
     RECT  4.889 58.464 5.105 60.072 ;
     RECT  5.029 44.448 5.113 51.912 ;
     RECT  5.101 30.096 5.125 35.4 ;
     RECT  5.125 30.096 5.171 35.496 ;
     RECT  5.113 44.688 5.173 51.912 ;
     RECT  4.529 53.04 5.173 54.264 ;
     RECT  5.105 58.656 5.177 60.072 ;
     RECT  4.933 61.104 5.245 61.56 ;
     RECT  4.637 19.344 5.317 28.824 ;
     RECT  4.453 39.024 5.317 40.92 ;
     RECT  4.981 68.784 5.317 68.808 ;
     RECT  4.633 36.864 5.353 37.608 ;
     RECT  5.171 30.096 5.357 33.72 ;
     RECT  5.173 44.688 5.357 54.264 ;
     RECT  5.357 53.328 5.393 54.264 ;
     RECT  5.317 68.688 5.413 68.808 ;
     RECT  5.357 30.192 5.465 33.72 ;
     RECT  5.393 53.856 5.501 54.264 ;
     RECT  5.245 61.104 5.557 61.608 ;
     RECT  5.557 61.104 5.699 61.704 ;
     RECT  4.997 1.152 5.701 16.536 ;
     RECT  5.465 30.192 5.725 33.288 ;
     RECT  4.933 110.784 5.941 112.2 ;
     RECT  5.125 102 5.989 102.024 ;
     RECT  5.317 19.344 5.996 29.112 ;
     RECT  5.317 38.736 6.037 40.92 ;
     RECT  5.996 18.768 6.083 29.112 ;
     RECT  5.941 110.016 6.083 112.2 ;
     RECT  5.171 34.944 6.085 35.496 ;
     RECT  5.353 36.624 6.085 37.608 ;
     RECT  4.093 43.392 6.145 43.416 ;
     RECT  5.357 44.688 6.145 52.2 ;
     RECT  4.889 55.392 6.185 56.904 ;
     RECT  5.989 101.712 6.185 102.024 ;
     RECT  6.185 55.968 6.361 56.904 ;
     RECT  5.177 58.656 6.361 59.304 ;
     RECT  5.699 61.104 6.365 61.56 ;
     RECT  5.749 66.528 6.469 66.552 ;
     RECT  6.145 43.392 6.505 52.2 ;
     RECT  6.083 110.256 6.545 112.2 ;
     RECT  5.221 64.656 6.565 64.68 ;
     RECT  6.361 58.56 6.613 59.304 ;
     RECT  6.365 61.104 6.613 61.176 ;
     RECT  5.701 1.152 6.649 17.064 ;
     RECT  6.083 19.536 6.685 29.112 ;
     RECT  5.725 30.192 6.685 30.984 ;
     RECT  6.613 58.56 6.7 61.176 ;
     RECT  6.649 1.152 6.709 17.16 ;
     RECT  6.685 19.536 6.721 30.984 ;
     RECT  5.725 32.256 6.721 33.288 ;
     RECT  5.501 53.856 6.721 53.88 ;
     RECT  6.505 43.296 6.757 52.2 ;
     RECT  6.721 53.856 6.757 53.928 ;
     RECT  6.757 53.856 6.829 54.36 ;
     RECT  6.721 19.536 6.865 33.288 ;
     RECT  5.413 67.92 6.901 68.808 ;
     RECT  6.709 1.152 6.937 17.256 ;
     RECT  6.865 19.536 6.973 33.384 ;
     RECT  6.829 53.808 6.973 54.36 ;
     RECT  6.973 19.536 7.081 33.432 ;
     RECT  6.085 34.944 7.081 37.608 ;
     RECT  6.037 38.688 7.081 40.92 ;
     RECT  6.757 42.72 7.081 52.2 ;
     RECT  7.081 19.248 7.225 33.432 ;
     RECT  7.081 34.752 7.225 37.608 ;
     RECT  6.937 1.152 7.261 18.216 ;
     RECT  7.225 19.248 7.261 37.608 ;
     RECT  7.081 38.688 7.333 52.2 ;
     RECT  6.545 110.256 7.381 112.152 ;
     RECT  7.333 38.688 7.405 52.68 ;
     RECT  6.973 53.712 7.405 54.36 ;
     RECT  6.361 55.968 7.573 57.576 ;
     RECT  5.269 0.144 7.669 0.168 ;
     RECT  7.261 1.152 7.669 37.608 ;
     RECT  7.669 0.144 7.808 37.608 ;
     RECT  7.405 38.688 7.808 54.36 ;
     RECT  7.573 55.776 7.808 57.576 ;
     RECT  6.7 58.56 7.808 59.448 ;
     RECT  6.7 60.816 7.808 61.176 ;
     RECT  2.704 62.736 7.808 62.76 ;
     RECT  6.565 64.656 7.808 65.544 ;
     RECT  6.469 66.528 7.808 66.792 ;
     RECT  6.901 67.92 7.808 69.24 ;
     RECT  6.661 70.848 7.808 70.872 ;
     RECT  4.405 72.432 7.808 72.456 ;
     RECT  3.877 77.616 7.808 77.64 ;
     RECT  6.577 83.232 7.808 83.256 ;
     RECT  6.185 101.712 7.808 101.736 ;
     RECT  2.704 106.848 7.808 106.872 ;
     RECT  7.381 109.776 7.808 112.152 ;
     RECT  7.808 0.144 8.101 112.152 ;
     RECT  8.101 0.144 8.104 112.2 ;
     RECT  8.104 35.424 8.273 40.92 ;
     RECT  8.104 94.08 8.381 94.104 ;
     RECT  8.104 0.144 8.677 34.152 ;
     RECT  8.104 55.776 8.921 61.128 ;
     RECT  8.921 55.776 9.059 59.256 ;
     RECT  8.273 35.712 9.109 40.92 ;
     RECT  8.104 43.104 9.133 50.376 ;
     RECT  8.677 0.096 9.137 34.152 ;
     RECT  9.133 42.672 9.169 50.376 ;
     RECT  8.104 51.456 9.169 54.36 ;
     RECT  9.059 55.776 9.173 58.92 ;
     RECT  9.137 3.696 9.209 34.152 ;
     RECT  9.109 35.712 9.251 41.064 ;
     RECT  9.169 42.672 9.277 54.36 ;
     RECT  9.209 3.696 9.281 27.912 ;
     RECT  9.281 3.696 9.289 21.528 ;
     RECT  9.289 3.696 9.395 4.056 ;
     RECT  9.209 29.088 9.404 34.152 ;
     RECT  9.277 42.576 9.425 54.36 ;
     RECT  9.404 29.088 9.443 34.296 ;
     RECT  8.104 65.952 9.493 66.792 ;
     RECT  9.443 29.568 9.529 34.296 ;
     RECT  9.425 43.344 9.589 54.36 ;
     RECT  9.395 3.984 9.635 4.056 ;
     RECT  9.529 29.568 9.677 34.392 ;
     RECT  9.281 22.56 9.683 27.912 ;
     RECT  9.635 3.984 9.731 4.008 ;
     RECT  9.677 34.368 9.781 34.392 ;
     RECT  9.251 35.712 9.781 40.92 ;
     RECT  9.137 0.096 9.785 2.52 ;
     RECT  9.589 43.344 9.785 54.408 ;
     RECT  8.104 109.776 9.817 112.2 ;
     RECT  9.781 34.368 9.965 40.92 ;
     RECT  8.921 60.432 9.997 61.128 ;
     RECT  9.785 54.336 10.021 54.408 ;
     RECT  9.965 34.8 10.073 40.92 ;
     RECT  9.817 109.776 10.117 112.248 ;
     RECT  8.104 64.656 10.141 64.68 ;
     RECT  9.493 65.712 10.141 66.792 ;
     RECT  8.104 72.432 10.165 72.456 ;
     RECT  9.785 0.096 10.181 0.168 ;
     RECT  9.289 5.088 10.268 21.528 ;
     RECT  9.683 22.56 10.268 24.744 ;
     RECT  9.173 55.824 10.321 58.92 ;
     RECT  9.997 59.904 10.321 61.128 ;
     RECT  10.141 64.656 10.403 66.792 ;
     RECT  9.889 42.144 10.429 42.168 ;
     RECT  9.785 43.344 10.429 53.304 ;
     RECT  10.268 5.088 10.433 24.744 ;
     RECT  9.677 29.568 10.465 33.384 ;
     RECT  10.453 3.936 10.501 3.96 ;
     RECT  10.429 42.144 10.547 53.304 ;
     RECT  10.073 34.992 10.565 40.92 ;
     RECT  10.565 34.992 10.573 41.016 ;
     RECT  10.547 42.144 10.573 42.168 ;
     RECT  10.573 34.992 10.577 42.168 ;
     RECT  9.785 1.152 10.604 2.52 ;
     RECT  10.501 3.504 10.604 3.96 ;
     RECT  10.465 29.088 10.613 33.384 ;
     RECT  10.604 1.152 10.691 3.96 ;
     RECT  8.104 108.288 10.691 108.312 ;
     RECT  10.691 3.312 10.693 3.96 ;
     RECT  10.433 5.088 10.693 21.528 ;
     RECT  9.683 26.256 10.717 27.912 ;
     RECT  8.104 62.736 10.741 63.672 ;
     RECT  10.547 43.296 10.825 53.304 ;
     RECT  10.321 55.824 10.825 61.128 ;
     RECT  10.717 25.872 10.829 27.912 ;
     RECT  10.433 22.56 10.861 24.744 ;
     RECT  10.829 25.872 10.861 27.24 ;
     RECT  10.825 43.296 10.861 53.352 ;
     RECT  10.021 54.336 10.861 54.744 ;
     RECT  10.165 72.432 10.981 73.272 ;
     RECT  10.981 72.432 11.029 73.368 ;
     RECT  10.613 29.568 11.113 33.384 ;
     RECT  8.104 77.616 11.125 77.64 ;
     RECT  11.113 29.568 11.173 33.816 ;
     RECT  10.577 34.992 11.173 41.976 ;
     RECT  11.029 72.192 11.173 73.368 ;
     RECT  10.933 74.592 11.173 74.616 ;
     RECT  10.181 0.144 11.249 0.168 ;
     RECT  10.861 43.296 11.293 54.744 ;
     RECT  10.825 55.776 11.293 61.128 ;
     RECT  10.741 62.448 11.317 63.672 ;
     RECT  10.403 64.656 11.317 64.68 ;
     RECT  11.249 0.096 11.333 0.168 ;
     RECT  10.861 22.56 11.405 27.24 ;
     RECT  11.173 72.192 11.461 74.616 ;
     RECT  10.691 1.152 11.545 2.328 ;
     RECT  8.104 68.112 11.653 70.872 ;
     RECT  11.461 71.904 11.653 74.616 ;
     RECT  11.545 1.056 11.701 2.328 ;
     RECT  10.693 3.312 11.701 21.528 ;
     RECT  10.403 65.712 11.701 66.792 ;
     RECT  11.653 68.112 11.701 74.616 ;
     RECT  8.104 106.848 11.749 106.872 ;
     RECT  11.701 1.056 12.049 21.528 ;
     RECT  11.405 22.56 12.049 22.632 ;
     RECT  11.173 29.568 12.157 41.976 ;
     RECT  12.157 29.568 12.337 42.168 ;
     RECT  11.293 43.296 12.337 61.128 ;
     RECT  11.317 62.448 12.421 64.68 ;
     RECT  11.701 65.712 12.421 74.616 ;
     RECT  11.405 23.664 12.481 27.24 ;
     RECT  12.481 23.616 12.517 27.24 ;
     RECT  12.476 28.32 12.517 28.344 ;
     RECT  12.049 1.056 12.563 22.632 ;
     RECT  12.517 23.616 12.757 28.344 ;
     RECT  12.337 29.568 12.757 61.128 ;
     RECT  10.117 109.488 12.757 112.248 ;
     RECT  12.563 1.056 12.949 1.176 ;
     RECT  12.949 0.624 13.189 1.176 ;
     RECT  12.563 2.148 13.208 22.632 ;
     RECT  12.757 23.616 13.208 61.128 ;
     RECT  12.421 62.448 13.208 74.616 ;
     RECT  12.257 76.368 13.208 76.392 ;
     RECT  11.125 77.616 13.208 77.88 ;
     RECT  8.104 101.712 13.208 101.736 ;
     RECT  11.749 106.848 13.208 107.016 ;
     RECT  12.373 108.096 13.208 108.12 ;
     RECT  12.757 109.152 13.208 112.248 ;
     RECT  13.189 0.144 13.285 1.176 ;
     RECT  13.208 2.148 13.312 112.248 ;
     RECT  13.285 0.096 13.427 1.176 ;
     RECT  13.312 2.304 13.504 112.248 ;
     RECT  13.427 0.096 13.529 0.168 ;
     RECT  13.427 1.152 13.573 1.176 ;
     RECT  13.529 0.144 13.667 0.168 ;
     RECT  13.504 26.256 13.955 33.624 ;
     RECT  13.504 34.992 14.147 61.464 ;
     RECT  13.573 1.152 14.389 1.272 ;
     RECT  13.504 2.304 14.389 17.688 ;
     RECT  13.504 19.056 14.497 21.528 ;
     RECT  13.504 22.56 14.497 24.456 ;
     RECT  13.504 77.616 14.581 77.976 ;
     RECT  13.504 83.76 14.645 83.784 ;
     RECT  14.389 1.152 14.677 17.688 ;
     RECT  14.497 19.056 14.677 24.456 ;
     RECT  14.147 42.384 14.677 61.464 ;
     RECT  13.504 62.448 14.677 74.616 ;
     RECT  13.504 106.848 14.677 108.12 ;
     RECT  14.677 1.152 14.789 24.456 ;
     RECT  13.955 26.304 14.821 33.624 ;
     RECT  13.504 109.152 14.821 112.248 ;
     RECT  14.821 0.096 14.869 0.12 ;
     RECT  14.789 1.152 14.869 2.328 ;
     RECT  14.789 3.648 14.917 24.456 ;
     RECT  14.821 26.304 14.969 33.816 ;
     RECT  14.917 3.648 15.037 25.128 ;
     RECT  14.969 26.304 15.037 27.96 ;
     RECT  14.677 106.848 15.205 108.168 ;
     RECT  14.821 109.152 15.205 112.296 ;
     RECT  14.147 34.992 15.253 41.064 ;
     RECT  14.677 42.384 15.253 74.616 ;
     RECT  13.504 76.464 15.349 76.488 ;
     RECT  15.253 34.992 15.509 74.616 ;
     RECT  14.969 28.944 15.685 33.816 ;
     RECT  14.869 0.096 15.877 2.328 ;
     RECT  15.037 3.648 15.973 27.96 ;
     RECT  15.685 28.944 15.973 33.912 ;
     RECT  15.877 0.096 16.069 2.616 ;
     RECT  15.973 3.648 16.069 33.912 ;
     RECT  16.069 0.096 16.115 33.912 ;
     RECT  14.581 77.616 16.477 78.696 ;
     RECT  16.115 3.984 16.513 33.912 ;
     RECT  15.509 35.424 16.625 74.616 ;
     RECT  16.513 3.984 16.693 34.44 ;
     RECT  16.625 35.424 16.693 73.32 ;
     RECT  16.693 3.984 16.697 73.32 ;
     RECT  16.697 27.6 16.733 73.32 ;
     RECT  15.349 76.464 16.789 76.536 ;
     RECT  16.115 0.096 17.161 2.904 ;
     RECT  16.697 3.984 17.161 26.28 ;
     RECT  13.504 104.592 17.161 104.616 ;
     RECT  17.377 93.216 17.521 93.24 ;
     RECT  17.233 86.304 17.557 86.328 ;
     RECT  17.161 0.096 17.953 26.28 ;
     RECT  17.953 0.096 18.037 26.568 ;
     RECT  14.725 95.472 18.097 95.496 ;
     RECT  17.485 84.672 18.277 84.696 ;
     RECT  17.593 82.944 18.325 82.968 ;
     RECT  18.277 84.096 18.325 84.696 ;
     RECT  17.557 85.92 18.325 86.328 ;
     RECT  18.241 88.08 18.325 88.104 ;
     RECT  16.733 27.6 18.373 73.272 ;
     RECT  16.477 77.616 18.565 79.272 ;
     RECT  18.037 0.048 18.608 26.568 ;
     RECT  18.373 27.6 18.608 73.416 ;
     RECT  16.625 74.592 18.608 74.616 ;
     RECT  16.789 75.936 18.608 76.536 ;
     RECT  18.565 77.616 18.608 80.088 ;
     RECT  18.457 81.168 18.608 81.192 ;
     RECT  18.325 82.944 18.608 88.104 ;
     RECT  17.737 90.288 18.608 90.312 ;
     RECT  17.521 93.216 18.608 93.768 ;
     RECT  18.097 95.424 18.608 95.496 ;
     RECT  14.917 96.576 18.608 96.6 ;
     RECT  17.269 100.032 18.608 100.056 ;
     RECT  13.504 101.712 18.608 101.736 ;
     RECT  17.161 104.016 18.608 104.616 ;
     RECT  15.205 106.848 18.608 112.296 ;
     RECT  18.608 0.048 18.641 112.296 ;
     RECT  18.641 0.048 18.904 112.248 ;
     RECT  18.904 0.048 19.253 3.72 ;
     RECT  19.253 0.048 19.289 3.624 ;
     RECT  18.904 91.44 19.325 93.768 ;
     RECT  18.904 4.8 19.909 73.272 ;
     RECT  18.904 74.448 19.909 86.904 ;
     RECT  19.909 4.8 20.045 86.904 ;
     RECT  20.045 26.448 20.081 86.904 ;
     RECT  18.904 106.848 20.401 112.248 ;
     RECT  20.081 75.216 20.483 86.904 ;
     RECT  20.081 26.448 20.513 74.04 ;
     RECT  20.401 106.848 20.725 112.296 ;
     RECT  19.289 0.048 20.729 2.664 ;
     RECT  18.904 88.08 20.797 88.632 ;
     RECT  18.904 89.76 20.797 90.312 ;
     RECT  18.904 94.848 20.821 95.496 ;
     RECT  18.904 96.576 20.821 96.6 ;
     RECT  20.797 88.08 20.869 90.312 ;
     RECT  19.325 91.44 20.869 91.464 ;
     RECT  20.045 4.8 21.061 25.224 ;
     RECT  20.513 26.448 21.061 63.288 ;
     RECT  20.725 106.272 21.089 112.296 ;
     RECT  18.904 99.408 21.337 100.056 ;
     RECT  19.325 93.216 21.373 93.768 ;
     RECT  20.513 70.272 21.445 74.04 ;
     RECT  21.061 4.8 21.589 63.288 ;
     RECT  20.513 64.32 21.589 68.952 ;
     RECT  20.729 0.096 21.637 2.664 ;
     RECT  21.589 64.32 21.661 69.048 ;
     RECT  21.445 70.272 21.661 74.232 ;
     RECT  20.821 94.848 21.701 96.6 ;
     RECT  21.637 0.096 21.737 2.904 ;
     RECT  18.904 101.712 21.877 101.736 ;
     RECT  21.589 4.272 21.949 63.288 ;
     RECT  21.373 92.688 22.021 93.768 ;
     RECT  21.701 94.848 22.021 95.496 ;
     RECT  21.661 64.32 22.069 74.232 ;
     RECT  20.483 75.264 22.069 86.904 ;
     RECT  21.737 0.144 22.165 2.904 ;
     RECT  21.949 3.984 22.165 63.288 ;
     RECT  22.165 0.144 22.201 63.288 ;
     RECT  22.069 64.32 22.201 86.904 ;
     RECT  21.337 98.88 22.489 100.056 ;
     RECT  22.201 0.144 22.597 86.904 ;
     RECT  20.869 88.08 22.597 91.464 ;
     RECT  22.597 0.144 22.813 91.464 ;
     RECT  22.813 0.048 22.817 91.464 ;
     RECT  18.904 104.016 23.749 104.616 ;
     RECT  22.817 26.592 23.893 91.464 ;
     RECT  22.817 0.048 24.008 25.464 ;
     RECT  23.893 26.544 24.008 91.464 ;
     RECT  22.021 92.688 24.008 95.496 ;
     RECT  21.701 96.576 24.008 96.6 ;
     RECT  22.489 98.352 24.008 100.056 ;
     RECT  21.877 101.712 24.008 101.88 ;
     RECT  23.749 103.488 24.008 104.616 ;
     RECT  21.089 106.272 24.008 112.248 ;
     RECT  24.008 0.048 24.304 112.248 ;
     RECT  24.304 0.048 24.509 25.464 ;
     RECT  24.509 0.096 24.689 25.464 ;
     RECT  24.689 0.144 24.833 25.464 ;
     RECT  24.304 26.544 24.833 26.616 ;
     RECT  24.833 0.144 25.283 23.688 ;
     RECT  24.304 29.904 25.523 91.464 ;
     RECT  24.833 26.592 25.697 26.616 ;
     RECT  25.283 0.144 25.913 21.288 ;
     RECT  25.913 0.144 26.017 17.4 ;
     RECT  25.523 29.904 26.291 89.832 ;
     RECT  26.017 0.096 26.74 17.4 ;
     RECT  24.304 106.272 26.773 112.248 ;
     RECT  24.304 27.6 27.013 28.776 ;
     RECT  26.74 0.048 27.277 17.4 ;
     RECT  25.913 18.48 27.277 21.288 ;
     RECT  26.291 29.904 27.347 89.784 ;
     RECT  24.304 103.488 27.395 104.616 ;
     RECT  24.304 98.352 27.731 100.056 ;
     RECT  27.277 0.048 27.925 21.288 ;
     RECT  25.283 22.464 27.925 23.688 ;
     RECT  27.347 29.904 27.971 86.904 ;
     RECT  27.925 0.048 28.211 23.688 ;
     RECT  24.304 92.688 28.403 95.496 ;
     RECT  28.211 0.048 29.408 20.952 ;
     RECT  28.211 22.464 29.408 23.688 ;
     RECT  24.833 24.72 29.408 25.464 ;
     RECT  27.013 26.64 29.408 28.776 ;
     RECT  27.971 29.904 29.408 29.928 ;
     RECT  27.971 31.104 29.408 86.904 ;
     RECT  27.347 88.08 29.408 89.784 ;
     RECT  25.523 90.864 29.408 91.464 ;
     RECT  28.403 92.688 29.408 92.712 ;
     RECT  28.403 93.744 29.408 95.496 ;
     RECT  24.304 96.576 29.408 96.6 ;
     RECT  27.731 98.88 29.408 100.056 ;
     RECT  24.304 101.712 29.408 101.88 ;
     RECT  27.395 104.016 29.408 104.616 ;
     RECT  26.773 106.272 29.408 112.296 ;
     RECT  29.408 0.048 29.704 112.296 ;
     RECT  29.704 18.432 30.449 20.952 ;
     RECT  29.704 93.744 30.757 95.496 ;
     RECT  29.704 98.88 30.757 100.056 ;
     RECT  29.704 101.712 30.757 101.88 ;
     RECT  29.704 88.08 30.851 89.784 ;
     RECT  30.757 92.64 30.899 95.496 ;
     RECT  30.757 98.496 30.899 100.056 ;
     RECT  30.757 101.712 30.899 102.744 ;
     RECT  29.704 80.64 30.947 86.904 ;
     RECT  30.899 92.64 30.947 92.76 ;
     RECT  30.899 98.592 31.043 100.056 ;
     RECT  30.899 101.712 31.043 102.648 ;
     RECT  31.043 98.88 31.859 100.056 ;
     RECT  29.704 0.048 32.213 17.4 ;
     RECT  32.213 0.096 32.365 17.4 ;
     RECT  32.365 0.192 32.435 17.4 ;
     RECT  29.704 106.272 32.609 112.296 ;
     RECT  29.704 22.464 32.627 23.688 ;
     RECT  32.609 106.272 32.653 112.2 ;
     RECT  30.851 88.608 32.819 89.784 ;
     RECT  32.819 88.608 33.203 88.632 ;
     RECT  30.947 82.416 33.395 86.904 ;
     RECT  29.704 24.72 33.401 25.464 ;
     RECT  29.704 90.864 33.491 91.464 ;
     RECT  32.435 0.384 33.541 17.4 ;
     RECT  32.653 106.272 33.587 111.768 ;
     RECT  33.491 91.44 33.779 91.464 ;
     RECT  33.541 0.096 34.201 17.4 ;
     RECT  33.395 86.88 34.765 86.904 ;
     RECT  33.587 106.272 34.765 111.672 ;
     RECT  34.201 0.336 34.808 17.4 ;
     RECT  30.449 18.48 34.808 20.952 ;
     RECT  32.627 22.464 34.808 23.64 ;
     RECT  33.401 24.768 34.808 25.464 ;
     RECT  29.704 26.64 34.808 28.776 ;
     RECT  29.704 29.904 34.808 29.928 ;
     RECT  29.704 31.104 34.808 79.56 ;
     RECT  30.947 80.64 34.808 81.192 ;
     RECT  33.395 82.416 34.808 85.752 ;
     RECT  34.765 86.88 34.808 87.048 ;
     RECT  32.819 89.76 34.808 89.784 ;
     RECT  30.899 93.744 34.808 95.496 ;
     RECT  29.704 96.576 34.808 96.6 ;
     RECT  31.859 98.88 34.808 100.008 ;
     RECT  31.043 101.712 34.808 101.88 ;
     RECT  29.704 104.016 34.808 104.616 ;
     RECT  34.765 106.272 34.808 112.152 ;
     RECT  34.808 0.336 34.981 112.152 ;
     RECT  34.981 0.336 35.027 112.2 ;
     RECT  35.027 1.92 35.104 112.2 ;
     RECT  35.027 0.336 35.173 0.888 ;
     RECT  35.104 22.464 35.219 23.16 ;
     RECT  35.104 80.64 35.219 81.192 ;
     RECT  35.104 1.92 35.363 17.4 ;
     RECT  35.104 101.712 35.411 101.88 ;
     RECT  35.104 82.416 35.507 84.12 ;
     RECT  35.104 106.848 35.821 112.2 ;
     RECT  35.507 82.944 35.849 84.12 ;
     RECT  35.173 0.192 35.941 0.888 ;
     RECT  35.219 22.464 35.957 23.064 ;
     RECT  35.104 94.32 35.987 94.344 ;
     RECT  35.104 89.76 36.083 89.784 ;
     RECT  35.941 0.096 36.209 0.888 ;
     RECT  35.104 85.728 36.275 85.752 ;
     RECT  36.209 0.432 36.325 0.888 ;
     RECT  35.363 2.208 36.325 17.4 ;
     RECT  35.104 98.88 36.563 100.008 ;
     RECT  35.104 95.472 36.709 95.496 ;
     RECT  35.104 96.576 36.709 96.6 ;
     RECT  35.821 106.848 36.817 112.152 ;
     RECT  35.849 82.944 36.947 83.592 ;
     RECT  36.325 0.432 37.189 17.4 ;
     RECT  36.709 95.472 37.235 96.6 ;
     RECT  37.189 0.096 37.253 17.4 ;
     RECT  37.253 0.096 37.325 9.096 ;
     RECT  37.325 2.208 37.331 9.096 ;
     RECT  35.104 31.632 37.331 79.56 ;
     RECT  35.104 87.024 37.427 87.048 ;
     RECT  37.325 0.096 37.505 1.176 ;
     RECT  37.505 0.192 37.541 1.176 ;
     RECT  36.817 106.848 37.541 112.248 ;
     RECT  36.563 99.456 37.907 100.008 ;
     RECT  37.907 99.984 38.003 100.008 ;
     RECT  37.541 0.432 38.225 1.176 ;
     RECT  37.331 2.304 38.693 9.096 ;
     RECT  38.693 2.352 38.833 9.096 ;
     RECT  37.253 10.128 38.833 17.4 ;
     RECT  38.833 2.352 38.945 17.4 ;
     RECT  35.104 25.44 39.445 25.464 ;
     RECT  35.957 22.464 39.589 22.488 ;
     RECT  38.225 0.432 39.925 0.888 ;
     RECT  39.925 0.192 40.057 0.888 ;
     RECT  38.945 2.544 40.208 9.096 ;
     RECT  38.945 10.128 40.208 17.4 ;
     RECT  35.104 18.48 40.208 20.952 ;
     RECT  39.589 22.464 40.208 23.352 ;
     RECT  39.445 25.008 40.208 25.464 ;
     RECT  35.104 26.64 40.208 27.624 ;
     RECT  35.104 28.752 40.208 28.776 ;
     RECT  35.104 29.904 40.208 29.928 ;
     RECT  37.331 31.632 40.208 78.936 ;
     RECT  35.219 81.168 40.208 81.192 ;
     RECT  36.947 82.944 40.208 82.968 ;
     RECT  37.235 95.472 40.208 95.496 ;
     RECT  37.235 96.576 40.208 96.6 ;
     RECT  35.411 101.712 40.208 101.736 ;
     RECT  35.104 104.592 40.208 104.616 ;
     RECT  37.541 106.848 40.208 108.168 ;
     RECT  37.541 109.152 40.208 112.248 ;
     RECT  40.208 2.148 40.312 112.248 ;
     RECT  40.312 2.418 40.504 112.248 ;
     RECT  40.504 13.44 40.691 17.4 ;
     RECT  40.504 22.464 41.171 23.352 ;
     RECT  40.504 106.848 41.357 107.016 ;
     RECT  40.504 25.008 41.555 25.464 ;
     RECT  40.504 30.192 41.651 30.216 ;
     RECT  41.171 22.464 41.747 22.776 ;
     RECT  40.504 26.64 41.789 27.624 ;
     RECT  40.504 95.472 41.857 95.496 ;
     RECT  40.504 18.48 42.323 20.952 ;
     RECT  40.691 15.552 42.419 17.4 ;
     RECT  40.504 2.544 42.515 5.592 ;
     RECT  40.504 10.128 42.611 12.36 ;
     RECT  40.504 109.152 42.653 112.248 ;
     RECT  41.357 106.848 42.757 106.872 ;
     RECT  42.757 106.848 42.797 107.016 ;
     RECT  42.419 15.552 42.803 16.392 ;
     RECT  42.653 109.248 42.803 112.248 ;
     RECT  42.611 10.128 42.851 10.92 ;
     RECT  42.085 6.864 42.899 6.888 ;
     RECT  41.555 25.44 43.091 25.464 ;
     RECT  40.504 81.168 43.091 81.192 ;
     RECT  41.747 22.464 43.187 22.488 ;
     RECT  42.323 18.48 43.283 19.656 ;
     RECT  40.504 96.576 43.283 96.6 ;
     RECT  42.901 89.52 43.477 89.544 ;
     RECT  43.283 18.528 43.571 19.656 ;
     RECT  42.611 12.048 43.763 12.36 ;
     RECT  43.571 19.344 43.859 19.656 ;
     RECT  42.803 16.368 43.955 16.392 ;
     RECT  43.763 12.048 44.051 12.072 ;
     RECT  42.323 20.928 44.147 20.952 ;
     RECT  40.691 13.44 44.339 14.568 ;
     RECT  44.339 13.584 44.435 14.568 ;
     RECT  42.419 17.376 44.531 17.4 ;
     RECT  41.789 27.6 44.627 27.624 ;
     RECT  40.057 0.096 44.629 0.888 ;
     RECT  40.504 82.944 45.385 82.968 ;
     RECT  44.629 0.096 45.493 1.704 ;
     RECT  45.493 0.096 45.608 1.8 ;
     RECT  42.515 3.312 45.608 5.592 ;
     RECT  45.061 6.864 45.608 6.888 ;
     RECT  42.851 10.128 45.608 10.152 ;
     RECT  44.435 14.544 45.608 14.568 ;
     RECT  43.859 19.632 45.608 19.656 ;
     RECT  44.149 22.752 45.608 22.776 ;
     RECT  40.504 28.752 45.608 28.776 ;
     RECT  40.504 31.632 45.608 78.936 ;
     RECT  45.385 82.944 45.608 83.352 ;
     RECT  43.477 89.52 45.608 89.784 ;
     RECT  41.857 95.424 45.608 95.496 ;
     RECT  40.504 101.712 45.608 101.736 ;
     RECT  42.797 106.992 45.608 107.016 ;
     RECT  42.517 108 45.608 108.024 ;
     RECT  42.803 109.248 45.608 109.272 ;
     RECT  42.803 110.256 45.608 112.248 ;
     RECT  45.608 0.096 45.712 112.248 ;
     RECT  45.712 0.096 45.904 32.142 ;
     RECT  45.712 33.312 45.904 112.248 ;
     RECT  45.904 110.352 45.971 112.248 ;
     RECT  45.904 83.328 46.001 83.496 ;
     RECT  45.904 106.992 46.451 107.016 ;
     RECT  45.904 0.096 46.547 1.752 ;
     RECT  45.971 110.832 47.005 112.248 ;
     RECT  45.904 33.312 47.939 78.936 ;
     RECT  45.904 31.632 48.515 32.04 ;
     RECT  45.904 3.312 51.008 5.592 ;
     RECT  45.904 10.128 51.008 10.152 ;
     RECT  45.904 19.632 51.008 19.656 ;
     RECT  48.515 32.016 51.008 32.04 ;
     RECT  47.939 33.552 51.008 78.936 ;
     RECT  46.001 83.472 51.008 83.496 ;
     RECT  45.904 89.76 51.008 89.784 ;
     RECT  45.904 95.424 51.008 95.448 ;
     RECT  45.904 101.712 51.008 101.736 ;
     RECT  45.904 109.248 51.008 109.272 ;
     RECT  47.005 110.832 51.008 112.296 ;
     RECT  51.008 2.148 51.112 32.412 ;
     RECT  51.112 2.418 51.304 32.142 ;
     RECT  51.008 33.552 51.304 112.296 ;
     RECT  46.547 0.096 53.603 0.84 ;
     RECT  51.304 33.552 53.603 78.936 ;
     RECT  51.304 3.312 56.408 5.592 ;
     RECT  51.304 10.128 56.408 10.152 ;
     RECT  51.304 19.632 56.408 19.656 ;
     RECT  51.304 32.016 56.408 32.04 ;
     RECT  53.603 77.52 56.408 78.936 ;
     RECT  51.304 83.472 56.408 83.496 ;
     RECT  51.304 89.76 56.408 89.784 ;
     RECT  51.304 95.424 56.408 95.448 ;
     RECT  51.304 101.712 56.408 101.736 ;
     RECT  51.304 109.248 56.408 109.272 ;
     RECT  51.304 110.832 56.408 112.296 ;
     RECT  56.408 2.148 56.512 32.412 ;
     RECT  56.512 2.418 56.704 32.142 ;
     RECT  56.408 77.52 56.704 112.296 ;
     RECT  56.704 3.312 61.808 5.592 ;
     RECT  56.704 10.128 61.808 10.152 ;
     RECT  56.704 19.632 61.808 19.656 ;
     RECT  56.704 32.016 61.808 32.04 ;
     RECT  56.704 77.52 61.808 78.936 ;
     RECT  56.704 83.472 61.808 83.496 ;
     RECT  56.704 89.76 61.808 89.784 ;
     RECT  56.704 95.424 61.808 95.448 ;
     RECT  56.704 101.712 61.808 101.736 ;
     RECT  56.704 109.248 61.808 109.272 ;
     RECT  56.704 110.832 61.808 112.296 ;
     RECT  61.808 2.148 61.912 32.412 ;
     RECT  61.912 2.418 62.104 32.142 ;
     RECT  61.808 77.52 62.104 112.296 ;
     RECT  62.104 101.712 65.981 101.736 ;
     RECT  62.104 3.312 67.208 5.592 ;
     RECT  62.104 10.128 67.208 10.152 ;
     RECT  62.104 19.632 67.208 19.656 ;
     RECT  62.104 32.016 67.208 32.04 ;
     RECT  62.104 77.52 67.208 78.936 ;
     RECT  62.104 83.472 67.208 83.496 ;
     RECT  62.104 89.76 67.208 89.784 ;
     RECT  62.104 95.424 67.208 95.448 ;
     RECT  62.104 109.248 67.208 109.272 ;
     RECT  62.104 110.832 67.208 112.296 ;
     RECT  67.208 2.148 67.312 32.412 ;
     RECT  67.312 2.418 67.504 32.142 ;
     RECT  67.208 77.52 67.504 112.296 ;
     RECT  67.504 32.016 68.885 32.04 ;
     RECT  68.885 32.016 68.969 32.472 ;
     RECT  68.969 32.016 69.257 32.04 ;
     RECT  67.504 3.312 72.608 5.592 ;
     RECT  67.504 10.128 72.608 10.152 ;
     RECT  67.504 19.632 72.608 19.656 ;
     RECT  67.504 77.52 72.608 78.936 ;
     RECT  67.504 83.472 72.608 83.496 ;
     RECT  67.504 89.76 72.608 89.784 ;
     RECT  67.504 95.424 72.608 95.448 ;
     RECT  67.504 109.248 72.608 109.272 ;
     RECT  67.504 110.832 72.608 112.296 ;
     RECT  72.608 2.148 72.712 32.412 ;
     RECT  72.712 2.418 72.904 32.142 ;
     RECT  72.608 77.52 72.904 112.296 ;
     RECT  72.904 3.312 78.008 5.592 ;
     RECT  72.904 10.128 78.008 10.152 ;
     RECT  72.904 19.632 78.008 19.656 ;
     RECT  72.904 77.52 78.008 78.936 ;
     RECT  72.904 83.472 78.008 83.496 ;
     RECT  72.904 89.76 78.008 89.784 ;
     RECT  72.904 95.424 78.008 95.448 ;
     RECT  72.904 109.248 78.008 109.272 ;
     RECT  72.904 110.832 78.008 112.296 ;
     RECT  78.008 2.148 78.112 32.412 ;
     RECT  78.112 2.418 78.304 32.142 ;
     RECT  78.008 77.52 78.304 112.296 ;
     RECT  78.304 3.312 83.408 5.592 ;
     RECT  78.304 10.128 83.408 10.152 ;
     RECT  78.304 19.632 83.408 19.656 ;
     RECT  78.304 77.52 83.408 78.936 ;
     RECT  78.304 83.472 83.408 83.496 ;
     RECT  78.304 89.76 83.408 89.784 ;
     RECT  78.304 95.424 83.408 95.448 ;
     RECT  78.304 109.248 83.408 109.272 ;
     RECT  78.304 110.832 83.408 112.296 ;
     RECT  83.408 2.148 83.512 32.412 ;
     RECT  83.512 2.418 83.704 32.142 ;
     RECT  83.408 77.52 83.704 112.296 ;
     RECT  83.704 3.312 88.808 5.592 ;
     RECT  83.704 10.128 88.808 10.152 ;
     RECT  83.704 19.632 88.808 19.656 ;
     RECT  83.704 77.52 88.808 78.936 ;
     RECT  83.704 83.472 88.808 83.496 ;
     RECT  83.704 89.76 88.808 89.784 ;
     RECT  83.704 95.424 88.808 95.448 ;
     RECT  83.704 109.248 88.808 109.272 ;
     RECT  83.704 110.832 88.808 112.296 ;
     RECT  88.808 2.148 88.912 32.412 ;
     RECT  88.912 2.418 89.104 32.142 ;
     RECT  88.808 77.52 89.104 112.296 ;
     RECT  53.603 0.528 90.637 0.84 ;
     RECT  90.637 0.432 92.933 0.84 ;
     RECT  89.104 3.312 93.445 5.592 ;
     RECT  92.933 0.096 94.165 0.84 ;
     RECT  93.445 2.88 94.208 5.592 ;
     RECT  89.104 10.128 94.208 10.152 ;
     RECT  89.104 19.632 94.208 19.656 ;
     RECT  89.104 77.52 94.208 78.936 ;
     RECT  89.104 83.472 94.208 83.496 ;
     RECT  89.104 89.76 94.208 89.784 ;
     RECT  89.104 95.424 94.208 95.448 ;
     RECT  89.104 109.248 94.208 109.272 ;
     RECT  89.104 110.832 94.208 112.296 ;
     RECT  94.208 2.148 94.312 32.412 ;
     RECT  94.312 2.148 94.504 32.142 ;
     RECT  94.208 77.52 94.504 112.296 ;
     RECT  94.165 0.096 94.565 1.128 ;
     RECT  94.565 0.144 94.643 1.128 ;
     RECT  94.504 3.312 95.033 5.592 ;
     RECT  94.643 0.432 95.065 1.128 ;
     RECT  95.065 0.432 95.411 1.752 ;
     RECT  95.033 4.128 95.507 5.592 ;
     RECT  94.504 10.128 95.699 10.152 ;
     RECT  95.411 0.432 95.749 0.84 ;
     RECT  95.749 0.096 95.833 0.84 ;
     RECT  94.504 19.632 95.891 19.656 ;
     RECT  95.507 4.128 99.608 5.496 ;
     RECT  94.504 77.52 99.608 78.936 ;
     RECT  94.504 83.472 99.608 83.496 ;
     RECT  94.504 89.76 99.608 89.784 ;
     RECT  94.504 95.424 99.608 95.448 ;
     RECT  94.504 109.248 99.608 109.272 ;
     RECT  94.504 110.832 99.608 112.296 ;
     RECT  99.608 2.148 99.712 32.412 ;
     RECT  99.712 2.418 99.904 32.142 ;
     RECT  99.608 77.52 99.904 112.296 ;
     RECT  99.904 109.248 102.035 109.272 ;
     RECT  99.904 4.128 105.008 5.496 ;
     RECT  99.904 77.52 105.008 78.936 ;
     RECT  99.904 83.472 105.008 83.496 ;
     RECT  99.904 89.76 105.008 89.784 ;
     RECT  99.904 95.424 105.008 95.448 ;
     RECT  99.904 110.832 105.008 112.296 ;
     RECT  105.008 2.148 105.112 32.412 ;
     RECT  105.112 2.418 105.304 32.142 ;
     RECT  105.008 77.52 105.304 112.296 ;
     RECT  105.304 4.128 110.408 5.496 ;
     RECT  105.304 77.52 110.408 78.936 ;
     RECT  105.304 83.472 110.408 83.496 ;
     RECT  105.304 89.76 110.408 89.784 ;
     RECT  105.304 95.424 110.408 95.448 ;
     RECT  105.304 110.832 110.408 112.296 ;
     RECT  110.408 2.148 110.512 32.412 ;
     RECT  110.512 2.418 110.704 32.142 ;
     RECT  110.408 77.52 110.704 112.296 ;
     RECT  110.704 83.472 114.577 83.496 ;
     RECT  114.577 83.472 114.617 83.592 ;
     RECT  95.833 0.816 115.189 0.84 ;
     RECT  115.189 0.816 115.621 1.176 ;
     RECT  110.704 77.52 115.669 78.936 ;
     RECT  115.669 76.944 115.769 78.936 ;
     RECT  110.704 4.128 115.808 5.496 ;
     RECT  115.769 77.616 115.808 78.936 ;
     RECT  114.617 83.568 115.808 83.592 ;
     RECT  110.704 89.76 115.808 89.784 ;
     RECT  110.704 95.424 115.808 95.448 ;
     RECT  110.704 110.832 115.808 112.296 ;
     RECT  115.808 2.148 115.912 32.412 ;
     RECT  115.621 0.096 116.051 1.176 ;
     RECT  115.912 2.148 116.104 32.142 ;
     RECT  115.808 77.616 116.104 112.296 ;
     RECT  116.051 0.192 116.147 1.176 ;
     RECT  116.147 0.576 116.485 1.176 ;
     RECT  116.104 2.148 116.485 2.904 ;
     RECT  116.485 0.576 117.316 2.904 ;
     RECT  116.104 110.832 117.491 112.296 ;
     RECT  117.491 111.408 117.587 112.296 ;
     RECT  117.457 32.4 117.601 32.424 ;
     RECT  116.104 95.424 117.683 95.448 ;
     RECT  116.104 83.568 117.779 83.592 ;
     RECT  116.104 77.616 117.827 77.88 ;
     RECT  53.603 33.552 117.875 75.768 ;
     RECT  116.104 89.76 117.875 89.784 ;
     RECT  117.827 77.808 117.923 77.88 ;
     RECT  117.587 112.176 117.965 112.296 ;
     RECT  117.601 32.352 117.971 32.424 ;
     RECT  117.875 33.552 118.001 75 ;
     RECT  116.104 107.76 118.067 107.784 ;
     RECT  117.971 32.352 118.115 32.376 ;
     RECT  117.673 100.896 118.163 100.92 ;
     RECT  117.097 99.744 118.259 99.768 ;
     RECT  117.316 0.576 118.289 2.952 ;
     RECT  118.289 0.816 118.541 2.952 ;
     RECT  118.001 73.632 118.885 75 ;
     RECT  118.853 23.376 118.937 23.4 ;
     RECT  118.541 0.816 119.045 2.904 ;
     RECT  117.965 112.176 119.077 112.2 ;
     RECT  118.001 53.088 119.153 59.352 ;
     RECT  118.001 60.384 119.153 72.408 ;
     RECT  119.153 60.384 119.189 64.248 ;
     RECT  119.077 112.128 119.365 112.2 ;
     RECT  118.885 73.632 119.441 75.816 ;
     RECT  119.153 53.088 119.461 55.32 ;
     RECT  119.365 111.696 119.557 112.2 ;
     RECT  118.001 33.552 119.693 51.96 ;
     RECT  119.461 53.04 119.693 55.32 ;
     RECT  119.153 56.448 119.693 59.352 ;
     RECT  119.189 60.384 119.693 64.056 ;
     RECT  119.153 65.28 119.693 72.408 ;
     RECT  119.693 53.04 119.726 54.744 ;
     RECT  119.693 65.28 119.729 72.312 ;
     RECT  119.045 0.816 119.749 2.808 ;
     RECT  119.749 0.096 119.909 2.808 ;
     RECT  119.693 51.84 119.981 51.864 ;
     RECT  119.693 62.016 119.981 63.96 ;
     RECT  119.729 68.64 119.981 70.488 ;
     RECT  119.981 63.456 120.017 63.96 ;
     RECT  119.729 65.952 120.017 67.416 ;
     RECT  119.729 72 120.017 72.312 ;
     RECT  119.909 2.544 120.053 2.808 ;
     RECT  119.726 53.04 120.053 54.264 ;
     RECT  120.017 66.048 120.053 67.416 ;
     RECT  119.693 56.736 120.089 59.352 ;
     RECT  120.053 66.048 120.089 67.128 ;
     RECT  119.441 73.632 120.089 75.096 ;
     RECT  120.053 2.592 120.161 2.808 ;
     RECT  119.693 48.864 120.161 50.712 ;
     RECT  120.089 73.632 120.161 73.848 ;
     RECT  120.053 53.04 120.197 53.544 ;
     RECT  120.089 56.736 120.197 57.624 ;
     RECT  120.089 66.048 120.197 67.032 ;
     RECT  119.981 68.64 120.197 70.104 ;
     RECT  120.161 48.864 120.233 49.08 ;
     RECT  120.161 50.112 120.233 50.136 ;
     RECT  120.017 72 120.233 72.024 ;
     RECT  120.161 73.632 120.233 73.752 ;
     RECT  120.197 53.52 121.093 53.544 ;
     RECT  120.161 2.784 121.208 2.808 ;
     RECT  116.104 4.128 121.208 5.496 ;
     RECT  120.188 28.464 121.208 28.488 ;
     RECT  119.845 32.496 121.208 32.52 ;
     RECT  119.693 33.552 121.208 47.352 ;
     RECT  120.233 49.056 121.208 49.08 ;
     RECT  121.093 53.52 121.208 53.592 ;
     RECT  120.197 56.928 121.208 57.624 ;
     RECT  119.693 60.384 121.208 60.888 ;
     RECT  119.981 62.16 121.208 62.184 ;
     RECT  120.017 63.936 121.208 63.96 ;
     RECT  120.197 67.008 121.208 67.032 ;
     RECT  120.197 68.64 121.208 69.528 ;
     RECT  120.233 73.632 121.208 73.656 ;
     RECT  120.089 74.832 121.208 75.096 ;
     RECT  117.923 77.856 121.208 77.88 ;
     RECT  119.557 111.12 121.208 112.2 ;
     RECT  121.208 2.148 121.312 112.2 ;
     RECT  121.312 2.418 121.504 109.902 ;
     RECT  121.504 33.552 121.709 46.584 ;
     RECT  121.504 4.128 121.811 5.496 ;
     RECT  121.811 4.656 121.907 5.496 ;
     RECT  121.907 5.472 122.003 5.496 ;
     RECT  121.709 33.552 122.033 46.488 ;
     RECT  121.504 58.944 122.147 59.64 ;
     RECT  119.909 0.096 122.177 1.176 ;
     RECT  122.033 33.552 122.195 46.056 ;
     RECT  122.195 37.392 122.243 46.056 ;
     RECT  121.312 111.024 122.249 112.2 ;
     RECT  122.243 37.392 122.321 44.088 ;
     RECT  122.249 111.216 122.483 112.2 ;
     RECT  122.533 49.872 122.617 49.896 ;
     RECT  121.504 53.28 122.627 54.168 ;
     RECT  122.177 1.104 122.645 1.176 ;
     RECT  122.533 55.824 122.675 55.848 ;
     RECT  122.243 45.36 122.753 46.056 ;
     RECT  122.321 37.392 122.825 43.896 ;
     RECT  122.195 33.552 122.867 36.12 ;
     RECT  122.627 53.28 122.929 53.304 ;
     RECT  122.753 45.36 123.005 45.432 ;
     RECT  122.929 52.992 123.013 53.304 ;
     RECT  122.483 111.6 123.059 112.2 ;
     RECT  123.005 45.36 123.077 45.384 ;
     RECT  123.068 6.24 123.155 6.264 ;
     RECT  122.177 0.096 123.293 0.12 ;
     RECT  122.867 33.552 123.469 35.064 ;
     RECT  123.5 47.184 123.587 47.208 ;
     RECT  123.059 111.696 123.628 112.2 ;
     RECT  123.469 33.024 123.635 35.064 ;
     RECT  122.893 29.04 123.829 29.064 ;
     RECT  123.829 29.04 124.019 29.64 ;
     RECT  124.019 29.04 124.115 29.592 ;
     RECT  122.645 1.104 124.153 1.128 ;
     RECT  122.825 37.392 124.441 43.848 ;
     RECT  124.261 3.936 124.595 3.96 ;
     RECT  124.115 29.04 124.657 29.064 ;
     RECT  124.613 45.552 124.697 45.576 ;
     RECT  124.729 46.752 124.748 46.776 ;
     RECT  124.153 0.528 124.765 1.128 ;
     RECT  124.657 28.752 124.883 29.064 ;
     RECT  124.748 46.08 124.957 46.776 ;
     RECT  122.147 58.944 124.979 58.968 ;
     RECT  124.441 37.392 124.993 43.944 ;
     RECT  124.993 37.392 125.021 43.416 ;
     RECT  123.635 33.552 125.053 35.064 ;
     RECT  122.867 36.096 125.053 36.12 ;
     RECT  124.117 47.904 125.075 47.928 ;
     RECT  123.628 111.744 125.125 112.2 ;
     RECT  125.021 37.392 125.161 43.32 ;
     RECT  123.013 53.28 125.171 53.304 ;
     RECT  124.765 0.432 125.405 1.128 ;
     RECT  125.161 37.104 125.453 43.32 ;
     RECT  125.453 37.104 125.459 40.584 ;
     RECT  125.405 0.096 125.489 1.128 ;
     RECT  125.453 41.568 125.497 43.32 ;
     RECT  125.497 42.336 125.507 43.32 ;
     RECT  125.053 33.552 125.521 36.12 ;
     RECT  125.459 37.104 125.521 39.912 ;
     RECT  125.489 0.432 126.131 1.128 ;
     RECT  125.507 42.48 126.277 43.32 ;
     RECT  125.125 111.168 126.419 112.2 ;
     RECT  126.205 1.632 126.493 1.704 ;
     RECT  126.277 42.48 126.529 43.656 ;
     RECT  126.493 1.632 126.608 2.04 ;
     RECT  125.629 27.312 126.608 27.336 ;
     RECT  124.883 28.752 126.608 28.776 ;
     RECT  125.521 33.552 126.608 39.912 ;
     RECT  126.529 42.192 126.608 43.896 ;
     RECT  124.957 46.752 126.608 46.776 ;
     RECT  125.197 53.04 126.608 53.064 ;
     RECT  126.131 0.432 126.661 0.504 ;
     RECT  126.608 1.632 126.904 110.172 ;
     RECT  126.904 1.632 126.995 1.656 ;
     RECT  126.949 110.256 127.037 110.28 ;
     RECT  126.661 0.144 127.043 0.504 ;
     RECT  126.904 33.552 127.043 40.584 ;
     RECT  127.043 0.432 127.1 0.504 ;
     RECT  127.1 0.432 127.187 0.552 ;
     RECT  127.043 37.392 127.333 40.584 ;
     RECT  127.333 38.976 127.577 40.584 ;
     RECT  127.187 0.432 127.667 0.456 ;
     RECT  127.577 38.976 127.721 39.912 ;
     RECT  127.043 33.552 127.859 36.12 ;
     RECT  126.904 41.616 127.873 44.472 ;
     RECT  126.904 28.752 127.955 28.776 ;
     RECT  127.721 39.216 128.009 39.912 ;
     RECT  127.859 33.552 128.051 34.488 ;
     RECT  128.009 39.312 128.147 39.912 ;
     RECT  127.873 41.616 128.147 43.656 ;
     RECT  128.147 41.664 128.243 43.656 ;
     RECT  126.419 111.744 128.245 112.2 ;
     RECT  128.243 42.192 128.291 43.656 ;
     RECT  128.245 111.696 128.293 112.2 ;
     RECT  128.147 39.312 128.339 39.864 ;
     RECT  128.291 42.768 128.531 43.656 ;
     RECT  128.531 42.768 128.627 42.792 ;
     RECT  126.904 46.752 128.723 46.824 ;
     RECT  128.293 111.6 128.819 112.2 ;
     RECT  128.723 46.752 128.915 46.776 ;
     RECT  128.339 39.792 129.061 39.864 ;
     RECT  129.061 39.84 129.301 39.864 ;
     RECT  129.409 40.992 129.493 41.016 ;
     RECT  129.301 39.84 129.517 39.912 ;
     RECT  129.517 39.84 129.521 40.44 ;
     RECT  129.521 40.416 129.601 40.44 ;
     RECT  128.819 111.648 129.875 112.2 ;
     RECT  129.949 41.568 130.033 41.592 ;
     RECT  129.875 111.744 130.355 112.2 ;
     RECT  130.355 112.176 130.457 112.2 ;
     RECT  127.333 37.392 130.961 37.608 ;
     RECT  128.051 33.552 132.008 34.152 ;
     RECT  127.859 36.096 132.008 36.12 ;
     RECT  130.961 37.392 132.008 37.464 ;
     RECT  132.008 2.148 132.112 110.172 ;
     RECT  132.112 2.418 132.304 109.902 ;
     RECT  132.304 37.392 132.509 37.464 ;
     RECT  132.304 36.096 133.369 36.12 ;
     RECT  132.509 37.392 133.369 37.416 ;
     RECT  133.369 36.096 133.409 37.416 ;
     RECT  132.304 33.552 134.021 34.152 ;
     RECT  133.409 36.096 134.417 37.032 ;
     RECT  134.417 36.096 134.561 36.6 ;
     RECT  134.561 36.528 135.281 36.6 ;
     RECT  135.281 36.576 135.821 36.6 ;
     RECT  134.021 33.6 137.408 34.152 ;
     RECT  137.408 2.148 137.512 110.172 ;
     RECT  137.512 2.418 137.704 109.902 ;
     RECT  139.057 37.2 139.597 37.224 ;
     RECT  139.597 36.72 140.281 37.32 ;
     RECT  137.704 33.6 140.285 34.152 ;
     RECT  140.285 33.6 140.357 33.768 ;
     RECT  140.281 36.624 140.364 37.32 ;
     RECT  140.357 33.6 140.393 33.624 ;
     RECT  140.364 36.624 140.393 36.648 ;
    LAYER M5 ;
     RECT  115.92 0.016 128.136 0.085 ;
     RECT  0.72 0.016 46.536 0.131 ;
     RECT  0.816 0.131 46.536 0.181 ;
     RECT  92.88 0.016 95.88 0.611 ;
     RECT  93.264 0.611 95.88 0.659 ;
     RECT  93.36 0.659 95.88 0.755 ;
     RECT  93.456 0.755 95.88 1.139 ;
     RECT  115.632 0.085 128.136 1.141 ;
     RECT  0.816 0.181 47.352 1.187 ;
     RECT  50.16 0.133 50.184 2.137 ;
     RECT  93.456 1.139 93.48 2.137 ;
     RECT  95.088 1.139 95.88 2.137 ;
     RECT  50.16 2.137 51.12 2.151 ;
     RECT  56.4 2.137 56.52 2.151 ;
     RECT  61.8 2.137 61.92 2.151 ;
     RECT  67.2 2.137 67.32 2.151 ;
     RECT  72.6 2.137 72.72 2.151 ;
     RECT  78 2.137 78.12 2.151 ;
     RECT  83.4 2.137 83.52 2.151 ;
     RECT  88.8 2.137 88.92 2.151 ;
     RECT  99.6 2.137 99.72 2.151 ;
     RECT  105 2.137 105.12 2.151 ;
     RECT  110.4 2.137 110.52 2.151 ;
     RECT  132 2.137 132.12 2.151 ;
     RECT  137.4 2.137 137.52 2.151 ;
     RECT  0.816 1.187 37.32 2.243 ;
     RECT  0.816 2.243 37.032 2.435 ;
     RECT  0.816 2.435 36.84 2.915 ;
     RECT  93.456 2.137 95.88 2.915 ;
     RECT  115.2 1.141 128.136 2.915 ;
     RECT  117.36 2.915 128.136 2.963 ;
     RECT  23.856 2.915 36.84 4.019 ;
     RECT  23.856 4.019 36.072 4.067 ;
     RECT  32.496 4.067 36.072 4.595 ;
     RECT  23.856 4.067 31.32 5.123 ;
     RECT  1.008 2.915 22.824 5.171 ;
     RECT  39.12 1.187 47.352 5.363 ;
     RECT  1.488 5.171 22.824 5.461 ;
     RECT  23.856 5.123 30.168 5.461 ;
     RECT  39.312 5.363 47.352 5.555 ;
     RECT  94.2 2.915 95.88 5.603 ;
     RECT  32.496 4.595 35.208 5.605 ;
     RECT  1.488 5.461 30.168 5.699 ;
     RECT  26.208 5.699 30.168 5.747 ;
     RECT  1.488 5.699 25.176 5.795 ;
     RECT  26.448 5.747 30.072 6.323 ;
     RECT  32.496 5.605 35.352 6.323 ;
     RECT  27.888 6.323 30.072 6.755 ;
     RECT  1.632 5.795 25.176 6.805 ;
     RECT  26.448 6.323 26.472 6.805 ;
     RECT  1.632 6.805 26.472 6.899 ;
     RECT  28.032 6.755 30.072 7.091 ;
     RECT  37.488 6.901 37.512 7.331 ;
     RECT  28.656 7.091 30.072 7.381 ;
     RECT  31.296 5.123 31.32 7.381 ;
     RECT  1.68 6.899 25.656 7.523 ;
     RECT  28.656 7.381 31.32 7.571 ;
     RECT  7.632 7.523 25.656 7.763 ;
     RECT  32.496 6.323 35.208 7.957 ;
     RECT  37.584 7.381 37.608 7.957 ;
     RECT  7.632 7.763 25.272 8.003 ;
     RECT  7.68 8.003 25.272 8.147 ;
     RECT  28.656 7.571 30.696 8.195 ;
     RECT  26.688 7.909 26.712 9.109 ;
     RECT  26.4 9.109 26.712 9.683 ;
     RECT  1.68 7.523 6.648 9.731 ;
     RECT  31.872 7.957 35.208 9.827 ;
     RECT  95.664 5.603 95.88 10.163 ;
     RECT  36.48 9.589 36.504 10.213 ;
     RECT  37.584 7.957 38.184 10.213 ;
     RECT  39.408 5.555 47.352 10.213 ;
     RECT  1.68 9.731 3.288 10.259 ;
     RECT  4.272 9.731 6.648 10.261 ;
     RECT  32.112 9.827 35.208 10.453 ;
     RECT  36.336 10.213 36.504 10.453 ;
     RECT  28.656 8.195 29.712 10.693 ;
     RECT  4.272 10.261 6.744 10.741 ;
     RECT  7.8 8.147 25.272 10.741 ;
     RECT  28.512 10.693 29.712 11.123 ;
     RECT  29.184 11.123 29.712 11.219 ;
     RECT  26.688 9.683 26.712 11.317 ;
     RECT  32.112 10.453 36.504 11.845 ;
     RECT  37.584 10.213 47.352 11.845 ;
     RECT  4.272 10.741 25.272 11.941 ;
     RECT  1.68 10.259 3.192 12.517 ;
     RECT  4.176 11.941 25.272 12.517 ;
     RECT  26.688 11.317 26.856 13.093 ;
     RECT  32.112 11.845 47.352 13.573 ;
     RECT  26.592 13.093 26.856 14.197 ;
     RECT  27.936 11.365 27.96 14.197 ;
     RECT  29.4 11.219 29.712 14.341 ;
     RECT  31.296 13.573 47.352 14.341 ;
     RECT  26.592 14.197 27.96 14.629 ;
     RECT  29.4 14.341 47.352 14.629 ;
     RECT  26.592 14.629 47.352 14.867 ;
     RECT  26.592 14.867 31.32 15.443 ;
     RECT  26.592 15.443 31.272 15.539 ;
     RECT  26.688 15.539 31.272 16.019 ;
     RECT  29.28 16.019 31.272 17.939 ;
     RECT  95.856 10.163 95.88 19.667 ;
     RECT  32.4 14.867 47.352 20.963 ;
     RECT  0.24 20.389 0.264 21.157 ;
     RECT  26.688 16.019 27.96 21.637 ;
     RECT  26.688 21.637 28.2 21.683 ;
     RECT  0.24 21.157 0.36 21.731 ;
     RECT  1.68 12.517 25.272 21.827 ;
     RECT  1.68 21.827 24.696 22.357 ;
     RECT  32.4 20.963 43.176 22.499 ;
     RECT  1.152 22.357 24.696 22.547 ;
     RECT  44.208 20.963 47.352 22.741 ;
     RECT  0.144 22.741 0.168 23.123 ;
     RECT  118.896 2.963 128.136 23.411 ;
     RECT  1.68 22.547 24.696 24.613 ;
     RECT  1.68 24.613 24.744 24.995 ;
     RECT  32.4 22.499 43.08 25.475 ;
     RECT  0.144 24.277 0.168 25.477 ;
     RECT  0.144 25.477 0.264 25.525 ;
     RECT  0.144 25.525 0.552 25.715 ;
     RECT  0.144 25.715 0.264 25.955 ;
     RECT  1.68 24.995 24.696 26.243 ;
     RECT  26.688 21.683 27.048 26.675 ;
     RECT  28.176 21.683 28.2 27.107 ;
     RECT  1.68 26.243 2.712 27.733 ;
     RECT  3.888 26.243 24.696 27.877 ;
     RECT  1.68 27.733 2.808 27.923 ;
     RECT  0.24 25.955 0.264 28.355 ;
     RECT  3.792 27.877 24.696 29.267 ;
     RECT  0.144 29.221 0.168 29.317 ;
     RECT  0.144 29.317 0.216 29.413 ;
     RECT  0.144 29.413 0.264 29.509 ;
     RECT  0.144 29.509 0.312 29.605 ;
     RECT  26.688 26.675 26.712 30.565 ;
     RECT  27.936 30.325 27.96 30.565 ;
     RECT  0.144 29.605 0.36 30.851 ;
     RECT  0.144 30.851 0.264 31.139 ;
     RECT  0.144 31.139 0.216 31.427 ;
     RECT  26.688 30.565 27.96 31.621 ;
     RECT  29.4 17.939 31.272 31.861 ;
     RECT  32.4 25.475 42.888 31.861 ;
     RECT  0.144 31.427 0.168 32.003 ;
     RECT  44.16 22.741 47.352 32.245 ;
     RECT  29.4 31.861 42.888 32.341 ;
     RECT  43.872 32.245 47.352 32.341 ;
     RECT  118.992 23.411 128.136 32.341 ;
     RECT  118.08 32.341 128.136 32.389 ;
     RECT  29.4 32.341 47.352 33.301 ;
     RECT  48.48 31.621 48.504 33.301 ;
     RECT  117.936 32.389 128.136 33.781 ;
     RECT  117.888 33.781 128.136 34.165 ;
     RECT  3.888 29.267 24.696 34.451 ;
     RECT  3.888 34.451 22.776 35.363 ;
     RECT  117.792 34.165 128.136 35.987 ;
     RECT  117.888 35.987 128.136 37.139 ;
     RECT  126.384 37.139 128.136 37.667 ;
     RECT  126.48 37.667 128.136 37.715 ;
     RECT  3.888 35.363 22.728 38.773 ;
     RECT  3.888 38.773 22.824 38.963 ;
     RECT  117.888 37.139 124.968 38.965 ;
     RECT  126.6 37.715 128.136 39.301 ;
     RECT  117.792 38.965 124.968 39.443 ;
     RECT  123.696 39.443 124.968 39.589 ;
     RECT  126.6 39.301 128.328 39.781 ;
     RECT  117.792 39.443 122.472 39.827 ;
     RECT  126.6 39.781 129.048 39.877 ;
     RECT  126.6 39.877 129.336 39.971 ;
     RECT  128.304 39.971 129.336 40.405 ;
     RECT  117.888 39.827 122.472 40.499 ;
     RECT  123.696 39.589 125.448 40.595 ;
     RECT  117.888 40.499 121.512 40.933 ;
     RECT  117.792 40.933 121.512 41.075 ;
     RECT  123.696 40.595 124.968 41.557 ;
     RECT  128.304 40.405 129.576 41.557 ;
     RECT  126.6 39.971 127.32 41.605 ;
     RECT  128.304 41.557 130.008 41.605 ;
     RECT  117.888 41.075 121.512 41.651 ;
     RECT  123.696 41.557 125.448 41.651 ;
     RECT  124.464 41.651 125.448 42.325 ;
     RECT  117.888 41.651 118.728 42.613 ;
     RECT  120.24 41.651 121.512 42.613 ;
     RECT  124.464 42.325 125.496 43.141 ;
     RECT  126.6 41.605 130.008 43.141 ;
     RECT  117.888 42.613 121.512 43.285 ;
     RECT  117.888 43.285 121.608 43.333 ;
     RECT  117.792 43.333 121.608 43.573 ;
     RECT  3.888 38.963 22.68 43.717 ;
     RECT  124.464 43.141 130.008 43.955 ;
     RECT  1.68 27.923 2.712 44.437 ;
     RECT  3.888 43.717 22.728 44.437 ;
     RECT  117.792 43.573 122.232 44.483 ;
     RECT  117.792 44.483 121.992 45.107 ;
     RECT  117.888 45.107 121.992 46.259 ;
     RECT  117.888 46.259 121.752 46.309 ;
     RECT  1.68 44.437 22.728 46.501 ;
     RECT  1.68 46.501 22.824 46.691 ;
     RECT  117.792 46.309 121.752 49.861 ;
     RECT  117.792 49.861 122.568 52.981 ;
     RECT  123.552 47.173 123.576 52.981 ;
     RECT  1.68 46.691 22.728 62.677 ;
     RECT  1.68 62.677 22.776 62.771 ;
     RECT  2.256 62.771 22.776 62.867 ;
     RECT  2.256 62.867 22.728 68.819 ;
     RECT  5.664 68.819 22.728 74.581 ;
     RECT  5.664 74.581 22.776 75.877 ;
     RECT  24 34.451 24.696 75.877 ;
     RECT  26.688 31.621 28.008 76.021 ;
     RECT  29.4 33.301 48.504 76.163 ;
     RECT  25.776 76.021 28.008 76.213 ;
     RECT  29.4 76.163 44.184 76.213 ;
     RECT  25.776 76.213 44.184 76.261 ;
     RECT  5.664 75.877 24.696 76.403 ;
     RECT  25.68 76.261 44.184 76.403 ;
     RECT  45.168 76.163 48.504 76.403 ;
     RECT  25.68 76.403 33.672 76.595 ;
     RECT  34.704 76.403 44.184 76.595 ;
     RECT  53.568 0.085 53.592 76.643 ;
     RECT  45.264 76.403 48.504 76.691 ;
     RECT  26.784 76.595 33.672 76.739 ;
     RECT  50.16 2.151 51.312 76.739 ;
     RECT  25.68 76.595 25.8 76.885 ;
     RECT  33.312 76.739 33.672 76.931 ;
     RECT  34.8 76.595 44.184 77.507 ;
     RECT  102.096 34.069 102.12 77.603 ;
     RECT  117.792 52.981 123.576 77.651 ;
     RECT  38.88 77.507 44.184 77.747 ;
     RECT  34.8 77.507 37.704 77.795 ;
     RECT  68.928 32.437 68.952 77.843 ;
     RECT  117.888 77.651 123.576 77.843 ;
     RECT  69.216 77.845 69.24 77.987 ;
     RECT  33.648 76.931 33.672 77.989 ;
     RECT  34.8 77.795 37.128 78.083 ;
     RECT  38.88 77.747 44.136 78.131 ;
     RECT  115.2 2.915 116.112 78.131 ;
     RECT  38.88 78.131 40.512 78.179 ;
     RECT  45.264 76.691 46.824 78.179 ;
     RECT  42 78.131 44.136 78.227 ;
     RECT  33.36 77.989 33.672 78.515 ;
     RECT  38.88 78.179 38.904 78.707 ;
     RECT  25.584 76.885 25.8 78.949 ;
     RECT  36.144 78.083 37.128 79.525 ;
     RECT  34.8 78.083 35.112 80.629 ;
     RECT  36.144 79.525 37.32 80.629 ;
     RECT  26.784 76.739 31.704 80.773 ;
     RECT  42.432 78.227 44.136 82.933 ;
     RECT  45.264 78.179 46.344 82.933 ;
     RECT  33.648 78.515 33.672 82.981 ;
     RECT  34.8 80.629 37.32 82.981 ;
     RECT  118.416 77.843 123.576 83.557 ;
     RECT  26.784 80.773 31.752 84.037 ;
     RECT  25.392 78.949 25.8 85.381 ;
     RECT  26.784 84.037 32.424 85.381 ;
     RECT  25.392 85.381 32.424 85.765 ;
     RECT  33.648 82.981 37.32 85.765 ;
     RECT  5.664 76.403 24.408 86.533 ;
     RECT  25.392 85.765 37.32 86.533 ;
     RECT  5.664 86.533 37.32 87.013 ;
     RECT  117.744 83.557 123.576 95.413 ;
     RECT  5.664 87.013 37.416 99.445 ;
     RECT  5.664 99.445 37.896 99.973 ;
     RECT  2.256 68.819 4.536 101.989 ;
     RECT  5.664 99.973 37.992 101.989 ;
     RECT  42.432 82.933 46.344 106.981 ;
     RECT  102 77.797 102.024 109.283 ;
     RECT  40.2 78.179 40.512 109.381 ;
     RECT  40.032 109.381 40.512 109.669 ;
     RECT  2.256 101.989 37.992 109.765 ;
     RECT  40.032 109.669 40.968 109.765 ;
     RECT  42.432 106.981 46.44 109.765 ;
     RECT  2.256 109.765 38.664 110.005 ;
     RECT  40.032 109.765 46.44 110.005 ;
     RECT  51 76.739 51.312 110.169 ;
     RECT  56.4 2.151 56.712 110.169 ;
     RECT  61.8 2.151 62.112 110.169 ;
     RECT  67.2 2.151 67.512 110.169 ;
     RECT  72.6 2.151 72.912 110.169 ;
     RECT  78 2.151 78.312 110.169 ;
     RECT  83.4 2.151 83.712 110.169 ;
     RECT  88.8 2.151 89.112 110.169 ;
     RECT  94.2 5.603 94.512 110.169 ;
     RECT  99.6 2.151 99.912 110.169 ;
     RECT  105 2.151 105.312 110.169 ;
     RECT  110.4 2.151 110.712 110.169 ;
     RECT  115.8 78.131 116.112 110.169 ;
     RECT  132 2.151 132.312 110.169 ;
     RECT  137.4 2.151 137.712 110.169 ;
     RECT  51 110.169 51.12 110.183 ;
     RECT  56.4 110.169 56.52 110.183 ;
     RECT  61.8 110.169 61.92 110.183 ;
     RECT  67.2 110.169 67.32 110.183 ;
     RECT  72.6 110.169 72.72 110.183 ;
     RECT  78 110.169 78.12 110.183 ;
     RECT  83.4 110.169 83.52 110.183 ;
     RECT  88.8 110.169 88.92 110.183 ;
     RECT  94.2 110.169 94.32 110.183 ;
     RECT  99.6 110.169 99.72 110.183 ;
     RECT  105 110.169 105.12 110.183 ;
     RECT  110.4 110.169 110.52 110.183 ;
     RECT  115.8 110.169 115.92 110.183 ;
     RECT  132 110.169 132.12 110.183 ;
     RECT  137.4 110.169 137.52 110.183 ;
     RECT  117.648 95.413 123.576 110.821 ;
     RECT  2.256 110.005 46.44 111.155 ;
     RECT  44.976 111.155 46.44 111.733 ;
     RECT  117.456 110.821 123.576 111.733 ;
     RECT  124.56 43.955 130.008 111.733 ;
     RECT  117.456 111.733 130.344 112.165 ;
     RECT  47.904 76.691 48.504 112.211 ;
     RECT  48.48 112.211 48.504 112.259 ;
     RECT  2.256 111.155 43.656 112.272 ;
     RECT  44.976 111.733 46.536 112.272 ;
     RECT  117.456 112.165 130.44 112.272 ;
     RECT  93.48 1.139 95.088 2.137 ;
     RECT  22.824 2.915 23.856 5.461 ;
     RECT  116.112 2.915 117.36 2.963 ;
     RECT  31.32 4.067 32.496 7.571 ;
     RECT  35.208 4.595 35.352 5.605 ;
     RECT  30.168 5.123 31.296 5.747 ;
     RECT  94.512 5.603 95.664 10.163 ;
     RECT  25.176 5.699 26.208 5.747 ;
     RECT  25.176 5.747 26.448 6.805 ;
     RECT  30.072 5.747 31.296 7.381 ;
     RECT  26.472 6.323 27.888 6.755 ;
     RECT  26.472 6.755 28.032 6.899 ;
     RECT  25.656 6.899 28.032 7.091 ;
     RECT  25.656 7.091 26.712 7.763 ;
     RECT  6.648 7.523 7.632 8.003 ;
     RECT  30.696 7.571 32.496 7.957 ;
     RECT  25.272 7.763 26.712 7.909 ;
     RECT  25.272 7.909 26.688 9.109 ;
     RECT  30.696 7.957 31.872 8.195 ;
     RECT  38.184 7.957 39.408 10.213 ;
     RECT  6.648 8.003 7.68 8.147 ;
     RECT  6.648 8.147 7.8 10.261 ;
     RECT  25.272 9.109 26.4 9.683 ;
     RECT  35.208 9.589 36.48 10.213 ;
     RECT  36.504 9.589 37.584 11.845 ;
     RECT  25.272 9.683 26.688 13.093 ;
     RECT  3.288 9.731 4.272 10.259 ;
     RECT  94.512 10.163 95.856 19.667 ;
     RECT  35.208 10.213 36.336 10.453 ;
     RECT  3.192 10.259 4.272 11.941 ;
     RECT  6.744 10.261 7.8 10.741 ;
     RECT  28.512 11.123 29.184 11.219 ;
     RECT  28.512 11.219 29.4 11.365 ;
     RECT  26.856 11.365 27.936 14.197 ;
     RECT  27.96 11.365 29.4 14.629 ;
     RECT  3.192 11.941 4.176 12.517 ;
     RECT  25.272 13.093 26.592 15.539 ;
     RECT  31.32 14.867 32.4 15.443 ;
     RECT  31.272 15.443 32.4 31.861 ;
     RECT  25.272 15.539 26.688 21.827 ;
     RECT  27.96 16.019 29.28 17.939 ;
     RECT  27.96 17.939 29.4 21.637 ;
     RECT  0.264 20.389 1.68 21.157 ;
     RECT  43.176 20.963 44.208 22.499 ;
     RECT  0.36 21.157 1.68 21.731 ;
     RECT  28.2 21.637 29.4 27.107 ;
     RECT  27.048 21.683 28.176 26.675 ;
     RECT  0.24 21.731 1.68 22.357 ;
     RECT  0.24 22.357 1.152 22.547 ;
     RECT  43.08 22.499 44.208 22.741 ;
     RECT  0.24 22.547 1.68 22.741 ;
     RECT  0.168 22.741 1.68 23.123 ;
     RECT  43.08 22.741 44.16 25.475 ;
     RECT  0.144 23.123 1.68 24.277 ;
     RECT  0.168 24.277 1.68 25.477 ;
     RECT  42.888 25.475 44.16 32.245 ;
     RECT  0.264 25.477 1.68 25.525 ;
     RECT  0.552 25.525 1.68 25.715 ;
     RECT  0.264 25.715 1.68 28.355 ;
     RECT  2.712 26.243 3.888 27.733 ;
     RECT  26.712 26.675 28.176 27.107 ;
     RECT  2.808 27.733 3.888 27.877 ;
     RECT  2.808 27.877 3.792 27.923 ;
     RECT  2.712 27.923 3.792 29.267 ;
     RECT  0.24 28.355 1.68 29.221 ;
     RECT  0.168 29.221 1.68 29.317 ;
     RECT  2.712 29.267 3.888 44.437 ;
     RECT  0.216 29.317 1.68 29.413 ;
     RECT  0.264 29.413 1.68 29.509 ;
     RECT  0.312 29.509 1.68 29.605 ;
     RECT  0.36 29.605 1.68 30.851 ;
     RECT  26.712 30.325 27.936 30.565 ;
     RECT  27.96 30.325 29.4 31.621 ;
     RECT  0.264 30.851 1.68 31.139 ;
     RECT  0.216 31.139 1.68 31.427 ;
     RECT  0.168 31.427 1.68 32.003 ;
     RECT  28.008 31.621 29.4 76.213 ;
     RECT  47.352 31.621 48.48 33.301 ;
     RECT  42.888 32.245 43.872 32.341 ;
     RECT  67.512 32.437 68.928 77.843 ;
     RECT  22.776 34.451 24 35.363 ;
     RECT  22.728 35.363 24 38.773 ;
     RECT  124.968 37.139 126.384 37.667 ;
     RECT  124.968 37.667 126.48 37.715 ;
     RECT  22.824 38.773 24 38.963 ;
     RECT  22.68 38.963 24 43.717 ;
     RECT  122.472 39.443 123.696 40.499 ;
     RECT  125.448 39.589 126.6 40.595 ;
     RECT  117.792 39.827 117.888 40.933 ;
     RECT  127.32 39.971 128.304 41.605 ;
     RECT  124.968 40.595 126.6 41.557 ;
     RECT  125.448 41.557 126.6 42.325 ;
     RECT  118.728 41.651 120.24 42.613 ;
     RECT  125.496 42.325 126.6 43.141 ;
     RECT  22.728 43.717 24 46.501 ;
     RECT  117.792 45.107 117.888 46.309 ;
     RECT  22.824 46.501 24 46.691 ;
     RECT  22.728 46.691 24 62.677 ;
     RECT  123.576 47.173 124.56 111.733 ;
     RECT  122.568 49.861 123.552 52.981 ;
     RECT  22.776 62.677 24 62.867 ;
     RECT  22.728 62.867 24 74.581 ;
     RECT  4.536 68.819 5.664 101.989 ;
     RECT  22.776 74.581 24 75.877 ;
     RECT  24.696 76.021 25.776 76.261 ;
     RECT  44.184 76.163 45.168 76.403 ;
     RECT  24.696 76.261 25.68 76.403 ;
     RECT  24.408 76.403 25.68 76.885 ;
     RECT  33.672 76.403 34.704 76.595 ;
     RECT  44.184 76.403 45.264 77.747 ;
     RECT  25.8 76.595 26.784 85.381 ;
     RECT  33.672 76.595 34.8 82.981 ;
     RECT  46.824 76.691 47.904 78.179 ;
     RECT  24.408 76.885 25.584 78.949 ;
     RECT  33.36 76.931 33.648 77.989 ;
     RECT  37.704 77.507 38.88 77.795 ;
     RECT  44.136 77.747 45.264 82.933 ;
     RECT  35.112 78.083 36.144 80.629 ;
     RECT  40.512 78.131 42 78.227 ;
     RECT  38.904 78.179 40.2 78.707 ;
     RECT  24.408 78.949 25.392 86.533 ;
     RECT  32.424 84.037 33.648 85.765 ;
     RECT  46.44 106.981 47.904 111.733 ;
     RECT  40.968 109.669 42.432 109.765 ;
     RECT  38.664 109.765 40.032 110.005 ;
     RECT  43.656 111.155 44.976 112.188 ;
     RECT  46.536 111.733 47.904 112.188 ;
     RECT  43.704 112.188 44.928 112.272 ;
     RECT  46.584 112.188 47.904 112.211 ;
  END
END ot_hbm_svc_static_pc
END LIBRARY
